VERSION 5.8 ;
BUSBITCHARS "[]" ;
DIVIDERCHAR "/" ;
UNITS
    DATABASE MICRONS 1000 ;
END UNITS

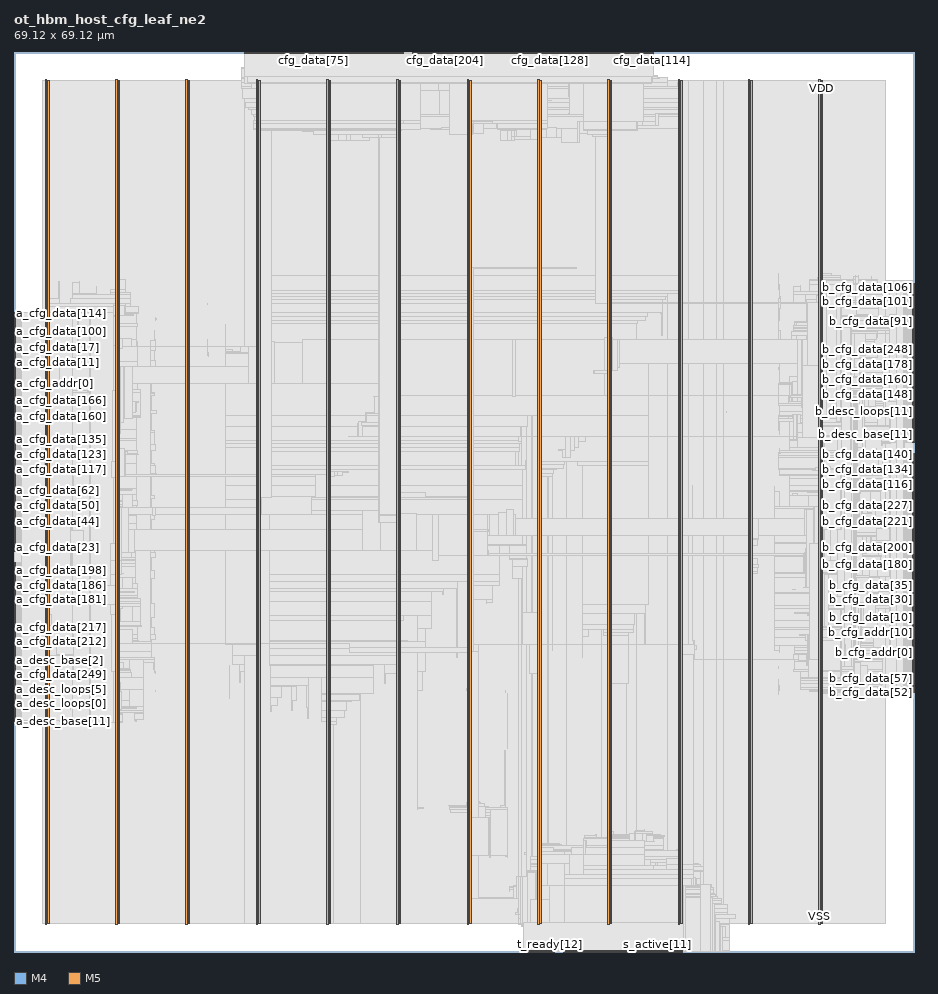
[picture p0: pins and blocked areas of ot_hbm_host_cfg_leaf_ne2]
MACRO ot_hbm_host_cfg_leaf_ne2
  FOREIGN ot_hbm_host_cfg_leaf_ne2 0 0 ;
  CLASS BLOCK ;
  SIZE 69.12 BY 69.12 ;
  PIN a_cfg_addr[0]
    DIRECTION OUTPUT ;
    USE SIGNAL ;
    PORT
      LAYER M4 ;
        RECT  0 43.056 0.084 43.08 ;
    END
  END a_cfg_addr[0]
  PIN a_cfg_addr[10]
    DIRECTION OUTPUT ;
    USE SIGNAL ;
    PORT
      LAYER M4 ;
        RECT  0 44.016 0.084 44.04 ;
    END
  END a_cfg_addr[10]
  PIN a_cfg_addr[11]
    DIRECTION OUTPUT ;
    USE SIGNAL ;
    PORT
      LAYER M4 ;
        RECT  0 44.112 0.084 44.136 ;
    END
  END a_cfg_addr[11]
  PIN a_cfg_addr[1]
    DIRECTION OUTPUT ;
    USE SIGNAL ;
    PORT
      LAYER M4 ;
        RECT  0 43.152 0.084 43.176 ;
    END
  END a_cfg_addr[1]
  PIN a_cfg_addr[2]
    DIRECTION OUTPUT ;
    USE SIGNAL ;
    PORT
      LAYER M4 ;
        RECT  0 43.248 0.084 43.272 ;
    END
  END a_cfg_addr[2]
  PIN a_cfg_addr[3]
    DIRECTION OUTPUT ;
    USE SIGNAL ;
    PORT
      LAYER M4 ;
        RECT  0 43.344 0.084 43.368 ;
    END
  END a_cfg_addr[3]
  PIN a_cfg_addr[4]
    DIRECTION OUTPUT ;
    USE SIGNAL ;
    PORT
      LAYER M4 ;
        RECT  0 43.44 0.084 43.464 ;
    END
  END a_cfg_addr[4]
  PIN a_cfg_addr[5]
    DIRECTION OUTPUT ;
    USE SIGNAL ;
    PORT
      LAYER M4 ;
        RECT  0 43.536 0.084 43.56 ;
    END
  END a_cfg_addr[5]
  PIN a_cfg_addr[6]
    DIRECTION OUTPUT ;
    USE SIGNAL ;
    PORT
      LAYER M4 ;
        RECT  0 43.632 0.084 43.656 ;
    END
  END a_cfg_addr[6]
  PIN a_cfg_addr[7]
    DIRECTION OUTPUT ;
    USE SIGNAL ;
    PORT
      LAYER M4 ;
        RECT  0 43.728 0.084 43.752 ;
    END
  END a_cfg_addr[7]
  PIN a_cfg_addr[8]
    DIRECTION OUTPUT ;
    USE SIGNAL ;
    PORT
      LAYER M4 ;
        RECT  0 43.824 0.084 43.848 ;
    END
  END a_cfg_addr[8]
  PIN a_cfg_addr[9]
    DIRECTION OUTPUT ;
    USE SIGNAL ;
    PORT
      LAYER M4 ;
        RECT  0 43.92 0.084 43.944 ;
    END
  END a_cfg_addr[9]
  PIN a_cfg_data[0]
    DIRECTION OUTPUT ;
    USE SIGNAL ;
    PORT
      LAYER M4 ;
        RECT  0 44.208 0.084 44.232 ;
    END
  END a_cfg_data[0]
  PIN a_cfg_data[100]
    DIRECTION OUTPUT ;
    USE SIGNAL ;
    PORT
      LAYER M4 ;
        RECT  0 47.664 0.084 47.688 ;
    END
  END a_cfg_data[100]
  PIN a_cfg_data[101]
    DIRECTION OUTPUT ;
    USE SIGNAL ;
    PORT
      LAYER M4 ;
        RECT  0 47.76 0.084 47.784 ;
    END
  END a_cfg_data[101]
  PIN a_cfg_data[102]
    DIRECTION OUTPUT ;
    USE SIGNAL ;
    PORT
      LAYER M4 ;
        RECT  0 47.856 0.084 47.88 ;
    END
  END a_cfg_data[102]
  PIN a_cfg_data[103]
    DIRECTION OUTPUT ;
    USE SIGNAL ;
    PORT
      LAYER M4 ;
        RECT  0 47.952 0.084 47.976 ;
    END
  END a_cfg_data[103]
  PIN a_cfg_data[104]
    DIRECTION OUTPUT ;
    USE SIGNAL ;
    PORT
      LAYER M4 ;
        RECT  0 48.048 0.084 48.072 ;
    END
  END a_cfg_data[104]
  PIN a_cfg_data[105]
    DIRECTION OUTPUT ;
    USE SIGNAL ;
    PORT
      LAYER M4 ;
        RECT  0 48.144 0.084 48.168 ;
    END
  END a_cfg_data[105]
  PIN a_cfg_data[106]
    DIRECTION OUTPUT ;
    USE SIGNAL ;
    PORT
      LAYER M4 ;
        RECT  0 48.24 0.084 48.264 ;
    END
  END a_cfg_data[106]
  PIN a_cfg_data[107]
    DIRECTION OUTPUT ;
    USE SIGNAL ;
    PORT
      LAYER M4 ;
        RECT  0 48.336 0.084 48.36 ;
    END
  END a_cfg_data[107]
  PIN a_cfg_data[108]
    DIRECTION OUTPUT ;
    USE SIGNAL ;
    PORT
      LAYER M4 ;
        RECT  0 48.432 0.084 48.456 ;
    END
  END a_cfg_data[108]
  PIN a_cfg_data[109]
    DIRECTION OUTPUT ;
    USE SIGNAL ;
    PORT
      LAYER M4 ;
        RECT  0 48.528 0.084 48.552 ;
    END
  END a_cfg_data[109]
  PIN a_cfg_data[10]
    DIRECTION OUTPUT ;
    USE SIGNAL ;
    PORT
      LAYER M4 ;
        RECT  0 45.168 0.084 45.192 ;
    END
  END a_cfg_data[10]
  PIN a_cfg_data[110]
    DIRECTION OUTPUT ;
    USE SIGNAL ;
    PORT
      LAYER M4 ;
        RECT  0 48.624 0.084 48.648 ;
    END
  END a_cfg_data[110]
  PIN a_cfg_data[111]
    DIRECTION OUTPUT ;
    USE SIGNAL ;
    PORT
      LAYER M4 ;
        RECT  0 48.72 0.084 48.744 ;
    END
  END a_cfg_data[111]
  PIN a_cfg_data[112]
    DIRECTION OUTPUT ;
    USE SIGNAL ;
    PORT
      LAYER M4 ;
        RECT  0 48.816 0.084 48.84 ;
    END
  END a_cfg_data[112]
  PIN a_cfg_data[113]
    DIRECTION OUTPUT ;
    USE SIGNAL ;
    PORT
      LAYER M4 ;
        RECT  0 48.912 0.084 48.936 ;
    END
  END a_cfg_data[113]
  PIN a_cfg_data[114]
    DIRECTION OUTPUT ;
    USE SIGNAL ;
    PORT
      LAYER M4 ;
        RECT  0 49.008 0.084 49.032 ;
    END
  END a_cfg_data[114]
  PIN a_cfg_data[115]
    DIRECTION OUTPUT ;
    USE SIGNAL ;
    PORT
      LAYER M4 ;
        RECT  0 49.104 0.084 49.128 ;
    END
  END a_cfg_data[115]
  PIN a_cfg_data[116]
    DIRECTION OUTPUT ;
    USE SIGNAL ;
    PORT
      LAYER M4 ;
        RECT  0 36.912 0.084 36.936 ;
    END
  END a_cfg_data[116]
  PIN a_cfg_data[117]
    DIRECTION OUTPUT ;
    USE SIGNAL ;
    PORT
      LAYER M4 ;
        RECT  0 37.008 0.084 37.032 ;
    END
  END a_cfg_data[117]
  PIN a_cfg_data[118]
    DIRECTION OUTPUT ;
    USE SIGNAL ;
    PORT
      LAYER M4 ;
        RECT  0 37.104 0.084 37.128 ;
    END
  END a_cfg_data[118]
  PIN a_cfg_data[119]
    DIRECTION OUTPUT ;
    USE SIGNAL ;
    PORT
      LAYER M4 ;
        RECT  0 37.2 0.084 37.224 ;
    END
  END a_cfg_data[119]
  PIN a_cfg_data[11]
    DIRECTION OUTPUT ;
    USE SIGNAL ;
    PORT
      LAYER M4 ;
        RECT  0 45.264 0.084 45.288 ;
    END
  END a_cfg_data[11]
  PIN a_cfg_data[120]
    DIRECTION OUTPUT ;
    USE SIGNAL ;
    PORT
      LAYER M4 ;
        RECT  0 37.296 0.084 37.32 ;
    END
  END a_cfg_data[120]
  PIN a_cfg_data[121]
    DIRECTION OUTPUT ;
    USE SIGNAL ;
    PORT
      LAYER M4 ;
        RECT  0 37.392 0.084 37.416 ;
    END
  END a_cfg_data[121]
  PIN a_cfg_data[122]
    DIRECTION OUTPUT ;
    USE SIGNAL ;
    PORT
      LAYER M4 ;
        RECT  0 37.488 0.084 37.512 ;
    END
  END a_cfg_data[122]
  PIN a_cfg_data[123]
    DIRECTION OUTPUT ;
    USE SIGNAL ;
    PORT
      LAYER M4 ;
        RECT  0 37.584 0.084 37.608 ;
    END
  END a_cfg_data[123]
  PIN a_cfg_data[124]
    DIRECTION OUTPUT ;
    USE SIGNAL ;
    PORT
      LAYER M4 ;
        RECT  0 37.68 0.084 37.704 ;
    END
  END a_cfg_data[124]
  PIN a_cfg_data[125]
    DIRECTION OUTPUT ;
    USE SIGNAL ;
    PORT
      LAYER M4 ;
        RECT  0 37.776 0.084 37.8 ;
    END
  END a_cfg_data[125]
  PIN a_cfg_data[126]
    DIRECTION OUTPUT ;
    USE SIGNAL ;
    PORT
      LAYER M4 ;
        RECT  0 37.872 0.084 37.896 ;
    END
  END a_cfg_data[126]
  PIN a_cfg_data[127]
    DIRECTION OUTPUT ;
    USE SIGNAL ;
    PORT
      LAYER M4 ;
        RECT  0 37.968 0.084 37.992 ;
    END
  END a_cfg_data[127]
  PIN a_cfg_data[128]
    DIRECTION OUTPUT ;
    USE SIGNAL ;
    PORT
      LAYER M4 ;
        RECT  0 38.064 0.084 38.088 ;
    END
  END a_cfg_data[128]
  PIN a_cfg_data[129]
    DIRECTION OUTPUT ;
    USE SIGNAL ;
    PORT
      LAYER M4 ;
        RECT  0 38.16 0.084 38.184 ;
    END
  END a_cfg_data[129]
  PIN a_cfg_data[12]
    DIRECTION OUTPUT ;
    USE SIGNAL ;
    PORT
      LAYER M4 ;
        RECT  0 45.36 0.084 45.384 ;
    END
  END a_cfg_data[12]
  PIN a_cfg_data[130]
    DIRECTION OUTPUT ;
    USE SIGNAL ;
    PORT
      LAYER M4 ;
        RECT  0 38.256 0.084 38.28 ;
    END
  END a_cfg_data[130]
  PIN a_cfg_data[131]
    DIRECTION OUTPUT ;
    USE SIGNAL ;
    PORT
      LAYER M4 ;
        RECT  0 38.352 0.084 38.376 ;
    END
  END a_cfg_data[131]
  PIN a_cfg_data[132]
    DIRECTION OUTPUT ;
    USE SIGNAL ;
    PORT
      LAYER M4 ;
        RECT  0 38.448 0.084 38.472 ;
    END
  END a_cfg_data[132]
  PIN a_cfg_data[133]
    DIRECTION OUTPUT ;
    USE SIGNAL ;
    PORT
      LAYER M4 ;
        RECT  0 38.544 0.084 38.568 ;
    END
  END a_cfg_data[133]
  PIN a_cfg_data[134]
    DIRECTION OUTPUT ;
    USE SIGNAL ;
    PORT
      LAYER M4 ;
        RECT  0 38.64 0.084 38.664 ;
    END
  END a_cfg_data[134]
  PIN a_cfg_data[135]
    DIRECTION OUTPUT ;
    USE SIGNAL ;
    PORT
      LAYER M4 ;
        RECT  0 38.736 0.084 38.76 ;
    END
  END a_cfg_data[135]
  PIN a_cfg_data[136]
    DIRECTION OUTPUT ;
    USE SIGNAL ;
    PORT
      LAYER M4 ;
        RECT  0 38.832 0.084 38.856 ;
    END
  END a_cfg_data[136]
  PIN a_cfg_data[137]
    DIRECTION OUTPUT ;
    USE SIGNAL ;
    PORT
      LAYER M4 ;
        RECT  0 38.928 0.084 38.952 ;
    END
  END a_cfg_data[137]
  PIN a_cfg_data[138]
    DIRECTION OUTPUT ;
    USE SIGNAL ;
    PORT
      LAYER M4 ;
        RECT  0 39.024 0.084 39.048 ;
    END
  END a_cfg_data[138]
  PIN a_cfg_data[139]
    DIRECTION OUTPUT ;
    USE SIGNAL ;
    PORT
      LAYER M4 ;
        RECT  0 39.12 0.084 39.144 ;
    END
  END a_cfg_data[139]
  PIN a_cfg_data[13]
    DIRECTION OUTPUT ;
    USE SIGNAL ;
    PORT
      LAYER M4 ;
        RECT  0 45.456 0.084 45.48 ;
    END
  END a_cfg_data[13]
  PIN a_cfg_data[140]
    DIRECTION OUTPUT ;
    USE SIGNAL ;
    PORT
      LAYER M4 ;
        RECT  0 39.216 0.084 39.24 ;
    END
  END a_cfg_data[140]
  PIN a_cfg_data[141]
    DIRECTION OUTPUT ;
    USE SIGNAL ;
    PORT
      LAYER M4 ;
        RECT  0 39.312 0.084 39.336 ;
    END
  END a_cfg_data[141]
  PIN a_cfg_data[142]
    DIRECTION OUTPUT ;
    USE SIGNAL ;
    PORT
      LAYER M4 ;
        RECT  0 39.408 0.084 39.432 ;
    END
  END a_cfg_data[142]
  PIN a_cfg_data[143]
    DIRECTION OUTPUT ;
    USE SIGNAL ;
    PORT
      LAYER M4 ;
        RECT  0 39.504 0.084 39.528 ;
    END
  END a_cfg_data[143]
  PIN a_cfg_data[144]
    DIRECTION OUTPUT ;
    USE SIGNAL ;
    PORT
      LAYER M4 ;
        RECT  0 39.6 0.084 39.624 ;
    END
  END a_cfg_data[144]
  PIN a_cfg_data[145]
    DIRECTION OUTPUT ;
    USE SIGNAL ;
    PORT
      LAYER M4 ;
        RECT  0 39.696 0.084 39.72 ;
    END
  END a_cfg_data[145]
  PIN a_cfg_data[146]
    DIRECTION OUTPUT ;
    USE SIGNAL ;
    PORT
      LAYER M4 ;
        RECT  0 39.792 0.084 39.816 ;
    END
  END a_cfg_data[146]
  PIN a_cfg_data[147]
    DIRECTION OUTPUT ;
    USE SIGNAL ;
    PORT
      LAYER M4 ;
        RECT  0 39.888 0.084 39.912 ;
    END
  END a_cfg_data[147]
  PIN a_cfg_data[148]
    DIRECTION OUTPUT ;
    USE SIGNAL ;
    PORT
      LAYER M4 ;
        RECT  0 39.984 0.084 40.008 ;
    END
  END a_cfg_data[148]
  PIN a_cfg_data[149]
    DIRECTION OUTPUT ;
    USE SIGNAL ;
    PORT
      LAYER M4 ;
        RECT  0 40.08 0.084 40.104 ;
    END
  END a_cfg_data[149]
  PIN a_cfg_data[14]
    DIRECTION OUTPUT ;
    USE SIGNAL ;
    PORT
      LAYER M4 ;
        RECT  0 45.552 0.084 45.576 ;
    END
  END a_cfg_data[14]
  PIN a_cfg_data[150]
    DIRECTION OUTPUT ;
    USE SIGNAL ;
    PORT
      LAYER M4 ;
        RECT  0 40.176 0.084 40.2 ;
    END
  END a_cfg_data[150]
  PIN a_cfg_data[151]
    DIRECTION OUTPUT ;
    USE SIGNAL ;
    PORT
      LAYER M4 ;
        RECT  0 40.272 0.084 40.296 ;
    END
  END a_cfg_data[151]
  PIN a_cfg_data[152]
    DIRECTION OUTPUT ;
    USE SIGNAL ;
    PORT
      LAYER M4 ;
        RECT  0 40.368 0.084 40.392 ;
    END
  END a_cfg_data[152]
  PIN a_cfg_data[153]
    DIRECTION OUTPUT ;
    USE SIGNAL ;
    PORT
      LAYER M4 ;
        RECT  0 40.464 0.084 40.488 ;
    END
  END a_cfg_data[153]
  PIN a_cfg_data[154]
    DIRECTION OUTPUT ;
    USE SIGNAL ;
    PORT
      LAYER M4 ;
        RECT  0 40.56 0.084 40.584 ;
    END
  END a_cfg_data[154]
  PIN a_cfg_data[155]
    DIRECTION OUTPUT ;
    USE SIGNAL ;
    PORT
      LAYER M4 ;
        RECT  0 40.656 0.084 40.68 ;
    END
  END a_cfg_data[155]
  PIN a_cfg_data[156]
    DIRECTION OUTPUT ;
    USE SIGNAL ;
    PORT
      LAYER M4 ;
        RECT  0 40.752 0.084 40.776 ;
    END
  END a_cfg_data[156]
  PIN a_cfg_data[157]
    DIRECTION OUTPUT ;
    USE SIGNAL ;
    PORT
      LAYER M4 ;
        RECT  0 40.848 0.084 40.872 ;
    END
  END a_cfg_data[157]
  PIN a_cfg_data[158]
    DIRECTION OUTPUT ;
    USE SIGNAL ;
    PORT
      LAYER M4 ;
        RECT  0 40.944 0.084 40.968 ;
    END
  END a_cfg_data[158]
  PIN a_cfg_data[159]
    DIRECTION OUTPUT ;
    USE SIGNAL ;
    PORT
      LAYER M4 ;
        RECT  0 41.04 0.084 41.064 ;
    END
  END a_cfg_data[159]
  PIN a_cfg_data[15]
    DIRECTION OUTPUT ;
    USE SIGNAL ;
    PORT
      LAYER M4 ;
        RECT  0 45.648 0.084 45.672 ;
    END
  END a_cfg_data[15]
  PIN a_cfg_data[160]
    DIRECTION OUTPUT ;
    USE SIGNAL ;
    PORT
      LAYER M4 ;
        RECT  0 41.136 0.084 41.16 ;
    END
  END a_cfg_data[160]
  PIN a_cfg_data[161]
    DIRECTION OUTPUT ;
    USE SIGNAL ;
    PORT
      LAYER M4 ;
        RECT  0 41.232 0.084 41.256 ;
    END
  END a_cfg_data[161]
  PIN a_cfg_data[162]
    DIRECTION OUTPUT ;
    USE SIGNAL ;
    PORT
      LAYER M4 ;
        RECT  0 41.328 0.084 41.352 ;
    END
  END a_cfg_data[162]
  PIN a_cfg_data[163]
    DIRECTION OUTPUT ;
    USE SIGNAL ;
    PORT
      LAYER M4 ;
        RECT  0 41.424 0.084 41.448 ;
    END
  END a_cfg_data[163]
  PIN a_cfg_data[164]
    DIRECTION OUTPUT ;
    USE SIGNAL ;
    PORT
      LAYER M4 ;
        RECT  0 41.52 0.084 41.544 ;
    END
  END a_cfg_data[164]
  PIN a_cfg_data[165]
    DIRECTION OUTPUT ;
    USE SIGNAL ;
    PORT
      LAYER M4 ;
        RECT  0 41.616 0.084 41.64 ;
    END
  END a_cfg_data[165]
  PIN a_cfg_data[166]
    DIRECTION OUTPUT ;
    USE SIGNAL ;
    PORT
      LAYER M4 ;
        RECT  0 41.712 0.084 41.736 ;
    END
  END a_cfg_data[166]
  PIN a_cfg_data[167]
    DIRECTION OUTPUT ;
    USE SIGNAL ;
    PORT
      LAYER M4 ;
        RECT  0 41.808 0.084 41.832 ;
    END
  END a_cfg_data[167]
  PIN a_cfg_data[168]
    DIRECTION OUTPUT ;
    USE SIGNAL ;
    PORT
      LAYER M4 ;
        RECT  0 41.904 0.084 41.928 ;
    END
  END a_cfg_data[168]
  PIN a_cfg_data[169]
    DIRECTION OUTPUT ;
    USE SIGNAL ;
    PORT
      LAYER M4 ;
        RECT  0 42 0.084 42.024 ;
    END
  END a_cfg_data[169]
  PIN a_cfg_data[16]
    DIRECTION OUTPUT ;
    USE SIGNAL ;
    PORT
      LAYER M4 ;
        RECT  0 45.744 0.084 45.768 ;
    END
  END a_cfg_data[16]
  PIN a_cfg_data[170]
    DIRECTION OUTPUT ;
    USE SIGNAL ;
    PORT
      LAYER M4 ;
        RECT  0 42.096 0.084 42.12 ;
    END
  END a_cfg_data[170]
  PIN a_cfg_data[171]
    DIRECTION OUTPUT ;
    USE SIGNAL ;
    PORT
      LAYER M4 ;
        RECT  0 42.192 0.084 42.216 ;
    END
  END a_cfg_data[171]
  PIN a_cfg_data[172]
    DIRECTION OUTPUT ;
    USE SIGNAL ;
    PORT
      LAYER M4 ;
        RECT  0 42.288 0.084 42.312 ;
    END
  END a_cfg_data[172]
  PIN a_cfg_data[173]
    DIRECTION OUTPUT ;
    USE SIGNAL ;
    PORT
      LAYER M4 ;
        RECT  0 42.384 0.084 42.408 ;
    END
  END a_cfg_data[173]
  PIN a_cfg_data[174]
    DIRECTION OUTPUT ;
    USE SIGNAL ;
    PORT
      LAYER M4 ;
        RECT  0 42.48 0.084 42.504 ;
    END
  END a_cfg_data[174]
  PIN a_cfg_data[175]
    DIRECTION OUTPUT ;
    USE SIGNAL ;
    PORT
      LAYER M4 ;
        RECT  0 42.576 0.084 42.6 ;
    END
  END a_cfg_data[175]
  PIN a_cfg_data[176]
    DIRECTION OUTPUT ;
    USE SIGNAL ;
    PORT
      LAYER M4 ;
        RECT  0 42.672 0.084 42.696 ;
    END
  END a_cfg_data[176]
  PIN a_cfg_data[177]
    DIRECTION OUTPUT ;
    USE SIGNAL ;
    PORT
      LAYER M4 ;
        RECT  0 42.768 0.084 42.792 ;
    END
  END a_cfg_data[177]
  PIN a_cfg_data[178]
    DIRECTION OUTPUT ;
    USE SIGNAL ;
    PORT
      LAYER M4 ;
        RECT  0 42.864 0.084 42.888 ;
    END
  END a_cfg_data[178]
  PIN a_cfg_data[179]
    DIRECTION OUTPUT ;
    USE SIGNAL ;
    PORT
      LAYER M4 ;
        RECT  0 42.96 0.084 42.984 ;
    END
  END a_cfg_data[179]
  PIN a_cfg_data[17]
    DIRECTION OUTPUT ;
    USE SIGNAL ;
    PORT
      LAYER M4 ;
        RECT  0 45.84 0.084 45.864 ;
    END
  END a_cfg_data[17]
  PIN a_cfg_data[180]
    DIRECTION OUTPUT ;
    USE SIGNAL ;
    PORT
      LAYER M4 ;
        RECT  0 26.928 0.084 26.952 ;
    END
  END a_cfg_data[180]
  PIN a_cfg_data[181]
    DIRECTION OUTPUT ;
    USE SIGNAL ;
    PORT
      LAYER M4 ;
        RECT  0 27.024 0.084 27.048 ;
    END
  END a_cfg_data[181]
  PIN a_cfg_data[182]
    DIRECTION OUTPUT ;
    USE SIGNAL ;
    PORT
      LAYER M4 ;
        RECT  0 27.12 0.084 27.144 ;
    END
  END a_cfg_data[182]
  PIN a_cfg_data[183]
    DIRECTION OUTPUT ;
    USE SIGNAL ;
    PORT
      LAYER M4 ;
        RECT  0 27.216 0.084 27.24 ;
    END
  END a_cfg_data[183]
  PIN a_cfg_data[184]
    DIRECTION OUTPUT ;
    USE SIGNAL ;
    PORT
      LAYER M4 ;
        RECT  0 27.312 0.084 27.336 ;
    END
  END a_cfg_data[184]
  PIN a_cfg_data[185]
    DIRECTION OUTPUT ;
    USE SIGNAL ;
    PORT
      LAYER M4 ;
        RECT  0 27.408 0.084 27.432 ;
    END
  END a_cfg_data[185]
  PIN a_cfg_data[186]
    DIRECTION OUTPUT ;
    USE SIGNAL ;
    PORT
      LAYER M4 ;
        RECT  0 27.504 0.084 27.528 ;
    END
  END a_cfg_data[186]
  PIN a_cfg_data[187]
    DIRECTION OUTPUT ;
    USE SIGNAL ;
    PORT
      LAYER M4 ;
        RECT  0 27.6 0.084 27.624 ;
    END
  END a_cfg_data[187]
  PIN a_cfg_data[188]
    DIRECTION OUTPUT ;
    USE SIGNAL ;
    PORT
      LAYER M4 ;
        RECT  0 27.696 0.084 27.72 ;
    END
  END a_cfg_data[188]
  PIN a_cfg_data[189]
    DIRECTION OUTPUT ;
    USE SIGNAL ;
    PORT
      LAYER M4 ;
        RECT  0 27.792 0.084 27.816 ;
    END
  END a_cfg_data[189]
  PIN a_cfg_data[18]
    DIRECTION OUTPUT ;
    USE SIGNAL ;
    PORT
      LAYER M4 ;
        RECT  0 45.936 0.084 45.96 ;
    END
  END a_cfg_data[18]
  PIN a_cfg_data[190]
    DIRECTION OUTPUT ;
    USE SIGNAL ;
    PORT
      LAYER M4 ;
        RECT  0 27.888 0.084 27.912 ;
    END
  END a_cfg_data[190]
  PIN a_cfg_data[191]
    DIRECTION OUTPUT ;
    USE SIGNAL ;
    PORT
      LAYER M4 ;
        RECT  0 27.984 0.084 28.008 ;
    END
  END a_cfg_data[191]
  PIN a_cfg_data[192]
    DIRECTION OUTPUT ;
    USE SIGNAL ;
    PORT
      LAYER M4 ;
        RECT  0 28.08 0.084 28.104 ;
    END
  END a_cfg_data[192]
  PIN a_cfg_data[193]
    DIRECTION OUTPUT ;
    USE SIGNAL ;
    PORT
      LAYER M4 ;
        RECT  0 28.176 0.084 28.2 ;
    END
  END a_cfg_data[193]
  PIN a_cfg_data[194]
    DIRECTION OUTPUT ;
    USE SIGNAL ;
    PORT
      LAYER M4 ;
        RECT  0 28.272 0.084 28.296 ;
    END
  END a_cfg_data[194]
  PIN a_cfg_data[195]
    DIRECTION OUTPUT ;
    USE SIGNAL ;
    PORT
      LAYER M4 ;
        RECT  0 28.368 0.084 28.392 ;
    END
  END a_cfg_data[195]
  PIN a_cfg_data[196]
    DIRECTION OUTPUT ;
    USE SIGNAL ;
    PORT
      LAYER M4 ;
        RECT  0 28.464 0.084 28.488 ;
    END
  END a_cfg_data[196]
  PIN a_cfg_data[197]
    DIRECTION OUTPUT ;
    USE SIGNAL ;
    PORT
      LAYER M4 ;
        RECT  0 28.56 0.084 28.584 ;
    END
  END a_cfg_data[197]
  PIN a_cfg_data[198]
    DIRECTION OUTPUT ;
    USE SIGNAL ;
    PORT
      LAYER M4 ;
        RECT  0 28.656 0.084 28.68 ;
    END
  END a_cfg_data[198]
  PIN a_cfg_data[199]
    DIRECTION OUTPUT ;
    USE SIGNAL ;
    PORT
      LAYER M4 ;
        RECT  0 28.752 0.084 28.776 ;
    END
  END a_cfg_data[199]
  PIN a_cfg_data[19]
    DIRECTION OUTPUT ;
    USE SIGNAL ;
    PORT
      LAYER M4 ;
        RECT  0 46.032 0.084 46.056 ;
    END
  END a_cfg_data[19]
  PIN a_cfg_data[1]
    DIRECTION OUTPUT ;
    USE SIGNAL ;
    PORT
      LAYER M4 ;
        RECT  0 44.304 0.084 44.328 ;
    END
  END a_cfg_data[1]
  PIN a_cfg_data[200]
    DIRECTION OUTPUT ;
    USE SIGNAL ;
    PORT
      LAYER M4 ;
        RECT  0 28.848 0.084 28.872 ;
    END
  END a_cfg_data[200]
  PIN a_cfg_data[201]
    DIRECTION OUTPUT ;
    USE SIGNAL ;
    PORT
      LAYER M4 ;
        RECT  0 28.944 0.084 28.968 ;
    END
  END a_cfg_data[201]
  PIN a_cfg_data[202]
    DIRECTION OUTPUT ;
    USE SIGNAL ;
    PORT
      LAYER M4 ;
        RECT  0 29.04 0.084 29.064 ;
    END
  END a_cfg_data[202]
  PIN a_cfg_data[203]
    DIRECTION OUTPUT ;
    USE SIGNAL ;
    PORT
      LAYER M4 ;
        RECT  0 29.136 0.084 29.16 ;
    END
  END a_cfg_data[203]
  PIN a_cfg_data[204]
    DIRECTION OUTPUT ;
    USE SIGNAL ;
    PORT
      LAYER M4 ;
        RECT  0 29.232 0.084 29.256 ;
    END
  END a_cfg_data[204]
  PIN a_cfg_data[205]
    DIRECTION OUTPUT ;
    USE SIGNAL ;
    PORT
      LAYER M4 ;
        RECT  0 29.328 0.084 29.352 ;
    END
  END a_cfg_data[205]
  PIN a_cfg_data[206]
    DIRECTION OUTPUT ;
    USE SIGNAL ;
    PORT
      LAYER M4 ;
        RECT  0 29.424 0.084 29.448 ;
    END
  END a_cfg_data[206]
  PIN a_cfg_data[207]
    DIRECTION OUTPUT ;
    USE SIGNAL ;
    PORT
      LAYER M4 ;
        RECT  0 29.52 0.084 29.544 ;
    END
  END a_cfg_data[207]
  PIN a_cfg_data[208]
    DIRECTION OUTPUT ;
    USE SIGNAL ;
    PORT
      LAYER M4 ;
        RECT  0 29.616 0.084 29.64 ;
    END
  END a_cfg_data[208]
  PIN a_cfg_data[209]
    DIRECTION OUTPUT ;
    USE SIGNAL ;
    PORT
      LAYER M4 ;
        RECT  0 29.712 0.084 29.736 ;
    END
  END a_cfg_data[209]
  PIN a_cfg_data[20]
    DIRECTION OUTPUT ;
    USE SIGNAL ;
    PORT
      LAYER M4 ;
        RECT  0 30.768 0.084 30.792 ;
    END
  END a_cfg_data[20]
  PIN a_cfg_data[210]
    DIRECTION OUTPUT ;
    USE SIGNAL ;
    PORT
      LAYER M4 ;
        RECT  0 29.808 0.084 29.832 ;
    END
  END a_cfg_data[210]
  PIN a_cfg_data[211]
    DIRECTION OUTPUT ;
    USE SIGNAL ;
    PORT
      LAYER M4 ;
        RECT  0 29.904 0.084 29.928 ;
    END
  END a_cfg_data[211]
  PIN a_cfg_data[212]
    DIRECTION OUTPUT ;
    USE SIGNAL ;
    PORT
      LAYER M4 ;
        RECT  0 23.856 0.084 23.88 ;
    END
  END a_cfg_data[212]
  PIN a_cfg_data[213]
    DIRECTION OUTPUT ;
    USE SIGNAL ;
    PORT
      LAYER M4 ;
        RECT  0 23.952 0.084 23.976 ;
    END
  END a_cfg_data[213]
  PIN a_cfg_data[214]
    DIRECTION OUTPUT ;
    USE SIGNAL ;
    PORT
      LAYER M4 ;
        RECT  0 24.048 0.084 24.072 ;
    END
  END a_cfg_data[214]
  PIN a_cfg_data[215]
    DIRECTION OUTPUT ;
    USE SIGNAL ;
    PORT
      LAYER M4 ;
        RECT  0 24.144 0.084 24.168 ;
    END
  END a_cfg_data[215]
  PIN a_cfg_data[216]
    DIRECTION OUTPUT ;
    USE SIGNAL ;
    PORT
      LAYER M4 ;
        RECT  0 24.24 0.084 24.264 ;
    END
  END a_cfg_data[216]
  PIN a_cfg_data[217]
    DIRECTION OUTPUT ;
    USE SIGNAL ;
    PORT
      LAYER M4 ;
        RECT  0 24.336 0.084 24.36 ;
    END
  END a_cfg_data[217]
  PIN a_cfg_data[218]
    DIRECTION OUTPUT ;
    USE SIGNAL ;
    PORT
      LAYER M4 ;
        RECT  0 24.432 0.084 24.456 ;
    END
  END a_cfg_data[218]
  PIN a_cfg_data[219]
    DIRECTION OUTPUT ;
    USE SIGNAL ;
    PORT
      LAYER M4 ;
        RECT  0 24.528 0.084 24.552 ;
    END
  END a_cfg_data[219]
  PIN a_cfg_data[21]
    DIRECTION OUTPUT ;
    USE SIGNAL ;
    PORT
      LAYER M4 ;
        RECT  0 30.864 0.084 30.888 ;
    END
  END a_cfg_data[21]
  PIN a_cfg_data[220]
    DIRECTION OUTPUT ;
    USE SIGNAL ;
    PORT
      LAYER M4 ;
        RECT  0 24.624 0.084 24.648 ;
    END
  END a_cfg_data[220]
  PIN a_cfg_data[221]
    DIRECTION OUTPUT ;
    USE SIGNAL ;
    PORT
      LAYER M4 ;
        RECT  0 24.72 0.084 24.744 ;
    END
  END a_cfg_data[221]
  PIN a_cfg_data[222]
    DIRECTION OUTPUT ;
    USE SIGNAL ;
    PORT
      LAYER M4 ;
        RECT  0 24.816 0.084 24.84 ;
    END
  END a_cfg_data[222]
  PIN a_cfg_data[223]
    DIRECTION OUTPUT ;
    USE SIGNAL ;
    PORT
      LAYER M4 ;
        RECT  0 24.912 0.084 24.936 ;
    END
  END a_cfg_data[223]
  PIN a_cfg_data[224]
    DIRECTION OUTPUT ;
    USE SIGNAL ;
    PORT
      LAYER M4 ;
        RECT  0 25.008 0.084 25.032 ;
    END
  END a_cfg_data[224]
  PIN a_cfg_data[225]
    DIRECTION OUTPUT ;
    USE SIGNAL ;
    PORT
      LAYER M4 ;
        RECT  0 25.104 0.084 25.128 ;
    END
  END a_cfg_data[225]
  PIN a_cfg_data[226]
    DIRECTION OUTPUT ;
    USE SIGNAL ;
    PORT
      LAYER M4 ;
        RECT  0 25.2 0.084 25.224 ;
    END
  END a_cfg_data[226]
  PIN a_cfg_data[227]
    DIRECTION OUTPUT ;
    USE SIGNAL ;
    PORT
      LAYER M4 ;
        RECT  0 25.296 0.084 25.32 ;
    END
  END a_cfg_data[227]
  PIN a_cfg_data[228]
    DIRECTION OUTPUT ;
    USE SIGNAL ;
    PORT
      LAYER M4 ;
        RECT  0 25.392 0.084 25.416 ;
    END
  END a_cfg_data[228]
  PIN a_cfg_data[229]
    DIRECTION OUTPUT ;
    USE SIGNAL ;
    PORT
      LAYER M4 ;
        RECT  0 25.488 0.084 25.512 ;
    END
  END a_cfg_data[229]
  PIN a_cfg_data[22]
    DIRECTION OUTPUT ;
    USE SIGNAL ;
    PORT
      LAYER M4 ;
        RECT  0 30.96 0.084 30.984 ;
    END
  END a_cfg_data[22]
  PIN a_cfg_data[230]
    DIRECTION OUTPUT ;
    USE SIGNAL ;
    PORT
      LAYER M4 ;
        RECT  0 25.584 0.084 25.608 ;
    END
  END a_cfg_data[230]
  PIN a_cfg_data[231]
    DIRECTION OUTPUT ;
    USE SIGNAL ;
    PORT
      LAYER M4 ;
        RECT  0 25.68 0.084 25.704 ;
    END
  END a_cfg_data[231]
  PIN a_cfg_data[232]
    DIRECTION OUTPUT ;
    USE SIGNAL ;
    PORT
      LAYER M4 ;
        RECT  0 25.776 0.084 25.8 ;
    END
  END a_cfg_data[232]
  PIN a_cfg_data[233]
    DIRECTION OUTPUT ;
    USE SIGNAL ;
    PORT
      LAYER M4 ;
        RECT  0 25.872 0.084 25.896 ;
    END
  END a_cfg_data[233]
  PIN a_cfg_data[234]
    DIRECTION OUTPUT ;
    USE SIGNAL ;
    PORT
      LAYER M4 ;
        RECT  0 25.968 0.084 25.992 ;
    END
  END a_cfg_data[234]
  PIN a_cfg_data[235]
    DIRECTION OUTPUT ;
    USE SIGNAL ;
    PORT
      LAYER M4 ;
        RECT  0 26.064 0.084 26.088 ;
    END
  END a_cfg_data[235]
  PIN a_cfg_data[236]
    DIRECTION OUTPUT ;
    USE SIGNAL ;
    PORT
      LAYER M4 ;
        RECT  0 26.16 0.084 26.184 ;
    END
  END a_cfg_data[236]
  PIN a_cfg_data[237]
    DIRECTION OUTPUT ;
    USE SIGNAL ;
    PORT
      LAYER M4 ;
        RECT  0 26.256 0.084 26.28 ;
    END
  END a_cfg_data[237]
  PIN a_cfg_data[238]
    DIRECTION OUTPUT ;
    USE SIGNAL ;
    PORT
      LAYER M4 ;
        RECT  0 26.352 0.084 26.376 ;
    END
  END a_cfg_data[238]
  PIN a_cfg_data[239]
    DIRECTION OUTPUT ;
    USE SIGNAL ;
    PORT
      LAYER M4 ;
        RECT  0 26.448 0.084 26.472 ;
    END
  END a_cfg_data[239]
  PIN a_cfg_data[23]
    DIRECTION OUTPUT ;
    USE SIGNAL ;
    PORT
      LAYER M4 ;
        RECT  0 31.056 0.084 31.08 ;
    END
  END a_cfg_data[23]
  PIN a_cfg_data[240]
    DIRECTION OUTPUT ;
    USE SIGNAL ;
    PORT
      LAYER M4 ;
        RECT  0 26.544 0.084 26.568 ;
    END
  END a_cfg_data[240]
  PIN a_cfg_data[241]
    DIRECTION OUTPUT ;
    USE SIGNAL ;
    PORT
      LAYER M4 ;
        RECT  0 26.64 0.084 26.664 ;
    END
  END a_cfg_data[241]
  PIN a_cfg_data[242]
    DIRECTION OUTPUT ;
    USE SIGNAL ;
    PORT
      LAYER M4 ;
        RECT  0 26.736 0.084 26.76 ;
    END
  END a_cfg_data[242]
  PIN a_cfg_data[243]
    DIRECTION OUTPUT ;
    USE SIGNAL ;
    PORT
      LAYER M4 ;
        RECT  0 26.832 0.084 26.856 ;
    END
  END a_cfg_data[243]
  PIN a_cfg_data[244]
    DIRECTION OUTPUT ;
    USE SIGNAL ;
    PORT
      LAYER M4 ;
        RECT  0 20.784 0.084 20.808 ;
    END
  END a_cfg_data[244]
  PIN a_cfg_data[245]
    DIRECTION OUTPUT ;
    USE SIGNAL ;
    PORT
      LAYER M4 ;
        RECT  0 20.88 0.084 20.904 ;
    END
  END a_cfg_data[245]
  PIN a_cfg_data[246]
    DIRECTION OUTPUT ;
    USE SIGNAL ;
    PORT
      LAYER M4 ;
        RECT  0 20.976 0.084 21 ;
    END
  END a_cfg_data[246]
  PIN a_cfg_data[247]
    DIRECTION OUTPUT ;
    USE SIGNAL ;
    PORT
      LAYER M4 ;
        RECT  0 21.072 0.084 21.096 ;
    END
  END a_cfg_data[247]
  PIN a_cfg_data[248]
    DIRECTION OUTPUT ;
    USE SIGNAL ;
    PORT
      LAYER M4 ;
        RECT  0 21.168 0.084 21.192 ;
    END
  END a_cfg_data[248]
  PIN a_cfg_data[249]
    DIRECTION OUTPUT ;
    USE SIGNAL ;
    PORT
      LAYER M4 ;
        RECT  0 21.264 0.084 21.288 ;
    END
  END a_cfg_data[249]
  PIN a_cfg_data[24]
    DIRECTION OUTPUT ;
    USE SIGNAL ;
    PORT
      LAYER M4 ;
        RECT  0 31.152 0.084 31.176 ;
    END
  END a_cfg_data[24]
  PIN a_cfg_data[250]
    DIRECTION OUTPUT ;
    USE SIGNAL ;
    PORT
      LAYER M4 ;
        RECT  0 21.36 0.084 21.384 ;
    END
  END a_cfg_data[250]
  PIN a_cfg_data[251]
    DIRECTION OUTPUT ;
    USE SIGNAL ;
    PORT
      LAYER M4 ;
        RECT  0 21.456 0.084 21.48 ;
    END
  END a_cfg_data[251]
  PIN a_cfg_data[252]
    DIRECTION OUTPUT ;
    USE SIGNAL ;
    PORT
      LAYER M4 ;
        RECT  0 21.552 0.084 21.576 ;
    END
  END a_cfg_data[252]
  PIN a_cfg_data[253]
    DIRECTION OUTPUT ;
    USE SIGNAL ;
    PORT
      LAYER M4 ;
        RECT  0 21.648 0.084 21.672 ;
    END
  END a_cfg_data[253]
  PIN a_cfg_data[254]
    DIRECTION OUTPUT ;
    USE SIGNAL ;
    PORT
      LAYER M4 ;
        RECT  0 21.744 0.084 21.768 ;
    END
  END a_cfg_data[254]
  PIN a_cfg_data[255]
    DIRECTION OUTPUT ;
    USE SIGNAL ;
    PORT
      LAYER M4 ;
        RECT  0 21.84 0.084 21.864 ;
    END
  END a_cfg_data[255]
  PIN a_cfg_data[25]
    DIRECTION OUTPUT ;
    USE SIGNAL ;
    PORT
      LAYER M4 ;
        RECT  0 31.248 0.084 31.272 ;
    END
  END a_cfg_data[25]
  PIN a_cfg_data[26]
    DIRECTION OUTPUT ;
    USE SIGNAL ;
    PORT
      LAYER M4 ;
        RECT  0 31.344 0.084 31.368 ;
    END
  END a_cfg_data[26]
  PIN a_cfg_data[27]
    DIRECTION OUTPUT ;
    USE SIGNAL ;
    PORT
      LAYER M4 ;
        RECT  0 31.44 0.084 31.464 ;
    END
  END a_cfg_data[27]
  PIN a_cfg_data[28]
    DIRECTION OUTPUT ;
    USE SIGNAL ;
    PORT
      LAYER M4 ;
        RECT  0 31.536 0.084 31.56 ;
    END
  END a_cfg_data[28]
  PIN a_cfg_data[29]
    DIRECTION OUTPUT ;
    USE SIGNAL ;
    PORT
      LAYER M4 ;
        RECT  0 31.632 0.084 31.656 ;
    END
  END a_cfg_data[29]
  PIN a_cfg_data[2]
    DIRECTION OUTPUT ;
    USE SIGNAL ;
    PORT
      LAYER M4 ;
        RECT  0 44.4 0.084 44.424 ;
    END
  END a_cfg_data[2]
  PIN a_cfg_data[30]
    DIRECTION OUTPUT ;
    USE SIGNAL ;
    PORT
      LAYER M4 ;
        RECT  0 31.728 0.084 31.752 ;
    END
  END a_cfg_data[30]
  PIN a_cfg_data[31]
    DIRECTION OUTPUT ;
    USE SIGNAL ;
    PORT
      LAYER M4 ;
        RECT  0 31.824 0.084 31.848 ;
    END
  END a_cfg_data[31]
  PIN a_cfg_data[32]
    DIRECTION OUTPUT ;
    USE SIGNAL ;
    PORT
      LAYER M4 ;
        RECT  0 31.92 0.084 31.944 ;
    END
  END a_cfg_data[32]
  PIN a_cfg_data[33]
    DIRECTION OUTPUT ;
    USE SIGNAL ;
    PORT
      LAYER M4 ;
        RECT  0 32.016 0.084 32.04 ;
    END
  END a_cfg_data[33]
  PIN a_cfg_data[34]
    DIRECTION OUTPUT ;
    USE SIGNAL ;
    PORT
      LAYER M4 ;
        RECT  0 32.112 0.084 32.136 ;
    END
  END a_cfg_data[34]
  PIN a_cfg_data[35]
    DIRECTION OUTPUT ;
    USE SIGNAL ;
    PORT
      LAYER M4 ;
        RECT  0 32.208 0.084 32.232 ;
    END
  END a_cfg_data[35]
  PIN a_cfg_data[36]
    DIRECTION OUTPUT ;
    USE SIGNAL ;
    PORT
      LAYER M4 ;
        RECT  0 32.304 0.084 32.328 ;
    END
  END a_cfg_data[36]
  PIN a_cfg_data[37]
    DIRECTION OUTPUT ;
    USE SIGNAL ;
    PORT
      LAYER M4 ;
        RECT  0 32.4 0.084 32.424 ;
    END
  END a_cfg_data[37]
  PIN a_cfg_data[38]
    DIRECTION OUTPUT ;
    USE SIGNAL ;
    PORT
      LAYER M4 ;
        RECT  0 32.496 0.084 32.52 ;
    END
  END a_cfg_data[38]
  PIN a_cfg_data[39]
    DIRECTION OUTPUT ;
    USE SIGNAL ;
    PORT
      LAYER M4 ;
        RECT  0 32.592 0.084 32.616 ;
    END
  END a_cfg_data[39]
  PIN a_cfg_data[3]
    DIRECTION OUTPUT ;
    USE SIGNAL ;
    PORT
      LAYER M4 ;
        RECT  0 44.496 0.084 44.52 ;
    END
  END a_cfg_data[3]
  PIN a_cfg_data[40]
    DIRECTION OUTPUT ;
    USE SIGNAL ;
    PORT
      LAYER M4 ;
        RECT  0 32.688 0.084 32.712 ;
    END
  END a_cfg_data[40]
  PIN a_cfg_data[41]
    DIRECTION OUTPUT ;
    USE SIGNAL ;
    PORT
      LAYER M4 ;
        RECT  0 32.784 0.084 32.808 ;
    END
  END a_cfg_data[41]
  PIN a_cfg_data[42]
    DIRECTION OUTPUT ;
    USE SIGNAL ;
    PORT
      LAYER M4 ;
        RECT  0 32.88 0.084 32.904 ;
    END
  END a_cfg_data[42]
  PIN a_cfg_data[43]
    DIRECTION OUTPUT ;
    USE SIGNAL ;
    PORT
      LAYER M4 ;
        RECT  0 32.976 0.084 33 ;
    END
  END a_cfg_data[43]
  PIN a_cfg_data[44]
    DIRECTION OUTPUT ;
    USE SIGNAL ;
    PORT
      LAYER M4 ;
        RECT  0 33.072 0.084 33.096 ;
    END
  END a_cfg_data[44]
  PIN a_cfg_data[45]
    DIRECTION OUTPUT ;
    USE SIGNAL ;
    PORT
      LAYER M4 ;
        RECT  0 33.168 0.084 33.192 ;
    END
  END a_cfg_data[45]
  PIN a_cfg_data[46]
    DIRECTION OUTPUT ;
    USE SIGNAL ;
    PORT
      LAYER M4 ;
        RECT  0 33.264 0.084 33.288 ;
    END
  END a_cfg_data[46]
  PIN a_cfg_data[47]
    DIRECTION OUTPUT ;
    USE SIGNAL ;
    PORT
      LAYER M4 ;
        RECT  0 33.36 0.084 33.384 ;
    END
  END a_cfg_data[47]
  PIN a_cfg_data[48]
    DIRECTION OUTPUT ;
    USE SIGNAL ;
    PORT
      LAYER M4 ;
        RECT  0 33.456 0.084 33.48 ;
    END
  END a_cfg_data[48]
  PIN a_cfg_data[49]
    DIRECTION OUTPUT ;
    USE SIGNAL ;
    PORT
      LAYER M4 ;
        RECT  0 33.552 0.084 33.576 ;
    END
  END a_cfg_data[49]
  PIN a_cfg_data[4]
    DIRECTION OUTPUT ;
    USE SIGNAL ;
    PORT
      LAYER M4 ;
        RECT  0 44.592 0.084 44.616 ;
    END
  END a_cfg_data[4]
  PIN a_cfg_data[50]
    DIRECTION OUTPUT ;
    USE SIGNAL ;
    PORT
      LAYER M4 ;
        RECT  0 33.648 0.084 33.672 ;
    END
  END a_cfg_data[50]
  PIN a_cfg_data[51]
    DIRECTION OUTPUT ;
    USE SIGNAL ;
    PORT
      LAYER M4 ;
        RECT  0 33.744 0.084 33.768 ;
    END
  END a_cfg_data[51]
  PIN a_cfg_data[52]
    DIRECTION OUTPUT ;
    USE SIGNAL ;
    PORT
      LAYER M4 ;
        RECT  0 33.84 0.084 33.864 ;
    END
  END a_cfg_data[52]
  PIN a_cfg_data[53]
    DIRECTION OUTPUT ;
    USE SIGNAL ;
    PORT
      LAYER M4 ;
        RECT  0 33.936 0.084 33.96 ;
    END
  END a_cfg_data[53]
  PIN a_cfg_data[54]
    DIRECTION OUTPUT ;
    USE SIGNAL ;
    PORT
      LAYER M4 ;
        RECT  0 34.032 0.084 34.056 ;
    END
  END a_cfg_data[54]
  PIN a_cfg_data[55]
    DIRECTION OUTPUT ;
    USE SIGNAL ;
    PORT
      LAYER M4 ;
        RECT  0 34.128 0.084 34.152 ;
    END
  END a_cfg_data[55]
  PIN a_cfg_data[56]
    DIRECTION OUTPUT ;
    USE SIGNAL ;
    PORT
      LAYER M4 ;
        RECT  0 34.224 0.084 34.248 ;
    END
  END a_cfg_data[56]
  PIN a_cfg_data[57]
    DIRECTION OUTPUT ;
    USE SIGNAL ;
    PORT
      LAYER M4 ;
        RECT  0 34.32 0.084 34.344 ;
    END
  END a_cfg_data[57]
  PIN a_cfg_data[58]
    DIRECTION OUTPUT ;
    USE SIGNAL ;
    PORT
      LAYER M4 ;
        RECT  0 34.416 0.084 34.44 ;
    END
  END a_cfg_data[58]
  PIN a_cfg_data[59]
    DIRECTION OUTPUT ;
    USE SIGNAL ;
    PORT
      LAYER M4 ;
        RECT  0 34.512 0.084 34.536 ;
    END
  END a_cfg_data[59]
  PIN a_cfg_data[5]
    DIRECTION OUTPUT ;
    USE SIGNAL ;
    PORT
      LAYER M4 ;
        RECT  0 44.688 0.084 44.712 ;
    END
  END a_cfg_data[5]
  PIN a_cfg_data[60]
    DIRECTION OUTPUT ;
    USE SIGNAL ;
    PORT
      LAYER M4 ;
        RECT  0 34.608 0.084 34.632 ;
    END
  END a_cfg_data[60]
  PIN a_cfg_data[61]
    DIRECTION OUTPUT ;
    USE SIGNAL ;
    PORT
      LAYER M4 ;
        RECT  0 34.704 0.084 34.728 ;
    END
  END a_cfg_data[61]
  PIN a_cfg_data[62]
    DIRECTION OUTPUT ;
    USE SIGNAL ;
    PORT
      LAYER M4 ;
        RECT  0 34.8 0.084 34.824 ;
    END
  END a_cfg_data[62]
  PIN a_cfg_data[63]
    DIRECTION OUTPUT ;
    USE SIGNAL ;
    PORT
      LAYER M4 ;
        RECT  0 34.896 0.084 34.92 ;
    END
  END a_cfg_data[63]
  PIN a_cfg_data[64]
    DIRECTION OUTPUT ;
    USE SIGNAL ;
    PORT
      LAYER M4 ;
        RECT  0 34.992 0.084 35.016 ;
    END
  END a_cfg_data[64]
  PIN a_cfg_data[65]
    DIRECTION OUTPUT ;
    USE SIGNAL ;
    PORT
      LAYER M4 ;
        RECT  0 35.088 0.084 35.112 ;
    END
  END a_cfg_data[65]
  PIN a_cfg_data[66]
    DIRECTION OUTPUT ;
    USE SIGNAL ;
    PORT
      LAYER M4 ;
        RECT  0 35.184 0.084 35.208 ;
    END
  END a_cfg_data[66]
  PIN a_cfg_data[67]
    DIRECTION OUTPUT ;
    USE SIGNAL ;
    PORT
      LAYER M4 ;
        RECT  0 35.28 0.084 35.304 ;
    END
  END a_cfg_data[67]
  PIN a_cfg_data[68]
    DIRECTION OUTPUT ;
    USE SIGNAL ;
    PORT
      LAYER M4 ;
        RECT  0 35.376 0.084 35.4 ;
    END
  END a_cfg_data[68]
  PIN a_cfg_data[69]
    DIRECTION OUTPUT ;
    USE SIGNAL ;
    PORT
      LAYER M4 ;
        RECT  0 35.472 0.084 35.496 ;
    END
  END a_cfg_data[69]
  PIN a_cfg_data[6]
    DIRECTION OUTPUT ;
    USE SIGNAL ;
    PORT
      LAYER M4 ;
        RECT  0 44.784 0.084 44.808 ;
    END
  END a_cfg_data[6]
  PIN a_cfg_data[70]
    DIRECTION OUTPUT ;
    USE SIGNAL ;
    PORT
      LAYER M4 ;
        RECT  0 35.568 0.084 35.592 ;
    END
  END a_cfg_data[70]
  PIN a_cfg_data[71]
    DIRECTION OUTPUT ;
    USE SIGNAL ;
    PORT
      LAYER M4 ;
        RECT  0 35.664 0.084 35.688 ;
    END
  END a_cfg_data[71]
  PIN a_cfg_data[72]
    DIRECTION OUTPUT ;
    USE SIGNAL ;
    PORT
      LAYER M4 ;
        RECT  0 35.76 0.084 35.784 ;
    END
  END a_cfg_data[72]
  PIN a_cfg_data[73]
    DIRECTION OUTPUT ;
    USE SIGNAL ;
    PORT
      LAYER M4 ;
        RECT  0 35.856 0.084 35.88 ;
    END
  END a_cfg_data[73]
  PIN a_cfg_data[74]
    DIRECTION OUTPUT ;
    USE SIGNAL ;
    PORT
      LAYER M4 ;
        RECT  0 35.952 0.084 35.976 ;
    END
  END a_cfg_data[74]
  PIN a_cfg_data[75]
    DIRECTION OUTPUT ;
    USE SIGNAL ;
    PORT
      LAYER M4 ;
        RECT  0 36.048 0.084 36.072 ;
    END
  END a_cfg_data[75]
  PIN a_cfg_data[76]
    DIRECTION OUTPUT ;
    USE SIGNAL ;
    PORT
      LAYER M4 ;
        RECT  0 36.144 0.084 36.168 ;
    END
  END a_cfg_data[76]
  PIN a_cfg_data[77]
    DIRECTION OUTPUT ;
    USE SIGNAL ;
    PORT
      LAYER M4 ;
        RECT  0 36.24 0.084 36.264 ;
    END
  END a_cfg_data[77]
  PIN a_cfg_data[78]
    DIRECTION OUTPUT ;
    USE SIGNAL ;
    PORT
      LAYER M4 ;
        RECT  0 36.336 0.084 36.36 ;
    END
  END a_cfg_data[78]
  PIN a_cfg_data[79]
    DIRECTION OUTPUT ;
    USE SIGNAL ;
    PORT
      LAYER M4 ;
        RECT  0 36.432 0.084 36.456 ;
    END
  END a_cfg_data[79]
  PIN a_cfg_data[7]
    DIRECTION OUTPUT ;
    USE SIGNAL ;
    PORT
      LAYER M4 ;
        RECT  0 44.88 0.084 44.904 ;
    END
  END a_cfg_data[7]
  PIN a_cfg_data[80]
    DIRECTION OUTPUT ;
    USE SIGNAL ;
    PORT
      LAYER M4 ;
        RECT  0 36.528 0.084 36.552 ;
    END
  END a_cfg_data[80]
  PIN a_cfg_data[81]
    DIRECTION OUTPUT ;
    USE SIGNAL ;
    PORT
      LAYER M4 ;
        RECT  0 36.624 0.084 36.648 ;
    END
  END a_cfg_data[81]
  PIN a_cfg_data[82]
    DIRECTION OUTPUT ;
    USE SIGNAL ;
    PORT
      LAYER M4 ;
        RECT  0 36.72 0.084 36.744 ;
    END
  END a_cfg_data[82]
  PIN a_cfg_data[83]
    DIRECTION OUTPUT ;
    USE SIGNAL ;
    PORT
      LAYER M4 ;
        RECT  0 36.816 0.084 36.84 ;
    END
  END a_cfg_data[83]
  PIN a_cfg_data[84]
    DIRECTION OUTPUT ;
    USE SIGNAL ;
    PORT
      LAYER M4 ;
        RECT  0 46.128 0.084 46.152 ;
    END
  END a_cfg_data[84]
  PIN a_cfg_data[85]
    DIRECTION OUTPUT ;
    USE SIGNAL ;
    PORT
      LAYER M4 ;
        RECT  0 46.224 0.084 46.248 ;
    END
  END a_cfg_data[85]
  PIN a_cfg_data[86]
    DIRECTION OUTPUT ;
    USE SIGNAL ;
    PORT
      LAYER M4 ;
        RECT  0 46.32 0.084 46.344 ;
    END
  END a_cfg_data[86]
  PIN a_cfg_data[87]
    DIRECTION OUTPUT ;
    USE SIGNAL ;
    PORT
      LAYER M4 ;
        RECT  0 46.416 0.084 46.44 ;
    END
  END a_cfg_data[87]
  PIN a_cfg_data[88]
    DIRECTION OUTPUT ;
    USE SIGNAL ;
    PORT
      LAYER M4 ;
        RECT  0 46.512 0.084 46.536 ;
    END
  END a_cfg_data[88]
  PIN a_cfg_data[89]
    DIRECTION OUTPUT ;
    USE SIGNAL ;
    PORT
      LAYER M4 ;
        RECT  0 46.608 0.084 46.632 ;
    END
  END a_cfg_data[89]
  PIN a_cfg_data[8]
    DIRECTION OUTPUT ;
    USE SIGNAL ;
    PORT
      LAYER M4 ;
        RECT  0 44.976 0.084 45 ;
    END
  END a_cfg_data[8]
  PIN a_cfg_data[90]
    DIRECTION OUTPUT ;
    USE SIGNAL ;
    PORT
      LAYER M4 ;
        RECT  0 46.704 0.084 46.728 ;
    END
  END a_cfg_data[90]
  PIN a_cfg_data[91]
    DIRECTION OUTPUT ;
    USE SIGNAL ;
    PORT
      LAYER M4 ;
        RECT  0 46.8 0.084 46.824 ;
    END
  END a_cfg_data[91]
  PIN a_cfg_data[92]
    DIRECTION OUTPUT ;
    USE SIGNAL ;
    PORT
      LAYER M4 ;
        RECT  0 46.896 0.084 46.92 ;
    END
  END a_cfg_data[92]
  PIN a_cfg_data[93]
    DIRECTION OUTPUT ;
    USE SIGNAL ;
    PORT
      LAYER M4 ;
        RECT  0 46.992 0.084 47.016 ;
    END
  END a_cfg_data[93]
  PIN a_cfg_data[94]
    DIRECTION OUTPUT ;
    USE SIGNAL ;
    PORT
      LAYER M4 ;
        RECT  0 47.088 0.084 47.112 ;
    END
  END a_cfg_data[94]
  PIN a_cfg_data[95]
    DIRECTION OUTPUT ;
    USE SIGNAL ;
    PORT
      LAYER M4 ;
        RECT  0 47.184 0.084 47.208 ;
    END
  END a_cfg_data[95]
  PIN a_cfg_data[96]
    DIRECTION OUTPUT ;
    USE SIGNAL ;
    PORT
      LAYER M4 ;
        RECT  0 47.28 0.084 47.304 ;
    END
  END a_cfg_data[96]
  PIN a_cfg_data[97]
    DIRECTION OUTPUT ;
    USE SIGNAL ;
    PORT
      LAYER M4 ;
        RECT  0 47.376 0.084 47.4 ;
    END
  END a_cfg_data[97]
  PIN a_cfg_data[98]
    DIRECTION OUTPUT ;
    USE SIGNAL ;
    PORT
      LAYER M4 ;
        RECT  0 47.472 0.084 47.496 ;
    END
  END a_cfg_data[98]
  PIN a_cfg_data[99]
    DIRECTION OUTPUT ;
    USE SIGNAL ;
    PORT
      LAYER M4 ;
        RECT  0 47.568 0.084 47.592 ;
    END
  END a_cfg_data[99]
  PIN a_cfg_data[9]
    DIRECTION OUTPUT ;
    USE SIGNAL ;
    PORT
      LAYER M4 ;
        RECT  0 45.072 0.084 45.096 ;
    END
  END a_cfg_data[9]
  PIN a_cfg_target[0]
    DIRECTION OUTPUT ;
    USE SIGNAL ;
    PORT
      LAYER M4 ;
        RECT  0 21.936 0.084 21.96 ;
    END
  END a_cfg_target[0]
  PIN a_cfg_target[1]
    DIRECTION OUTPUT ;
    USE SIGNAL ;
    PORT
      LAYER M4 ;
        RECT  0 22.032 0.084 22.056 ;
    END
  END a_cfg_target[1]
  PIN a_cfg_target[2]
    DIRECTION OUTPUT ;
    USE SIGNAL ;
    PORT
      LAYER M4 ;
        RECT  0 22.128 0.084 22.152 ;
    END
  END a_cfg_target[2]
  PIN a_cfg_target[3]
    DIRECTION OUTPUT ;
    USE SIGNAL ;
    PORT
      LAYER M4 ;
        RECT  0 22.224 0.084 22.248 ;
    END
  END a_cfg_target[3]
  PIN a_cfg_target[4]
    DIRECTION OUTPUT ;
    USE SIGNAL ;
    PORT
      LAYER M4 ;
        RECT  0 22.32 0.084 22.344 ;
    END
  END a_cfg_target[4]
  PIN a_cfg_target[5]
    DIRECTION OUTPUT ;
    USE SIGNAL ;
    PORT
      LAYER M4 ;
        RECT  0 22.416 0.084 22.44 ;
    END
  END a_cfg_target[5]
  PIN a_cfg_target[6]
    DIRECTION OUTPUT ;
    USE SIGNAL ;
    PORT
      LAYER M4 ;
        RECT  0 22.512 0.084 22.536 ;
    END
  END a_cfg_target[6]
  PIN a_cfg_target[7]
    DIRECTION OUTPUT ;
    USE SIGNAL ;
    PORT
      LAYER M4 ;
        RECT  0 22.608 0.084 22.632 ;
    END
  END a_cfg_target[7]
  PIN a_cfg_v
    DIRECTION OUTPUT ;
    USE SIGNAL ;
    PORT
      LAYER M4 ;
        RECT  0 22.704 0.084 22.728 ;
    END
  END a_cfg_v
  PIN a_desc_base[0]
    DIRECTION OUTPUT ;
    USE SIGNAL ;
    PORT
      LAYER M4 ;
        RECT  0 22.8 0.084 22.824 ;
    END
  END a_desc_base[0]
  PIN a_desc_base[10]
    DIRECTION OUTPUT ;
    USE SIGNAL ;
    PORT
      LAYER M4 ;
        RECT  0 23.76 0.084 23.784 ;
    END
  END a_desc_base[10]
  PIN a_desc_base[11]
    DIRECTION OUTPUT ;
    USE SIGNAL ;
    PORT
      LAYER M4 ;
        RECT  0 17.712 0.084 17.736 ;
    END
  END a_desc_base[11]
  PIN a_desc_base[1]
    DIRECTION OUTPUT ;
    USE SIGNAL ;
    PORT
      LAYER M4 ;
        RECT  0 22.896 0.084 22.92 ;
    END
  END a_desc_base[1]
  PIN a_desc_base[2]
    DIRECTION OUTPUT ;
    USE SIGNAL ;
    PORT
      LAYER M4 ;
        RECT  0 22.992 0.084 23.016 ;
    END
  END a_desc_base[2]
  PIN a_desc_base[3]
    DIRECTION OUTPUT ;
    USE SIGNAL ;
    PORT
      LAYER M4 ;
        RECT  0 23.088 0.084 23.112 ;
    END
  END a_desc_base[3]
  PIN a_desc_base[4]
    DIRECTION OUTPUT ;
    USE SIGNAL ;
    PORT
      LAYER M4 ;
        RECT  0 23.184 0.084 23.208 ;
    END
  END a_desc_base[4]
  PIN a_desc_base[5]
    DIRECTION OUTPUT ;
    USE SIGNAL ;
    PORT
      LAYER M4 ;
        RECT  0 23.28 0.084 23.304 ;
    END
  END a_desc_base[5]
  PIN a_desc_base[6]
    DIRECTION OUTPUT ;
    USE SIGNAL ;
    PORT
      LAYER M4 ;
        RECT  0 23.376 0.084 23.4 ;
    END
  END a_desc_base[6]
  PIN a_desc_base[7]
    DIRECTION OUTPUT ;
    USE SIGNAL ;
    PORT
      LAYER M4 ;
        RECT  0 23.472 0.084 23.496 ;
    END
  END a_desc_base[7]
  PIN a_desc_base[8]
    DIRECTION OUTPUT ;
    USE SIGNAL ;
    PORT
      LAYER M4 ;
        RECT  0 23.568 0.084 23.592 ;
    END
  END a_desc_base[8]
  PIN a_desc_base[9]
    DIRECTION OUTPUT ;
    USE SIGNAL ;
    PORT
      LAYER M4 ;
        RECT  0 23.664 0.084 23.688 ;
    END
  END a_desc_base[9]
  PIN a_desc_limit[0]
    DIRECTION OUTPUT ;
    USE SIGNAL ;
    PORT
      LAYER M4 ;
        RECT  0 17.808 0.084 17.832 ;
    END
  END a_desc_limit[0]
  PIN a_desc_limit[10]
    DIRECTION OUTPUT ;
    USE SIGNAL ;
    PORT
      LAYER M4 ;
        RECT  0 18.768 0.084 18.792 ;
    END
  END a_desc_limit[10]
  PIN a_desc_limit[11]
    DIRECTION OUTPUT ;
    USE SIGNAL ;
    PORT
      LAYER M4 ;
        RECT  0 18.864 0.084 18.888 ;
    END
  END a_desc_limit[11]
  PIN a_desc_limit[12]
    DIRECTION OUTPUT ;
    USE SIGNAL ;
    PORT
      LAYER M4 ;
        RECT  0 18.96 0.084 18.984 ;
    END
  END a_desc_limit[12]
  PIN a_desc_limit[1]
    DIRECTION OUTPUT ;
    USE SIGNAL ;
    PORT
      LAYER M4 ;
        RECT  0 17.904 0.084 17.928 ;
    END
  END a_desc_limit[1]
  PIN a_desc_limit[2]
    DIRECTION OUTPUT ;
    USE SIGNAL ;
    PORT
      LAYER M4 ;
        RECT  0 18 0.084 18.024 ;
    END
  END a_desc_limit[2]
  PIN a_desc_limit[3]
    DIRECTION OUTPUT ;
    USE SIGNAL ;
    PORT
      LAYER M4 ;
        RECT  0 18.096 0.084 18.12 ;
    END
  END a_desc_limit[3]
  PIN a_desc_limit[4]
    DIRECTION OUTPUT ;
    USE SIGNAL ;
    PORT
      LAYER M4 ;
        RECT  0 18.192 0.084 18.216 ;
    END
  END a_desc_limit[4]
  PIN a_desc_limit[5]
    DIRECTION OUTPUT ;
    USE SIGNAL ;
    PORT
      LAYER M4 ;
        RECT  0 18.288 0.084 18.312 ;
    END
  END a_desc_limit[5]
  PIN a_desc_limit[6]
    DIRECTION OUTPUT ;
    USE SIGNAL ;
    PORT
      LAYER M4 ;
        RECT  0 18.384 0.084 18.408 ;
    END
  END a_desc_limit[6]
  PIN a_desc_limit[7]
    DIRECTION OUTPUT ;
    USE SIGNAL ;
    PORT
      LAYER M4 ;
        RECT  0 18.48 0.084 18.504 ;
    END
  END a_desc_limit[7]
  PIN a_desc_limit[8]
    DIRECTION OUTPUT ;
    USE SIGNAL ;
    PORT
      LAYER M4 ;
        RECT  0 18.576 0.084 18.6 ;
    END
  END a_desc_limit[8]
  PIN a_desc_limit[9]
    DIRECTION OUTPUT ;
    USE SIGNAL ;
    PORT
      LAYER M4 ;
        RECT  0 18.672 0.084 18.696 ;
    END
  END a_desc_limit[9]
  PIN a_desc_loops[0]
    DIRECTION OUTPUT ;
    USE SIGNAL ;
    PORT
      LAYER M4 ;
        RECT  0 19.056 0.084 19.08 ;
    END
  END a_desc_loops[0]
  PIN a_desc_loops[10]
    DIRECTION OUTPUT ;
    USE SIGNAL ;
    PORT
      LAYER M4 ;
        RECT  0 20.016 0.084 20.04 ;
    END
  END a_desc_loops[10]
  PIN a_desc_loops[11]
    DIRECTION OUTPUT ;
    USE SIGNAL ;
    PORT
      LAYER M4 ;
        RECT  0 20.112 0.084 20.136 ;
    END
  END a_desc_loops[11]
  PIN a_desc_loops[12]
    DIRECTION OUTPUT ;
    USE SIGNAL ;
    PORT
      LAYER M4 ;
        RECT  0 20.208 0.084 20.232 ;
    END
  END a_desc_loops[12]
  PIN a_desc_loops[13]
    DIRECTION OUTPUT ;
    USE SIGNAL ;
    PORT
      LAYER M4 ;
        RECT  0 20.304 0.084 20.328 ;
    END
  END a_desc_loops[13]
  PIN a_desc_loops[14]
    DIRECTION OUTPUT ;
    USE SIGNAL ;
    PORT
      LAYER M4 ;
        RECT  0 20.4 0.084 20.424 ;
    END
  END a_desc_loops[14]
  PIN a_desc_loops[15]
    DIRECTION OUTPUT ;
    USE SIGNAL ;
    PORT
      LAYER M4 ;
        RECT  0 20.496 0.084 20.52 ;
    END
  END a_desc_loops[15]
  PIN a_desc_loops[1]
    DIRECTION OUTPUT ;
    USE SIGNAL ;
    PORT
      LAYER M4 ;
        RECT  0 19.152 0.084 19.176 ;
    END
  END a_desc_loops[1]
  PIN a_desc_loops[2]
    DIRECTION OUTPUT ;
    USE SIGNAL ;
    PORT
      LAYER M4 ;
        RECT  0 19.248 0.084 19.272 ;
    END
  END a_desc_loops[2]
  PIN a_desc_loops[3]
    DIRECTION OUTPUT ;
    USE SIGNAL ;
    PORT
      LAYER M4 ;
        RECT  0 19.344 0.084 19.368 ;
    END
  END a_desc_loops[3]
  PIN a_desc_loops[4]
    DIRECTION OUTPUT ;
    USE SIGNAL ;
    PORT
      LAYER M4 ;
        RECT  0 19.44 0.084 19.464 ;
    END
  END a_desc_loops[4]
  PIN a_desc_loops[5]
    DIRECTION OUTPUT ;
    USE SIGNAL ;
    PORT
      LAYER M4 ;
        RECT  0 19.536 0.084 19.56 ;
    END
  END a_desc_loops[5]
  PIN a_desc_loops[6]
    DIRECTION OUTPUT ;
    USE SIGNAL ;
    PORT
      LAYER M4 ;
        RECT  0 19.632 0.084 19.656 ;
    END
  END a_desc_loops[6]
  PIN a_desc_loops[7]
    DIRECTION OUTPUT ;
    USE SIGNAL ;
    PORT
      LAYER M4 ;
        RECT  0 19.728 0.084 19.752 ;
    END
  END a_desc_loops[7]
  PIN a_desc_loops[8]
    DIRECTION OUTPUT ;
    USE SIGNAL ;
    PORT
      LAYER M4 ;
        RECT  0 19.824 0.084 19.848 ;
    END
  END a_desc_loops[8]
  PIN a_desc_loops[9]
    DIRECTION OUTPUT ;
    USE SIGNAL ;
    PORT
      LAYER M4 ;
        RECT  0 19.92 0.084 19.944 ;
    END
  END a_desc_loops[9]
  PIN a_desc_v
    DIRECTION OUTPUT ;
    USE SIGNAL ;
    PORT
      LAYER M4 ;
        RECT  0 20.592 0.084 20.616 ;
    END
  END a_desc_v
  PIN a_launch_v
    DIRECTION OUTPUT ;
    USE SIGNAL ;
    PORT
      LAYER M4 ;
        RECT  0 20.688 0.084 20.712 ;
    END
  END a_launch_v
  PIN b_cfg_addr[0]
    DIRECTION OUTPUT ;
    USE SIGNAL ;
    PORT
      LAYER M4 ;
        RECT  69.036 22.992 69.12 23.016 ;
    END
  END b_cfg_addr[0]
  PIN b_cfg_addr[10]
    DIRECTION OUTPUT ;
    USE SIGNAL ;
    PORT
      LAYER M4 ;
        RECT  69.036 23.952 69.12 23.976 ;
    END
  END b_cfg_addr[10]
  PIN b_cfg_addr[11]
    DIRECTION OUTPUT ;
    USE SIGNAL ;
    PORT
      LAYER M4 ;
        RECT  69.036 24.048 69.12 24.072 ;
    END
  END b_cfg_addr[11]
  PIN b_cfg_addr[1]
    DIRECTION OUTPUT ;
    USE SIGNAL ;
    PORT
      LAYER M4 ;
        RECT  69.036 23.088 69.12 23.112 ;
    END
  END b_cfg_addr[1]
  PIN b_cfg_addr[2]
    DIRECTION OUTPUT ;
    USE SIGNAL ;
    PORT
      LAYER M4 ;
        RECT  69.036 23.184 69.12 23.208 ;
    END
  END b_cfg_addr[2]
  PIN b_cfg_addr[3]
    DIRECTION OUTPUT ;
    USE SIGNAL ;
    PORT
      LAYER M4 ;
        RECT  69.036 23.28 69.12 23.304 ;
    END
  END b_cfg_addr[3]
  PIN b_cfg_addr[4]
    DIRECTION OUTPUT ;
    USE SIGNAL ;
    PORT
      LAYER M4 ;
        RECT  69.036 23.376 69.12 23.4 ;
    END
  END b_cfg_addr[4]
  PIN b_cfg_addr[5]
    DIRECTION OUTPUT ;
    USE SIGNAL ;
    PORT
      LAYER M4 ;
        RECT  69.036 23.472 69.12 23.496 ;
    END
  END b_cfg_addr[5]
  PIN b_cfg_addr[6]
    DIRECTION OUTPUT ;
    USE SIGNAL ;
    PORT
      LAYER M4 ;
        RECT  69.036 23.568 69.12 23.592 ;
    END
  END b_cfg_addr[6]
  PIN b_cfg_addr[7]
    DIRECTION OUTPUT ;
    USE SIGNAL ;
    PORT
      LAYER M4 ;
        RECT  69.036 23.664 69.12 23.688 ;
    END
  END b_cfg_addr[7]
  PIN b_cfg_addr[8]
    DIRECTION OUTPUT ;
    USE SIGNAL ;
    PORT
      LAYER M4 ;
        RECT  69.036 23.76 69.12 23.784 ;
    END
  END b_cfg_addr[8]
  PIN b_cfg_addr[9]
    DIRECTION OUTPUT ;
    USE SIGNAL ;
    PORT
      LAYER M4 ;
        RECT  69.036 23.856 69.12 23.88 ;
    END
  END b_cfg_addr[9]
  PIN b_cfg_data[0]
    DIRECTION OUTPUT ;
    USE SIGNAL ;
    PORT
      LAYER M4 ;
        RECT  69.036 24.144 69.12 24.168 ;
    END
  END b_cfg_data[0]
  PIN b_cfg_data[100]
    DIRECTION OUTPUT ;
    USE SIGNAL ;
    PORT
      LAYER M4 ;
        RECT  69.036 49.872 69.12 49.896 ;
    END
  END b_cfg_data[100]
  PIN b_cfg_data[101]
    DIRECTION OUTPUT ;
    USE SIGNAL ;
    PORT
      LAYER M4 ;
        RECT  69.036 49.968 69.12 49.992 ;
    END
  END b_cfg_data[101]
  PIN b_cfg_data[102]
    DIRECTION OUTPUT ;
    USE SIGNAL ;
    PORT
      LAYER M4 ;
        RECT  69.036 50.064 69.12 50.088 ;
    END
  END b_cfg_data[102]
  PIN b_cfg_data[103]
    DIRECTION OUTPUT ;
    USE SIGNAL ;
    PORT
      LAYER M4 ;
        RECT  69.036 50.16 69.12 50.184 ;
    END
  END b_cfg_data[103]
  PIN b_cfg_data[104]
    DIRECTION OUTPUT ;
    USE SIGNAL ;
    PORT
      LAYER M4 ;
        RECT  69.036 50.256 69.12 50.28 ;
    END
  END b_cfg_data[104]
  PIN b_cfg_data[105]
    DIRECTION OUTPUT ;
    USE SIGNAL ;
    PORT
      LAYER M4 ;
        RECT  69.036 50.352 69.12 50.376 ;
    END
  END b_cfg_data[105]
  PIN b_cfg_data[106]
    DIRECTION OUTPUT ;
    USE SIGNAL ;
    PORT
      LAYER M4 ;
        RECT  69.036 50.448 69.12 50.472 ;
    END
  END b_cfg_data[106]
  PIN b_cfg_data[107]
    DIRECTION OUTPUT ;
    USE SIGNAL ;
    PORT
      LAYER M4 ;
        RECT  69.036 50.544 69.12 50.568 ;
    END
  END b_cfg_data[107]
  PIN b_cfg_data[108]
    DIRECTION OUTPUT ;
    USE SIGNAL ;
    PORT
      LAYER M4 ;
        RECT  69.036 50.64 69.12 50.664 ;
    END
  END b_cfg_data[108]
  PIN b_cfg_data[109]
    DIRECTION OUTPUT ;
    USE SIGNAL ;
    PORT
      LAYER M4 ;
        RECT  69.036 50.736 69.12 50.76 ;
    END
  END b_cfg_data[109]
  PIN b_cfg_data[10]
    DIRECTION OUTPUT ;
    USE SIGNAL ;
    PORT
      LAYER M4 ;
        RECT  69.036 25.104 69.12 25.128 ;
    END
  END b_cfg_data[10]
  PIN b_cfg_data[110]
    DIRECTION OUTPUT ;
    USE SIGNAL ;
    PORT
      LAYER M4 ;
        RECT  69.036 50.832 69.12 50.856 ;
    END
  END b_cfg_data[110]
  PIN b_cfg_data[111]
    DIRECTION OUTPUT ;
    USE SIGNAL ;
    PORT
      LAYER M4 ;
        RECT  69.036 50.928 69.12 50.952 ;
    END
  END b_cfg_data[111]
  PIN b_cfg_data[112]
    DIRECTION OUTPUT ;
    USE SIGNAL ;
    PORT
      LAYER M4 ;
        RECT  69.036 51.024 69.12 51.048 ;
    END
  END b_cfg_data[112]
  PIN b_cfg_data[113]
    DIRECTION OUTPUT ;
    USE SIGNAL ;
    PORT
      LAYER M4 ;
        RECT  69.036 51.12 69.12 51.144 ;
    END
  END b_cfg_data[113]
  PIN b_cfg_data[114]
    DIRECTION OUTPUT ;
    USE SIGNAL ;
    PORT
      LAYER M4 ;
        RECT  69.036 51.216 69.12 51.24 ;
    END
  END b_cfg_data[114]
  PIN b_cfg_data[115]
    DIRECTION OUTPUT ;
    USE SIGNAL ;
    PORT
      LAYER M4 ;
        RECT  69.036 51.312 69.12 51.336 ;
    END
  END b_cfg_data[115]
  PIN b_cfg_data[116]
    DIRECTION OUTPUT ;
    USE SIGNAL ;
    PORT
      LAYER M4 ;
        RECT  69.036 35.28 69.12 35.304 ;
    END
  END b_cfg_data[116]
  PIN b_cfg_data[117]
    DIRECTION OUTPUT ;
    USE SIGNAL ;
    PORT
      LAYER M4 ;
        RECT  69.036 35.376 69.12 35.4 ;
    END
  END b_cfg_data[117]
  PIN b_cfg_data[118]
    DIRECTION OUTPUT ;
    USE SIGNAL ;
    PORT
      LAYER M4 ;
        RECT  69.036 35.472 69.12 35.496 ;
    END
  END b_cfg_data[118]
  PIN b_cfg_data[119]
    DIRECTION OUTPUT ;
    USE SIGNAL ;
    PORT
      LAYER M4 ;
        RECT  69.036 35.568 69.12 35.592 ;
    END
  END b_cfg_data[119]
  PIN b_cfg_data[11]
    DIRECTION OUTPUT ;
    USE SIGNAL ;
    PORT
      LAYER M4 ;
        RECT  69.036 25.2 69.12 25.224 ;
    END
  END b_cfg_data[11]
  PIN b_cfg_data[120]
    DIRECTION OUTPUT ;
    USE SIGNAL ;
    PORT
      LAYER M4 ;
        RECT  69.036 35.664 69.12 35.688 ;
    END
  END b_cfg_data[120]
  PIN b_cfg_data[121]
    DIRECTION OUTPUT ;
    USE SIGNAL ;
    PORT
      LAYER M4 ;
        RECT  69.036 35.76 69.12 35.784 ;
    END
  END b_cfg_data[121]
  PIN b_cfg_data[122]
    DIRECTION OUTPUT ;
    USE SIGNAL ;
    PORT
      LAYER M4 ;
        RECT  69.036 35.856 69.12 35.88 ;
    END
  END b_cfg_data[122]
  PIN b_cfg_data[123]
    DIRECTION OUTPUT ;
    USE SIGNAL ;
    PORT
      LAYER M4 ;
        RECT  69.036 35.952 69.12 35.976 ;
    END
  END b_cfg_data[123]
  PIN b_cfg_data[124]
    DIRECTION OUTPUT ;
    USE SIGNAL ;
    PORT
      LAYER M4 ;
        RECT  69.036 36.048 69.12 36.072 ;
    END
  END b_cfg_data[124]
  PIN b_cfg_data[125]
    DIRECTION OUTPUT ;
    USE SIGNAL ;
    PORT
      LAYER M4 ;
        RECT  69.036 36.144 69.12 36.168 ;
    END
  END b_cfg_data[125]
  PIN b_cfg_data[126]
    DIRECTION OUTPUT ;
    USE SIGNAL ;
    PORT
      LAYER M4 ;
        RECT  69.036 36.24 69.12 36.264 ;
    END
  END b_cfg_data[126]
  PIN b_cfg_data[127]
    DIRECTION OUTPUT ;
    USE SIGNAL ;
    PORT
      LAYER M4 ;
        RECT  69.036 36.336 69.12 36.36 ;
    END
  END b_cfg_data[127]
  PIN b_cfg_data[128]
    DIRECTION OUTPUT ;
    USE SIGNAL ;
    PORT
      LAYER M4 ;
        RECT  69.036 36.432 69.12 36.456 ;
    END
  END b_cfg_data[128]
  PIN b_cfg_data[129]
    DIRECTION OUTPUT ;
    USE SIGNAL ;
    PORT
      LAYER M4 ;
        RECT  69.036 36.528 69.12 36.552 ;
    END
  END b_cfg_data[129]
  PIN b_cfg_data[12]
    DIRECTION OUTPUT ;
    USE SIGNAL ;
    PORT
      LAYER M4 ;
        RECT  69.036 25.296 69.12 25.32 ;
    END
  END b_cfg_data[12]
  PIN b_cfg_data[130]
    DIRECTION OUTPUT ;
    USE SIGNAL ;
    PORT
      LAYER M4 ;
        RECT  69.036 36.624 69.12 36.648 ;
    END
  END b_cfg_data[130]
  PIN b_cfg_data[131]
    DIRECTION OUTPUT ;
    USE SIGNAL ;
    PORT
      LAYER M4 ;
        RECT  69.036 36.72 69.12 36.744 ;
    END
  END b_cfg_data[131]
  PIN b_cfg_data[132]
    DIRECTION OUTPUT ;
    USE SIGNAL ;
    PORT
      LAYER M4 ;
        RECT  69.036 36.816 69.12 36.84 ;
    END
  END b_cfg_data[132]
  PIN b_cfg_data[133]
    DIRECTION OUTPUT ;
    USE SIGNAL ;
    PORT
      LAYER M4 ;
        RECT  69.036 36.912 69.12 36.936 ;
    END
  END b_cfg_data[133]
  PIN b_cfg_data[134]
    DIRECTION OUTPUT ;
    USE SIGNAL ;
    PORT
      LAYER M4 ;
        RECT  69.036 37.008 69.12 37.032 ;
    END
  END b_cfg_data[134]
  PIN b_cfg_data[135]
    DIRECTION OUTPUT ;
    USE SIGNAL ;
    PORT
      LAYER M4 ;
        RECT  69.036 37.104 69.12 37.128 ;
    END
  END b_cfg_data[135]
  PIN b_cfg_data[136]
    DIRECTION OUTPUT ;
    USE SIGNAL ;
    PORT
      LAYER M4 ;
        RECT  69.036 37.2 69.12 37.224 ;
    END
  END b_cfg_data[136]
  PIN b_cfg_data[137]
    DIRECTION OUTPUT ;
    USE SIGNAL ;
    PORT
      LAYER M4 ;
        RECT  69.036 37.296 69.12 37.32 ;
    END
  END b_cfg_data[137]
  PIN b_cfg_data[138]
    DIRECTION OUTPUT ;
    USE SIGNAL ;
    PORT
      LAYER M4 ;
        RECT  69.036 37.392 69.12 37.416 ;
    END
  END b_cfg_data[138]
  PIN b_cfg_data[139]
    DIRECTION OUTPUT ;
    USE SIGNAL ;
    PORT
      LAYER M4 ;
        RECT  69.036 37.488 69.12 37.512 ;
    END
  END b_cfg_data[139]
  PIN b_cfg_data[13]
    DIRECTION OUTPUT ;
    USE SIGNAL ;
    PORT
      LAYER M4 ;
        RECT  69.036 25.392 69.12 25.416 ;
    END
  END b_cfg_data[13]
  PIN b_cfg_data[140]
    DIRECTION OUTPUT ;
    USE SIGNAL ;
    PORT
      LAYER M4 ;
        RECT  69.036 37.584 69.12 37.608 ;
    END
  END b_cfg_data[140]
  PIN b_cfg_data[141]
    DIRECTION OUTPUT ;
    USE SIGNAL ;
    PORT
      LAYER M4 ;
        RECT  69.036 37.68 69.12 37.704 ;
    END
  END b_cfg_data[141]
  PIN b_cfg_data[142]
    DIRECTION OUTPUT ;
    USE SIGNAL ;
    PORT
      LAYER M4 ;
        RECT  69.036 37.776 69.12 37.8 ;
    END
  END b_cfg_data[142]
  PIN b_cfg_data[143]
    DIRECTION OUTPUT ;
    USE SIGNAL ;
    PORT
      LAYER M4 ;
        RECT  69.036 37.872 69.12 37.896 ;
    END
  END b_cfg_data[143]
  PIN b_cfg_data[144]
    DIRECTION OUTPUT ;
    USE SIGNAL ;
    PORT
      LAYER M4 ;
        RECT  69.036 37.968 69.12 37.992 ;
    END
  END b_cfg_data[144]
  PIN b_cfg_data[145]
    DIRECTION OUTPUT ;
    USE SIGNAL ;
    PORT
      LAYER M4 ;
        RECT  69.036 38.064 69.12 38.088 ;
    END
  END b_cfg_data[145]
  PIN b_cfg_data[146]
    DIRECTION OUTPUT ;
    USE SIGNAL ;
    PORT
      LAYER M4 ;
        RECT  69.036 38.16 69.12 38.184 ;
    END
  END b_cfg_data[146]
  PIN b_cfg_data[147]
    DIRECTION OUTPUT ;
    USE SIGNAL ;
    PORT
      LAYER M4 ;
        RECT  69.036 38.256 69.12 38.28 ;
    END
  END b_cfg_data[147]
  PIN b_cfg_data[148]
    DIRECTION OUTPUT ;
    USE SIGNAL ;
    PORT
      LAYER M4 ;
        RECT  69.036 42.192 69.12 42.216 ;
    END
  END b_cfg_data[148]
  PIN b_cfg_data[149]
    DIRECTION OUTPUT ;
    USE SIGNAL ;
    PORT
      LAYER M4 ;
        RECT  69.036 42.288 69.12 42.312 ;
    END
  END b_cfg_data[149]
  PIN b_cfg_data[14]
    DIRECTION OUTPUT ;
    USE SIGNAL ;
    PORT
      LAYER M4 ;
        RECT  69.036 25.488 69.12 25.512 ;
    END
  END b_cfg_data[14]
  PIN b_cfg_data[150]
    DIRECTION OUTPUT ;
    USE SIGNAL ;
    PORT
      LAYER M4 ;
        RECT  69.036 42.384 69.12 42.408 ;
    END
  END b_cfg_data[150]
  PIN b_cfg_data[151]
    DIRECTION OUTPUT ;
    USE SIGNAL ;
    PORT
      LAYER M4 ;
        RECT  69.036 42.48 69.12 42.504 ;
    END
  END b_cfg_data[151]
  PIN b_cfg_data[152]
    DIRECTION OUTPUT ;
    USE SIGNAL ;
    PORT
      LAYER M4 ;
        RECT  69.036 42.576 69.12 42.6 ;
    END
  END b_cfg_data[152]
  PIN b_cfg_data[153]
    DIRECTION OUTPUT ;
    USE SIGNAL ;
    PORT
      LAYER M4 ;
        RECT  69.036 42.672 69.12 42.696 ;
    END
  END b_cfg_data[153]
  PIN b_cfg_data[154]
    DIRECTION OUTPUT ;
    USE SIGNAL ;
    PORT
      LAYER M4 ;
        RECT  69.036 42.768 69.12 42.792 ;
    END
  END b_cfg_data[154]
  PIN b_cfg_data[155]
    DIRECTION OUTPUT ;
    USE SIGNAL ;
    PORT
      LAYER M4 ;
        RECT  69.036 42.864 69.12 42.888 ;
    END
  END b_cfg_data[155]
  PIN b_cfg_data[156]
    DIRECTION OUTPUT ;
    USE SIGNAL ;
    PORT
      LAYER M4 ;
        RECT  69.036 42.96 69.12 42.984 ;
    END
  END b_cfg_data[156]
  PIN b_cfg_data[157]
    DIRECTION OUTPUT ;
    USE SIGNAL ;
    PORT
      LAYER M4 ;
        RECT  69.036 43.056 69.12 43.08 ;
    END
  END b_cfg_data[157]
  PIN b_cfg_data[158]
    DIRECTION OUTPUT ;
    USE SIGNAL ;
    PORT
      LAYER M4 ;
        RECT  69.036 43.152 69.12 43.176 ;
    END
  END b_cfg_data[158]
  PIN b_cfg_data[159]
    DIRECTION OUTPUT ;
    USE SIGNAL ;
    PORT
      LAYER M4 ;
        RECT  69.036 43.248 69.12 43.272 ;
    END
  END b_cfg_data[159]
  PIN b_cfg_data[15]
    DIRECTION OUTPUT ;
    USE SIGNAL ;
    PORT
      LAYER M4 ;
        RECT  69.036 25.584 69.12 25.608 ;
    END
  END b_cfg_data[15]
  PIN b_cfg_data[160]
    DIRECTION OUTPUT ;
    USE SIGNAL ;
    PORT
      LAYER M4 ;
        RECT  69.036 43.344 69.12 43.368 ;
    END
  END b_cfg_data[160]
  PIN b_cfg_data[161]
    DIRECTION OUTPUT ;
    USE SIGNAL ;
    PORT
      LAYER M4 ;
        RECT  69.036 43.44 69.12 43.464 ;
    END
  END b_cfg_data[161]
  PIN b_cfg_data[162]
    DIRECTION OUTPUT ;
    USE SIGNAL ;
    PORT
      LAYER M4 ;
        RECT  69.036 43.536 69.12 43.56 ;
    END
  END b_cfg_data[162]
  PIN b_cfg_data[163]
    DIRECTION OUTPUT ;
    USE SIGNAL ;
    PORT
      LAYER M4 ;
        RECT  69.036 43.632 69.12 43.656 ;
    END
  END b_cfg_data[163]
  PIN b_cfg_data[164]
    DIRECTION OUTPUT ;
    USE SIGNAL ;
    PORT
      LAYER M4 ;
        RECT  69.036 43.728 69.12 43.752 ;
    END
  END b_cfg_data[164]
  PIN b_cfg_data[165]
    DIRECTION OUTPUT ;
    USE SIGNAL ;
    PORT
      LAYER M4 ;
        RECT  69.036 43.824 69.12 43.848 ;
    END
  END b_cfg_data[165]
  PIN b_cfg_data[166]
    DIRECTION OUTPUT ;
    USE SIGNAL ;
    PORT
      LAYER M4 ;
        RECT  69.036 43.92 69.12 43.944 ;
    END
  END b_cfg_data[166]
  PIN b_cfg_data[167]
    DIRECTION OUTPUT ;
    USE SIGNAL ;
    PORT
      LAYER M4 ;
        RECT  69.036 44.016 69.12 44.04 ;
    END
  END b_cfg_data[167]
  PIN b_cfg_data[168]
    DIRECTION OUTPUT ;
    USE SIGNAL ;
    PORT
      LAYER M4 ;
        RECT  69.036 44.112 69.12 44.136 ;
    END
  END b_cfg_data[168]
  PIN b_cfg_data[169]
    DIRECTION OUTPUT ;
    USE SIGNAL ;
    PORT
      LAYER M4 ;
        RECT  69.036 44.208 69.12 44.232 ;
    END
  END b_cfg_data[169]
  PIN b_cfg_data[16]
    DIRECTION OUTPUT ;
    USE SIGNAL ;
    PORT
      LAYER M4 ;
        RECT  69.036 25.68 69.12 25.704 ;
    END
  END b_cfg_data[16]
  PIN b_cfg_data[170]
    DIRECTION OUTPUT ;
    USE SIGNAL ;
    PORT
      LAYER M4 ;
        RECT  69.036 44.304 69.12 44.328 ;
    END
  END b_cfg_data[170]
  PIN b_cfg_data[171]
    DIRECTION OUTPUT ;
    USE SIGNAL ;
    PORT
      LAYER M4 ;
        RECT  69.036 44.4 69.12 44.424 ;
    END
  END b_cfg_data[171]
  PIN b_cfg_data[172]
    DIRECTION OUTPUT ;
    USE SIGNAL ;
    PORT
      LAYER M4 ;
        RECT  69.036 44.496 69.12 44.52 ;
    END
  END b_cfg_data[172]
  PIN b_cfg_data[173]
    DIRECTION OUTPUT ;
    USE SIGNAL ;
    PORT
      LAYER M4 ;
        RECT  69.036 44.592 69.12 44.616 ;
    END
  END b_cfg_data[173]
  PIN b_cfg_data[174]
    DIRECTION OUTPUT ;
    USE SIGNAL ;
    PORT
      LAYER M4 ;
        RECT  69.036 44.688 69.12 44.712 ;
    END
  END b_cfg_data[174]
  PIN b_cfg_data[175]
    DIRECTION OUTPUT ;
    USE SIGNAL ;
    PORT
      LAYER M4 ;
        RECT  69.036 44.784 69.12 44.808 ;
    END
  END b_cfg_data[175]
  PIN b_cfg_data[176]
    DIRECTION OUTPUT ;
    USE SIGNAL ;
    PORT
      LAYER M4 ;
        RECT  69.036 44.88 69.12 44.904 ;
    END
  END b_cfg_data[176]
  PIN b_cfg_data[177]
    DIRECTION OUTPUT ;
    USE SIGNAL ;
    PORT
      LAYER M4 ;
        RECT  69.036 44.976 69.12 45 ;
    END
  END b_cfg_data[177]
  PIN b_cfg_data[178]
    DIRECTION OUTPUT ;
    USE SIGNAL ;
    PORT
      LAYER M4 ;
        RECT  69.036 45.072 69.12 45.096 ;
    END
  END b_cfg_data[178]
  PIN b_cfg_data[179]
    DIRECTION OUTPUT ;
    USE SIGNAL ;
    PORT
      LAYER M4 ;
        RECT  69.036 45.168 69.12 45.192 ;
    END
  END b_cfg_data[179]
  PIN b_cfg_data[17]
    DIRECTION OUTPUT ;
    USE SIGNAL ;
    PORT
      LAYER M4 ;
        RECT  69.036 25.776 69.12 25.8 ;
    END
  END b_cfg_data[17]
  PIN b_cfg_data[180]
    DIRECTION OUTPUT ;
    USE SIGNAL ;
    PORT
      LAYER M4 ;
        RECT  69.036 29.136 69.12 29.16 ;
    END
  END b_cfg_data[180]
  PIN b_cfg_data[181]
    DIRECTION OUTPUT ;
    USE SIGNAL ;
    PORT
      LAYER M4 ;
        RECT  69.036 29.232 69.12 29.256 ;
    END
  END b_cfg_data[181]
  PIN b_cfg_data[182]
    DIRECTION OUTPUT ;
    USE SIGNAL ;
    PORT
      LAYER M4 ;
        RECT  69.036 29.328 69.12 29.352 ;
    END
  END b_cfg_data[182]
  PIN b_cfg_data[183]
    DIRECTION OUTPUT ;
    USE SIGNAL ;
    PORT
      LAYER M4 ;
        RECT  69.036 29.424 69.12 29.448 ;
    END
  END b_cfg_data[183]
  PIN b_cfg_data[184]
    DIRECTION OUTPUT ;
    USE SIGNAL ;
    PORT
      LAYER M4 ;
        RECT  69.036 29.52 69.12 29.544 ;
    END
  END b_cfg_data[184]
  PIN b_cfg_data[185]
    DIRECTION OUTPUT ;
    USE SIGNAL ;
    PORT
      LAYER M4 ;
        RECT  69.036 29.616 69.12 29.64 ;
    END
  END b_cfg_data[185]
  PIN b_cfg_data[186]
    DIRECTION OUTPUT ;
    USE SIGNAL ;
    PORT
      LAYER M4 ;
        RECT  69.036 29.712 69.12 29.736 ;
    END
  END b_cfg_data[186]
  PIN b_cfg_data[187]
    DIRECTION OUTPUT ;
    USE SIGNAL ;
    PORT
      LAYER M4 ;
        RECT  69.036 29.808 69.12 29.832 ;
    END
  END b_cfg_data[187]
  PIN b_cfg_data[188]
    DIRECTION OUTPUT ;
    USE SIGNAL ;
    PORT
      LAYER M4 ;
        RECT  69.036 29.904 69.12 29.928 ;
    END
  END b_cfg_data[188]
  PIN b_cfg_data[189]
    DIRECTION OUTPUT ;
    USE SIGNAL ;
    PORT
      LAYER M4 ;
        RECT  69.036 30 69.12 30.024 ;
    END
  END b_cfg_data[189]
  PIN b_cfg_data[18]
    DIRECTION OUTPUT ;
    USE SIGNAL ;
    PORT
      LAYER M4 ;
        RECT  69.036 25.872 69.12 25.896 ;
    END
  END b_cfg_data[18]
  PIN b_cfg_data[190]
    DIRECTION OUTPUT ;
    USE SIGNAL ;
    PORT
      LAYER M4 ;
        RECT  69.036 30.096 69.12 30.12 ;
    END
  END b_cfg_data[190]
  PIN b_cfg_data[191]
    DIRECTION OUTPUT ;
    USE SIGNAL ;
    PORT
      LAYER M4 ;
        RECT  69.036 30.192 69.12 30.216 ;
    END
  END b_cfg_data[191]
  PIN b_cfg_data[192]
    DIRECTION OUTPUT ;
    USE SIGNAL ;
    PORT
      LAYER M4 ;
        RECT  69.036 30.288 69.12 30.312 ;
    END
  END b_cfg_data[192]
  PIN b_cfg_data[193]
    DIRECTION OUTPUT ;
    USE SIGNAL ;
    PORT
      LAYER M4 ;
        RECT  69.036 30.384 69.12 30.408 ;
    END
  END b_cfg_data[193]
  PIN b_cfg_data[194]
    DIRECTION OUTPUT ;
    USE SIGNAL ;
    PORT
      LAYER M4 ;
        RECT  69.036 30.48 69.12 30.504 ;
    END
  END b_cfg_data[194]
  PIN b_cfg_data[195]
    DIRECTION OUTPUT ;
    USE SIGNAL ;
    PORT
      LAYER M4 ;
        RECT  69.036 30.576 69.12 30.6 ;
    END
  END b_cfg_data[195]
  PIN b_cfg_data[196]
    DIRECTION OUTPUT ;
    USE SIGNAL ;
    PORT
      LAYER M4 ;
        RECT  69.036 30.672 69.12 30.696 ;
    END
  END b_cfg_data[196]
  PIN b_cfg_data[197]
    DIRECTION OUTPUT ;
    USE SIGNAL ;
    PORT
      LAYER M4 ;
        RECT  69.036 30.768 69.12 30.792 ;
    END
  END b_cfg_data[197]
  PIN b_cfg_data[198]
    DIRECTION OUTPUT ;
    USE SIGNAL ;
    PORT
      LAYER M4 ;
        RECT  69.036 30.864 69.12 30.888 ;
    END
  END b_cfg_data[198]
  PIN b_cfg_data[199]
    DIRECTION OUTPUT ;
    USE SIGNAL ;
    PORT
      LAYER M4 ;
        RECT  69.036 30.96 69.12 30.984 ;
    END
  END b_cfg_data[199]
  PIN b_cfg_data[19]
    DIRECTION OUTPUT ;
    USE SIGNAL ;
    PORT
      LAYER M4 ;
        RECT  69.036 25.968 69.12 25.992 ;
    END
  END b_cfg_data[19]
  PIN b_cfg_data[1]
    DIRECTION OUTPUT ;
    USE SIGNAL ;
    PORT
      LAYER M4 ;
        RECT  69.036 24.24 69.12 24.264 ;
    END
  END b_cfg_data[1]
  PIN b_cfg_data[200]
    DIRECTION OUTPUT ;
    USE SIGNAL ;
    PORT
      LAYER M4 ;
        RECT  69.036 31.056 69.12 31.08 ;
    END
  END b_cfg_data[200]
  PIN b_cfg_data[201]
    DIRECTION OUTPUT ;
    USE SIGNAL ;
    PORT
      LAYER M4 ;
        RECT  69.036 31.152 69.12 31.176 ;
    END
  END b_cfg_data[201]
  PIN b_cfg_data[202]
    DIRECTION OUTPUT ;
    USE SIGNAL ;
    PORT
      LAYER M4 ;
        RECT  69.036 31.248 69.12 31.272 ;
    END
  END b_cfg_data[202]
  PIN b_cfg_data[203]
    DIRECTION OUTPUT ;
    USE SIGNAL ;
    PORT
      LAYER M4 ;
        RECT  69.036 31.344 69.12 31.368 ;
    END
  END b_cfg_data[203]
  PIN b_cfg_data[204]
    DIRECTION OUTPUT ;
    USE SIGNAL ;
    PORT
      LAYER M4 ;
        RECT  69.036 31.44 69.12 31.464 ;
    END
  END b_cfg_data[204]
  PIN b_cfg_data[205]
    DIRECTION OUTPUT ;
    USE SIGNAL ;
    PORT
      LAYER M4 ;
        RECT  69.036 31.536 69.12 31.56 ;
    END
  END b_cfg_data[205]
  PIN b_cfg_data[206]
    DIRECTION OUTPUT ;
    USE SIGNAL ;
    PORT
      LAYER M4 ;
        RECT  69.036 31.632 69.12 31.656 ;
    END
  END b_cfg_data[206]
  PIN b_cfg_data[207]
    DIRECTION OUTPUT ;
    USE SIGNAL ;
    PORT
      LAYER M4 ;
        RECT  69.036 31.728 69.12 31.752 ;
    END
  END b_cfg_data[207]
  PIN b_cfg_data[208]
    DIRECTION OUTPUT ;
    USE SIGNAL ;
    PORT
      LAYER M4 ;
        RECT  69.036 31.824 69.12 31.848 ;
    END
  END b_cfg_data[208]
  PIN b_cfg_data[209]
    DIRECTION OUTPUT ;
    USE SIGNAL ;
    PORT
      LAYER M4 ;
        RECT  69.036 31.92 69.12 31.944 ;
    END
  END b_cfg_data[209]
  PIN b_cfg_data[20]
    DIRECTION OUTPUT ;
    USE SIGNAL ;
    PORT
      LAYER M4 ;
        RECT  69.036 26.064 69.12 26.088 ;
    END
  END b_cfg_data[20]
  PIN b_cfg_data[210]
    DIRECTION OUTPUT ;
    USE SIGNAL ;
    PORT
      LAYER M4 ;
        RECT  69.036 32.016 69.12 32.04 ;
    END
  END b_cfg_data[210]
  PIN b_cfg_data[211]
    DIRECTION OUTPUT ;
    USE SIGNAL ;
    PORT
      LAYER M4 ;
        RECT  69.036 32.112 69.12 32.136 ;
    END
  END b_cfg_data[211]
  PIN b_cfg_data[212]
    DIRECTION OUTPUT ;
    USE SIGNAL ;
    PORT
      LAYER M4 ;
        RECT  69.036 32.208 69.12 32.232 ;
    END
  END b_cfg_data[212]
  PIN b_cfg_data[213]
    DIRECTION OUTPUT ;
    USE SIGNAL ;
    PORT
      LAYER M4 ;
        RECT  69.036 32.304 69.12 32.328 ;
    END
  END b_cfg_data[213]
  PIN b_cfg_data[214]
    DIRECTION OUTPUT ;
    USE SIGNAL ;
    PORT
      LAYER M4 ;
        RECT  69.036 32.4 69.12 32.424 ;
    END
  END b_cfg_data[214]
  PIN b_cfg_data[215]
    DIRECTION OUTPUT ;
    USE SIGNAL ;
    PORT
      LAYER M4 ;
        RECT  69.036 32.496 69.12 32.52 ;
    END
  END b_cfg_data[215]
  PIN b_cfg_data[216]
    DIRECTION OUTPUT ;
    USE SIGNAL ;
    PORT
      LAYER M4 ;
        RECT  69.036 32.592 69.12 32.616 ;
    END
  END b_cfg_data[216]
  PIN b_cfg_data[217]
    DIRECTION OUTPUT ;
    USE SIGNAL ;
    PORT
      LAYER M4 ;
        RECT  69.036 32.688 69.12 32.712 ;
    END
  END b_cfg_data[217]
  PIN b_cfg_data[218]
    DIRECTION OUTPUT ;
    USE SIGNAL ;
    PORT
      LAYER M4 ;
        RECT  69.036 32.784 69.12 32.808 ;
    END
  END b_cfg_data[218]
  PIN b_cfg_data[219]
    DIRECTION OUTPUT ;
    USE SIGNAL ;
    PORT
      LAYER M4 ;
        RECT  69.036 32.88 69.12 32.904 ;
    END
  END b_cfg_data[219]
  PIN b_cfg_data[21]
    DIRECTION OUTPUT ;
    USE SIGNAL ;
    PORT
      LAYER M4 ;
        RECT  69.036 26.16 69.12 26.184 ;
    END
  END b_cfg_data[21]
  PIN b_cfg_data[220]
    DIRECTION OUTPUT ;
    USE SIGNAL ;
    PORT
      LAYER M4 ;
        RECT  69.036 32.976 69.12 33 ;
    END
  END b_cfg_data[220]
  PIN b_cfg_data[221]
    DIRECTION OUTPUT ;
    USE SIGNAL ;
    PORT
      LAYER M4 ;
        RECT  69.036 33.072 69.12 33.096 ;
    END
  END b_cfg_data[221]
  PIN b_cfg_data[222]
    DIRECTION OUTPUT ;
    USE SIGNAL ;
    PORT
      LAYER M4 ;
        RECT  69.036 33.168 69.12 33.192 ;
    END
  END b_cfg_data[222]
  PIN b_cfg_data[223]
    DIRECTION OUTPUT ;
    USE SIGNAL ;
    PORT
      LAYER M4 ;
        RECT  69.036 33.264 69.12 33.288 ;
    END
  END b_cfg_data[223]
  PIN b_cfg_data[224]
    DIRECTION OUTPUT ;
    USE SIGNAL ;
    PORT
      LAYER M4 ;
        RECT  69.036 33.36 69.12 33.384 ;
    END
  END b_cfg_data[224]
  PIN b_cfg_data[225]
    DIRECTION OUTPUT ;
    USE SIGNAL ;
    PORT
      LAYER M4 ;
        RECT  69.036 33.456 69.12 33.48 ;
    END
  END b_cfg_data[225]
  PIN b_cfg_data[226]
    DIRECTION OUTPUT ;
    USE SIGNAL ;
    PORT
      LAYER M4 ;
        RECT  69.036 33.552 69.12 33.576 ;
    END
  END b_cfg_data[226]
  PIN b_cfg_data[227]
    DIRECTION OUTPUT ;
    USE SIGNAL ;
    PORT
      LAYER M4 ;
        RECT  69.036 33.648 69.12 33.672 ;
    END
  END b_cfg_data[227]
  PIN b_cfg_data[228]
    DIRECTION OUTPUT ;
    USE SIGNAL ;
    PORT
      LAYER M4 ;
        RECT  69.036 33.744 69.12 33.768 ;
    END
  END b_cfg_data[228]
  PIN b_cfg_data[229]
    DIRECTION OUTPUT ;
    USE SIGNAL ;
    PORT
      LAYER M4 ;
        RECT  69.036 33.84 69.12 33.864 ;
    END
  END b_cfg_data[229]
  PIN b_cfg_data[22]
    DIRECTION OUTPUT ;
    USE SIGNAL ;
    PORT
      LAYER M4 ;
        RECT  69.036 26.256 69.12 26.28 ;
    END
  END b_cfg_data[22]
  PIN b_cfg_data[230]
    DIRECTION OUTPUT ;
    USE SIGNAL ;
    PORT
      LAYER M4 ;
        RECT  69.036 33.936 69.12 33.96 ;
    END
  END b_cfg_data[230]
  PIN b_cfg_data[231]
    DIRECTION OUTPUT ;
    USE SIGNAL ;
    PORT
      LAYER M4 ;
        RECT  69.036 34.032 69.12 34.056 ;
    END
  END b_cfg_data[231]
  PIN b_cfg_data[232]
    DIRECTION OUTPUT ;
    USE SIGNAL ;
    PORT
      LAYER M4 ;
        RECT  69.036 34.128 69.12 34.152 ;
    END
  END b_cfg_data[232]
  PIN b_cfg_data[233]
    DIRECTION OUTPUT ;
    USE SIGNAL ;
    PORT
      LAYER M4 ;
        RECT  69.036 34.224 69.12 34.248 ;
    END
  END b_cfg_data[233]
  PIN b_cfg_data[234]
    DIRECTION OUTPUT ;
    USE SIGNAL ;
    PORT
      LAYER M4 ;
        RECT  69.036 34.32 69.12 34.344 ;
    END
  END b_cfg_data[234]
  PIN b_cfg_data[235]
    DIRECTION OUTPUT ;
    USE SIGNAL ;
    PORT
      LAYER M4 ;
        RECT  69.036 34.416 69.12 34.44 ;
    END
  END b_cfg_data[235]
  PIN b_cfg_data[236]
    DIRECTION OUTPUT ;
    USE SIGNAL ;
    PORT
      LAYER M4 ;
        RECT  69.036 34.512 69.12 34.536 ;
    END
  END b_cfg_data[236]
  PIN b_cfg_data[237]
    DIRECTION OUTPUT ;
    USE SIGNAL ;
    PORT
      LAYER M4 ;
        RECT  69.036 34.608 69.12 34.632 ;
    END
  END b_cfg_data[237]
  PIN b_cfg_data[238]
    DIRECTION OUTPUT ;
    USE SIGNAL ;
    PORT
      LAYER M4 ;
        RECT  69.036 34.704 69.12 34.728 ;
    END
  END b_cfg_data[238]
  PIN b_cfg_data[239]
    DIRECTION OUTPUT ;
    USE SIGNAL ;
    PORT
      LAYER M4 ;
        RECT  69.036 34.8 69.12 34.824 ;
    END
  END b_cfg_data[239]
  PIN b_cfg_data[23]
    DIRECTION OUTPUT ;
    USE SIGNAL ;
    PORT
      LAYER M4 ;
        RECT  69.036 26.352 69.12 26.376 ;
    END
  END b_cfg_data[23]
  PIN b_cfg_data[240]
    DIRECTION OUTPUT ;
    USE SIGNAL ;
    PORT
      LAYER M4 ;
        RECT  69.036 34.896 69.12 34.92 ;
    END
  END b_cfg_data[240]
  PIN b_cfg_data[241]
    DIRECTION OUTPUT ;
    USE SIGNAL ;
    PORT
      LAYER M4 ;
        RECT  69.036 34.992 69.12 35.016 ;
    END
  END b_cfg_data[241]
  PIN b_cfg_data[242]
    DIRECTION OUTPUT ;
    USE SIGNAL ;
    PORT
      LAYER M4 ;
        RECT  69.036 35.088 69.12 35.112 ;
    END
  END b_cfg_data[242]
  PIN b_cfg_data[243]
    DIRECTION OUTPUT ;
    USE SIGNAL ;
    PORT
      LAYER M4 ;
        RECT  69.036 35.184 69.12 35.208 ;
    END
  END b_cfg_data[243]
  PIN b_cfg_data[244]
    DIRECTION OUTPUT ;
    USE SIGNAL ;
    PORT
      LAYER M4 ;
        RECT  69.036 45.264 69.12 45.288 ;
    END
  END b_cfg_data[244]
  PIN b_cfg_data[245]
    DIRECTION OUTPUT ;
    USE SIGNAL ;
    PORT
      LAYER M4 ;
        RECT  69.036 45.36 69.12 45.384 ;
    END
  END b_cfg_data[245]
  PIN b_cfg_data[246]
    DIRECTION OUTPUT ;
    USE SIGNAL ;
    PORT
      LAYER M4 ;
        RECT  69.036 45.456 69.12 45.48 ;
    END
  END b_cfg_data[246]
  PIN b_cfg_data[247]
    DIRECTION OUTPUT ;
    USE SIGNAL ;
    PORT
      LAYER M4 ;
        RECT  69.036 45.552 69.12 45.576 ;
    END
  END b_cfg_data[247]
  PIN b_cfg_data[248]
    DIRECTION OUTPUT ;
    USE SIGNAL ;
    PORT
      LAYER M4 ;
        RECT  69.036 45.648 69.12 45.672 ;
    END
  END b_cfg_data[248]
  PIN b_cfg_data[249]
    DIRECTION OUTPUT ;
    USE SIGNAL ;
    PORT
      LAYER M4 ;
        RECT  69.036 45.744 69.12 45.768 ;
    END
  END b_cfg_data[249]
  PIN b_cfg_data[24]
    DIRECTION OUTPUT ;
    USE SIGNAL ;
    PORT
      LAYER M4 ;
        RECT  69.036 26.448 69.12 26.472 ;
    END
  END b_cfg_data[24]
  PIN b_cfg_data[250]
    DIRECTION OUTPUT ;
    USE SIGNAL ;
    PORT
      LAYER M4 ;
        RECT  69.036 45.84 69.12 45.864 ;
    END
  END b_cfg_data[250]
  PIN b_cfg_data[251]
    DIRECTION OUTPUT ;
    USE SIGNAL ;
    PORT
      LAYER M4 ;
        RECT  69.036 45.936 69.12 45.96 ;
    END
  END b_cfg_data[251]
  PIN b_cfg_data[252]
    DIRECTION OUTPUT ;
    USE SIGNAL ;
    PORT
      LAYER M4 ;
        RECT  69.036 46.032 69.12 46.056 ;
    END
  END b_cfg_data[252]
  PIN b_cfg_data[253]
    DIRECTION OUTPUT ;
    USE SIGNAL ;
    PORT
      LAYER M4 ;
        RECT  69.036 46.128 69.12 46.152 ;
    END
  END b_cfg_data[253]
  PIN b_cfg_data[254]
    DIRECTION OUTPUT ;
    USE SIGNAL ;
    PORT
      LAYER M4 ;
        RECT  69.036 46.224 69.12 46.248 ;
    END
  END b_cfg_data[254]
  PIN b_cfg_data[255]
    DIRECTION OUTPUT ;
    USE SIGNAL ;
    PORT
      LAYER M4 ;
        RECT  69.036 46.32 69.12 46.344 ;
    END
  END b_cfg_data[255]
  PIN b_cfg_data[25]
    DIRECTION OUTPUT ;
    USE SIGNAL ;
    PORT
      LAYER M4 ;
        RECT  69.036 26.544 69.12 26.568 ;
    END
  END b_cfg_data[25]
  PIN b_cfg_data[26]
    DIRECTION OUTPUT ;
    USE SIGNAL ;
    PORT
      LAYER M4 ;
        RECT  69.036 26.64 69.12 26.664 ;
    END
  END b_cfg_data[26]
  PIN b_cfg_data[27]
    DIRECTION OUTPUT ;
    USE SIGNAL ;
    PORT
      LAYER M4 ;
        RECT  69.036 26.736 69.12 26.76 ;
    END
  END b_cfg_data[27]
  PIN b_cfg_data[28]
    DIRECTION OUTPUT ;
    USE SIGNAL ;
    PORT
      LAYER M4 ;
        RECT  69.036 26.832 69.12 26.856 ;
    END
  END b_cfg_data[28]
  PIN b_cfg_data[29]
    DIRECTION OUTPUT ;
    USE SIGNAL ;
    PORT
      LAYER M4 ;
        RECT  69.036 26.928 69.12 26.952 ;
    END
  END b_cfg_data[29]
  PIN b_cfg_data[2]
    DIRECTION OUTPUT ;
    USE SIGNAL ;
    PORT
      LAYER M4 ;
        RECT  69.036 24.336 69.12 24.36 ;
    END
  END b_cfg_data[2]
  PIN b_cfg_data[30]
    DIRECTION OUTPUT ;
    USE SIGNAL ;
    PORT
      LAYER M4 ;
        RECT  69.036 27.024 69.12 27.048 ;
    END
  END b_cfg_data[30]
  PIN b_cfg_data[31]
    DIRECTION OUTPUT ;
    USE SIGNAL ;
    PORT
      LAYER M4 ;
        RECT  69.036 27.12 69.12 27.144 ;
    END
  END b_cfg_data[31]
  PIN b_cfg_data[32]
    DIRECTION OUTPUT ;
    USE SIGNAL ;
    PORT
      LAYER M4 ;
        RECT  69.036 27.216 69.12 27.24 ;
    END
  END b_cfg_data[32]
  PIN b_cfg_data[33]
    DIRECTION OUTPUT ;
    USE SIGNAL ;
    PORT
      LAYER M4 ;
        RECT  69.036 27.312 69.12 27.336 ;
    END
  END b_cfg_data[33]
  PIN b_cfg_data[34]
    DIRECTION OUTPUT ;
    USE SIGNAL ;
    PORT
      LAYER M4 ;
        RECT  69.036 27.408 69.12 27.432 ;
    END
  END b_cfg_data[34]
  PIN b_cfg_data[35]
    DIRECTION OUTPUT ;
    USE SIGNAL ;
    PORT
      LAYER M4 ;
        RECT  69.036 27.504 69.12 27.528 ;
    END
  END b_cfg_data[35]
  PIN b_cfg_data[36]
    DIRECTION OUTPUT ;
    USE SIGNAL ;
    PORT
      LAYER M4 ;
        RECT  69.036 27.6 69.12 27.624 ;
    END
  END b_cfg_data[36]
  PIN b_cfg_data[37]
    DIRECTION OUTPUT ;
    USE SIGNAL ;
    PORT
      LAYER M4 ;
        RECT  69.036 27.696 69.12 27.72 ;
    END
  END b_cfg_data[37]
  PIN b_cfg_data[38]
    DIRECTION OUTPUT ;
    USE SIGNAL ;
    PORT
      LAYER M4 ;
        RECT  69.036 27.792 69.12 27.816 ;
    END
  END b_cfg_data[38]
  PIN b_cfg_data[39]
    DIRECTION OUTPUT ;
    USE SIGNAL ;
    PORT
      LAYER M4 ;
        RECT  69.036 27.888 69.12 27.912 ;
    END
  END b_cfg_data[39]
  PIN b_cfg_data[3]
    DIRECTION OUTPUT ;
    USE SIGNAL ;
    PORT
      LAYER M4 ;
        RECT  69.036 24.432 69.12 24.456 ;
    END
  END b_cfg_data[3]
  PIN b_cfg_data[40]
    DIRECTION OUTPUT ;
    USE SIGNAL ;
    PORT
      LAYER M4 ;
        RECT  69.036 27.984 69.12 28.008 ;
    END
  END b_cfg_data[40]
  PIN b_cfg_data[41]
    DIRECTION OUTPUT ;
    USE SIGNAL ;
    PORT
      LAYER M4 ;
        RECT  69.036 28.08 69.12 28.104 ;
    END
  END b_cfg_data[41]
  PIN b_cfg_data[42]
    DIRECTION OUTPUT ;
    USE SIGNAL ;
    PORT
      LAYER M4 ;
        RECT  69.036 28.176 69.12 28.2 ;
    END
  END b_cfg_data[42]
  PIN b_cfg_data[43]
    DIRECTION OUTPUT ;
    USE SIGNAL ;
    PORT
      LAYER M4 ;
        RECT  69.036 28.272 69.12 28.296 ;
    END
  END b_cfg_data[43]
  PIN b_cfg_data[44]
    DIRECTION OUTPUT ;
    USE SIGNAL ;
    PORT
      LAYER M4 ;
        RECT  69.036 28.368 69.12 28.392 ;
    END
  END b_cfg_data[44]
  PIN b_cfg_data[45]
    DIRECTION OUTPUT ;
    USE SIGNAL ;
    PORT
      LAYER M4 ;
        RECT  69.036 28.464 69.12 28.488 ;
    END
  END b_cfg_data[45]
  PIN b_cfg_data[46]
    DIRECTION OUTPUT ;
    USE SIGNAL ;
    PORT
      LAYER M4 ;
        RECT  69.036 28.56 69.12 28.584 ;
    END
  END b_cfg_data[46]
  PIN b_cfg_data[47]
    DIRECTION OUTPUT ;
    USE SIGNAL ;
    PORT
      LAYER M4 ;
        RECT  69.036 28.656 69.12 28.68 ;
    END
  END b_cfg_data[47]
  PIN b_cfg_data[48]
    DIRECTION OUTPUT ;
    USE SIGNAL ;
    PORT
      LAYER M4 ;
        RECT  69.036 28.752 69.12 28.776 ;
    END
  END b_cfg_data[48]
  PIN b_cfg_data[49]
    DIRECTION OUTPUT ;
    USE SIGNAL ;
    PORT
      LAYER M4 ;
        RECT  69.036 28.848 69.12 28.872 ;
    END
  END b_cfg_data[49]
  PIN b_cfg_data[4]
    DIRECTION OUTPUT ;
    USE SIGNAL ;
    PORT
      LAYER M4 ;
        RECT  69.036 24.528 69.12 24.552 ;
    END
  END b_cfg_data[4]
  PIN b_cfg_data[50]
    DIRECTION OUTPUT ;
    USE SIGNAL ;
    PORT
      LAYER M4 ;
        RECT  69.036 28.944 69.12 28.968 ;
    END
  END b_cfg_data[50]
  PIN b_cfg_data[51]
    DIRECTION OUTPUT ;
    USE SIGNAL ;
    PORT
      LAYER M4 ;
        RECT  69.036 29.04 69.12 29.064 ;
    END
  END b_cfg_data[51]
  PIN b_cfg_data[52]
    DIRECTION OUTPUT ;
    USE SIGNAL ;
    PORT
      LAYER M4 ;
        RECT  69.036 19.92 69.12 19.944 ;
    END
  END b_cfg_data[52]
  PIN b_cfg_data[53]
    DIRECTION OUTPUT ;
    USE SIGNAL ;
    PORT
      LAYER M4 ;
        RECT  69.036 20.016 69.12 20.04 ;
    END
  END b_cfg_data[53]
  PIN b_cfg_data[54]
    DIRECTION OUTPUT ;
    USE SIGNAL ;
    PORT
      LAYER M4 ;
        RECT  69.036 20.112 69.12 20.136 ;
    END
  END b_cfg_data[54]
  PIN b_cfg_data[55]
    DIRECTION OUTPUT ;
    USE SIGNAL ;
    PORT
      LAYER M4 ;
        RECT  69.036 20.208 69.12 20.232 ;
    END
  END b_cfg_data[55]
  PIN b_cfg_data[56]
    DIRECTION OUTPUT ;
    USE SIGNAL ;
    PORT
      LAYER M4 ;
        RECT  69.036 20.304 69.12 20.328 ;
    END
  END b_cfg_data[56]
  PIN b_cfg_data[57]
    DIRECTION OUTPUT ;
    USE SIGNAL ;
    PORT
      LAYER M4 ;
        RECT  69.036 20.4 69.12 20.424 ;
    END
  END b_cfg_data[57]
  PIN b_cfg_data[58]
    DIRECTION OUTPUT ;
    USE SIGNAL ;
    PORT
      LAYER M4 ;
        RECT  69.036 20.496 69.12 20.52 ;
    END
  END b_cfg_data[58]
  PIN b_cfg_data[59]
    DIRECTION OUTPUT ;
    USE SIGNAL ;
    PORT
      LAYER M4 ;
        RECT  69.036 20.592 69.12 20.616 ;
    END
  END b_cfg_data[59]
  PIN b_cfg_data[5]
    DIRECTION OUTPUT ;
    USE SIGNAL ;
    PORT
      LAYER M4 ;
        RECT  69.036 24.624 69.12 24.648 ;
    END
  END b_cfg_data[5]
  PIN b_cfg_data[60]
    DIRECTION OUTPUT ;
    USE SIGNAL ;
    PORT
      LAYER M4 ;
        RECT  69.036 20.688 69.12 20.712 ;
    END
  END b_cfg_data[60]
  PIN b_cfg_data[61]
    DIRECTION OUTPUT ;
    USE SIGNAL ;
    PORT
      LAYER M4 ;
        RECT  69.036 20.784 69.12 20.808 ;
    END
  END b_cfg_data[61]
  PIN b_cfg_data[62]
    DIRECTION OUTPUT ;
    USE SIGNAL ;
    PORT
      LAYER M4 ;
        RECT  69.036 20.88 69.12 20.904 ;
    END
  END b_cfg_data[62]
  PIN b_cfg_data[63]
    DIRECTION OUTPUT ;
    USE SIGNAL ;
    PORT
      LAYER M4 ;
        RECT  69.036 20.976 69.12 21 ;
    END
  END b_cfg_data[63]
  PIN b_cfg_data[64]
    DIRECTION OUTPUT ;
    USE SIGNAL ;
    PORT
      LAYER M4 ;
        RECT  69.036 21.072 69.12 21.096 ;
    END
  END b_cfg_data[64]
  PIN b_cfg_data[65]
    DIRECTION OUTPUT ;
    USE SIGNAL ;
    PORT
      LAYER M4 ;
        RECT  69.036 21.168 69.12 21.192 ;
    END
  END b_cfg_data[65]
  PIN b_cfg_data[66]
    DIRECTION OUTPUT ;
    USE SIGNAL ;
    PORT
      LAYER M4 ;
        RECT  69.036 21.264 69.12 21.288 ;
    END
  END b_cfg_data[66]
  PIN b_cfg_data[67]
    DIRECTION OUTPUT ;
    USE SIGNAL ;
    PORT
      LAYER M4 ;
        RECT  69.036 21.36 69.12 21.384 ;
    END
  END b_cfg_data[67]
  PIN b_cfg_data[68]
    DIRECTION OUTPUT ;
    USE SIGNAL ;
    PORT
      LAYER M4 ;
        RECT  69.036 21.456 69.12 21.48 ;
    END
  END b_cfg_data[68]
  PIN b_cfg_data[69]
    DIRECTION OUTPUT ;
    USE SIGNAL ;
    PORT
      LAYER M4 ;
        RECT  69.036 21.552 69.12 21.576 ;
    END
  END b_cfg_data[69]
  PIN b_cfg_data[6]
    DIRECTION OUTPUT ;
    USE SIGNAL ;
    PORT
      LAYER M4 ;
        RECT  69.036 24.72 69.12 24.744 ;
    END
  END b_cfg_data[6]
  PIN b_cfg_data[70]
    DIRECTION OUTPUT ;
    USE SIGNAL ;
    PORT
      LAYER M4 ;
        RECT  69.036 21.648 69.12 21.672 ;
    END
  END b_cfg_data[70]
  PIN b_cfg_data[71]
    DIRECTION OUTPUT ;
    USE SIGNAL ;
    PORT
      LAYER M4 ;
        RECT  69.036 21.744 69.12 21.768 ;
    END
  END b_cfg_data[71]
  PIN b_cfg_data[72]
    DIRECTION OUTPUT ;
    USE SIGNAL ;
    PORT
      LAYER M4 ;
        RECT  69.036 21.84 69.12 21.864 ;
    END
  END b_cfg_data[72]
  PIN b_cfg_data[73]
    DIRECTION OUTPUT ;
    USE SIGNAL ;
    PORT
      LAYER M4 ;
        RECT  69.036 21.936 69.12 21.96 ;
    END
  END b_cfg_data[73]
  PIN b_cfg_data[74]
    DIRECTION OUTPUT ;
    USE SIGNAL ;
    PORT
      LAYER M4 ;
        RECT  69.036 22.032 69.12 22.056 ;
    END
  END b_cfg_data[74]
  PIN b_cfg_data[75]
    DIRECTION OUTPUT ;
    USE SIGNAL ;
    PORT
      LAYER M4 ;
        RECT  69.036 22.128 69.12 22.152 ;
    END
  END b_cfg_data[75]
  PIN b_cfg_data[76]
    DIRECTION OUTPUT ;
    USE SIGNAL ;
    PORT
      LAYER M4 ;
        RECT  69.036 22.224 69.12 22.248 ;
    END
  END b_cfg_data[76]
  PIN b_cfg_data[77]
    DIRECTION OUTPUT ;
    USE SIGNAL ;
    PORT
      LAYER M4 ;
        RECT  69.036 22.32 69.12 22.344 ;
    END
  END b_cfg_data[77]
  PIN b_cfg_data[78]
    DIRECTION OUTPUT ;
    USE SIGNAL ;
    PORT
      LAYER M4 ;
        RECT  69.036 22.416 69.12 22.44 ;
    END
  END b_cfg_data[78]
  PIN b_cfg_data[79]
    DIRECTION OUTPUT ;
    USE SIGNAL ;
    PORT
      LAYER M4 ;
        RECT  69.036 22.512 69.12 22.536 ;
    END
  END b_cfg_data[79]
  PIN b_cfg_data[7]
    DIRECTION OUTPUT ;
    USE SIGNAL ;
    PORT
      LAYER M4 ;
        RECT  69.036 24.816 69.12 24.84 ;
    END
  END b_cfg_data[7]
  PIN b_cfg_data[80]
    DIRECTION OUTPUT ;
    USE SIGNAL ;
    PORT
      LAYER M4 ;
        RECT  69.036 22.608 69.12 22.632 ;
    END
  END b_cfg_data[80]
  PIN b_cfg_data[81]
    DIRECTION OUTPUT ;
    USE SIGNAL ;
    PORT
      LAYER M4 ;
        RECT  69.036 22.704 69.12 22.728 ;
    END
  END b_cfg_data[81]
  PIN b_cfg_data[82]
    DIRECTION OUTPUT ;
    USE SIGNAL ;
    PORT
      LAYER M4 ;
        RECT  69.036 22.8 69.12 22.824 ;
    END
  END b_cfg_data[82]
  PIN b_cfg_data[83]
    DIRECTION OUTPUT ;
    USE SIGNAL ;
    PORT
      LAYER M4 ;
        RECT  69.036 22.896 69.12 22.92 ;
    END
  END b_cfg_data[83]
  PIN b_cfg_data[84]
    DIRECTION OUTPUT ;
    USE SIGNAL ;
    PORT
      LAYER M4 ;
        RECT  69.036 48.336 69.12 48.36 ;
    END
  END b_cfg_data[84]
  PIN b_cfg_data[85]
    DIRECTION OUTPUT ;
    USE SIGNAL ;
    PORT
      LAYER M4 ;
        RECT  69.036 48.432 69.12 48.456 ;
    END
  END b_cfg_data[85]
  PIN b_cfg_data[86]
    DIRECTION OUTPUT ;
    USE SIGNAL ;
    PORT
      LAYER M4 ;
        RECT  69.036 48.528 69.12 48.552 ;
    END
  END b_cfg_data[86]
  PIN b_cfg_data[87]
    DIRECTION OUTPUT ;
    USE SIGNAL ;
    PORT
      LAYER M4 ;
        RECT  69.036 48.624 69.12 48.648 ;
    END
  END b_cfg_data[87]
  PIN b_cfg_data[88]
    DIRECTION OUTPUT ;
    USE SIGNAL ;
    PORT
      LAYER M4 ;
        RECT  69.036 48.72 69.12 48.744 ;
    END
  END b_cfg_data[88]
  PIN b_cfg_data[89]
    DIRECTION OUTPUT ;
    USE SIGNAL ;
    PORT
      LAYER M4 ;
        RECT  69.036 48.816 69.12 48.84 ;
    END
  END b_cfg_data[89]
  PIN b_cfg_data[8]
    DIRECTION OUTPUT ;
    USE SIGNAL ;
    PORT
      LAYER M4 ;
        RECT  69.036 24.912 69.12 24.936 ;
    END
  END b_cfg_data[8]
  PIN b_cfg_data[90]
    DIRECTION OUTPUT ;
    USE SIGNAL ;
    PORT
      LAYER M4 ;
        RECT  69.036 48.912 69.12 48.936 ;
    END
  END b_cfg_data[90]
  PIN b_cfg_data[91]
    DIRECTION OUTPUT ;
    USE SIGNAL ;
    PORT
      LAYER M4 ;
        RECT  69.036 49.008 69.12 49.032 ;
    END
  END b_cfg_data[91]
  PIN b_cfg_data[92]
    DIRECTION OUTPUT ;
    USE SIGNAL ;
    PORT
      LAYER M4 ;
        RECT  69.036 49.104 69.12 49.128 ;
    END
  END b_cfg_data[92]
  PIN b_cfg_data[93]
    DIRECTION OUTPUT ;
    USE SIGNAL ;
    PORT
      LAYER M4 ;
        RECT  69.036 49.2 69.12 49.224 ;
    END
  END b_cfg_data[93]
  PIN b_cfg_data[94]
    DIRECTION OUTPUT ;
    USE SIGNAL ;
    PORT
      LAYER M4 ;
        RECT  69.036 49.296 69.12 49.32 ;
    END
  END b_cfg_data[94]
  PIN b_cfg_data[95]
    DIRECTION OUTPUT ;
    USE SIGNAL ;
    PORT
      LAYER M4 ;
        RECT  69.036 49.392 69.12 49.416 ;
    END
  END b_cfg_data[95]
  PIN b_cfg_data[96]
    DIRECTION OUTPUT ;
    USE SIGNAL ;
    PORT
      LAYER M4 ;
        RECT  69.036 49.488 69.12 49.512 ;
    END
  END b_cfg_data[96]
  PIN b_cfg_data[97]
    DIRECTION OUTPUT ;
    USE SIGNAL ;
    PORT
      LAYER M4 ;
        RECT  69.036 49.584 69.12 49.608 ;
    END
  END b_cfg_data[97]
  PIN b_cfg_data[98]
    DIRECTION OUTPUT ;
    USE SIGNAL ;
    PORT
      LAYER M4 ;
        RECT  69.036 49.68 69.12 49.704 ;
    END
  END b_cfg_data[98]
  PIN b_cfg_data[99]
    DIRECTION OUTPUT ;
    USE SIGNAL ;
    PORT
      LAYER M4 ;
        RECT  69.036 49.776 69.12 49.8 ;
    END
  END b_cfg_data[99]
  PIN b_cfg_data[9]
    DIRECTION OUTPUT ;
    USE SIGNAL ;
    PORT
      LAYER M4 ;
        RECT  69.036 25.008 69.12 25.032 ;
    END
  END b_cfg_data[9]
  PIN b_cfg_target[0]
    DIRECTION OUTPUT ;
    USE SIGNAL ;
    PORT
      LAYER M4 ;
        RECT  69.036 46.416 69.12 46.44 ;
    END
  END b_cfg_target[0]
  PIN b_cfg_target[1]
    DIRECTION OUTPUT ;
    USE SIGNAL ;
    PORT
      LAYER M4 ;
        RECT  69.036 46.512 69.12 46.536 ;
    END
  END b_cfg_target[1]
  PIN b_cfg_target[2]
    DIRECTION OUTPUT ;
    USE SIGNAL ;
    PORT
      LAYER M4 ;
        RECT  69.036 46.608 69.12 46.632 ;
    END
  END b_cfg_target[2]
  PIN b_cfg_target[3]
    DIRECTION OUTPUT ;
    USE SIGNAL ;
    PORT
      LAYER M4 ;
        RECT  69.036 46.704 69.12 46.728 ;
    END
  END b_cfg_target[3]
  PIN b_cfg_target[4]
    DIRECTION OUTPUT ;
    USE SIGNAL ;
    PORT
      LAYER M4 ;
        RECT  69.036 46.8 69.12 46.824 ;
    END
  END b_cfg_target[4]
  PIN b_cfg_target[5]
    DIRECTION OUTPUT ;
    USE SIGNAL ;
    PORT
      LAYER M4 ;
        RECT  69.036 46.896 69.12 46.92 ;
    END
  END b_cfg_target[5]
  PIN b_cfg_target[6]
    DIRECTION OUTPUT ;
    USE SIGNAL ;
    PORT
      LAYER M4 ;
        RECT  69.036 46.992 69.12 47.016 ;
    END
  END b_cfg_target[6]
  PIN b_cfg_target[7]
    DIRECTION OUTPUT ;
    USE SIGNAL ;
    PORT
      LAYER M4 ;
        RECT  69.036 47.088 69.12 47.112 ;
    END
  END b_cfg_target[7]
  PIN b_cfg_v
    DIRECTION OUTPUT ;
    USE SIGNAL ;
    PORT
      LAYER M4 ;
        RECT  69.036 47.184 69.12 47.208 ;
    END
  END b_cfg_v
  PIN b_desc_base[0]
    DIRECTION OUTPUT ;
    USE SIGNAL ;
    PORT
      LAYER M4 ;
        RECT  69.036 47.28 69.12 47.304 ;
    END
  END b_desc_base[0]
  PIN b_desc_base[10]
    DIRECTION OUTPUT ;
    USE SIGNAL ;
    PORT
      LAYER M4 ;
        RECT  69.036 48.24 69.12 48.264 ;
    END
  END b_desc_base[10]
  PIN b_desc_base[11]
    DIRECTION OUTPUT ;
    USE SIGNAL ;
    PORT
      LAYER M4 ;
        RECT  69.036 39.12 69.12 39.144 ;
    END
  END b_desc_base[11]
  PIN b_desc_base[1]
    DIRECTION OUTPUT ;
    USE SIGNAL ;
    PORT
      LAYER M4 ;
        RECT  69.036 47.376 69.12 47.4 ;
    END
  END b_desc_base[1]
  PIN b_desc_base[2]
    DIRECTION OUTPUT ;
    USE SIGNAL ;
    PORT
      LAYER M4 ;
        RECT  69.036 47.472 69.12 47.496 ;
    END
  END b_desc_base[2]
  PIN b_desc_base[3]
    DIRECTION OUTPUT ;
    USE SIGNAL ;
    PORT
      LAYER M4 ;
        RECT  69.036 47.568 69.12 47.592 ;
    END
  END b_desc_base[3]
  PIN b_desc_base[4]
    DIRECTION OUTPUT ;
    USE SIGNAL ;
    PORT
      LAYER M4 ;
        RECT  69.036 47.664 69.12 47.688 ;
    END
  END b_desc_base[4]
  PIN b_desc_base[5]
    DIRECTION OUTPUT ;
    USE SIGNAL ;
    PORT
      LAYER M4 ;
        RECT  69.036 47.76 69.12 47.784 ;
    END
  END b_desc_base[5]
  PIN b_desc_base[6]
    DIRECTION OUTPUT ;
    USE SIGNAL ;
    PORT
      LAYER M4 ;
        RECT  69.036 47.856 69.12 47.88 ;
    END
  END b_desc_base[6]
  PIN b_desc_base[7]
    DIRECTION OUTPUT ;
    USE SIGNAL ;
    PORT
      LAYER M4 ;
        RECT  69.036 47.952 69.12 47.976 ;
    END
  END b_desc_base[7]
  PIN b_desc_base[8]
    DIRECTION OUTPUT ;
    USE SIGNAL ;
    PORT
      LAYER M4 ;
        RECT  69.036 48.048 69.12 48.072 ;
    END
  END b_desc_base[8]
  PIN b_desc_base[9]
    DIRECTION OUTPUT ;
    USE SIGNAL ;
    PORT
      LAYER M4 ;
        RECT  69.036 48.144 69.12 48.168 ;
    END
  END b_desc_base[9]
  PIN b_desc_limit[0]
    DIRECTION OUTPUT ;
    USE SIGNAL ;
    PORT
      LAYER M4 ;
        RECT  69.036 39.216 69.12 39.24 ;
    END
  END b_desc_limit[0]
  PIN b_desc_limit[10]
    DIRECTION OUTPUT ;
    USE SIGNAL ;
    PORT
      LAYER M4 ;
        RECT  69.036 40.176 69.12 40.2 ;
    END
  END b_desc_limit[10]
  PIN b_desc_limit[11]
    DIRECTION OUTPUT ;
    USE SIGNAL ;
    PORT
      LAYER M4 ;
        RECT  69.036 40.272 69.12 40.296 ;
    END
  END b_desc_limit[11]
  PIN b_desc_limit[12]
    DIRECTION OUTPUT ;
    USE SIGNAL ;
    PORT
      LAYER M4 ;
        RECT  69.036 40.368 69.12 40.392 ;
    END
  END b_desc_limit[12]
  PIN b_desc_limit[1]
    DIRECTION OUTPUT ;
    USE SIGNAL ;
    PORT
      LAYER M4 ;
        RECT  69.036 39.312 69.12 39.336 ;
    END
  END b_desc_limit[1]
  PIN b_desc_limit[2]
    DIRECTION OUTPUT ;
    USE SIGNAL ;
    PORT
      LAYER M4 ;
        RECT  69.036 39.408 69.12 39.432 ;
    END
  END b_desc_limit[2]
  PIN b_desc_limit[3]
    DIRECTION OUTPUT ;
    USE SIGNAL ;
    PORT
      LAYER M4 ;
        RECT  69.036 39.504 69.12 39.528 ;
    END
  END b_desc_limit[3]
  PIN b_desc_limit[4]
    DIRECTION OUTPUT ;
    USE SIGNAL ;
    PORT
      LAYER M4 ;
        RECT  69.036 39.6 69.12 39.624 ;
    END
  END b_desc_limit[4]
  PIN b_desc_limit[5]
    DIRECTION OUTPUT ;
    USE SIGNAL ;
    PORT
      LAYER M4 ;
        RECT  69.036 39.696 69.12 39.72 ;
    END
  END b_desc_limit[5]
  PIN b_desc_limit[6]
    DIRECTION OUTPUT ;
    USE SIGNAL ;
    PORT
      LAYER M4 ;
        RECT  69.036 39.792 69.12 39.816 ;
    END
  END b_desc_limit[6]
  PIN b_desc_limit[7]
    DIRECTION OUTPUT ;
    USE SIGNAL ;
    PORT
      LAYER M4 ;
        RECT  69.036 39.888 69.12 39.912 ;
    END
  END b_desc_limit[7]
  PIN b_desc_limit[8]
    DIRECTION OUTPUT ;
    USE SIGNAL ;
    PORT
      LAYER M4 ;
        RECT  69.036 39.984 69.12 40.008 ;
    END
  END b_desc_limit[8]
  PIN b_desc_limit[9]
    DIRECTION OUTPUT ;
    USE SIGNAL ;
    PORT
      LAYER M4 ;
        RECT  69.036 40.08 69.12 40.104 ;
    END
  END b_desc_limit[9]
  PIN b_desc_loops[0]
    DIRECTION OUTPUT ;
    USE SIGNAL ;
    PORT
      LAYER M4 ;
        RECT  69.036 40.464 69.12 40.488 ;
    END
  END b_desc_loops[0]
  PIN b_desc_loops[10]
    DIRECTION OUTPUT ;
    USE SIGNAL ;
    PORT
      LAYER M4 ;
        RECT  69.036 41.424 69.12 41.448 ;
    END
  END b_desc_loops[10]
  PIN b_desc_loops[11]
    DIRECTION OUTPUT ;
    USE SIGNAL ;
    PORT
      LAYER M4 ;
        RECT  69.036 41.52 69.12 41.544 ;
    END
  END b_desc_loops[11]
  PIN b_desc_loops[12]
    DIRECTION OUTPUT ;
    USE SIGNAL ;
    PORT
      LAYER M4 ;
        RECT  69.036 41.616 69.12 41.64 ;
    END
  END b_desc_loops[12]
  PIN b_desc_loops[13]
    DIRECTION OUTPUT ;
    USE SIGNAL ;
    PORT
      LAYER M4 ;
        RECT  69.036 41.712 69.12 41.736 ;
    END
  END b_desc_loops[13]
  PIN b_desc_loops[14]
    DIRECTION OUTPUT ;
    USE SIGNAL ;
    PORT
      LAYER M4 ;
        RECT  69.036 41.808 69.12 41.832 ;
    END
  END b_desc_loops[14]
  PIN b_desc_loops[15]
    DIRECTION OUTPUT ;
    USE SIGNAL ;
    PORT
      LAYER M4 ;
        RECT  69.036 41.904 69.12 41.928 ;
    END
  END b_desc_loops[15]
  PIN b_desc_loops[1]
    DIRECTION OUTPUT ;
    USE SIGNAL ;
    PORT
      LAYER M4 ;
        RECT  69.036 40.56 69.12 40.584 ;
    END
  END b_desc_loops[1]
  PIN b_desc_loops[2]
    DIRECTION OUTPUT ;
    USE SIGNAL ;
    PORT
      LAYER M4 ;
        RECT  69.036 40.656 69.12 40.68 ;
    END
  END b_desc_loops[2]
  PIN b_desc_loops[3]
    DIRECTION OUTPUT ;
    USE SIGNAL ;
    PORT
      LAYER M4 ;
        RECT  69.036 40.752 69.12 40.776 ;
    END
  END b_desc_loops[3]
  PIN b_desc_loops[4]
    DIRECTION OUTPUT ;
    USE SIGNAL ;
    PORT
      LAYER M4 ;
        RECT  69.036 40.848 69.12 40.872 ;
    END
  END b_desc_loops[4]
  PIN b_desc_loops[5]
    DIRECTION OUTPUT ;
    USE SIGNAL ;
    PORT
      LAYER M4 ;
        RECT  69.036 40.944 69.12 40.968 ;
    END
  END b_desc_loops[5]
  PIN b_desc_loops[6]
    DIRECTION OUTPUT ;
    USE SIGNAL ;
    PORT
      LAYER M4 ;
        RECT  69.036 41.04 69.12 41.064 ;
    END
  END b_desc_loops[6]
  PIN b_desc_loops[7]
    DIRECTION OUTPUT ;
    USE SIGNAL ;
    PORT
      LAYER M4 ;
        RECT  69.036 41.136 69.12 41.16 ;
    END
  END b_desc_loops[7]
  PIN b_desc_loops[8]
    DIRECTION OUTPUT ;
    USE SIGNAL ;
    PORT
      LAYER M4 ;
        RECT  69.036 41.232 69.12 41.256 ;
    END
  END b_desc_loops[8]
  PIN b_desc_loops[9]
    DIRECTION OUTPUT ;
    USE SIGNAL ;
    PORT
      LAYER M4 ;
        RECT  69.036 41.328 69.12 41.352 ;
    END
  END b_desc_loops[9]
  PIN b_desc_v
    DIRECTION OUTPUT ;
    USE SIGNAL ;
    PORT
      LAYER M4 ;
        RECT  69.036 42 69.12 42.024 ;
    END
  END b_desc_v
  PIN b_launch_v
    DIRECTION OUTPUT ;
    USE SIGNAL ;
    PORT
      LAYER M4 ;
        RECT  69.036 42.096 69.12 42.12 ;
    END
  END b_launch_v
  PIN cfg_addr[0]
    DIRECTION INPUT ;
    USE SIGNAL ;
    PORT
      LAYER M5 ;
        RECT  43.056 69.036 43.08 69.12 ;
    END
  END cfg_addr[0]
  PIN cfg_addr[10]
    DIRECTION INPUT ;
    USE SIGNAL ;
    PORT
      LAYER M5 ;
        RECT  44.016 69.036 44.04 69.12 ;
    END
  END cfg_addr[10]
  PIN cfg_addr[11]
    DIRECTION INPUT ;
    USE SIGNAL ;
    PORT
      LAYER M5 ;
        RECT  44.112 69.036 44.136 69.12 ;
    END
  END cfg_addr[11]
  PIN cfg_addr[1]
    DIRECTION INPUT ;
    USE SIGNAL ;
    PORT
      LAYER M5 ;
        RECT  43.152 69.036 43.176 69.12 ;
    END
  END cfg_addr[1]
  PIN cfg_addr[2]
    DIRECTION INPUT ;
    USE SIGNAL ;
    PORT
      LAYER M5 ;
        RECT  43.248 69.036 43.272 69.12 ;
    END
  END cfg_addr[2]
  PIN cfg_addr[3]
    DIRECTION INPUT ;
    USE SIGNAL ;
    PORT
      LAYER M5 ;
        RECT  43.344 69.036 43.368 69.12 ;
    END
  END cfg_addr[3]
  PIN cfg_addr[4]
    DIRECTION INPUT ;
    USE SIGNAL ;
    PORT
      LAYER M5 ;
        RECT  43.44 69.036 43.464 69.12 ;
    END
  END cfg_addr[4]
  PIN cfg_addr[5]
    DIRECTION INPUT ;
    USE SIGNAL ;
    PORT
      LAYER M5 ;
        RECT  43.536 69.036 43.56 69.12 ;
    END
  END cfg_addr[5]
  PIN cfg_addr[6]
    DIRECTION INPUT ;
    USE SIGNAL ;
    PORT
      LAYER M5 ;
        RECT  43.632 69.036 43.656 69.12 ;
    END
  END cfg_addr[6]
  PIN cfg_addr[7]
    DIRECTION INPUT ;
    USE SIGNAL ;
    PORT
      LAYER M5 ;
        RECT  43.728 69.036 43.752 69.12 ;
    END
  END cfg_addr[7]
  PIN cfg_addr[8]
    DIRECTION INPUT ;
    USE SIGNAL ;
    PORT
      LAYER M5 ;
        RECT  43.824 69.036 43.848 69.12 ;
    END
  END cfg_addr[8]
  PIN cfg_addr[9]
    DIRECTION INPUT ;
    USE SIGNAL ;
    PORT
      LAYER M5 ;
        RECT  43.92 69.036 43.944 69.12 ;
    END
  END cfg_addr[9]
  PIN cfg_data[0]
    DIRECTION INPUT ;
    USE SIGNAL ;
    PORT
      LAYER M5 ;
        RECT  44.208 69.036 44.232 69.12 ;
    END
  END cfg_data[0]
  PIN cfg_data[100]
    DIRECTION INPUT ;
    USE SIGNAL ;
    PORT
      LAYER M5 ;
        RECT  47.664 69.036 47.688 69.12 ;
    END
  END cfg_data[100]
  PIN cfg_data[101]
    DIRECTION INPUT ;
    USE SIGNAL ;
    PORT
      LAYER M5 ;
        RECT  47.76 69.036 47.784 69.12 ;
    END
  END cfg_data[101]
  PIN cfg_data[102]
    DIRECTION INPUT ;
    USE SIGNAL ;
    PORT
      LAYER M5 ;
        RECT  47.856 69.036 47.88 69.12 ;
    END
  END cfg_data[102]
  PIN cfg_data[103]
    DIRECTION INPUT ;
    USE SIGNAL ;
    PORT
      LAYER M5 ;
        RECT  47.952 69.036 47.976 69.12 ;
    END
  END cfg_data[103]
  PIN cfg_data[104]
    DIRECTION INPUT ;
    USE SIGNAL ;
    PORT
      LAYER M5 ;
        RECT  48.048 69.036 48.072 69.12 ;
    END
  END cfg_data[104]
  PIN cfg_data[105]
    DIRECTION INPUT ;
    USE SIGNAL ;
    PORT
      LAYER M5 ;
        RECT  48.144 69.036 48.168 69.12 ;
    END
  END cfg_data[105]
  PIN cfg_data[106]
    DIRECTION INPUT ;
    USE SIGNAL ;
    PORT
      LAYER M5 ;
        RECT  48.24 69.036 48.264 69.12 ;
    END
  END cfg_data[106]
  PIN cfg_data[107]
    DIRECTION INPUT ;
    USE SIGNAL ;
    PORT
      LAYER M5 ;
        RECT  48.336 69.036 48.36 69.12 ;
    END
  END cfg_data[107]
  PIN cfg_data[108]
    DIRECTION INPUT ;
    USE SIGNAL ;
    PORT
      LAYER M5 ;
        RECT  48.432 69.036 48.456 69.12 ;
    END
  END cfg_data[108]
  PIN cfg_data[109]
    DIRECTION INPUT ;
    USE SIGNAL ;
    PORT
      LAYER M5 ;
        RECT  48.528 69.036 48.552 69.12 ;
    END
  END cfg_data[109]
  PIN cfg_data[10]
    DIRECTION INPUT ;
    USE SIGNAL ;
    PORT
      LAYER M5 ;
        RECT  45.168 69.036 45.192 69.12 ;
    END
  END cfg_data[10]
  PIN cfg_data[110]
    DIRECTION INPUT ;
    USE SIGNAL ;
    PORT
      LAYER M5 ;
        RECT  48.624 69.036 48.648 69.12 ;
    END
  END cfg_data[110]
  PIN cfg_data[111]
    DIRECTION INPUT ;
    USE SIGNAL ;
    PORT
      LAYER M5 ;
        RECT  48.72 69.036 48.744 69.12 ;
    END
  END cfg_data[111]
  PIN cfg_data[112]
    DIRECTION INPUT ;
    USE SIGNAL ;
    PORT
      LAYER M5 ;
        RECT  48.816 69.036 48.84 69.12 ;
    END
  END cfg_data[112]
  PIN cfg_data[113]
    DIRECTION INPUT ;
    USE SIGNAL ;
    PORT
      LAYER M5 ;
        RECT  48.912 69.036 48.936 69.12 ;
    END
  END cfg_data[113]
  PIN cfg_data[114]
    DIRECTION INPUT ;
    USE SIGNAL ;
    PORT
      LAYER M5 ;
        RECT  49.008 69.036 49.032 69.12 ;
    END
  END cfg_data[114]
  PIN cfg_data[115]
    DIRECTION INPUT ;
    USE SIGNAL ;
    PORT
      LAYER M5 ;
        RECT  49.104 69.036 49.128 69.12 ;
    END
  END cfg_data[115]
  PIN cfg_data[116]
    DIRECTION INPUT ;
    USE SIGNAL ;
    PORT
      LAYER M5 ;
        RECT  39.984 69.036 40.008 69.12 ;
    END
  END cfg_data[116]
  PIN cfg_data[117]
    DIRECTION INPUT ;
    USE SIGNAL ;
    PORT
      LAYER M5 ;
        RECT  40.08 69.036 40.104 69.12 ;
    END
  END cfg_data[117]
  PIN cfg_data[118]
    DIRECTION INPUT ;
    USE SIGNAL ;
    PORT
      LAYER M5 ;
        RECT  40.176 69.036 40.2 69.12 ;
    END
  END cfg_data[118]
  PIN cfg_data[119]
    DIRECTION INPUT ;
    USE SIGNAL ;
    PORT
      LAYER M5 ;
        RECT  40.272 69.036 40.296 69.12 ;
    END
  END cfg_data[119]
  PIN cfg_data[11]
    DIRECTION INPUT ;
    USE SIGNAL ;
    PORT
      LAYER M5 ;
        RECT  45.264 69.036 45.288 69.12 ;
    END
  END cfg_data[11]
  PIN cfg_data[120]
    DIRECTION INPUT ;
    USE SIGNAL ;
    PORT
      LAYER M5 ;
        RECT  40.368 69.036 40.392 69.12 ;
    END
  END cfg_data[120]
  PIN cfg_data[121]
    DIRECTION INPUT ;
    USE SIGNAL ;
    PORT
      LAYER M5 ;
        RECT  40.464 69.036 40.488 69.12 ;
    END
  END cfg_data[121]
  PIN cfg_data[122]
    DIRECTION INPUT ;
    USE SIGNAL ;
    PORT
      LAYER M5 ;
        RECT  40.56 69.036 40.584 69.12 ;
    END
  END cfg_data[122]
  PIN cfg_data[123]
    DIRECTION INPUT ;
    USE SIGNAL ;
    PORT
      LAYER M5 ;
        RECT  40.656 69.036 40.68 69.12 ;
    END
  END cfg_data[123]
  PIN cfg_data[124]
    DIRECTION INPUT ;
    USE SIGNAL ;
    PORT
      LAYER M5 ;
        RECT  40.752 69.036 40.776 69.12 ;
    END
  END cfg_data[124]
  PIN cfg_data[125]
    DIRECTION INPUT ;
    USE SIGNAL ;
    PORT
      LAYER M5 ;
        RECT  40.848 69.036 40.872 69.12 ;
    END
  END cfg_data[125]
  PIN cfg_data[126]
    DIRECTION INPUT ;
    USE SIGNAL ;
    PORT
      LAYER M5 ;
        RECT  40.944 69.036 40.968 69.12 ;
    END
  END cfg_data[126]
  PIN cfg_data[127]
    DIRECTION INPUT ;
    USE SIGNAL ;
    PORT
      LAYER M5 ;
        RECT  41.04 69.036 41.064 69.12 ;
    END
  END cfg_data[127]
  PIN cfg_data[128]
    DIRECTION INPUT ;
    USE SIGNAL ;
    PORT
      LAYER M5 ;
        RECT  41.136 69.036 41.16 69.12 ;
    END
  END cfg_data[128]
  PIN cfg_data[129]
    DIRECTION INPUT ;
    USE SIGNAL ;
    PORT
      LAYER M5 ;
        RECT  41.232 69.036 41.256 69.12 ;
    END
  END cfg_data[129]
  PIN cfg_data[12]
    DIRECTION INPUT ;
    USE SIGNAL ;
    PORT
      LAYER M5 ;
        RECT  45.36 69.036 45.384 69.12 ;
    END
  END cfg_data[12]
  PIN cfg_data[130]
    DIRECTION INPUT ;
    USE SIGNAL ;
    PORT
      LAYER M5 ;
        RECT  41.328 69.036 41.352 69.12 ;
    END
  END cfg_data[130]
  PIN cfg_data[131]
    DIRECTION INPUT ;
    USE SIGNAL ;
    PORT
      LAYER M5 ;
        RECT  41.424 69.036 41.448 69.12 ;
    END
  END cfg_data[131]
  PIN cfg_data[132]
    DIRECTION INPUT ;
    USE SIGNAL ;
    PORT
      LAYER M5 ;
        RECT  41.52 69.036 41.544 69.12 ;
    END
  END cfg_data[132]
  PIN cfg_data[133]
    DIRECTION INPUT ;
    USE SIGNAL ;
    PORT
      LAYER M5 ;
        RECT  41.616 69.036 41.64 69.12 ;
    END
  END cfg_data[133]
  PIN cfg_data[134]
    DIRECTION INPUT ;
    USE SIGNAL ;
    PORT
      LAYER M5 ;
        RECT  41.712 69.036 41.736 69.12 ;
    END
  END cfg_data[134]
  PIN cfg_data[135]
    DIRECTION INPUT ;
    USE SIGNAL ;
    PORT
      LAYER M5 ;
        RECT  41.808 69.036 41.832 69.12 ;
    END
  END cfg_data[135]
  PIN cfg_data[136]
    DIRECTION INPUT ;
    USE SIGNAL ;
    PORT
      LAYER M5 ;
        RECT  41.904 69.036 41.928 69.12 ;
    END
  END cfg_data[136]
  PIN cfg_data[137]
    DIRECTION INPUT ;
    USE SIGNAL ;
    PORT
      LAYER M5 ;
        RECT  42 69.036 42.024 69.12 ;
    END
  END cfg_data[137]
  PIN cfg_data[138]
    DIRECTION INPUT ;
    USE SIGNAL ;
    PORT
      LAYER M5 ;
        RECT  42.096 69.036 42.12 69.12 ;
    END
  END cfg_data[138]
  PIN cfg_data[139]
    DIRECTION INPUT ;
    USE SIGNAL ;
    PORT
      LAYER M5 ;
        RECT  42.192 69.036 42.216 69.12 ;
    END
  END cfg_data[139]
  PIN cfg_data[13]
    DIRECTION INPUT ;
    USE SIGNAL ;
    PORT
      LAYER M5 ;
        RECT  45.456 69.036 45.48 69.12 ;
    END
  END cfg_data[13]
  PIN cfg_data[140]
    DIRECTION INPUT ;
    USE SIGNAL ;
    PORT
      LAYER M5 ;
        RECT  42.288 69.036 42.312 69.12 ;
    END
  END cfg_data[140]
  PIN cfg_data[141]
    DIRECTION INPUT ;
    USE SIGNAL ;
    PORT
      LAYER M5 ;
        RECT  42.384 69.036 42.408 69.12 ;
    END
  END cfg_data[141]
  PIN cfg_data[142]
    DIRECTION INPUT ;
    USE SIGNAL ;
    PORT
      LAYER M5 ;
        RECT  42.48 69.036 42.504 69.12 ;
    END
  END cfg_data[142]
  PIN cfg_data[143]
    DIRECTION INPUT ;
    USE SIGNAL ;
    PORT
      LAYER M5 ;
        RECT  42.576 69.036 42.6 69.12 ;
    END
  END cfg_data[143]
  PIN cfg_data[144]
    DIRECTION INPUT ;
    USE SIGNAL ;
    PORT
      LAYER M5 ;
        RECT  42.672 69.036 42.696 69.12 ;
    END
  END cfg_data[144]
  PIN cfg_data[145]
    DIRECTION INPUT ;
    USE SIGNAL ;
    PORT
      LAYER M5 ;
        RECT  42.768 69.036 42.792 69.12 ;
    END
  END cfg_data[145]
  PIN cfg_data[146]
    DIRECTION INPUT ;
    USE SIGNAL ;
    PORT
      LAYER M5 ;
        RECT  42.864 69.036 42.888 69.12 ;
    END
  END cfg_data[146]
  PIN cfg_data[147]
    DIRECTION INPUT ;
    USE SIGNAL ;
    PORT
      LAYER M5 ;
        RECT  42.96 69.036 42.984 69.12 ;
    END
  END cfg_data[147]
  PIN cfg_data[148]
    DIRECTION INPUT ;
    USE SIGNAL ;
    PORT
      LAYER M5 ;
        RECT  36.912 69.036 36.936 69.12 ;
    END
  END cfg_data[148]
  PIN cfg_data[149]
    DIRECTION INPUT ;
    USE SIGNAL ;
    PORT
      LAYER M5 ;
        RECT  37.008 69.036 37.032 69.12 ;
    END
  END cfg_data[149]
  PIN cfg_data[14]
    DIRECTION INPUT ;
    USE SIGNAL ;
    PORT
      LAYER M5 ;
        RECT  45.552 69.036 45.576 69.12 ;
    END
  END cfg_data[14]
  PIN cfg_data[150]
    DIRECTION INPUT ;
    USE SIGNAL ;
    PORT
      LAYER M5 ;
        RECT  37.104 69.036 37.128 69.12 ;
    END
  END cfg_data[150]
  PIN cfg_data[151]
    DIRECTION INPUT ;
    USE SIGNAL ;
    PORT
      LAYER M5 ;
        RECT  37.2 69.036 37.224 69.12 ;
    END
  END cfg_data[151]
  PIN cfg_data[152]
    DIRECTION INPUT ;
    USE SIGNAL ;
    PORT
      LAYER M5 ;
        RECT  37.296 69.036 37.32 69.12 ;
    END
  END cfg_data[152]
  PIN cfg_data[153]
    DIRECTION INPUT ;
    USE SIGNAL ;
    PORT
      LAYER M5 ;
        RECT  37.392 69.036 37.416 69.12 ;
    END
  END cfg_data[153]
  PIN cfg_data[154]
    DIRECTION INPUT ;
    USE SIGNAL ;
    PORT
      LAYER M5 ;
        RECT  37.488 69.036 37.512 69.12 ;
    END
  END cfg_data[154]
  PIN cfg_data[155]
    DIRECTION INPUT ;
    USE SIGNAL ;
    PORT
      LAYER M5 ;
        RECT  37.584 69.036 37.608 69.12 ;
    END
  END cfg_data[155]
  PIN cfg_data[156]
    DIRECTION INPUT ;
    USE SIGNAL ;
    PORT
      LAYER M5 ;
        RECT  37.68 69.036 37.704 69.12 ;
    END
  END cfg_data[156]
  PIN cfg_data[157]
    DIRECTION INPUT ;
    USE SIGNAL ;
    PORT
      LAYER M5 ;
        RECT  37.776 69.036 37.8 69.12 ;
    END
  END cfg_data[157]
  PIN cfg_data[158]
    DIRECTION INPUT ;
    USE SIGNAL ;
    PORT
      LAYER M5 ;
        RECT  37.872 69.036 37.896 69.12 ;
    END
  END cfg_data[158]
  PIN cfg_data[159]
    DIRECTION INPUT ;
    USE SIGNAL ;
    PORT
      LAYER M5 ;
        RECT  37.968 69.036 37.992 69.12 ;
    END
  END cfg_data[159]
  PIN cfg_data[15]
    DIRECTION INPUT ;
    USE SIGNAL ;
    PORT
      LAYER M5 ;
        RECT  45.648 69.036 45.672 69.12 ;
    END
  END cfg_data[15]
  PIN cfg_data[160]
    DIRECTION INPUT ;
    USE SIGNAL ;
    PORT
      LAYER M5 ;
        RECT  38.064 69.036 38.088 69.12 ;
    END
  END cfg_data[160]
  PIN cfg_data[161]
    DIRECTION INPUT ;
    USE SIGNAL ;
    PORT
      LAYER M5 ;
        RECT  38.16 69.036 38.184 69.12 ;
    END
  END cfg_data[161]
  PIN cfg_data[162]
    DIRECTION INPUT ;
    USE SIGNAL ;
    PORT
      LAYER M5 ;
        RECT  38.256 69.036 38.28 69.12 ;
    END
  END cfg_data[162]
  PIN cfg_data[163]
    DIRECTION INPUT ;
    USE SIGNAL ;
    PORT
      LAYER M5 ;
        RECT  38.352 69.036 38.376 69.12 ;
    END
  END cfg_data[163]
  PIN cfg_data[164]
    DIRECTION INPUT ;
    USE SIGNAL ;
    PORT
      LAYER M5 ;
        RECT  38.448 69.036 38.472 69.12 ;
    END
  END cfg_data[164]
  PIN cfg_data[165]
    DIRECTION INPUT ;
    USE SIGNAL ;
    PORT
      LAYER M5 ;
        RECT  38.544 69.036 38.568 69.12 ;
    END
  END cfg_data[165]
  PIN cfg_data[166]
    DIRECTION INPUT ;
    USE SIGNAL ;
    PORT
      LAYER M5 ;
        RECT  38.64 69.036 38.664 69.12 ;
    END
  END cfg_data[166]
  PIN cfg_data[167]
    DIRECTION INPUT ;
    USE SIGNAL ;
    PORT
      LAYER M5 ;
        RECT  38.736 69.036 38.76 69.12 ;
    END
  END cfg_data[167]
  PIN cfg_data[168]
    DIRECTION INPUT ;
    USE SIGNAL ;
    PORT
      LAYER M5 ;
        RECT  38.832 69.036 38.856 69.12 ;
    END
  END cfg_data[168]
  PIN cfg_data[169]
    DIRECTION INPUT ;
    USE SIGNAL ;
    PORT
      LAYER M5 ;
        RECT  38.928 69.036 38.952 69.12 ;
    END
  END cfg_data[169]
  PIN cfg_data[16]
    DIRECTION INPUT ;
    USE SIGNAL ;
    PORT
      LAYER M5 ;
        RECT  45.744 69.036 45.768 69.12 ;
    END
  END cfg_data[16]
  PIN cfg_data[170]
    DIRECTION INPUT ;
    USE SIGNAL ;
    PORT
      LAYER M5 ;
        RECT  39.024 69.036 39.048 69.12 ;
    END
  END cfg_data[170]
  PIN cfg_data[171]
    DIRECTION INPUT ;
    USE SIGNAL ;
    PORT
      LAYER M5 ;
        RECT  39.12 69.036 39.144 69.12 ;
    END
  END cfg_data[171]
  PIN cfg_data[172]
    DIRECTION INPUT ;
    USE SIGNAL ;
    PORT
      LAYER M5 ;
        RECT  39.216 69.036 39.24 69.12 ;
    END
  END cfg_data[172]
  PIN cfg_data[173]
    DIRECTION INPUT ;
    USE SIGNAL ;
    PORT
      LAYER M5 ;
        RECT  39.312 69.036 39.336 69.12 ;
    END
  END cfg_data[173]
  PIN cfg_data[174]
    DIRECTION INPUT ;
    USE SIGNAL ;
    PORT
      LAYER M5 ;
        RECT  39.408 69.036 39.432 69.12 ;
    END
  END cfg_data[174]
  PIN cfg_data[175]
    DIRECTION INPUT ;
    USE SIGNAL ;
    PORT
      LAYER M5 ;
        RECT  39.504 69.036 39.528 69.12 ;
    END
  END cfg_data[175]
  PIN cfg_data[176]
    DIRECTION INPUT ;
    USE SIGNAL ;
    PORT
      LAYER M5 ;
        RECT  39.6 69.036 39.624 69.12 ;
    END
  END cfg_data[176]
  PIN cfg_data[177]
    DIRECTION INPUT ;
    USE SIGNAL ;
    PORT
      LAYER M5 ;
        RECT  39.696 69.036 39.72 69.12 ;
    END
  END cfg_data[177]
  PIN cfg_data[178]
    DIRECTION INPUT ;
    USE SIGNAL ;
    PORT
      LAYER M5 ;
        RECT  39.792 69.036 39.816 69.12 ;
    END
  END cfg_data[178]
  PIN cfg_data[179]
    DIRECTION INPUT ;
    USE SIGNAL ;
    PORT
      LAYER M5 ;
        RECT  39.888 69.036 39.912 69.12 ;
    END
  END cfg_data[179]
  PIN cfg_data[17]
    DIRECTION INPUT ;
    USE SIGNAL ;
    PORT
      LAYER M5 ;
        RECT  45.84 69.036 45.864 69.12 ;
    END
  END cfg_data[17]
  PIN cfg_data[180]
    DIRECTION INPUT ;
    USE SIGNAL ;
    PORT
      LAYER M5 ;
        RECT  30.768 69.036 30.792 69.12 ;
    END
  END cfg_data[180]
  PIN cfg_data[181]
    DIRECTION INPUT ;
    USE SIGNAL ;
    PORT
      LAYER M5 ;
        RECT  30.864 69.036 30.888 69.12 ;
    END
  END cfg_data[181]
  PIN cfg_data[182]
    DIRECTION INPUT ;
    USE SIGNAL ;
    PORT
      LAYER M5 ;
        RECT  30.96 69.036 30.984 69.12 ;
    END
  END cfg_data[182]
  PIN cfg_data[183]
    DIRECTION INPUT ;
    USE SIGNAL ;
    PORT
      LAYER M5 ;
        RECT  31.056 69.036 31.08 69.12 ;
    END
  END cfg_data[183]
  PIN cfg_data[184]
    DIRECTION INPUT ;
    USE SIGNAL ;
    PORT
      LAYER M5 ;
        RECT  31.152 69.036 31.176 69.12 ;
    END
  END cfg_data[184]
  PIN cfg_data[185]
    DIRECTION INPUT ;
    USE SIGNAL ;
    PORT
      LAYER M5 ;
        RECT  31.248 69.036 31.272 69.12 ;
    END
  END cfg_data[185]
  PIN cfg_data[186]
    DIRECTION INPUT ;
    USE SIGNAL ;
    PORT
      LAYER M5 ;
        RECT  31.344 69.036 31.368 69.12 ;
    END
  END cfg_data[186]
  PIN cfg_data[187]
    DIRECTION INPUT ;
    USE SIGNAL ;
    PORT
      LAYER M5 ;
        RECT  31.44 69.036 31.464 69.12 ;
    END
  END cfg_data[187]
  PIN cfg_data[188]
    DIRECTION INPUT ;
    USE SIGNAL ;
    PORT
      LAYER M5 ;
        RECT  31.536 69.036 31.56 69.12 ;
    END
  END cfg_data[188]
  PIN cfg_data[189]
    DIRECTION INPUT ;
    USE SIGNAL ;
    PORT
      LAYER M5 ;
        RECT  31.632 69.036 31.656 69.12 ;
    END
  END cfg_data[189]
  PIN cfg_data[18]
    DIRECTION INPUT ;
    USE SIGNAL ;
    PORT
      LAYER M5 ;
        RECT  45.936 69.036 45.96 69.12 ;
    END
  END cfg_data[18]
  PIN cfg_data[190]
    DIRECTION INPUT ;
    USE SIGNAL ;
    PORT
      LAYER M5 ;
        RECT  31.728 69.036 31.752 69.12 ;
    END
  END cfg_data[190]
  PIN cfg_data[191]
    DIRECTION INPUT ;
    USE SIGNAL ;
    PORT
      LAYER M5 ;
        RECT  31.824 69.036 31.848 69.12 ;
    END
  END cfg_data[191]
  PIN cfg_data[192]
    DIRECTION INPUT ;
    USE SIGNAL ;
    PORT
      LAYER M5 ;
        RECT  31.92 69.036 31.944 69.12 ;
    END
  END cfg_data[192]
  PIN cfg_data[193]
    DIRECTION INPUT ;
    USE SIGNAL ;
    PORT
      LAYER M5 ;
        RECT  32.016 69.036 32.04 69.12 ;
    END
  END cfg_data[193]
  PIN cfg_data[194]
    DIRECTION INPUT ;
    USE SIGNAL ;
    PORT
      LAYER M5 ;
        RECT  32.112 69.036 32.136 69.12 ;
    END
  END cfg_data[194]
  PIN cfg_data[195]
    DIRECTION INPUT ;
    USE SIGNAL ;
    PORT
      LAYER M5 ;
        RECT  32.208 69.036 32.232 69.12 ;
    END
  END cfg_data[195]
  PIN cfg_data[196]
    DIRECTION INPUT ;
    USE SIGNAL ;
    PORT
      LAYER M5 ;
        RECT  32.304 69.036 32.328 69.12 ;
    END
  END cfg_data[196]
  PIN cfg_data[197]
    DIRECTION INPUT ;
    USE SIGNAL ;
    PORT
      LAYER M5 ;
        RECT  32.4 69.036 32.424 69.12 ;
    END
  END cfg_data[197]
  PIN cfg_data[198]
    DIRECTION INPUT ;
    USE SIGNAL ;
    PORT
      LAYER M5 ;
        RECT  32.496 69.036 32.52 69.12 ;
    END
  END cfg_data[198]
  PIN cfg_data[199]
    DIRECTION INPUT ;
    USE SIGNAL ;
    PORT
      LAYER M5 ;
        RECT  32.592 69.036 32.616 69.12 ;
    END
  END cfg_data[199]
  PIN cfg_data[19]
    DIRECTION INPUT ;
    USE SIGNAL ;
    PORT
      LAYER M5 ;
        RECT  46.032 69.036 46.056 69.12 ;
    END
  END cfg_data[19]
  PIN cfg_data[1]
    DIRECTION INPUT ;
    USE SIGNAL ;
    PORT
      LAYER M5 ;
        RECT  44.304 69.036 44.328 69.12 ;
    END
  END cfg_data[1]
  PIN cfg_data[200]
    DIRECTION INPUT ;
    USE SIGNAL ;
    PORT
      LAYER M5 ;
        RECT  32.688 69.036 32.712 69.12 ;
    END
  END cfg_data[200]
  PIN cfg_data[201]
    DIRECTION INPUT ;
    USE SIGNAL ;
    PORT
      LAYER M5 ;
        RECT  32.784 69.036 32.808 69.12 ;
    END
  END cfg_data[201]
  PIN cfg_data[202]
    DIRECTION INPUT ;
    USE SIGNAL ;
    PORT
      LAYER M5 ;
        RECT  32.88 69.036 32.904 69.12 ;
    END
  END cfg_data[202]
  PIN cfg_data[203]
    DIRECTION INPUT ;
    USE SIGNAL ;
    PORT
      LAYER M5 ;
        RECT  32.976 69.036 33 69.12 ;
    END
  END cfg_data[203]
  PIN cfg_data[204]
    DIRECTION INPUT ;
    USE SIGNAL ;
    PORT
      LAYER M5 ;
        RECT  33.072 69.036 33.096 69.12 ;
    END
  END cfg_data[204]
  PIN cfg_data[205]
    DIRECTION INPUT ;
    USE SIGNAL ;
    PORT
      LAYER M5 ;
        RECT  33.168 69.036 33.192 69.12 ;
    END
  END cfg_data[205]
  PIN cfg_data[206]
    DIRECTION INPUT ;
    USE SIGNAL ;
    PORT
      LAYER M5 ;
        RECT  33.264 69.036 33.288 69.12 ;
    END
  END cfg_data[206]
  PIN cfg_data[207]
    DIRECTION INPUT ;
    USE SIGNAL ;
    PORT
      LAYER M5 ;
        RECT  33.36 69.036 33.384 69.12 ;
    END
  END cfg_data[207]
  PIN cfg_data[208]
    DIRECTION INPUT ;
    USE SIGNAL ;
    PORT
      LAYER M5 ;
        RECT  33.456 69.036 33.48 69.12 ;
    END
  END cfg_data[208]
  PIN cfg_data[209]
    DIRECTION INPUT ;
    USE SIGNAL ;
    PORT
      LAYER M5 ;
        RECT  33.552 69.036 33.576 69.12 ;
    END
  END cfg_data[209]
  PIN cfg_data[20]
    DIRECTION INPUT ;
    USE SIGNAL ;
    PORT
      LAYER M5 ;
        RECT  33.84 69.036 33.864 69.12 ;
    END
  END cfg_data[20]
  PIN cfg_data[210]
    DIRECTION INPUT ;
    USE SIGNAL ;
    PORT
      LAYER M5 ;
        RECT  33.648 69.036 33.672 69.12 ;
    END
  END cfg_data[210]
  PIN cfg_data[211]
    DIRECTION INPUT ;
    USE SIGNAL ;
    PORT
      LAYER M5 ;
        RECT  33.744 69.036 33.768 69.12 ;
    END
  END cfg_data[211]
  PIN cfg_data[212]
    DIRECTION INPUT ;
    USE SIGNAL ;
    PORT
      LAYER M5 ;
        RECT  26.928 69.036 26.952 69.12 ;
    END
  END cfg_data[212]
  PIN cfg_data[213]
    DIRECTION INPUT ;
    USE SIGNAL ;
    PORT
      LAYER M5 ;
        RECT  27.024 69.036 27.048 69.12 ;
    END
  END cfg_data[213]
  PIN cfg_data[214]
    DIRECTION INPUT ;
    USE SIGNAL ;
    PORT
      LAYER M5 ;
        RECT  27.12 69.036 27.144 69.12 ;
    END
  END cfg_data[214]
  PIN cfg_data[215]
    DIRECTION INPUT ;
    USE SIGNAL ;
    PORT
      LAYER M5 ;
        RECT  27.216 69.036 27.24 69.12 ;
    END
  END cfg_data[215]
  PIN cfg_data[216]
    DIRECTION INPUT ;
    USE SIGNAL ;
    PORT
      LAYER M5 ;
        RECT  27.312 69.036 27.336 69.12 ;
    END
  END cfg_data[216]
  PIN cfg_data[217]
    DIRECTION INPUT ;
    USE SIGNAL ;
    PORT
      LAYER M5 ;
        RECT  27.408 69.036 27.432 69.12 ;
    END
  END cfg_data[217]
  PIN cfg_data[218]
    DIRECTION INPUT ;
    USE SIGNAL ;
    PORT
      LAYER M5 ;
        RECT  27.504 69.036 27.528 69.12 ;
    END
  END cfg_data[218]
  PIN cfg_data[219]
    DIRECTION INPUT ;
    USE SIGNAL ;
    PORT
      LAYER M5 ;
        RECT  27.6 69.036 27.624 69.12 ;
    END
  END cfg_data[219]
  PIN cfg_data[21]
    DIRECTION INPUT ;
    USE SIGNAL ;
    PORT
      LAYER M5 ;
        RECT  33.936 69.036 33.96 69.12 ;
    END
  END cfg_data[21]
  PIN cfg_data[220]
    DIRECTION INPUT ;
    USE SIGNAL ;
    PORT
      LAYER M5 ;
        RECT  27.696 69.036 27.72 69.12 ;
    END
  END cfg_data[220]
  PIN cfg_data[221]
    DIRECTION INPUT ;
    USE SIGNAL ;
    PORT
      LAYER M5 ;
        RECT  27.792 69.036 27.816 69.12 ;
    END
  END cfg_data[221]
  PIN cfg_data[222]
    DIRECTION INPUT ;
    USE SIGNAL ;
    PORT
      LAYER M5 ;
        RECT  27.888 69.036 27.912 69.12 ;
    END
  END cfg_data[222]
  PIN cfg_data[223]
    DIRECTION INPUT ;
    USE SIGNAL ;
    PORT
      LAYER M5 ;
        RECT  27.984 69.036 28.008 69.12 ;
    END
  END cfg_data[223]
  PIN cfg_data[224]
    DIRECTION INPUT ;
    USE SIGNAL ;
    PORT
      LAYER M5 ;
        RECT  28.08 69.036 28.104 69.12 ;
    END
  END cfg_data[224]
  PIN cfg_data[225]
    DIRECTION INPUT ;
    USE SIGNAL ;
    PORT
      LAYER M5 ;
        RECT  28.176 69.036 28.2 69.12 ;
    END
  END cfg_data[225]
  PIN cfg_data[226]
    DIRECTION INPUT ;
    USE SIGNAL ;
    PORT
      LAYER M5 ;
        RECT  28.272 69.036 28.296 69.12 ;
    END
  END cfg_data[226]
  PIN cfg_data[227]
    DIRECTION INPUT ;
    USE SIGNAL ;
    PORT
      LAYER M5 ;
        RECT  28.368 69.036 28.392 69.12 ;
    END
  END cfg_data[227]
  PIN cfg_data[228]
    DIRECTION INPUT ;
    USE SIGNAL ;
    PORT
      LAYER M5 ;
        RECT  28.464 69.036 28.488 69.12 ;
    END
  END cfg_data[228]
  PIN cfg_data[229]
    DIRECTION INPUT ;
    USE SIGNAL ;
    PORT
      LAYER M5 ;
        RECT  28.56 69.036 28.584 69.12 ;
    END
  END cfg_data[229]
  PIN cfg_data[22]
    DIRECTION INPUT ;
    USE SIGNAL ;
    PORT
      LAYER M5 ;
        RECT  34.032 69.036 34.056 69.12 ;
    END
  END cfg_data[22]
  PIN cfg_data[230]
    DIRECTION INPUT ;
    USE SIGNAL ;
    PORT
      LAYER M5 ;
        RECT  28.656 69.036 28.68 69.12 ;
    END
  END cfg_data[230]
  PIN cfg_data[231]
    DIRECTION INPUT ;
    USE SIGNAL ;
    PORT
      LAYER M5 ;
        RECT  28.752 69.036 28.776 69.12 ;
    END
  END cfg_data[231]
  PIN cfg_data[232]
    DIRECTION INPUT ;
    USE SIGNAL ;
    PORT
      LAYER M5 ;
        RECT  28.848 69.036 28.872 69.12 ;
    END
  END cfg_data[232]
  PIN cfg_data[233]
    DIRECTION INPUT ;
    USE SIGNAL ;
    PORT
      LAYER M5 ;
        RECT  28.944 69.036 28.968 69.12 ;
    END
  END cfg_data[233]
  PIN cfg_data[234]
    DIRECTION INPUT ;
    USE SIGNAL ;
    PORT
      LAYER M5 ;
        RECT  29.04 69.036 29.064 69.12 ;
    END
  END cfg_data[234]
  PIN cfg_data[235]
    DIRECTION INPUT ;
    USE SIGNAL ;
    PORT
      LAYER M5 ;
        RECT  29.136 69.036 29.16 69.12 ;
    END
  END cfg_data[235]
  PIN cfg_data[236]
    DIRECTION INPUT ;
    USE SIGNAL ;
    PORT
      LAYER M5 ;
        RECT  29.232 69.036 29.256 69.12 ;
    END
  END cfg_data[236]
  PIN cfg_data[237]
    DIRECTION INPUT ;
    USE SIGNAL ;
    PORT
      LAYER M5 ;
        RECT  29.328 69.036 29.352 69.12 ;
    END
  END cfg_data[237]
  PIN cfg_data[238]
    DIRECTION INPUT ;
    USE SIGNAL ;
    PORT
      LAYER M5 ;
        RECT  29.424 69.036 29.448 69.12 ;
    END
  END cfg_data[238]
  PIN cfg_data[239]
    DIRECTION INPUT ;
    USE SIGNAL ;
    PORT
      LAYER M5 ;
        RECT  29.52 69.036 29.544 69.12 ;
    END
  END cfg_data[239]
  PIN cfg_data[23]
    DIRECTION INPUT ;
    USE SIGNAL ;
    PORT
      LAYER M5 ;
        RECT  34.128 69.036 34.152 69.12 ;
    END
  END cfg_data[23]
  PIN cfg_data[240]
    DIRECTION INPUT ;
    USE SIGNAL ;
    PORT
      LAYER M5 ;
        RECT  29.616 69.036 29.64 69.12 ;
    END
  END cfg_data[240]
  PIN cfg_data[241]
    DIRECTION INPUT ;
    USE SIGNAL ;
    PORT
      LAYER M5 ;
        RECT  29.712 69.036 29.736 69.12 ;
    END
  END cfg_data[241]
  PIN cfg_data[242]
    DIRECTION INPUT ;
    USE SIGNAL ;
    PORT
      LAYER M5 ;
        RECT  29.808 69.036 29.832 69.12 ;
    END
  END cfg_data[242]
  PIN cfg_data[243]
    DIRECTION INPUT ;
    USE SIGNAL ;
    PORT
      LAYER M5 ;
        RECT  29.904 69.036 29.928 69.12 ;
    END
  END cfg_data[243]
  PIN cfg_data[244]
    DIRECTION INPUT ;
    USE SIGNAL ;
    PORT
      LAYER M5 ;
        RECT  17.712 69.036 17.736 69.12 ;
    END
  END cfg_data[244]
  PIN cfg_data[245]
    DIRECTION INPUT ;
    USE SIGNAL ;
    PORT
      LAYER M5 ;
        RECT  17.808 69.036 17.832 69.12 ;
    END
  END cfg_data[245]
  PIN cfg_data[246]
    DIRECTION INPUT ;
    USE SIGNAL ;
    PORT
      LAYER M5 ;
        RECT  17.904 69.036 17.928 69.12 ;
    END
  END cfg_data[246]
  PIN cfg_data[247]
    DIRECTION INPUT ;
    USE SIGNAL ;
    PORT
      LAYER M5 ;
        RECT  18 69.036 18.024 69.12 ;
    END
  END cfg_data[247]
  PIN cfg_data[248]
    DIRECTION INPUT ;
    USE SIGNAL ;
    PORT
      LAYER M5 ;
        RECT  18.096 69.036 18.12 69.12 ;
    END
  END cfg_data[248]
  PIN cfg_data[249]
    DIRECTION INPUT ;
    USE SIGNAL ;
    PORT
      LAYER M5 ;
        RECT  18.192 69.036 18.216 69.12 ;
    END
  END cfg_data[249]
  PIN cfg_data[24]
    DIRECTION INPUT ;
    USE SIGNAL ;
    PORT
      LAYER M5 ;
        RECT  34.224 69.036 34.248 69.12 ;
    END
  END cfg_data[24]
  PIN cfg_data[250]
    DIRECTION INPUT ;
    USE SIGNAL ;
    PORT
      LAYER M5 ;
        RECT  18.288 69.036 18.312 69.12 ;
    END
  END cfg_data[250]
  PIN cfg_data[251]
    DIRECTION INPUT ;
    USE SIGNAL ;
    PORT
      LAYER M5 ;
        RECT  18.384 69.036 18.408 69.12 ;
    END
  END cfg_data[251]
  PIN cfg_data[252]
    DIRECTION INPUT ;
    USE SIGNAL ;
    PORT
      LAYER M5 ;
        RECT  18.48 69.036 18.504 69.12 ;
    END
  END cfg_data[252]
  PIN cfg_data[253]
    DIRECTION INPUT ;
    USE SIGNAL ;
    PORT
      LAYER M5 ;
        RECT  18.576 69.036 18.6 69.12 ;
    END
  END cfg_data[253]
  PIN cfg_data[254]
    DIRECTION INPUT ;
    USE SIGNAL ;
    PORT
      LAYER M5 ;
        RECT  18.672 69.036 18.696 69.12 ;
    END
  END cfg_data[254]
  PIN cfg_data[255]
    DIRECTION INPUT ;
    USE SIGNAL ;
    PORT
      LAYER M5 ;
        RECT  18.768 69.036 18.792 69.12 ;
    END
  END cfg_data[255]
  PIN cfg_data[25]
    DIRECTION INPUT ;
    USE SIGNAL ;
    PORT
      LAYER M5 ;
        RECT  34.32 69.036 34.344 69.12 ;
    END
  END cfg_data[25]
  PIN cfg_data[26]
    DIRECTION INPUT ;
    USE SIGNAL ;
    PORT
      LAYER M5 ;
        RECT  34.416 69.036 34.44 69.12 ;
    END
  END cfg_data[26]
  PIN cfg_data[27]
    DIRECTION INPUT ;
    USE SIGNAL ;
    PORT
      LAYER M5 ;
        RECT  34.512 69.036 34.536 69.12 ;
    END
  END cfg_data[27]
  PIN cfg_data[28]
    DIRECTION INPUT ;
    USE SIGNAL ;
    PORT
      LAYER M5 ;
        RECT  34.608 69.036 34.632 69.12 ;
    END
  END cfg_data[28]
  PIN cfg_data[29]
    DIRECTION INPUT ;
    USE SIGNAL ;
    PORT
      LAYER M5 ;
        RECT  34.704 69.036 34.728 69.12 ;
    END
  END cfg_data[29]
  PIN cfg_data[2]
    DIRECTION INPUT ;
    USE SIGNAL ;
    PORT
      LAYER M5 ;
        RECT  44.4 69.036 44.424 69.12 ;
    END
  END cfg_data[2]
  PIN cfg_data[30]
    DIRECTION INPUT ;
    USE SIGNAL ;
    PORT
      LAYER M5 ;
        RECT  34.8 69.036 34.824 69.12 ;
    END
  END cfg_data[30]
  PIN cfg_data[31]
    DIRECTION INPUT ;
    USE SIGNAL ;
    PORT
      LAYER M5 ;
        RECT  34.896 69.036 34.92 69.12 ;
    END
  END cfg_data[31]
  PIN cfg_data[32]
    DIRECTION INPUT ;
    USE SIGNAL ;
    PORT
      LAYER M5 ;
        RECT  34.992 69.036 35.016 69.12 ;
    END
  END cfg_data[32]
  PIN cfg_data[33]
    DIRECTION INPUT ;
    USE SIGNAL ;
    PORT
      LAYER M5 ;
        RECT  35.088 69.036 35.112 69.12 ;
    END
  END cfg_data[33]
  PIN cfg_data[34]
    DIRECTION INPUT ;
    USE SIGNAL ;
    PORT
      LAYER M5 ;
        RECT  35.184 69.036 35.208 69.12 ;
    END
  END cfg_data[34]
  PIN cfg_data[35]
    DIRECTION INPUT ;
    USE SIGNAL ;
    PORT
      LAYER M5 ;
        RECT  35.28 69.036 35.304 69.12 ;
    END
  END cfg_data[35]
  PIN cfg_data[36]
    DIRECTION INPUT ;
    USE SIGNAL ;
    PORT
      LAYER M5 ;
        RECT  35.376 69.036 35.4 69.12 ;
    END
  END cfg_data[36]
  PIN cfg_data[37]
    DIRECTION INPUT ;
    USE SIGNAL ;
    PORT
      LAYER M5 ;
        RECT  35.472 69.036 35.496 69.12 ;
    END
  END cfg_data[37]
  PIN cfg_data[38]
    DIRECTION INPUT ;
    USE SIGNAL ;
    PORT
      LAYER M5 ;
        RECT  35.568 69.036 35.592 69.12 ;
    END
  END cfg_data[38]
  PIN cfg_data[39]
    DIRECTION INPUT ;
    USE SIGNAL ;
    PORT
      LAYER M5 ;
        RECT  35.664 69.036 35.688 69.12 ;
    END
  END cfg_data[39]
  PIN cfg_data[3]
    DIRECTION INPUT ;
    USE SIGNAL ;
    PORT
      LAYER M5 ;
        RECT  44.496 69.036 44.52 69.12 ;
    END
  END cfg_data[3]
  PIN cfg_data[40]
    DIRECTION INPUT ;
    USE SIGNAL ;
    PORT
      LAYER M5 ;
        RECT  35.76 69.036 35.784 69.12 ;
    END
  END cfg_data[40]
  PIN cfg_data[41]
    DIRECTION INPUT ;
    USE SIGNAL ;
    PORT
      LAYER M5 ;
        RECT  35.856 69.036 35.88 69.12 ;
    END
  END cfg_data[41]
  PIN cfg_data[42]
    DIRECTION INPUT ;
    USE SIGNAL ;
    PORT
      LAYER M5 ;
        RECT  35.952 69.036 35.976 69.12 ;
    END
  END cfg_data[42]
  PIN cfg_data[43]
    DIRECTION INPUT ;
    USE SIGNAL ;
    PORT
      LAYER M5 ;
        RECT  36.048 69.036 36.072 69.12 ;
    END
  END cfg_data[43]
  PIN cfg_data[44]
    DIRECTION INPUT ;
    USE SIGNAL ;
    PORT
      LAYER M5 ;
        RECT  36.144 69.036 36.168 69.12 ;
    END
  END cfg_data[44]
  PIN cfg_data[45]
    DIRECTION INPUT ;
    USE SIGNAL ;
    PORT
      LAYER M5 ;
        RECT  36.24 69.036 36.264 69.12 ;
    END
  END cfg_data[45]
  PIN cfg_data[46]
    DIRECTION INPUT ;
    USE SIGNAL ;
    PORT
      LAYER M5 ;
        RECT  36.336 69.036 36.36 69.12 ;
    END
  END cfg_data[46]
  PIN cfg_data[47]
    DIRECTION INPUT ;
    USE SIGNAL ;
    PORT
      LAYER M5 ;
        RECT  36.432 69.036 36.456 69.12 ;
    END
  END cfg_data[47]
  PIN cfg_data[48]
    DIRECTION INPUT ;
    USE SIGNAL ;
    PORT
      LAYER M5 ;
        RECT  36.528 69.036 36.552 69.12 ;
    END
  END cfg_data[48]
  PIN cfg_data[49]
    DIRECTION INPUT ;
    USE SIGNAL ;
    PORT
      LAYER M5 ;
        RECT  36.624 69.036 36.648 69.12 ;
    END
  END cfg_data[49]
  PIN cfg_data[4]
    DIRECTION INPUT ;
    USE SIGNAL ;
    PORT
      LAYER M5 ;
        RECT  44.592 69.036 44.616 69.12 ;
    END
  END cfg_data[4]
  PIN cfg_data[50]
    DIRECTION INPUT ;
    USE SIGNAL ;
    PORT
      LAYER M5 ;
        RECT  36.72 69.036 36.744 69.12 ;
    END
  END cfg_data[50]
  PIN cfg_data[51]
    DIRECTION INPUT ;
    USE SIGNAL ;
    PORT
      LAYER M5 ;
        RECT  36.816 69.036 36.84 69.12 ;
    END
  END cfg_data[51]
  PIN cfg_data[52]
    DIRECTION INPUT ;
    USE SIGNAL ;
    PORT
      LAYER M5 ;
        RECT  20.784 69.036 20.808 69.12 ;
    END
  END cfg_data[52]
  PIN cfg_data[53]
    DIRECTION INPUT ;
    USE SIGNAL ;
    PORT
      LAYER M5 ;
        RECT  20.88 69.036 20.904 69.12 ;
    END
  END cfg_data[53]
  PIN cfg_data[54]
    DIRECTION INPUT ;
    USE SIGNAL ;
    PORT
      LAYER M5 ;
        RECT  20.976 69.036 21 69.12 ;
    END
  END cfg_data[54]
  PIN cfg_data[55]
    DIRECTION INPUT ;
    USE SIGNAL ;
    PORT
      LAYER M5 ;
        RECT  21.072 69.036 21.096 69.12 ;
    END
  END cfg_data[55]
  PIN cfg_data[56]
    DIRECTION INPUT ;
    USE SIGNAL ;
    PORT
      LAYER M5 ;
        RECT  21.168 69.036 21.192 69.12 ;
    END
  END cfg_data[56]
  PIN cfg_data[57]
    DIRECTION INPUT ;
    USE SIGNAL ;
    PORT
      LAYER M5 ;
        RECT  21.264 69.036 21.288 69.12 ;
    END
  END cfg_data[57]
  PIN cfg_data[58]
    DIRECTION INPUT ;
    USE SIGNAL ;
    PORT
      LAYER M5 ;
        RECT  21.36 69.036 21.384 69.12 ;
    END
  END cfg_data[58]
  PIN cfg_data[59]
    DIRECTION INPUT ;
    USE SIGNAL ;
    PORT
      LAYER M5 ;
        RECT  21.456 69.036 21.48 69.12 ;
    END
  END cfg_data[59]
  PIN cfg_data[5]
    DIRECTION INPUT ;
    USE SIGNAL ;
    PORT
      LAYER M5 ;
        RECT  44.688 69.036 44.712 69.12 ;
    END
  END cfg_data[5]
  PIN cfg_data[60]
    DIRECTION INPUT ;
    USE SIGNAL ;
    PORT
      LAYER M5 ;
        RECT  21.552 69.036 21.576 69.12 ;
    END
  END cfg_data[60]
  PIN cfg_data[61]
    DIRECTION INPUT ;
    USE SIGNAL ;
    PORT
      LAYER M5 ;
        RECT  21.648 69.036 21.672 69.12 ;
    END
  END cfg_data[61]
  PIN cfg_data[62]
    DIRECTION INPUT ;
    USE SIGNAL ;
    PORT
      LAYER M5 ;
        RECT  21.744 69.036 21.768 69.12 ;
    END
  END cfg_data[62]
  PIN cfg_data[63]
    DIRECTION INPUT ;
    USE SIGNAL ;
    PORT
      LAYER M5 ;
        RECT  21.84 69.036 21.864 69.12 ;
    END
  END cfg_data[63]
  PIN cfg_data[64]
    DIRECTION INPUT ;
    USE SIGNAL ;
    PORT
      LAYER M5 ;
        RECT  21.936 69.036 21.96 69.12 ;
    END
  END cfg_data[64]
  PIN cfg_data[65]
    DIRECTION INPUT ;
    USE SIGNAL ;
    PORT
      LAYER M5 ;
        RECT  22.032 69.036 22.056 69.12 ;
    END
  END cfg_data[65]
  PIN cfg_data[66]
    DIRECTION INPUT ;
    USE SIGNAL ;
    PORT
      LAYER M5 ;
        RECT  22.128 69.036 22.152 69.12 ;
    END
  END cfg_data[66]
  PIN cfg_data[67]
    DIRECTION INPUT ;
    USE SIGNAL ;
    PORT
      LAYER M5 ;
        RECT  22.224 69.036 22.248 69.12 ;
    END
  END cfg_data[67]
  PIN cfg_data[68]
    DIRECTION INPUT ;
    USE SIGNAL ;
    PORT
      LAYER M5 ;
        RECT  22.32 69.036 22.344 69.12 ;
    END
  END cfg_data[68]
  PIN cfg_data[69]
    DIRECTION INPUT ;
    USE SIGNAL ;
    PORT
      LAYER M5 ;
        RECT  22.416 69.036 22.44 69.12 ;
    END
  END cfg_data[69]
  PIN cfg_data[6]
    DIRECTION INPUT ;
    USE SIGNAL ;
    PORT
      LAYER M5 ;
        RECT  44.784 69.036 44.808 69.12 ;
    END
  END cfg_data[6]
  PIN cfg_data[70]
    DIRECTION INPUT ;
    USE SIGNAL ;
    PORT
      LAYER M5 ;
        RECT  22.512 69.036 22.536 69.12 ;
    END
  END cfg_data[70]
  PIN cfg_data[71]
    DIRECTION INPUT ;
    USE SIGNAL ;
    PORT
      LAYER M5 ;
        RECT  22.608 69.036 22.632 69.12 ;
    END
  END cfg_data[71]
  PIN cfg_data[72]
    DIRECTION INPUT ;
    USE SIGNAL ;
    PORT
      LAYER M5 ;
        RECT  22.704 69.036 22.728 69.12 ;
    END
  END cfg_data[72]
  PIN cfg_data[73]
    DIRECTION INPUT ;
    USE SIGNAL ;
    PORT
      LAYER M5 ;
        RECT  22.8 69.036 22.824 69.12 ;
    END
  END cfg_data[73]
  PIN cfg_data[74]
    DIRECTION INPUT ;
    USE SIGNAL ;
    PORT
      LAYER M5 ;
        RECT  22.896 69.036 22.92 69.12 ;
    END
  END cfg_data[74]
  PIN cfg_data[75]
    DIRECTION INPUT ;
    USE SIGNAL ;
    PORT
      LAYER M5 ;
        RECT  22.992 69.036 23.016 69.12 ;
    END
  END cfg_data[75]
  PIN cfg_data[76]
    DIRECTION INPUT ;
    USE SIGNAL ;
    PORT
      LAYER M5 ;
        RECT  23.088 69.036 23.112 69.12 ;
    END
  END cfg_data[76]
  PIN cfg_data[77]
    DIRECTION INPUT ;
    USE SIGNAL ;
    PORT
      LAYER M5 ;
        RECT  23.184 69.036 23.208 69.12 ;
    END
  END cfg_data[77]
  PIN cfg_data[78]
    DIRECTION INPUT ;
    USE SIGNAL ;
    PORT
      LAYER M5 ;
        RECT  23.28 69.036 23.304 69.12 ;
    END
  END cfg_data[78]
  PIN cfg_data[79]
    DIRECTION INPUT ;
    USE SIGNAL ;
    PORT
      LAYER M5 ;
        RECT  23.376 69.036 23.4 69.12 ;
    END
  END cfg_data[79]
  PIN cfg_data[7]
    DIRECTION INPUT ;
    USE SIGNAL ;
    PORT
      LAYER M5 ;
        RECT  44.88 69.036 44.904 69.12 ;
    END
  END cfg_data[7]
  PIN cfg_data[80]
    DIRECTION INPUT ;
    USE SIGNAL ;
    PORT
      LAYER M5 ;
        RECT  23.472 69.036 23.496 69.12 ;
    END
  END cfg_data[80]
  PIN cfg_data[81]
    DIRECTION INPUT ;
    USE SIGNAL ;
    PORT
      LAYER M5 ;
        RECT  23.568 69.036 23.592 69.12 ;
    END
  END cfg_data[81]
  PIN cfg_data[82]
    DIRECTION INPUT ;
    USE SIGNAL ;
    PORT
      LAYER M5 ;
        RECT  23.664 69.036 23.688 69.12 ;
    END
  END cfg_data[82]
  PIN cfg_data[83]
    DIRECTION INPUT ;
    USE SIGNAL ;
    PORT
      LAYER M5 ;
        RECT  23.76 69.036 23.784 69.12 ;
    END
  END cfg_data[83]
  PIN cfg_data[84]
    DIRECTION INPUT ;
    USE SIGNAL ;
    PORT
      LAYER M5 ;
        RECT  46.128 69.036 46.152 69.12 ;
    END
  END cfg_data[84]
  PIN cfg_data[85]
    DIRECTION INPUT ;
    USE SIGNAL ;
    PORT
      LAYER M5 ;
        RECT  46.224 69.036 46.248 69.12 ;
    END
  END cfg_data[85]
  PIN cfg_data[86]
    DIRECTION INPUT ;
    USE SIGNAL ;
    PORT
      LAYER M5 ;
        RECT  46.32 69.036 46.344 69.12 ;
    END
  END cfg_data[86]
  PIN cfg_data[87]
    DIRECTION INPUT ;
    USE SIGNAL ;
    PORT
      LAYER M5 ;
        RECT  46.416 69.036 46.44 69.12 ;
    END
  END cfg_data[87]
  PIN cfg_data[88]
    DIRECTION INPUT ;
    USE SIGNAL ;
    PORT
      LAYER M5 ;
        RECT  46.512 69.036 46.536 69.12 ;
    END
  END cfg_data[88]
  PIN cfg_data[89]
    DIRECTION INPUT ;
    USE SIGNAL ;
    PORT
      LAYER M5 ;
        RECT  46.608 69.036 46.632 69.12 ;
    END
  END cfg_data[89]
  PIN cfg_data[8]
    DIRECTION INPUT ;
    USE SIGNAL ;
    PORT
      LAYER M5 ;
        RECT  44.976 69.036 45 69.12 ;
    END
  END cfg_data[8]
  PIN cfg_data[90]
    DIRECTION INPUT ;
    USE SIGNAL ;
    PORT
      LAYER M5 ;
        RECT  46.704 69.036 46.728 69.12 ;
    END
  END cfg_data[90]
  PIN cfg_data[91]
    DIRECTION INPUT ;
    USE SIGNAL ;
    PORT
      LAYER M5 ;
        RECT  46.8 69.036 46.824 69.12 ;
    END
  END cfg_data[91]
  PIN cfg_data[92]
    DIRECTION INPUT ;
    USE SIGNAL ;
    PORT
      LAYER M5 ;
        RECT  46.896 69.036 46.92 69.12 ;
    END
  END cfg_data[92]
  PIN cfg_data[93]
    DIRECTION INPUT ;
    USE SIGNAL ;
    PORT
      LAYER M5 ;
        RECT  46.992 69.036 47.016 69.12 ;
    END
  END cfg_data[93]
  PIN cfg_data[94]
    DIRECTION INPUT ;
    USE SIGNAL ;
    PORT
      LAYER M5 ;
        RECT  47.088 69.036 47.112 69.12 ;
    END
  END cfg_data[94]
  PIN cfg_data[95]
    DIRECTION INPUT ;
    USE SIGNAL ;
    PORT
      LAYER M5 ;
        RECT  47.184 69.036 47.208 69.12 ;
    END
  END cfg_data[95]
  PIN cfg_data[96]
    DIRECTION INPUT ;
    USE SIGNAL ;
    PORT
      LAYER M5 ;
        RECT  47.28 69.036 47.304 69.12 ;
    END
  END cfg_data[96]
  PIN cfg_data[97]
    DIRECTION INPUT ;
    USE SIGNAL ;
    PORT
      LAYER M5 ;
        RECT  47.376 69.036 47.4 69.12 ;
    END
  END cfg_data[97]
  PIN cfg_data[98]
    DIRECTION INPUT ;
    USE SIGNAL ;
    PORT
      LAYER M5 ;
        RECT  47.472 69.036 47.496 69.12 ;
    END
  END cfg_data[98]
  PIN cfg_data[99]
    DIRECTION INPUT ;
    USE SIGNAL ;
    PORT
      LAYER M5 ;
        RECT  47.568 69.036 47.592 69.12 ;
    END
  END cfg_data[99]
  PIN cfg_data[9]
    DIRECTION INPUT ;
    USE SIGNAL ;
    PORT
      LAYER M5 ;
        RECT  45.072 69.036 45.096 69.12 ;
    END
  END cfg_data[9]
  PIN cfg_target[0]
    DIRECTION INPUT ;
    USE SIGNAL ;
    PORT
      LAYER M5 ;
        RECT  18.864 69.036 18.888 69.12 ;
    END
  END cfg_target[0]
  PIN cfg_target[1]
    DIRECTION INPUT ;
    USE SIGNAL ;
    PORT
      LAYER M5 ;
        RECT  18.96 69.036 18.984 69.12 ;
    END
  END cfg_target[1]
  PIN cfg_target[2]
    DIRECTION INPUT ;
    USE SIGNAL ;
    PORT
      LAYER M5 ;
        RECT  19.056 69.036 19.08 69.12 ;
    END
  END cfg_target[2]
  PIN cfg_target[3]
    DIRECTION INPUT ;
    USE SIGNAL ;
    PORT
      LAYER M5 ;
        RECT  19.152 69.036 19.176 69.12 ;
    END
  END cfg_target[3]
  PIN cfg_target[4]
    DIRECTION INPUT ;
    USE SIGNAL ;
    PORT
      LAYER M5 ;
        RECT  19.248 69.036 19.272 69.12 ;
    END
  END cfg_target[4]
  PIN cfg_target[5]
    DIRECTION INPUT ;
    USE SIGNAL ;
    PORT
      LAYER M5 ;
        RECT  19.344 69.036 19.368 69.12 ;
    END
  END cfg_target[5]
  PIN cfg_target[6]
    DIRECTION INPUT ;
    USE SIGNAL ;
    PORT
      LAYER M5 ;
        RECT  19.44 69.036 19.464 69.12 ;
    END
  END cfg_target[6]
  PIN cfg_target[7]
    DIRECTION INPUT ;
    USE SIGNAL ;
    PORT
      LAYER M5 ;
        RECT  19.536 69.036 19.56 69.12 ;
    END
  END cfg_target[7]
  PIN cfg_v
    DIRECTION INPUT ;
    USE SIGNAL ;
    PORT
      LAYER M5 ;
        RECT  19.632 69.036 19.656 69.12 ;
    END
  END cfg_v
  PIN clk
    DIRECTION INPUT ;
    USE SIGNAL ;
    PORT
      LAYER M5 ;
        RECT  19.728 69.036 19.752 69.12 ;
    END
  END clk
  PIN desc_base[0]
    DIRECTION INPUT ;
    USE SIGNAL ;
    PORT
      LAYER M5 ;
        RECT  19.824 69.036 19.848 69.12 ;
    END
  END desc_base[0]
  PIN desc_base[10]
    DIRECTION INPUT ;
    USE SIGNAL ;
    PORT
      LAYER M5 ;
        RECT  23.856 69.036 23.88 69.12 ;
    END
  END desc_base[10]
  PIN desc_base[11]
    DIRECTION INPUT ;
    USE SIGNAL ;
    PORT
      LAYER M5 ;
        RECT  23.952 69.036 23.976 69.12 ;
    END
  END desc_base[11]
  PIN desc_base[1]
    DIRECTION INPUT ;
    USE SIGNAL ;
    PORT
      LAYER M5 ;
        RECT  19.92 69.036 19.944 69.12 ;
    END
  END desc_base[1]
  PIN desc_base[2]
    DIRECTION INPUT ;
    USE SIGNAL ;
    PORT
      LAYER M5 ;
        RECT  20.016 69.036 20.04 69.12 ;
    END
  END desc_base[2]
  PIN desc_base[3]
    DIRECTION INPUT ;
    USE SIGNAL ;
    PORT
      LAYER M5 ;
        RECT  20.112 69.036 20.136 69.12 ;
    END
  END desc_base[3]
  PIN desc_base[4]
    DIRECTION INPUT ;
    USE SIGNAL ;
    PORT
      LAYER M5 ;
        RECT  20.208 69.036 20.232 69.12 ;
    END
  END desc_base[4]
  PIN desc_base[5]
    DIRECTION INPUT ;
    USE SIGNAL ;
    PORT
      LAYER M5 ;
        RECT  20.304 69.036 20.328 69.12 ;
    END
  END desc_base[5]
  PIN desc_base[6]
    DIRECTION INPUT ;
    USE SIGNAL ;
    PORT
      LAYER M5 ;
        RECT  20.4 69.036 20.424 69.12 ;
    END
  END desc_base[6]
  PIN desc_base[7]
    DIRECTION INPUT ;
    USE SIGNAL ;
    PORT
      LAYER M5 ;
        RECT  20.496 69.036 20.52 69.12 ;
    END
  END desc_base[7]
  PIN desc_base[8]
    DIRECTION INPUT ;
    USE SIGNAL ;
    PORT
      LAYER M5 ;
        RECT  20.592 69.036 20.616 69.12 ;
    END
  END desc_base[8]
  PIN desc_base[9]
    DIRECTION INPUT ;
    USE SIGNAL ;
    PORT
      LAYER M5 ;
        RECT  20.688 69.036 20.712 69.12 ;
    END
  END desc_base[9]
  PIN desc_limit[0]
    DIRECTION INPUT ;
    USE SIGNAL ;
    PORT
      LAYER M5 ;
        RECT  24.048 69.036 24.072 69.12 ;
    END
  END desc_limit[0]
  PIN desc_limit[10]
    DIRECTION INPUT ;
    USE SIGNAL ;
    PORT
      LAYER M5 ;
        RECT  25.008 69.036 25.032 69.12 ;
    END
  END desc_limit[10]
  PIN desc_limit[11]
    DIRECTION INPUT ;
    USE SIGNAL ;
    PORT
      LAYER M5 ;
        RECT  25.104 69.036 25.128 69.12 ;
    END
  END desc_limit[11]
  PIN desc_limit[12]
    DIRECTION INPUT ;
    USE SIGNAL ;
    PORT
      LAYER M5 ;
        RECT  25.2 69.036 25.224 69.12 ;
    END
  END desc_limit[12]
  PIN desc_limit[1]
    DIRECTION INPUT ;
    USE SIGNAL ;
    PORT
      LAYER M5 ;
        RECT  24.144 69.036 24.168 69.12 ;
    END
  END desc_limit[1]
  PIN desc_limit[2]
    DIRECTION INPUT ;
    USE SIGNAL ;
    PORT
      LAYER M5 ;
        RECT  24.24 69.036 24.264 69.12 ;
    END
  END desc_limit[2]
  PIN desc_limit[3]
    DIRECTION INPUT ;
    USE SIGNAL ;
    PORT
      LAYER M5 ;
        RECT  24.336 69.036 24.36 69.12 ;
    END
  END desc_limit[3]
  PIN desc_limit[4]
    DIRECTION INPUT ;
    USE SIGNAL ;
    PORT
      LAYER M5 ;
        RECT  24.432 69.036 24.456 69.12 ;
    END
  END desc_limit[4]
  PIN desc_limit[5]
    DIRECTION INPUT ;
    USE SIGNAL ;
    PORT
      LAYER M5 ;
        RECT  24.528 69.036 24.552 69.12 ;
    END
  END desc_limit[5]
  PIN desc_limit[6]
    DIRECTION INPUT ;
    USE SIGNAL ;
    PORT
      LAYER M5 ;
        RECT  24.624 69.036 24.648 69.12 ;
    END
  END desc_limit[6]
  PIN desc_limit[7]
    DIRECTION INPUT ;
    USE SIGNAL ;
    PORT
      LAYER M5 ;
        RECT  24.72 69.036 24.744 69.12 ;
    END
  END desc_limit[7]
  PIN desc_limit[8]
    DIRECTION INPUT ;
    USE SIGNAL ;
    PORT
      LAYER M5 ;
        RECT  24.816 69.036 24.84 69.12 ;
    END
  END desc_limit[8]
  PIN desc_limit[9]
    DIRECTION INPUT ;
    USE SIGNAL ;
    PORT
      LAYER M5 ;
        RECT  24.912 69.036 24.936 69.12 ;
    END
  END desc_limit[9]
  PIN desc_loops[0]
    DIRECTION INPUT ;
    USE SIGNAL ;
    PORT
      LAYER M5 ;
        RECT  25.296 69.036 25.32 69.12 ;
    END
  END desc_loops[0]
  PIN desc_loops[10]
    DIRECTION INPUT ;
    USE SIGNAL ;
    PORT
      LAYER M5 ;
        RECT  26.256 69.036 26.28 69.12 ;
    END
  END desc_loops[10]
  PIN desc_loops[11]
    DIRECTION INPUT ;
    USE SIGNAL ;
    PORT
      LAYER M5 ;
        RECT  26.352 69.036 26.376 69.12 ;
    END
  END desc_loops[11]
  PIN desc_loops[12]
    DIRECTION INPUT ;
    USE SIGNAL ;
    PORT
      LAYER M5 ;
        RECT  26.448 69.036 26.472 69.12 ;
    END
  END desc_loops[12]
  PIN desc_loops[13]
    DIRECTION INPUT ;
    USE SIGNAL ;
    PORT
      LAYER M5 ;
        RECT  26.544 69.036 26.568 69.12 ;
    END
  END desc_loops[13]
  PIN desc_loops[14]
    DIRECTION INPUT ;
    USE SIGNAL ;
    PORT
      LAYER M5 ;
        RECT  26.64 69.036 26.664 69.12 ;
    END
  END desc_loops[14]
  PIN desc_loops[15]
    DIRECTION INPUT ;
    USE SIGNAL ;
    PORT
      LAYER M5 ;
        RECT  26.736 69.036 26.76 69.12 ;
    END
  END desc_loops[15]
  PIN desc_loops[1]
    DIRECTION INPUT ;
    USE SIGNAL ;
    PORT
      LAYER M5 ;
        RECT  25.392 69.036 25.416 69.12 ;
    END
  END desc_loops[1]
  PIN desc_loops[2]
    DIRECTION INPUT ;
    USE SIGNAL ;
    PORT
      LAYER M5 ;
        RECT  25.488 69.036 25.512 69.12 ;
    END
  END desc_loops[2]
  PIN desc_loops[3]
    DIRECTION INPUT ;
    USE SIGNAL ;
    PORT
      LAYER M5 ;
        RECT  25.584 69.036 25.608 69.12 ;
    END
  END desc_loops[3]
  PIN desc_loops[4]
    DIRECTION INPUT ;
    USE SIGNAL ;
    PORT
      LAYER M5 ;
        RECT  25.68 69.036 25.704 69.12 ;
    END
  END desc_loops[4]
  PIN desc_loops[5]
    DIRECTION INPUT ;
    USE SIGNAL ;
    PORT
      LAYER M5 ;
        RECT  25.776 69.036 25.8 69.12 ;
    END
  END desc_loops[5]
  PIN desc_loops[6]
    DIRECTION INPUT ;
    USE SIGNAL ;
    PORT
      LAYER M5 ;
        RECT  25.872 69.036 25.896 69.12 ;
    END
  END desc_loops[6]
  PIN desc_loops[7]
    DIRECTION INPUT ;
    USE SIGNAL ;
    PORT
      LAYER M5 ;
        RECT  25.968 69.036 25.992 69.12 ;
    END
  END desc_loops[7]
  PIN desc_loops[8]
    DIRECTION INPUT ;
    USE SIGNAL ;
    PORT
      LAYER M5 ;
        RECT  26.064 69.036 26.088 69.12 ;
    END
  END desc_loops[8]
  PIN desc_loops[9]
    DIRECTION INPUT ;
    USE SIGNAL ;
    PORT
      LAYER M5 ;
        RECT  26.16 69.036 26.184 69.12 ;
    END
  END desc_loops[9]
  PIN desc_v
    DIRECTION INPUT ;
    USE SIGNAL ;
    PORT
      LAYER M5 ;
        RECT  26.832 69.036 26.856 69.12 ;
    END
  END desc_v
  PIN launch_v
    DIRECTION INPUT ;
    USE SIGNAL ;
    PORT
      LAYER M5 ;
        RECT  30.576 69.036 30.6 69.12 ;
    END
  END launch_v
  PIN rst_n
    DIRECTION INPUT ;
    USE SIGNAL ;
    PORT
      LAYER M5 ;
        RECT  30.672 69.036 30.696 69.12 ;
    END
  END rst_n
  PIN s_active[0]
    DIRECTION OUTPUT ;
    USE SIGNAL ;
    PORT
      LAYER M5 ;
        RECT  48.336 0 48.36 0.084 ;
    END
  END s_active[0]
  PIN s_active[10]
    DIRECTION OUTPUT ;
    USE SIGNAL ;
    PORT
      LAYER M5 ;
        RECT  49.296 0 49.32 0.084 ;
    END
  END s_active[10]
  PIN s_active[11]
    DIRECTION OUTPUT ;
    USE SIGNAL ;
    PORT
      LAYER M5 ;
        RECT  49.392 0 49.416 0.084 ;
    END
  END s_active[11]
  PIN s_active[12]
    DIRECTION OUTPUT ;
    USE SIGNAL ;
    PORT
      LAYER M5 ;
        RECT  49.488 0 49.512 0.084 ;
    END
  END s_active[12]
  PIN s_active[13]
    DIRECTION OUTPUT ;
    USE SIGNAL ;
    PORT
      LAYER M5 ;
        RECT  49.584 0 49.608 0.084 ;
    END
  END s_active[13]
  PIN s_active[14]
    DIRECTION OUTPUT ;
    USE SIGNAL ;
    PORT
      LAYER M5 ;
        RECT  49.68 0 49.704 0.084 ;
    END
  END s_active[14]
  PIN s_active[15]
    DIRECTION OUTPUT ;
    USE SIGNAL ;
    PORT
      LAYER M5 ;
        RECT  49.776 0 49.8 0.084 ;
    END
  END s_active[15]
  PIN s_active[16]
    DIRECTION OUTPUT ;
    USE SIGNAL ;
    PORT
      LAYER M5 ;
        RECT  49.872 0 49.896 0.084 ;
    END
  END s_active[16]
  PIN s_active[1]
    DIRECTION OUTPUT ;
    USE SIGNAL ;
    PORT
      LAYER M5 ;
        RECT  48.432 0 48.456 0.084 ;
    END
  END s_active[1]
  PIN s_active[2]
    DIRECTION OUTPUT ;
    USE SIGNAL ;
    PORT
      LAYER M5 ;
        RECT  48.528 0 48.552 0.084 ;
    END
  END s_active[2]
  PIN s_active[3]
    DIRECTION OUTPUT ;
    USE SIGNAL ;
    PORT
      LAYER M5 ;
        RECT  48.624 0 48.648 0.084 ;
    END
  END s_active[3]
  PIN s_active[4]
    DIRECTION OUTPUT ;
    USE SIGNAL ;
    PORT
      LAYER M5 ;
        RECT  48.72 0 48.744 0.084 ;
    END
  END s_active[4]
  PIN s_active[5]
    DIRECTION OUTPUT ;
    USE SIGNAL ;
    PORT
      LAYER M5 ;
        RECT  48.816 0 48.84 0.084 ;
    END
  END s_active[5]
  PIN s_active[6]
    DIRECTION OUTPUT ;
    USE SIGNAL ;
    PORT
      LAYER M5 ;
        RECT  48.912 0 48.936 0.084 ;
    END
  END s_active[6]
  PIN s_active[7]
    DIRECTION OUTPUT ;
    USE SIGNAL ;
    PORT
      LAYER M5 ;
        RECT  49.008 0 49.032 0.084 ;
    END
  END s_active[7]
  PIN s_active[8]
    DIRECTION OUTPUT ;
    USE SIGNAL ;
    PORT
      LAYER M5 ;
        RECT  49.104 0 49.128 0.084 ;
    END
  END s_active[8]
  PIN s_active[9]
    DIRECTION OUTPUT ;
    USE SIGNAL ;
    PORT
      LAYER M5 ;
        RECT  49.2 0 49.224 0.084 ;
    END
  END s_active[9]
  PIN s_fault[0]
    DIRECTION OUTPUT ;
    USE SIGNAL ;
    PORT
      LAYER M5 ;
        RECT  49.968 0 49.992 0.084 ;
    END
  END s_fault[0]
  PIN s_fault[10]
    DIRECTION OUTPUT ;
    USE SIGNAL ;
    PORT
      LAYER M5 ;
        RECT  50.928 0 50.952 0.084 ;
    END
  END s_fault[10]
  PIN s_fault[11]
    DIRECTION OUTPUT ;
    USE SIGNAL ;
    PORT
      LAYER M5 ;
        RECT  51.024 0 51.048 0.084 ;
    END
  END s_fault[11]
  PIN s_fault[12]
    DIRECTION OUTPUT ;
    USE SIGNAL ;
    PORT
      LAYER M5 ;
        RECT  51.12 0 51.144 0.084 ;
    END
  END s_fault[12]
  PIN s_fault[13]
    DIRECTION OUTPUT ;
    USE SIGNAL ;
    PORT
      LAYER M5 ;
        RECT  51.216 0 51.24 0.084 ;
    END
  END s_fault[13]
  PIN s_fault[14]
    DIRECTION OUTPUT ;
    USE SIGNAL ;
    PORT
      LAYER M5 ;
        RECT  51.312 0 51.336 0.084 ;
    END
  END s_fault[14]
  PIN s_fault[15]
    DIRECTION OUTPUT ;
    USE SIGNAL ;
    PORT
      LAYER M5 ;
        RECT  45.264 0 45.288 0.084 ;
    END
  END s_fault[15]
  PIN s_fault[16]
    DIRECTION OUTPUT ;
    USE SIGNAL ;
    PORT
      LAYER M5 ;
        RECT  45.36 0 45.384 0.084 ;
    END
  END s_fault[16]
  PIN s_fault[17]
    DIRECTION OUTPUT ;
    USE SIGNAL ;
    PORT
      LAYER M5 ;
        RECT  45.456 0 45.48 0.084 ;
    END
  END s_fault[17]
  PIN s_fault[18]
    DIRECTION OUTPUT ;
    USE SIGNAL ;
    PORT
      LAYER M5 ;
        RECT  45.552 0 45.576 0.084 ;
    END
  END s_fault[18]
  PIN s_fault[19]
    DIRECTION OUTPUT ;
    USE SIGNAL ;
    PORT
      LAYER M5 ;
        RECT  45.648 0 45.672 0.084 ;
    END
  END s_fault[19]
  PIN s_fault[1]
    DIRECTION OUTPUT ;
    USE SIGNAL ;
    PORT
      LAYER M5 ;
        RECT  50.064 0 50.088 0.084 ;
    END
  END s_fault[1]
  PIN s_fault[20]
    DIRECTION OUTPUT ;
    USE SIGNAL ;
    PORT
      LAYER M5 ;
        RECT  45.744 0 45.768 0.084 ;
    END
  END s_fault[20]
  PIN s_fault[21]
    DIRECTION OUTPUT ;
    USE SIGNAL ;
    PORT
      LAYER M5 ;
        RECT  45.84 0 45.864 0.084 ;
    END
  END s_fault[21]
  PIN s_fault[22]
    DIRECTION OUTPUT ;
    USE SIGNAL ;
    PORT
      LAYER M5 ;
        RECT  45.936 0 45.96 0.084 ;
    END
  END s_fault[22]
  PIN s_fault[23]
    DIRECTION OUTPUT ;
    USE SIGNAL ;
    PORT
      LAYER M5 ;
        RECT  46.032 0 46.056 0.084 ;
    END
  END s_fault[23]
  PIN s_fault[24]
    DIRECTION OUTPUT ;
    USE SIGNAL ;
    PORT
      LAYER M5 ;
        RECT  46.128 0 46.152 0.084 ;
    END
  END s_fault[24]
  PIN s_fault[25]
    DIRECTION OUTPUT ;
    USE SIGNAL ;
    PORT
      LAYER M5 ;
        RECT  46.224 0 46.248 0.084 ;
    END
  END s_fault[25]
  PIN s_fault[26]
    DIRECTION OUTPUT ;
    USE SIGNAL ;
    PORT
      LAYER M5 ;
        RECT  46.32 0 46.344 0.084 ;
    END
  END s_fault[26]
  PIN s_fault[2]
    DIRECTION OUTPUT ;
    USE SIGNAL ;
    PORT
      LAYER M5 ;
        RECT  50.16 0 50.184 0.084 ;
    END
  END s_fault[2]
  PIN s_fault[3]
    DIRECTION OUTPUT ;
    USE SIGNAL ;
    PORT
      LAYER M5 ;
        RECT  50.256 0 50.28 0.084 ;
    END
  END s_fault[3]
  PIN s_fault[4]
    DIRECTION OUTPUT ;
    USE SIGNAL ;
    PORT
      LAYER M5 ;
        RECT  50.352 0 50.376 0.084 ;
    END
  END s_fault[4]
  PIN s_fault[5]
    DIRECTION OUTPUT ;
    USE SIGNAL ;
    PORT
      LAYER M5 ;
        RECT  50.448 0 50.472 0.084 ;
    END
  END s_fault[5]
  PIN s_fault[6]
    DIRECTION OUTPUT ;
    USE SIGNAL ;
    PORT
      LAYER M5 ;
        RECT  50.544 0 50.568 0.084 ;
    END
  END s_fault[6]
  PIN s_fault[7]
    DIRECTION OUTPUT ;
    USE SIGNAL ;
    PORT
      LAYER M5 ;
        RECT  50.64 0 50.664 0.084 ;
    END
  END s_fault[7]
  PIN s_fault[8]
    DIRECTION OUTPUT ;
    USE SIGNAL ;
    PORT
      LAYER M5 ;
        RECT  50.736 0 50.76 0.084 ;
    END
  END s_fault[8]
  PIN s_fault[9]
    DIRECTION OUTPUT ;
    USE SIGNAL ;
    PORT
      LAYER M5 ;
        RECT  50.832 0 50.856 0.084 ;
    END
  END s_fault[9]
  PIN s_ready[0]
    DIRECTION OUTPUT ;
    USE SIGNAL ;
    PORT
      LAYER M5 ;
        RECT  46.416 0 46.44 0.084 ;
    END
  END s_ready[0]
  PIN s_ready[10]
    DIRECTION OUTPUT ;
    USE SIGNAL ;
    PORT
      LAYER M5 ;
        RECT  47.376 0 47.4 0.084 ;
    END
  END s_ready[10]
  PIN s_ready[11]
    DIRECTION OUTPUT ;
    USE SIGNAL ;
    PORT
      LAYER M5 ;
        RECT  47.472 0 47.496 0.084 ;
    END
  END s_ready[11]
  PIN s_ready[12]
    DIRECTION OUTPUT ;
    USE SIGNAL ;
    PORT
      LAYER M5 ;
        RECT  47.568 0 47.592 0.084 ;
    END
  END s_ready[12]
  PIN s_ready[13]
    DIRECTION OUTPUT ;
    USE SIGNAL ;
    PORT
      LAYER M5 ;
        RECT  47.664 0 47.688 0.084 ;
    END
  END s_ready[13]
  PIN s_ready[14]
    DIRECTION OUTPUT ;
    USE SIGNAL ;
    PORT
      LAYER M5 ;
        RECT  47.76 0 47.784 0.084 ;
    END
  END s_ready[14]
  PIN s_ready[15]
    DIRECTION OUTPUT ;
    USE SIGNAL ;
    PORT
      LAYER M5 ;
        RECT  47.856 0 47.88 0.084 ;
    END
  END s_ready[15]
  PIN s_ready[16]
    DIRECTION OUTPUT ;
    USE SIGNAL ;
    PORT
      LAYER M5 ;
        RECT  47.952 0 47.976 0.084 ;
    END
  END s_ready[16]
  PIN s_ready[1]
    DIRECTION OUTPUT ;
    USE SIGNAL ;
    PORT
      LAYER M5 ;
        RECT  46.512 0 46.536 0.084 ;
    END
  END s_ready[1]
  PIN s_ready[2]
    DIRECTION OUTPUT ;
    USE SIGNAL ;
    PORT
      LAYER M5 ;
        RECT  46.608 0 46.632 0.084 ;
    END
  END s_ready[2]
  PIN s_ready[3]
    DIRECTION OUTPUT ;
    USE SIGNAL ;
    PORT
      LAYER M5 ;
        RECT  46.704 0 46.728 0.084 ;
    END
  END s_ready[3]
  PIN s_ready[4]
    DIRECTION OUTPUT ;
    USE SIGNAL ;
    PORT
      LAYER M5 ;
        RECT  46.8 0 46.824 0.084 ;
    END
  END s_ready[4]
  PIN s_ready[5]
    DIRECTION OUTPUT ;
    USE SIGNAL ;
    PORT
      LAYER M5 ;
        RECT  46.896 0 46.92 0.084 ;
    END
  END s_ready[5]
  PIN s_ready[6]
    DIRECTION OUTPUT ;
    USE SIGNAL ;
    PORT
      LAYER M5 ;
        RECT  46.992 0 47.016 0.084 ;
    END
  END s_ready[6]
  PIN s_ready[7]
    DIRECTION OUTPUT ;
    USE SIGNAL ;
    PORT
      LAYER M5 ;
        RECT  47.088 0 47.112 0.084 ;
    END
  END s_ready[7]
  PIN s_ready[8]
    DIRECTION OUTPUT ;
    USE SIGNAL ;
    PORT
      LAYER M5 ;
        RECT  47.184 0 47.208 0.084 ;
    END
  END s_ready[8]
  PIN s_ready[9]
    DIRECTION OUTPUT ;
    USE SIGNAL ;
    PORT
      LAYER M5 ;
        RECT  47.28 0 47.304 0.084 ;
    END
  END s_ready[9]
  PIN t_active[0]
    DIRECTION INPUT ;
    USE SIGNAL ;
    PORT
      LAYER M5 ;
        RECT  48.048 0 48.072 0.084 ;
    END
  END t_active[0]
  PIN t_active[10]
    DIRECTION INPUT ;
    USE SIGNAL ;
    PORT
      LAYER M5 ;
        RECT  42.864 0 42.888 0.084 ;
    END
  END t_active[10]
  PIN t_active[11]
    DIRECTION INPUT ;
    USE SIGNAL ;
    PORT
      LAYER M5 ;
        RECT  42.96 0 42.984 0.084 ;
    END
  END t_active[11]
  PIN t_active[12]
    DIRECTION INPUT ;
    USE SIGNAL ;
    PORT
      LAYER M5 ;
        RECT  43.056 0 43.08 0.084 ;
    END
  END t_active[12]
  PIN t_active[13]
    DIRECTION INPUT ;
    USE SIGNAL ;
    PORT
      LAYER M5 ;
        RECT  43.152 0 43.176 0.084 ;
    END
  END t_active[13]
  PIN t_active[14]
    DIRECTION INPUT ;
    USE SIGNAL ;
    PORT
      LAYER M5 ;
        RECT  43.248 0 43.272 0.084 ;
    END
  END t_active[14]
  PIN t_active[15]
    DIRECTION INPUT ;
    USE SIGNAL ;
    PORT
      LAYER M5 ;
        RECT  43.344 0 43.368 0.084 ;
    END
  END t_active[15]
  PIN t_active[16]
    DIRECTION INPUT ;
    USE SIGNAL ;
    PORT
      LAYER M5 ;
        RECT  43.44 0 43.464 0.084 ;
    END
  END t_active[16]
  PIN t_active[1]
    DIRECTION INPUT ;
    USE SIGNAL ;
    PORT
      LAYER M5 ;
        RECT  48.144 0 48.168 0.084 ;
    END
  END t_active[1]
  PIN t_active[2]
    DIRECTION INPUT ;
    USE SIGNAL ;
    PORT
      LAYER M5 ;
        RECT  48.24 0 48.264 0.084 ;
    END
  END t_active[2]
  PIN t_active[3]
    DIRECTION INPUT ;
    USE SIGNAL ;
    PORT
      LAYER M5 ;
        RECT  42.192 0 42.216 0.084 ;
    END
  END t_active[3]
  PIN t_active[4]
    DIRECTION INPUT ;
    USE SIGNAL ;
    PORT
      LAYER M5 ;
        RECT  42.288 0 42.312 0.084 ;
    END
  END t_active[4]
  PIN t_active[5]
    DIRECTION INPUT ;
    USE SIGNAL ;
    PORT
      LAYER M5 ;
        RECT  42.384 0 42.408 0.084 ;
    END
  END t_active[5]
  PIN t_active[6]
    DIRECTION INPUT ;
    USE SIGNAL ;
    PORT
      LAYER M5 ;
        RECT  42.48 0 42.504 0.084 ;
    END
  END t_active[6]
  PIN t_active[7]
    DIRECTION INPUT ;
    USE SIGNAL ;
    PORT
      LAYER M5 ;
        RECT  42.576 0 42.6 0.084 ;
    END
  END t_active[7]
  PIN t_active[8]
    DIRECTION INPUT ;
    USE SIGNAL ;
    PORT
      LAYER M5 ;
        RECT  42.672 0 42.696 0.084 ;
    END
  END t_active[8]
  PIN t_active[9]
    DIRECTION INPUT ;
    USE SIGNAL ;
    PORT
      LAYER M5 ;
        RECT  42.768 0 42.792 0.084 ;
    END
  END t_active[9]
  PIN t_fault[0]
    DIRECTION INPUT ;
    USE SIGNAL ;
    PORT
      LAYER M5 ;
        RECT  43.536 0 43.56 0.084 ;
    END
  END t_fault[0]
  PIN t_fault[10]
    DIRECTION INPUT ;
    USE SIGNAL ;
    PORT
      LAYER M5 ;
        RECT  44.496 0 44.52 0.084 ;
    END
  END t_fault[10]
  PIN t_fault[11]
    DIRECTION INPUT ;
    USE SIGNAL ;
    PORT
      LAYER M5 ;
        RECT  44.592 0 44.616 0.084 ;
    END
  END t_fault[11]
  PIN t_fault[12]
    DIRECTION INPUT ;
    USE SIGNAL ;
    PORT
      LAYER M5 ;
        RECT  44.688 0 44.712 0.084 ;
    END
  END t_fault[12]
  PIN t_fault[13]
    DIRECTION INPUT ;
    USE SIGNAL ;
    PORT
      LAYER M5 ;
        RECT  44.784 0 44.808 0.084 ;
    END
  END t_fault[13]
  PIN t_fault[14]
    DIRECTION INPUT ;
    USE SIGNAL ;
    PORT
      LAYER M5 ;
        RECT  44.88 0 44.904 0.084 ;
    END
  END t_fault[14]
  PIN t_fault[15]
    DIRECTION INPUT ;
    USE SIGNAL ;
    PORT
      LAYER M5 ;
        RECT  44.976 0 45 0.084 ;
    END
  END t_fault[15]
  PIN t_fault[16]
    DIRECTION INPUT ;
    USE SIGNAL ;
    PORT
      LAYER M5 ;
        RECT  45.072 0 45.096 0.084 ;
    END
  END t_fault[16]
  PIN t_fault[17]
    DIRECTION INPUT ;
    USE SIGNAL ;
    PORT
      LAYER M5 ;
        RECT  45.168 0 45.192 0.084 ;
    END
  END t_fault[17]
  PIN t_fault[18]
    DIRECTION INPUT ;
    USE SIGNAL ;
    PORT
      LAYER M5 ;
        RECT  39.12 0 39.144 0.084 ;
    END
  END t_fault[18]
  PIN t_fault[19]
    DIRECTION INPUT ;
    USE SIGNAL ;
    PORT
      LAYER M5 ;
        RECT  39.216 0 39.24 0.084 ;
    END
  END t_fault[19]
  PIN t_fault[1]
    DIRECTION INPUT ;
    USE SIGNAL ;
    PORT
      LAYER M5 ;
        RECT  43.632 0 43.656 0.084 ;
    END
  END t_fault[1]
  PIN t_fault[20]
    DIRECTION INPUT ;
    USE SIGNAL ;
    PORT
      LAYER M5 ;
        RECT  39.312 0 39.336 0.084 ;
    END
  END t_fault[20]
  PIN t_fault[21]
    DIRECTION INPUT ;
    USE SIGNAL ;
    PORT
      LAYER M5 ;
        RECT  39.408 0 39.432 0.084 ;
    END
  END t_fault[21]
  PIN t_fault[22]
    DIRECTION INPUT ;
    USE SIGNAL ;
    PORT
      LAYER M5 ;
        RECT  39.504 0 39.528 0.084 ;
    END
  END t_fault[22]
  PIN t_fault[23]
    DIRECTION INPUT ;
    USE SIGNAL ;
    PORT
      LAYER M5 ;
        RECT  39.6 0 39.624 0.084 ;
    END
  END t_fault[23]
  PIN t_fault[24]
    DIRECTION INPUT ;
    USE SIGNAL ;
    PORT
      LAYER M5 ;
        RECT  39.696 0 39.72 0.084 ;
    END
  END t_fault[24]
  PIN t_fault[25]
    DIRECTION INPUT ;
    USE SIGNAL ;
    PORT
      LAYER M5 ;
        RECT  39.792 0 39.816 0.084 ;
    END
  END t_fault[25]
  PIN t_fault[26]
    DIRECTION INPUT ;
    USE SIGNAL ;
    PORT
      LAYER M5 ;
        RECT  39.888 0 39.912 0.084 ;
    END
  END t_fault[26]
  PIN t_fault[2]
    DIRECTION INPUT ;
    USE SIGNAL ;
    PORT
      LAYER M5 ;
        RECT  43.728 0 43.752 0.084 ;
    END
  END t_fault[2]
  PIN t_fault[3]
    DIRECTION INPUT ;
    USE SIGNAL ;
    PORT
      LAYER M5 ;
        RECT  43.824 0 43.848 0.084 ;
    END
  END t_fault[3]
  PIN t_fault[4]
    DIRECTION INPUT ;
    USE SIGNAL ;
    PORT
      LAYER M5 ;
        RECT  43.92 0 43.944 0.084 ;
    END
  END t_fault[4]
  PIN t_fault[5]
    DIRECTION INPUT ;
    USE SIGNAL ;
    PORT
      LAYER M5 ;
        RECT  44.016 0 44.04 0.084 ;
    END
  END t_fault[5]
  PIN t_fault[6]
    DIRECTION INPUT ;
    USE SIGNAL ;
    PORT
      LAYER M5 ;
        RECT  44.112 0 44.136 0.084 ;
    END
  END t_fault[6]
  PIN t_fault[7]
    DIRECTION INPUT ;
    USE SIGNAL ;
    PORT
      LAYER M5 ;
        RECT  44.208 0 44.232 0.084 ;
    END
  END t_fault[7]
  PIN t_fault[8]
    DIRECTION INPUT ;
    USE SIGNAL ;
    PORT
      LAYER M5 ;
        RECT  44.304 0 44.328 0.084 ;
    END
  END t_fault[8]
  PIN t_fault[9]
    DIRECTION INPUT ;
    USE SIGNAL ;
    PORT
      LAYER M5 ;
        RECT  44.4 0 44.424 0.084 ;
    END
  END t_fault[9]
  PIN t_ready[0]
    DIRECTION INPUT ;
    USE SIGNAL ;
    PORT
      LAYER M5 ;
        RECT  39.984 0 40.008 0.084 ;
    END
  END t_ready[0]
  PIN t_ready[10]
    DIRECTION INPUT ;
    USE SIGNAL ;
    PORT
      LAYER M5 ;
        RECT  40.944 0 40.968 0.084 ;
    END
  END t_ready[10]
  PIN t_ready[11]
    DIRECTION INPUT ;
    USE SIGNAL ;
    PORT
      LAYER M5 ;
        RECT  41.04 0 41.064 0.084 ;
    END
  END t_ready[11]
  PIN t_ready[12]
    DIRECTION INPUT ;
    USE SIGNAL ;
    PORT
      LAYER M5 ;
        RECT  41.136 0 41.16 0.084 ;
    END
  END t_ready[12]
  PIN t_ready[13]
    DIRECTION INPUT ;
    USE SIGNAL ;
    PORT
      LAYER M5 ;
        RECT  41.232 0 41.256 0.084 ;
    END
  END t_ready[13]
  PIN t_ready[14]
    DIRECTION INPUT ;
    USE SIGNAL ;
    PORT
      LAYER M5 ;
        RECT  41.328 0 41.352 0.084 ;
    END
  END t_ready[14]
  PIN t_ready[15]
    DIRECTION INPUT ;
    USE SIGNAL ;
    PORT
      LAYER M5 ;
        RECT  41.424 0 41.448 0.084 ;
    END
  END t_ready[15]
  PIN t_ready[16]
    DIRECTION INPUT ;
    USE SIGNAL ;
    PORT
      LAYER M5 ;
        RECT  41.52 0 41.544 0.084 ;
    END
  END t_ready[16]
  PIN t_ready[1]
    DIRECTION INPUT ;
    USE SIGNAL ;
    PORT
      LAYER M5 ;
        RECT  40.08 0 40.104 0.084 ;
    END
  END t_ready[1]
  PIN t_ready[2]
    DIRECTION INPUT ;
    USE SIGNAL ;
    PORT
      LAYER M5 ;
        RECT  40.176 0 40.2 0.084 ;
    END
  END t_ready[2]
  PIN t_ready[3]
    DIRECTION INPUT ;
    USE SIGNAL ;
    PORT
      LAYER M5 ;
        RECT  40.272 0 40.296 0.084 ;
    END
  END t_ready[3]
  PIN t_ready[4]
    DIRECTION INPUT ;
    USE SIGNAL ;
    PORT
      LAYER M5 ;
        RECT  40.368 0 40.392 0.084 ;
    END
  END t_ready[4]
  PIN t_ready[5]
    DIRECTION INPUT ;
    USE SIGNAL ;
    PORT
      LAYER M5 ;
        RECT  40.464 0 40.488 0.084 ;
    END
  END t_ready[5]
  PIN t_ready[6]
    DIRECTION INPUT ;
    USE SIGNAL ;
    PORT
      LAYER M5 ;
        RECT  40.56 0 40.584 0.084 ;
    END
  END t_ready[6]
  PIN t_ready[7]
    DIRECTION INPUT ;
    USE SIGNAL ;
    PORT
      LAYER M5 ;
        RECT  40.656 0 40.68 0.084 ;
    END
  END t_ready[7]
  PIN t_ready[8]
    DIRECTION INPUT ;
    USE SIGNAL ;
    PORT
      LAYER M5 ;
        RECT  40.752 0 40.776 0.084 ;
    END
  END t_ready[8]
  PIN t_ready[9]
    DIRECTION INPUT ;
    USE SIGNAL ;
    PORT
      LAYER M5 ;
        RECT  40.848 0 40.872 0.084 ;
    END
  END t_ready[9]
  PIN VDD
    DIRECTION INOUT ;
    USE POWER ;
    PORT
      LAYER M5 ;
        RECT  61.992 2.151 62.112 66.969 ;
        RECT  56.592 2.151 56.712 66.969 ;
        RECT  51.192 2.151 51.312 66.969 ;
        RECT  45.792 2.151 45.912 66.969 ;
        RECT  40.392 2.151 40.512 66.969 ;
        RECT  34.992 2.151 35.112 66.969 ;
        RECT  29.592 2.151 29.712 66.969 ;
        RECT  24.192 2.151 24.312 66.969 ;
        RECT  18.792 2.151 18.912 66.969 ;
        RECT  13.392 2.151 13.512 66.969 ;
        RECT  7.992 2.151 8.112 66.969 ;
        RECT  2.592 2.151 2.712 66.969 ;
    END
  END VDD
  PIN VSS
    DIRECTION INOUT ;
    USE GROUND ;
    PORT
      LAYER M5 ;
        RECT  61.8 2.137 61.92 66.983 ;
        RECT  56.4 2.137 56.52 66.983 ;
        RECT  51 2.137 51.12 66.983 ;
        RECT  45.6 2.137 45.72 66.983 ;
        RECT  40.2 2.137 40.32 66.983 ;
        RECT  34.8 2.137 34.92 66.983 ;
        RECT  29.4 2.137 29.52 66.983 ;
        RECT  24 2.137 24.12 66.983 ;
        RECT  18.6 2.137 18.72 66.983 ;
        RECT  13.2 2.137 13.32 66.983 ;
        RECT  7.8 2.137 7.92 66.983 ;
        RECT  2.4 2.137 2.52 66.983 ;
    END
  END VSS
  # OT_OBS_CLOSED layer=M5 d_um=1.536 added=40
  OBS
    LAYER RVTN ;
     RECT  2.16 2.16 66.96 2.295 ;
     RECT  2.16 2.565 66.96 2.835 ;
     RECT  2.16 3.105 66.96 3.375 ;
     RECT  2.16 3.645 66.96 3.915 ;
     RECT  2.16 4.185 66.96 4.455 ;
     RECT  2.16 4.725 66.96 4.995 ;
     RECT  2.16 5.265 66.96 5.535 ;
     RECT  2.16 5.805 66.96 6.075 ;
     RECT  2.16 6.345 66.96 6.615 ;
     RECT  2.16 6.885 66.96 7.155 ;
     RECT  2.16 7.425 66.96 7.695 ;
     RECT  2.16 7.965 66.96 8.235 ;
     RECT  2.16 8.505 66.96 8.775 ;
     RECT  2.16 9.045 66.96 9.315 ;
     RECT  2.16 9.585 66.96 9.855 ;
     RECT  2.16 10.125 66.96 10.395 ;
     RECT  2.16 10.665 66.96 10.935 ;
     RECT  2.16 11.205 66.96 11.475 ;
     RECT  2.16 11.745 66.96 12.015 ;
     RECT  2.16 12.285 66.96 12.555 ;
     RECT  2.16 12.825 66.96 13.095 ;
     RECT  2.16 13.365 66.96 13.635 ;
     RECT  2.16 13.905 66.96 14.175 ;
     RECT  2.16 14.445 66.96 14.715 ;
     RECT  2.16 14.985 66.96 15.255 ;
     RECT  2.16 15.525 66.96 15.795 ;
     RECT  2.16 16.065 66.96 16.335 ;
     RECT  2.16 16.605 66.96 16.875 ;
     RECT  2.16 17.145 66.96 17.415 ;
     RECT  2.16 17.685 66.96 17.955 ;
     RECT  2.16 18.225 66.96 18.495 ;
     RECT  2.16 18.765 66.96 19.035 ;
     RECT  2.16 19.305 66.96 19.575 ;
     RECT  2.16 19.845 66.96 20.115 ;
     RECT  2.16 20.385 66.96 20.655 ;
     RECT  2.16 20.925 66.96 21.195 ;
     RECT  2.16 21.465 66.96 21.735 ;
     RECT  2.16 22.005 66.96 22.275 ;
     RECT  2.16 22.545 66.96 22.815 ;
     RECT  2.16 23.085 66.96 23.355 ;
     RECT  2.16 23.625 66.96 23.895 ;
     RECT  2.16 24.165 66.96 24.435 ;
     RECT  2.16 24.705 66.96 24.975 ;
     RECT  2.16 25.245 66.96 25.515 ;
     RECT  2.16 25.785 66.96 26.055 ;
     RECT  2.16 26.325 66.96 26.595 ;
     RECT  2.16 26.865 66.96 27.135 ;
     RECT  2.16 27.405 66.96 27.675 ;
     RECT  2.16 27.945 66.96 28.215 ;
     RECT  2.16 28.485 66.96 28.755 ;
     RECT  2.16 29.025 66.96 29.295 ;
     RECT  2.16 29.565 66.96 29.835 ;
     RECT  2.16 30.105 66.96 30.375 ;
     RECT  2.16 30.645 66.96 30.915 ;
     RECT  2.16 31.185 66.96 31.455 ;
     RECT  2.16 31.725 66.96 31.995 ;
     RECT  2.16 32.265 66.96 32.535 ;
     RECT  2.16 32.805 66.96 33.075 ;
     RECT  2.16 33.345 66.96 33.615 ;
     RECT  2.16 33.885 66.96 34.155 ;
     RECT  2.16 34.425 66.96 34.695 ;
     RECT  2.16 34.965 66.96 35.235 ;
     RECT  2.16 35.505 66.96 35.775 ;
     RECT  2.16 36.045 66.96 36.315 ;
     RECT  2.16 36.585 66.96 36.855 ;
     RECT  2.16 37.125 66.96 37.395 ;
     RECT  2.16 37.665 66.96 37.935 ;
     RECT  2.16 38.205 66.96 38.475 ;
     RECT  2.16 38.745 66.96 39.015 ;
     RECT  2.16 39.285 66.96 39.555 ;
     RECT  2.16 39.825 66.96 40.095 ;
     RECT  2.16 40.365 66.96 40.635 ;
     RECT  2.16 40.905 66.96 41.175 ;
     RECT  2.16 41.445 66.96 41.715 ;
     RECT  2.16 41.985 66.96 42.255 ;
     RECT  2.16 42.525 66.96 42.795 ;
     RECT  2.16 43.065 66.96 43.335 ;
     RECT  2.16 43.605 66.96 43.875 ;
     RECT  2.16 44.145 66.96 44.415 ;
     RECT  2.16 44.685 66.96 44.955 ;
     RECT  2.16 45.225 66.96 45.495 ;
     RECT  2.16 45.765 66.96 46.035 ;
     RECT  2.16 46.305 66.96 46.575 ;
     RECT  2.16 46.845 66.96 47.115 ;
     RECT  2.16 47.385 66.96 47.655 ;
     RECT  2.16 47.925 66.96 48.195 ;
     RECT  2.16 48.465 66.96 48.735 ;
     RECT  2.16 49.005 66.96 49.275 ;
     RECT  2.16 49.545 66.96 49.815 ;
     RECT  2.16 50.085 66.96 50.355 ;
     RECT  2.16 50.625 66.96 50.895 ;
     RECT  2.16 51.165 66.96 51.435 ;
     RECT  2.16 51.705 66.96 51.975 ;
     RECT  2.16 52.245 66.96 52.515 ;
     RECT  2.16 52.785 66.96 53.055 ;
     RECT  2.16 53.325 66.96 53.595 ;
     RECT  2.16 53.865 66.96 54.135 ;
     RECT  2.16 54.405 66.96 54.675 ;
     RECT  2.16 54.945 66.96 55.215 ;
     RECT  2.16 55.485 66.96 55.755 ;
     RECT  2.16 56.025 66.96 56.295 ;
     RECT  2.16 56.565 66.96 56.835 ;
     RECT  2.16 57.105 66.96 57.375 ;
     RECT  2.16 57.645 66.96 57.915 ;
     RECT  2.16 58.185 66.96 58.455 ;
     RECT  2.16 58.725 66.96 58.995 ;
     RECT  2.16 59.265 66.96 59.535 ;
     RECT  2.16 59.805 66.96 60.075 ;
     RECT  2.16 60.345 66.96 60.615 ;
     RECT  2.16 60.885 66.96 61.155 ;
     RECT  2.16 61.425 66.96 61.695 ;
     RECT  2.16 61.965 66.96 62.235 ;
     RECT  2.16 62.505 66.96 62.775 ;
     RECT  2.16 63.045 66.96 63.315 ;
     RECT  2.16 63.585 66.96 63.855 ;
     RECT  2.16 64.125 66.96 64.395 ;
     RECT  2.16 64.665 66.96 64.935 ;
     RECT  2.16 65.205 66.96 65.475 ;
     RECT  2.16 65.745 66.96 66.015 ;
     RECT  2.16 66.285 66.96 66.555 ;
     RECT  2.16 66.825 66.96 66.96 ;
    LAYER RVTP ;
     RECT  2.16 2.295 66.96 2.565 ;
     RECT  2.16 2.835 66.96 3.105 ;
     RECT  2.16 3.375 66.96 3.645 ;
     RECT  2.16 3.915 66.96 4.185 ;
     RECT  2.16 4.455 66.96 4.725 ;
     RECT  2.16 4.995 66.96 5.265 ;
     RECT  2.16 5.535 66.96 5.805 ;
     RECT  2.16 6.075 66.96 6.345 ;
     RECT  2.16 6.615 66.96 6.885 ;
     RECT  2.16 7.155 66.96 7.425 ;
     RECT  2.16 7.695 66.96 7.965 ;
     RECT  2.16 8.235 66.96 8.505 ;
     RECT  2.16 8.775 66.96 9.045 ;
     RECT  2.16 9.315 66.96 9.585 ;
     RECT  2.16 9.855 66.96 10.125 ;
     RECT  2.16 10.395 66.96 10.665 ;
     RECT  2.16 10.935 66.96 11.205 ;
     RECT  2.16 11.475 66.96 11.745 ;
     RECT  2.16 12.015 66.96 12.285 ;
     RECT  2.16 12.555 66.96 12.825 ;
     RECT  2.16 13.095 66.96 13.365 ;
     RECT  2.16 13.635 66.96 13.905 ;
     RECT  2.16 14.175 66.96 14.445 ;
     RECT  2.16 14.715 66.96 14.985 ;
     RECT  2.16 15.255 66.96 15.525 ;
     RECT  2.16 15.795 66.96 16.065 ;
     RECT  2.16 16.335 66.96 16.605 ;
     RECT  2.16 16.875 66.96 17.145 ;
     RECT  2.16 17.415 66.96 17.685 ;
     RECT  2.16 17.955 66.96 18.225 ;
     RECT  2.16 18.495 66.96 18.765 ;
     RECT  2.16 19.035 66.96 19.305 ;
     RECT  2.16 19.575 66.96 19.845 ;
     RECT  2.16 20.115 66.96 20.385 ;
     RECT  2.16 20.655 66.96 20.925 ;
     RECT  2.16 21.195 66.96 21.465 ;
     RECT  2.16 21.735 66.96 22.005 ;
     RECT  2.16 22.275 66.96 22.545 ;
     RECT  2.16 22.815 66.96 23.085 ;
     RECT  2.16 23.355 66.96 23.625 ;
     RECT  2.16 23.895 66.96 24.165 ;
     RECT  2.16 24.435 66.96 24.705 ;
     RECT  2.16 24.975 66.96 25.245 ;
     RECT  2.16 25.515 66.96 25.785 ;
     RECT  2.16 26.055 66.96 26.325 ;
     RECT  2.16 26.595 66.96 26.865 ;
     RECT  2.16 27.135 66.96 27.405 ;
     RECT  2.16 27.675 66.96 27.945 ;
     RECT  2.16 28.215 66.96 28.485 ;
     RECT  2.16 28.755 66.96 29.025 ;
     RECT  2.16 29.295 66.96 29.565 ;
     RECT  2.16 29.835 66.96 30.105 ;
     RECT  2.16 30.375 66.96 30.645 ;
     RECT  2.16 30.915 66.96 31.185 ;
     RECT  2.16 31.455 66.96 31.725 ;
     RECT  2.16 31.995 66.96 32.265 ;
     RECT  2.16 32.535 66.96 32.805 ;
     RECT  2.16 33.075 66.96 33.345 ;
     RECT  2.16 33.615 66.96 33.885 ;
     RECT  2.16 34.155 66.96 34.425 ;
     RECT  2.16 34.695 66.96 34.965 ;
     RECT  2.16 35.235 66.96 35.505 ;
     RECT  2.16 35.775 66.96 36.045 ;
     RECT  2.16 36.315 66.96 36.585 ;
     RECT  2.16 36.855 66.96 37.125 ;
     RECT  2.16 37.395 66.96 37.665 ;
     RECT  2.16 37.935 66.96 38.205 ;
     RECT  2.16 38.475 66.96 38.745 ;
     RECT  2.16 39.015 66.96 39.285 ;
     RECT  2.16 39.555 66.96 39.825 ;
     RECT  2.16 40.095 66.96 40.365 ;
     RECT  2.16 40.635 66.96 40.905 ;
     RECT  2.16 41.175 66.96 41.445 ;
     RECT  2.16 41.715 66.96 41.985 ;
     RECT  2.16 42.255 66.96 42.525 ;
     RECT  2.16 42.795 66.96 43.065 ;
     RECT  2.16 43.335 66.96 43.605 ;
     RECT  2.16 43.875 66.96 44.145 ;
     RECT  2.16 44.415 66.96 44.685 ;
     RECT  2.16 44.955 66.96 45.225 ;
     RECT  2.16 45.495 66.96 45.765 ;
     RECT  2.16 46.035 66.96 46.305 ;
     RECT  2.16 46.575 66.96 46.845 ;
     RECT  2.16 47.115 66.96 47.385 ;
     RECT  2.16 47.655 66.96 47.925 ;
     RECT  2.16 48.195 66.96 48.465 ;
     RECT  2.16 48.735 66.96 49.005 ;
     RECT  2.16 49.275 66.96 49.545 ;
     RECT  2.16 49.815 66.96 50.085 ;
     RECT  2.16 50.355 66.96 50.625 ;
     RECT  2.16 50.895 66.96 51.165 ;
     RECT  2.16 51.435 66.96 51.705 ;
     RECT  2.16 51.975 66.96 52.245 ;
     RECT  2.16 52.515 66.96 52.785 ;
     RECT  2.16 53.055 66.96 53.325 ;
     RECT  2.16 53.595 66.96 53.865 ;
     RECT  2.16 54.135 66.96 54.405 ;
     RECT  2.16 54.675 66.96 54.945 ;
     RECT  2.16 55.215 66.96 55.485 ;
     RECT  2.16 55.755 66.96 56.025 ;
     RECT  2.16 56.295 66.96 56.565 ;
     RECT  2.16 56.835 66.96 57.105 ;
     RECT  2.16 57.375 66.96 57.645 ;
     RECT  2.16 57.915 66.96 58.185 ;
     RECT  2.16 58.455 66.96 58.725 ;
     RECT  2.16 58.995 66.96 59.265 ;
     RECT  2.16 59.535 66.96 59.805 ;
     RECT  2.16 60.075 66.96 60.345 ;
     RECT  2.16 60.615 66.96 60.885 ;
     RECT  2.16 61.155 66.96 61.425 ;
     RECT  2.16 61.695 66.96 61.965 ;
     RECT  2.16 62.235 66.96 62.505 ;
     RECT  2.16 62.775 66.96 63.045 ;
     RECT  2.16 63.315 66.96 63.585 ;
     RECT  2.16 63.855 66.96 64.125 ;
     RECT  2.16 64.395 66.96 64.665 ;
     RECT  2.16 64.935 66.96 65.205 ;
     RECT  2.16 65.475 66.96 65.745 ;
     RECT  2.16 66.015 66.96 66.285 ;
     RECT  2.16 66.555 66.96 66.825 ;
    LAYER M1 ;
     RECT  2.16 2.151 66.96 66.969 ;
    LAYER M2 ;
     RECT  0.103 44.118 0.139 44.136 ;
     RECT  0.103 20.322 0.203 20.574 ;
     RECT  0.103 21.942 0.203 21.96 ;
     RECT  0.103 27.576 0.203 27.594 ;
     RECT  0.103 28.611 0.203 28.629 ;
     RECT  0.103 29.466 0.203 29.484 ;
     RECT  0.103 35.712 0.203 35.964 ;
     RECT  0.103 38.448 0.203 40.428 ;
     RECT  0.103 41.922 0.203 41.94 ;
     RECT  0.139 44.046 0.203 44.136 ;
     RECT  0.103 48.438 0.203 48.456 ;
     RECT  0.103 34.128 0.239 34.146 ;
     RECT  0.203 44.046 0.239 44.064 ;
     RECT  0.203 39.096 0.275 39.114 ;
     RECT  0.103 30.888 0.347 31.914 ;
     RECT  0.535 22.554 0.635 23.346 ;
     RECT  0.535 33.048 0.635 33.174 ;
     RECT  0.535 47.286 0.635 47.484 ;
     RECT  0.535 27.918 2.155 27.936 ;
     RECT  0.535 17.586 2.16 17.604 ;
     RECT  0.535 20.934 2.16 21.456 ;
     RECT  0.635 22.554 2.16 22.572 ;
     RECT  0.635 23.328 2.16 23.346 ;
     RECT  2.155 27.216 2.16 27.936 ;
     RECT  0.347 31.122 2.16 31.914 ;
     RECT  0.635 33.048 2.16 33.066 ;
     RECT  2.155 34.596 2.16 34.614 ;
     RECT  0.203 35.946 2.16 35.964 ;
     RECT  0.535 42.156 2.16 42.174 ;
     RECT  0.635 47.286 2.16 47.304 ;
     RECT  2.16 2.151 17.671 66.969 ;
     RECT  17.671 2.151 18.779 67.014 ;
     RECT  18.779 2.151 24.511 66.969 ;
     RECT  24.511 2.151 26.591 67.014 ;
     RECT  26.591 2.151 38.731 66.969 ;
     RECT  38.731 2.106 38.947 66.969 ;
     RECT  38.947 1.962 39.379 66.969 ;
     RECT  39.379 1.881 39.739 66.969 ;
     RECT  39.739 1.881 39.839 67.239 ;
     RECT  39.839 1.881 40.955 66.969 ;
     RECT  40.955 1.926 41.027 66.969 ;
     RECT  41.027 1.962 42.395 66.969 ;
     RECT  42.331 1.152 42.431 1.17 ;
     RECT  42.395 2.151 45.139 66.969 ;
     RECT  45.139 2.106 45.751 66.969 ;
     RECT  45.967 1.152 46.139 1.17 ;
     RECT  45.751 2.07 47.039 66.969 ;
     RECT  47.039 2.106 47.831 66.969 ;
     RECT  47.831 2.151 50.179 66.969 ;
     RECT  50.179 1.926 51.791 66.969 ;
     RECT  51.791 2.106 52.951 66.969 ;
     RECT  52.951 2.034 53.951 66.969 ;
     RECT  53.951 2.106 54.527 66.969 ;
     RECT  54.527 2.151 66.96 66.969 ;
     RECT  66.96 19.746 67.811 51.534 ;
     RECT  67.811 25.254 67.847 44.91 ;
     RECT  67.811 19.746 68.387 24.462 ;
     RECT  67.847 25.254 68.387 42.552 ;
     RECT  67.847 43.308 68.387 44.91 ;
     RECT  67.811 45.774 68.387 51.534 ;
     RECT  68.387 19.746 68.423 22.374 ;
     RECT  68.387 23.166 68.423 24.462 ;
     RECT  68.387 25.254 68.423 28.314 ;
     RECT  68.387 29.268 68.423 33.174 ;
     RECT  68.387 35.442 68.423 36.072 ;
     RECT  68.387 38.016 68.423 39.312 ;
     RECT  68.387 40.986 68.423 42.444 ;
     RECT  68.387 43.308 68.423 44.712 ;
     RECT  68.387 47.286 68.423 49.572 ;
     RECT  68.423 20.628 68.459 22.374 ;
     RECT  68.423 26.136 68.459 27.162 ;
     RECT  68.459 26.136 68.495 26.964 ;
     RECT  68.423 32.472 68.495 32.904 ;
     RECT  68.459 20.628 68.999 21.834 ;
     RECT  68.423 38.016 68.999 38.304 ;
     RECT  68.387 40.104 68.999 40.194 ;
     RECT  68.423 40.986 68.999 42.084 ;
     RECT  68.387 50.364 68.999 51.534 ;
     RECT  68.999 20.664 69.035 20.682 ;
     RECT  68.999 21.438 69.035 21.834 ;
     RECT  68.423 23.94 69.035 24.462 ;
     RECT  68.423 25.254 69.035 25.272 ;
     RECT  68.495 26.136 69.035 26.424 ;
     RECT  68.423 28.026 69.035 28.044 ;
     RECT  68.423 30.348 69.035 31.41 ;
     RECT  68.495 32.472 69.035 32.49 ;
     RECT  68.387 33.966 69.035 34.686 ;
     RECT  68.423 35.442 69.035 35.802 ;
     RECT  68.999 38.016 69.035 38.034 ;
     RECT  68.423 39.294 69.035 39.312 ;
     RECT  68.999 40.104 69.035 40.122 ;
     RECT  68.999 41.49 69.035 42.084 ;
     RECT  68.423 43.308 69.035 44.289 ;
     RECT  68.387 45.774 69.035 46.404 ;
     RECT  68.423 47.286 69.035 47.916 ;
     RECT  68.423 48.978 69.035 49.572 ;
     RECT  68.999 50.364 69.035 51.228 ;
    LAYER M3 ;
     RECT  54.9 0.043 54.918 0.091 ;
     RECT  49.428 0.043 49.446 0.173 ;
     RECT  40.068 0.091 40.086 0.317 ;
     RECT  42.732 0.475 42.75 0.523 ;
     RECT  39.24 0.091 39.258 0.571 ;
     RECT  44.964 0.523 44.982 0.571 ;
     RECT  45.972 0.091 45.99 0.571 ;
     RECT  54.18 0.091 54.918 0.859 ;
     RECT  54 0.859 54.918 0.907 ;
     RECT  42.732 0.523 42.858 1.099 ;
     RECT  39.24 0.571 39.942 1.147 ;
     RECT  40.752 0.571 41.022 1.147 ;
     RECT  44.964 0.571 45.99 1.147 ;
     RECT  42.336 1.099 42.858 1.175 ;
     RECT  44.964 1.147 46.134 1.175 ;
     RECT  46.944 1.627 46.962 1.675 ;
     RECT  39.24 1.147 41.022 1.723 ;
     RECT  42.408 1.175 42.858 1.723 ;
     RECT  43.992 0.523 44.01 1.723 ;
     RECT  44.964 1.175 45.306 1.723 ;
     RECT  48.996 1.147 49.014 1.723 ;
     RECT  48.816 1.723 49.014 1.771 ;
     RECT  50.184 1.723 50.202 1.771 ;
     RECT  52.884 1.723 52.902 1.771 ;
     RECT  48.816 1.771 49.23 1.819 ;
     RECT  50.112 1.771 50.202 1.819 ;
     RECT  52.812 1.771 52.902 1.819 ;
     RECT  51.84 0.811 51.858 1.921 ;
     RECT  39.24 1.723 41.598 1.957 ;
     RECT  42.408 1.723 45.306 1.957 ;
     RECT  48.816 1.819 50.202 1.957 ;
     RECT  51.768 1.921 51.858 1.957 ;
     RECT  42.372 1.957 45.306 2.011 ;
     RECT  46.116 1.175 46.134 2.011 ;
     RECT  38.952 1.957 41.598 2.029 ;
     RECT  42.372 2.011 46.134 2.029 ;
     RECT  48.816 1.957 50.742 2.029 ;
     RECT  51.66 1.957 51.858 2.029 ;
     RECT  52.74 1.819 52.902 2.029 ;
     RECT  38.952 2.029 46.134 2.101 ;
     RECT  46.944 1.675 47.106 2.101 ;
     RECT  48.816 2.029 51.858 2.101 ;
     RECT  52.74 2.029 52.974 2.101 ;
     RECT  53.712 0.907 54.918 2.101 ;
     RECT  38.736 2.101 46.134 2.191 ;
     RECT  46.944 2.101 47.826 2.191 ;
     RECT  48.816 2.101 54.918 2.191 ;
     RECT  2.415 2.143 2.505 2.413 ;
     RECT  7.815 2.143 7.905 2.413 ;
     RECT  13.215 2.143 13.305 2.413 ;
     RECT  18.615 2.143 18.705 2.413 ;
     RECT  24.015 2.143 24.105 2.413 ;
     RECT  29.415 2.143 29.505 2.413 ;
     RECT  34.815 2.143 34.905 2.413 ;
     RECT  56.415 2.143 56.505 2.413 ;
     RECT  61.815 2.143 61.905 2.413 ;
     RECT  38.736 2.191 54.918 2.605 ;
     RECT  38.736 2.605 55.386 2.875 ;
     RECT  38.7 2.875 55.386 2.903 ;
     RECT  38.7 2.903 54.774 2.911 ;
     RECT  38.52 2.911 54.774 3.029 ;
     RECT  38.7 3.029 54.774 3.335 ;
     RECT  38.772 3.335 54.774 3.641 ;
     RECT  38.772 3.641 54.306 3.713 ;
     RECT  38.88 3.713 54.306 3.983 ;
     RECT  38.916 3.983 54.306 4.145 ;
     RECT  38.916 4.145 54.018 4.289 ;
     RECT  38.916 4.289 53.838 4.379 ;
     RECT  38.916 4.379 53.766 4.487 ;
     RECT  38.052 4.657 38.07 4.792 ;
     RECT  38.916 4.487 53.694 4.792 ;
     RECT  38.052 4.792 53.694 4.955 ;
     RECT  38.052 4.955 53.586 5.063 ;
     RECT  38.376 5.063 53.586 5.069 ;
     RECT  38.628 5.069 53.586 5.189 ;
     RECT  53.568 5.189 53.586 5.213 ;
     RECT  38.628 5.189 52.686 5.639 ;
     RECT  38.628 5.639 38.646 5.789 ;
     RECT  39.42 5.639 52.686 6.151 ;
     RECT  39.42 6.151 52.974 6.269 ;
     RECT  39.672 6.269 52.974 6.539 ;
     RECT  39.672 6.539 52.722 6.683 ;
     RECT  39.672 6.683 52.542 6.809 ;
     RECT  39.672 6.809 52.218 7.079 ;
     RECT  39.672 7.079 51.966 7.349 ;
     RECT  37.872 7.231 37.89 7.357 ;
     RECT  37.728 7.357 37.89 7.421 ;
     RECT  39.348 7.465 39.366 7.501 ;
     RECT  39.168 7.501 39.366 7.619 ;
     RECT  39.168 7.619 39.186 7.655 ;
     RECT  40.215 7.349 51.297 7.763 ;
     RECT  40.215 7.763 49.914 7.889 ;
     RECT  50.904 7.763 51.297 7.889 ;
     RECT  40.215 7.889 49.878 8.159 ;
     RECT  43.02 8.159 49.878 8.195 ;
     RECT  40.215 8.159 42.03 8.267 ;
     RECT  40.215 8.267 41.922 8.303 ;
     RECT  43.74 8.195 49.878 8.699 ;
     RECT  43.776 8.699 49.878 8.807 ;
     RECT  45.615 8.807 49.878 8.851 ;
     RECT  43.776 8.807 44.73 8.969 ;
     RECT  45.615 8.851 49.986 8.969 ;
     RECT  44.64 8.969 44.73 9.005 ;
     RECT  45.615 8.969 49.662 9.005 ;
     RECT  44.712 9.005 44.73 9.041 ;
     RECT  47.304 9.005 49.662 9.041 ;
     RECT  47.304 9.041 49.014 9.101 ;
     RECT  45.615 9.005 46.026 9.239 ;
     RECT  47.7 9.101 49.014 9.239 ;
     RECT  47.7 9.239 48.438 9.311 ;
     RECT  48.168 9.311 48.438 9.347 ;
     RECT  48.42 9.347 48.438 9.383 ;
     RECT  36.54 7.231 36.558 10.201 ;
     RECT  36.432 10.201 36.558 10.291 ;
     RECT  34.815 2.413 35.097 10.357 ;
     RECT  36.144 10.291 36.558 10.357 ;
     RECT  34.815 10.357 36.558 10.471 ;
     RECT  34.812 10.471 36.558 10.705 ;
     RECT  37.872 7.421 37.89 10.939 ;
     RECT  33.552 10.705 36.558 10.975 ;
     RECT  37.368 10.939 37.89 10.975 ;
     RECT  30.996 10.975 31.014 11.011 ;
     RECT  30.996 11.011 31.446 11.129 ;
     RECT  33.408 10.975 37.89 11.129 ;
     RECT  33.408 11.129 36.45 11.165 ;
     RECT  33.408 11.165 33.966 11.237 ;
     RECT  37.368 11.129 37.71 11.237 ;
     RECT  33.408 11.237 33.426 11.261 ;
     RECT  34.776 11.165 36.162 11.399 ;
     RECT  34.776 11.399 35.838 11.507 ;
     RECT  34.815 11.507 35.73 11.543 ;
     RECT  37.692 11.237 37.71 15.485 ;
     RECT  4.212 17.455 4.23 17.491 ;
     RECT  24.015 2.413 24.297 17.491 ;
     RECT  5.976 17.491 5.994 17.609 ;
     RECT  7.815 2.413 8.097 17.659 ;
     RECT  5.796 17.617 5.85 17.689 ;
     RECT  24.015 17.491 24.786 17.689 ;
     RECT  4.212 17.491 4.338 17.725 ;
     RECT  0.54 17.581 0.558 17.741 ;
     RECT  3.492 17.725 4.338 17.755 ;
     RECT  2.415 2.413 2.697 17.761 ;
     RECT  3.492 17.755 4.482 17.761 ;
     RECT  5.58 17.689 5.85 17.761 ;
     RECT  9.36 17.725 9.378 17.761 ;
     RECT  9.288 17.761 9.378 17.851 ;
     RECT  3.42 17.761 5.85 17.879 ;
     RECT  2.304 17.761 2.697 17.887 ;
     RECT  3.42 17.879 3.51 17.887 ;
     RECT  6.912 17.761 6.93 17.995 ;
     RECT  23.652 17.689 24.786 18.031 ;
     RECT  2.304 17.887 3.51 18.149 ;
     RECT  6.912 17.995 7.038 18.265 ;
     RECT  7.815 17.659 8.298 18.265 ;
     RECT  6.912 18.265 8.298 18.301 ;
     RECT  9.288 17.851 9.954 18.301 ;
     RECT  6.768 18.301 8.298 18.391 ;
     RECT  9.216 18.301 9.954 18.391 ;
     RECT  0.144 18.235 0.162 18.413 ;
     RECT  6.768 18.391 9.954 18.427 ;
     RECT  4.248 17.879 5.85 18.571 ;
     RECT  6.696 18.427 9.954 18.571 ;
     RECT  23.652 18.031 25.398 18.571 ;
     RECT  22.572 17.923 22.59 18.769 ;
     RECT  4.248 18.571 9.954 18.869 ;
     RECT  19.728 18.463 19.746 18.931 ;
     RECT  23.652 18.571 25.542 19.201 ;
     RECT  4.248 18.869 8.838 19.291 ;
     RECT  2.304 18.149 3.402 19.309 ;
     RECT  4.176 19.291 8.838 19.309 ;
     RECT  23.652 19.201 25.938 19.309 ;
     RECT  21.348 18.535 21.366 19.345 ;
     RECT  19.728 18.931 20.214 19.543 ;
     RECT  63 19.615 63.018 19.651 ;
     RECT  23.652 19.309 26.514 19.777 ;
     RECT  37.872 15.601 37.89 19.841 ;
     RECT  23.616 19.777 26.514 19.849 ;
     RECT  23.616 19.849 27.054 19.885 ;
     RECT  61.815 2.413 62.097 19.885 ;
     RECT  63 19.651 63.27 19.885 ;
     RECT  68.4 19.741 68.418 19.915 ;
     RECT  61.815 19.885 63.27 19.921 ;
     RECT  61.815 19.921 64.458 20.011 ;
     RECT  61.092 20.011 64.674 20.047 ;
     RECT  37.728 19.921 37.746 20.075 ;
     RECT  30.996 11.129 31.014 20.083 ;
     RECT  34.815 11.543 35.097 20.083 ;
     RECT  58.716 19.777 58.734 20.083 ;
     RECT  10.836 20.011 10.854 20.111 ;
     RECT  0.144 19.435 0.162 20.155 ;
     RECT  66.312 20.011 66.33 20.155 ;
     RECT  2.304 19.309 8.838 20.191 ;
     RECT  9.936 18.869 9.954 20.191 ;
     RECT  61.092 20.047 64.818 20.191 ;
     RECT  0.144 20.155 0.198 20.203 ;
     RECT  34.776 20.083 35.097 20.219 ;
     RECT  60.372 20.191 64.818 20.281 ;
     RECT  68.364 19.915 68.418 20.299 ;
     RECT  66.312 20.155 66.474 20.353 ;
     RECT  19.728 19.543 20.538 20.389 ;
     RECT  21.348 19.345 21.69 20.389 ;
     RECT  66.312 20.353 66.618 20.389 ;
     RECT  68.328 20.299 68.418 20.395 ;
     RECT  19.728 20.389 21.69 20.461 ;
     RECT  22.5 18.769 22.59 20.461 ;
     RECT  58.716 20.083 58.806 20.489 ;
     RECT  67.788 20.395 68.418 20.491 ;
     RECT  65.664 20.389 66.618 20.551 ;
     RECT  60.372 20.281 64.89 20.587 ;
     RECT  65.664 20.551 66.69 20.587 ;
     RECT  0.108 20.203 0.198 20.621 ;
     RECT  45.615 9.239 45.897 20.623 ;
     RECT  47.196 20.587 47.214 20.623 ;
     RECT  60.372 20.587 66.69 20.821 ;
     RECT  0.144 20.621 0.198 20.929 ;
     RECT  58.716 20.489 58.734 20.957 ;
     RECT  60.372 20.821 66.762 21.001 ;
     RECT  67.788 20.491 69.03 21.001 ;
     RECT  19.728 20.461 22.59 21.091 ;
     RECT  23.616 19.885 27.63 21.091 ;
     RECT  0.144 20.929 0.558 21.101 ;
     RECT  60.372 21.001 69.03 21.101 ;
     RECT  2.304 20.191 9.954 21.119 ;
     RECT  28.476 20.587 28.494 21.361 ;
     RECT  29.415 2.413 29.697 21.361 ;
     RECT  40.215 8.303 40.497 21.361 ;
     RECT  2.304 21.119 9.054 21.461 ;
     RECT  10.836 21.361 10.854 21.469 ;
     RECT  60.372 21.101 66.69 21.505 ;
     RECT  10.764 21.469 10.854 21.533 ;
     RECT  17.352 20.731 17.37 21.541 ;
     RECT  30.996 20.083 31.338 21.541 ;
     RECT  2.304 21.461 8.982 21.581 ;
     RECT  2.376 21.581 8.982 21.659 ;
     RECT  59.868 21.505 66.69 21.659 ;
     RECT  0.18 21.101 0.558 21.677 ;
     RECT  10.764 21.533 10.818 21.703 ;
     RECT  0.18 21.677 0.198 21.835 ;
     RECT  67.788 21.101 69.03 21.839 ;
     RECT  58.716 21.811 58.734 21.929 ;
     RECT  16.524 19.507 16.542 21.965 ;
     RECT  0.108 21.835 0.198 21.98 ;
     RECT  19.728 21.091 27.63 22.009 ;
     RECT  17.352 21.541 17.694 22.045 ;
     RECT  19.656 22.009 27.63 22.045 ;
     RECT  28.476 21.361 29.697 22.045 ;
     RECT  67.788 21.839 68.526 22.061 ;
     RECT  67.788 22.061 68.49 22.157 ;
     RECT  9.936 21.119 9.954 22.207 ;
     RECT  10.728 21.703 10.818 22.207 ;
     RECT  59.904 21.659 66.69 22.279 ;
     RECT  2.376 21.659 8.838 22.441 ;
     RECT  9.936 22.207 10.818 22.441 ;
     RECT  59.904 22.279 66.726 22.441 ;
     RECT  59.868 22.441 66.726 22.493 ;
     RECT  67.788 22.157 68.454 22.541 ;
     RECT  0.144 21.98 0.198 22.549 ;
     RECT  59.904 22.493 66.726 22.549 ;
     RECT  2.376 22.441 10.818 22.649 ;
     RECT  67.788 22.541 68.418 22.699 ;
     RECT  16.812 22.045 17.694 22.783 ;
     RECT  18.615 2.413 18.897 22.783 ;
     RECT  19.656 22.045 29.697 22.808 ;
     RECT  0.144 22.549 0.558 22.843 ;
     RECT  59.904 22.549 66.762 22.891 ;
     RECT  67.752 22.699 68.418 22.891 ;
     RECT  2.376 22.649 10.53 23.083 ;
     RECT  59.904 22.891 68.418 23.117 ;
     RECT  58.788 22.981 58.806 23.161 ;
     RECT  0.144 22.843 0.63 23.179 ;
     RECT  52.2 22.795 52.218 23.251 ;
     RECT  30.996 21.541 31.626 23.287 ;
     RECT  0.144 23.179 1.17 23.309 ;
     RECT  19.62 22.808 29.697 23.323 ;
     RECT  30.78 23.287 31.626 23.323 ;
     RECT  59.904 23.117 66.546 23.351 ;
     RECT  58.392 23.161 58.806 23.521 ;
     RECT  59.904 23.351 66.042 23.521 ;
     RECT  52.2 23.251 52.434 23.549 ;
     RECT  67.284 23.117 68.418 23.549 ;
     RECT  68.328 23.549 68.418 23.563 ;
     RECT  0.54 23.309 0.558 23.597 ;
     RECT  16.812 22.783 18.897 23.629 ;
     RECT  39.6 21.361 40.497 23.629 ;
     RECT  19.62 23.323 31.626 23.819 ;
     RECT  2.304 23.083 10.53 23.855 ;
     RECT  19.62 23.819 30.222 23.891 ;
     RECT  52.2 23.549 52.29 23.899 ;
     RECT  2.304 23.855 9.558 23.927 ;
     RECT  52.128 23.899 52.29 23.927 ;
     RECT  10.512 23.855 10.53 23.971 ;
     RECT  2.304 23.927 9.486 24.043 ;
     RECT  58.392 23.521 66.042 24.133 ;
     RECT  43.668 22.621 43.686 24.205 ;
     RECT  68.328 23.563 69.03 24.269 ;
     RECT  45.615 20.623 47.214 24.331 ;
     RECT  10.512 23.971 10.854 24.359 ;
     RECT  1.152 24.187 1.17 24.365 ;
     RECT  67.284 23.549 67.374 24.403 ;
     RECT  2.268 24.043 9.486 24.413 ;
     RECT  45.288 24.331 47.214 24.511 ;
     RECT  43.668 24.205 44.154 24.745 ;
     RECT  45.288 24.511 47.574 24.745 ;
     RECT  58.392 24.133 66.15 24.781 ;
     RECT  30.996 23.819 31.626 24.871 ;
     RECT  10.512 24.359 10.782 24.899 ;
     RECT  58.392 24.781 66.222 24.907 ;
     RECT  2.304 24.413 9.486 24.979 ;
     RECT  2.304 24.979 9.774 25.079 ;
     RECT  43.668 24.745 47.574 25.141 ;
     RECT  67.284 24.403 67.842 25.195 ;
     RECT  69.012 24.269 69.03 25.195 ;
     RECT  0.144 24.523 0.162 25.277 ;
     RECT  67.284 25.195 69.03 25.325 ;
     RECT  2.304 25.079 9.702 25.349 ;
     RECT  19.62 23.891 29.697 25.447 ;
     RECT  58.392 24.907 66.294 25.447 ;
     RECT  2.304 25.349 3.618 25.681 ;
     RECT  10.512 24.899 10.53 25.717 ;
     RECT  0.324 25.675 0.342 25.805 ;
     RECT  67.752 25.325 69.03 25.853 ;
     RECT  19.62 25.447 29.934 25.861 ;
     RECT  30.996 24.871 32.058 25.861 ;
     RECT  2.232 25.681 3.618 25.949 ;
     RECT  43.668 25.141 47.646 26.023 ;
     RECT  48.456 23.701 48.474 26.023 ;
     RECT  39.024 23.629 40.497 26.087 ;
     RECT  34.815 20.219 35.097 26.095 ;
     RECT  2.304 25.949 3.618 26.347 ;
     RECT  4.356 25.349 8.19 26.347 ;
     RECT  2.304 26.347 8.19 26.365 ;
     RECT  58.392 25.447 66.402 26.365 ;
     RECT  67.248 26.251 67.302 26.365 ;
     RECT  68.328 25.853 69.03 26.429 ;
     RECT  2.304 26.365 8.37 26.527 ;
     RECT  9.108 25.349 9.702 26.527 ;
     RECT  58.392 26.365 67.302 26.635 ;
     RECT  68.328 26.429 68.49 26.635 ;
     RECT  43.668 26.023 48.474 26.671 ;
     RECT  0.144 26.587 0.162 26.765 ;
     RECT  10.512 25.717 10.818 26.789 ;
     RECT  2.304 26.527 9.702 26.797 ;
     RECT  36.252 26.761 36.27 26.869 ;
     RECT  2.304 26.797 9.738 26.941 ;
     RECT  19.62 25.861 32.058 26.941 ;
     RECT  34.815 26.095 35.154 27.103 ;
     RECT  36.252 26.869 36.774 27.103 ;
     RECT  2.268 26.941 9.738 27.131 ;
     RECT  2.268 27.131 9.702 27.167 ;
     RECT  2.268 27.167 9.486 27.211 ;
     RECT  2.16 27.211 9.486 27.341 ;
     RECT  0.18 27.451 0.198 27.499 ;
     RECT  58.392 26.635 68.49 27.499 ;
     RECT  0.108 27.499 0.198 27.599 ;
     RECT  58.392 27.499 69.03 27.599 ;
     RECT  19.62 26.941 32.094 27.715 ;
     RECT  32.94 27.445 32.958 27.715 ;
     RECT  0.216 27.739 0.234 27.787 ;
     RECT  65.52 27.599 69.03 27.869 ;
     RECT  2.304 27.341 9.486 27.905 ;
     RECT  0.216 27.787 0.342 27.913 ;
     RECT  65.628 27.869 69.03 27.917 ;
     RECT  19.62 27.715 32.958 27.949 ;
     RECT  34.02 22.585 34.038 27.949 ;
     RECT  65.628 27.917 66.69 28.049 ;
     RECT  67.752 27.917 69.03 28.049 ;
     RECT  34.815 27.103 36.774 28.147 ;
     RECT  0.216 27.913 0.558 28.205 ;
     RECT  67.752 28.049 68.454 28.205 ;
     RECT  9.108 27.905 9.486 28.319 ;
     RECT  0.216 28.205 0.342 28.363 ;
     RECT  19.62 27.949 34.038 28.489 ;
     RECT  34.815 28.147 37.278 28.489 ;
     RECT  67.788 28.205 68.454 28.589 ;
     RECT  10.512 26.789 10.53 28.651 ;
     RECT  0.108 28.363 0.342 28.652 ;
     RECT  39.024 26.087 39.042 28.723 ;
     RECT  0.144 28.652 0.342 28.781 ;
     RECT  2.304 27.905 8.37 28.795 ;
     RECT  9.108 28.319 9.342 28.795 ;
     RECT  58.392 27.599 64.71 28.795 ;
     RECT  65.628 28.049 66.438 28.795 ;
     RECT  19.62 28.489 37.278 29.029 ;
     RECT  67.788 28.589 68.418 29.029 ;
     RECT  56.415 2.413 56.697 29.101 ;
     RECT  58.392 28.795 66.438 29.101 ;
     RECT  58.392 29.101 66.582 29.165 ;
     RECT  67.32 29.029 68.418 29.165 ;
     RECT  56.415 29.101 57.078 29.191 ;
     RECT  67.32 29.165 67.338 29.191 ;
     RECT  10.512 28.651 10.818 29.291 ;
     RECT  0.144 28.781 0.198 29.452 ;
     RECT  56.415 29.191 57.114 29.497 ;
     RECT  67.284 29.191 67.338 29.549 ;
     RECT  38.304 28.723 39.042 29.569 ;
     RECT  2.304 28.795 9.342 29.597 ;
     RECT  67.32 29.549 67.338 29.645 ;
     RECT  0.108 29.452 0.198 29.741 ;
     RECT  0.18 29.741 0.198 29.789 ;
     RECT  56.415 29.497 57.15 29.795 ;
     RECT  2.415 29.597 9.342 29.867 ;
     RECT  68.364 29.165 68.418 29.992 ;
     RECT  4.5 29.867 9.342 30.065 ;
     RECT  4.68 30.065 9.342 30.173 ;
     RECT  67.788 29.992 68.418 30.173 ;
     RECT  38.304 29.569 39.402 30.181 ;
     RECT  38.088 30.181 39.402 30.209 ;
     RECT  56.415 29.795 57.078 30.209 ;
     RECT  4.788 30.173 9.342 30.299 ;
     RECT  10.512 29.291 10.53 30.307 ;
     RECT  58.392 29.165 66.51 30.343 ;
     RECT  58.392 30.343 66.618 30.443 ;
     RECT  10.512 30.307 10.854 30.677 ;
     RECT  2.415 29.867 3.618 30.811 ;
     RECT  9.036 30.299 9.342 30.811 ;
     RECT  2.415 30.811 3.798 30.859 ;
     RECT  67.788 30.173 67.878 30.859 ;
     RECT  0.108 30.859 0.126 30.883 ;
     RECT  9.036 30.811 9.414 30.919 ;
     RECT  67.248 30.859 67.878 30.919 ;
     RECT  68.868 30.187 69.03 30.919 ;
     RECT  0.108 30.883 0.342 31.117 ;
     RECT  56.415 30.209 56.697 31.189 ;
     RECT  4.788 30.299 8.262 31.195 ;
     RECT  9.036 30.919 9.486 31.195 ;
     RECT  19.62 29.029 37.314 31.225 ;
     RECT  38.088 30.209 39.366 31.225 ;
     RECT  2.304 30.859 3.798 31.243 ;
     RECT  4.788 31.195 9.486 31.243 ;
     RECT  2.268 31.243 9.486 31.289 ;
     RECT  19.62 31.225 39.366 31.289 ;
     RECT  58.392 30.443 66.366 31.387 ;
     RECT  67.248 30.919 69.03 31.387 ;
     RECT  58.392 31.387 69.03 31.415 ;
     RECT  56.415 31.189 57.078 31.693 ;
     RECT  0.108 31.117 0.522 31.765 ;
     RECT  56.415 31.693 57.15 31.801 ;
     RECT  56.415 31.801 57.186 31.853 ;
     RECT  0.108 31.765 0.558 31.949 ;
     RECT  58.392 31.415 68.418 31.955 ;
     RECT  0.144 31.949 0.558 32.045 ;
     RECT  0.144 32.045 0.522 32.141 ;
     RECT  58.392 31.955 66.546 32.225 ;
     RECT  10.512 30.677 10.818 32.297 ;
     RECT  10.512 32.297 10.746 32.369 ;
     RECT  0.144 32.141 0.486 32.429 ;
     RECT  13.215 2.413 13.497 32.431 ;
     RECT  67.284 31.955 68.418 32.467 ;
     RECT  13.104 32.431 13.497 32.477 ;
     RECT  56.415 31.853 57.15 32.495 ;
     RECT  0.468 32.429 0.486 32.621 ;
     RECT  67.284 32.467 69.03 32.621 ;
     RECT  2.304 31.289 9.414 32.872 ;
     RECT  2.268 32.872 9.414 32.909 ;
     RECT  56.415 32.495 57.114 32.909 ;
     RECT  56.415 32.909 57.042 33.071 ;
     RECT  58.392 32.225 58.41 33.079 ;
     RECT  59.544 32.225 66.546 33.079 ;
     RECT  67.284 32.621 68.49 33.079 ;
     RECT  0.54 33.043 0.558 33.115 ;
     RECT  0.54 33.115 0.63 33.179 ;
     RECT  58.392 33.079 68.49 33.179 ;
     RECT  0.54 33.179 0.558 33.197 ;
     RECT  10.512 32.369 10.53 33.241 ;
     RECT  67.284 33.179 68.49 33.389 ;
     RECT  2.304 32.909 9.414 33.485 ;
     RECT  10.512 33.241 10.818 33.691 ;
     RECT  10.512 33.691 10.89 33.809 ;
     RECT  67.752 33.389 68.49 33.809 ;
     RECT  0.252 33.739 0.27 33.883 ;
     RECT  2.415 33.485 9.414 34.079 ;
     RECT  58.392 33.179 66.15 34.087 ;
     RECT  0.144 33.883 0.27 34.123 ;
     RECT  0.108 34.123 0.27 34.16 ;
     RECT  58.392 34.087 66.546 34.187 ;
     RECT  0.144 34.16 0.27 34.205 ;
     RECT  59.544 34.187 66.546 34.205 ;
     RECT  2.415 34.079 8.37 34.219 ;
     RECT  61.815 34.205 66.546 34.219 ;
     RECT  67.752 33.809 67.806 34.219 ;
     RECT  9.108 34.079 9.414 34.321 ;
     RECT  2.304 34.219 8.37 34.385 ;
     RECT  61.815 34.219 67.806 34.385 ;
     RECT  65.772 34.385 67.806 34.457 ;
     RECT  2.304 34.385 8.298 34.591 ;
     RECT  2.16 34.591 8.298 34.637 ;
     RECT  67.284 34.457 67.806 34.637 ;
     RECT  9.108 34.321 9.45 34.691 ;
     RECT  67.788 34.637 67.806 34.699 ;
     RECT  69.012 33.931 69.03 34.699 ;
     RECT  16.236 23.629 18.897 34.771 ;
     RECT  19.62 31.289 39.042 34.771 ;
     RECT  10.512 33.809 10.53 34.861 ;
     RECT  10.512 34.861 10.818 35.033 ;
     RECT  59.544 34.205 61.038 35.041 ;
     RECT  61.815 34.385 64.962 35.041 ;
     RECT  2.304 34.637 8.298 35.167 ;
     RECT  9.108 34.691 9.414 35.167 ;
     RECT  58.392 34.187 58.806 35.339 ;
     RECT  67.788 34.699 69.03 35.371 ;
     RECT  59.544 35.041 64.962 35.401 ;
     RECT  65.772 34.457 66.546 35.401 ;
     RECT  59.544 35.401 66.546 35.419 ;
     RECT  59.544 35.419 66.618 35.467 ;
     RECT  67.752 35.371 69.03 35.467 ;
     RECT  2.304 35.167 9.414 35.563 ;
     RECT  2.268 35.563 9.414 35.609 ;
     RECT  0.144 34.205 0.162 35.692 ;
     RECT  58.392 35.339 58.41 35.771 ;
     RECT  52.128 23.927 52.146 35.807 ;
     RECT  59.544 35.467 69.03 35.807 ;
     RECT  0.108 35.692 0.198 35.837 ;
     RECT  16.236 34.771 39.042 35.843 ;
     RECT  0.108 35.837 0.126 35.981 ;
     RECT  59.544 35.807 68.418 36.365 ;
     RECT  40.215 26.087 40.497 36.517 ;
     RECT  41.328 23.125 41.346 36.517 ;
     RECT  59.544 36.365 68.382 36.625 ;
     RECT  10.512 35.033 10.53 36.661 ;
     RECT  58.824 36.625 68.382 36.661 ;
     RECT  40.215 36.517 41.346 36.751 ;
     RECT  10.512 36.661 10.926 36.779 ;
     RECT  0.144 36.859 0.162 37.037 ;
     RECT  58.788 36.661 68.382 37.057 ;
     RECT  19.62 35.843 39.042 37.093 ;
     RECT  40.215 36.751 41.454 37.093 ;
     RECT  40.215 37.093 41.634 37.129 ;
     RECT  58.716 37.057 68.382 37.133 ;
     RECT  40.215 37.129 41.67 37.165 ;
     RECT  10.512 36.779 10.854 37.391 ;
     RECT  19.62 37.093 39.258 37.391 ;
     RECT  43.668 26.671 48.726 37.399 ;
     RECT  40.215 37.165 42.21 37.471 ;
     RECT  67.248 37.133 68.382 37.483 ;
     RECT  2.304 35.609 9.414 37.499 ;
     RECT  10.512 37.391 10.782 37.499 ;
     RECT  40.215 37.471 42.246 37.633 ;
     RECT  43.308 37.399 48.726 37.633 ;
     RECT  39.312 37.399 39.33 37.769 ;
     RECT  67.248 37.483 69.03 37.967 ;
     RECT  58.716 37.133 66.402 37.975 ;
     RECT  67.248 37.967 67.842 37.975 ;
     RECT  68.976 37.967 69.03 38.039 ;
     RECT  58.716 37.975 67.842 38.093 ;
     RECT  67.284 38.093 67.842 38.189 ;
     RECT  6.912 37.499 9.414 38.2 ;
     RECT  6.912 38.2 9.522 38.237 ;
     RECT  2.304 37.499 6.174 38.245 ;
     RECT  6.912 38.237 9.486 38.245 ;
     RECT  2.304 38.245 9.486 38.273 ;
     RECT  67.824 38.189 67.842 38.285 ;
     RECT  68.976 38.039 68.994 38.309 ;
     RECT  58.716 38.093 66.222 38.333 ;
     RECT  0.108 38.347 0.126 38.395 ;
     RECT  19.62 37.391 38.538 38.407 ;
     RECT  58.788 38.333 66.222 38.507 ;
     RECT  4.428 38.273 9.486 38.543 ;
     RECT  10.512 37.499 10.53 38.551 ;
     RECT  66.204 38.507 66.222 38.669 ;
     RECT  58.788 38.507 58.806 38.705 ;
     RECT  59.544 38.507 65.43 38.765 ;
     RECT  16.236 35.843 18.897 38.768 ;
     RECT  19.62 38.407 38.79 38.768 ;
     RECT  2.304 38.273 3.546 38.923 ;
     RECT  10.512 38.551 10.854 38.939 ;
     RECT  0.108 38.395 0.198 39.019 ;
     RECT  2.268 38.923 3.546 39.091 ;
     RECT  16.236 38.768 38.79 39.091 ;
     RECT  66.6 38.911 66.726 39.091 ;
     RECT  66.6 39.091 67.338 39.115 ;
     RECT  68.4 38.821 68.418 39.115 ;
     RECT  66.6 39.115 68.418 39.211 ;
     RECT  0.108 39.019 0.342 39.245 ;
     RECT  16.236 39.091 38.97 39.245 ;
     RECT  2.268 39.091 3.69 39.289 ;
     RECT  4.428 38.543 9.414 39.289 ;
     RECT  59.544 38.765 60.21 39.293 ;
     RECT  59.544 39.293 60.066 39.353 ;
     RECT  2.268 39.289 9.414 39.437 ;
     RECT  60.984 38.765 65.43 39.623 ;
     RECT  61.38 39.623 65.43 39.631 ;
     RECT  66.6 39.211 69.03 39.631 ;
     RECT  10.512 38.939 10.782 39.901 ;
     RECT  10.512 39.901 10.818 40.019 ;
     RECT  58.752 39.757 58.77 40.027 ;
     RECT  2.304 39.437 9.414 40.127 ;
     RECT  16.236 39.245 38.862 40.369 ;
     RECT  61.38 39.631 69.03 40.369 ;
     RECT  0.108 39.245 0.198 40.433 ;
     RECT  60.66 40.369 69.03 40.433 ;
     RECT  67.248 40.433 69.03 40.469 ;
     RECT  58.716 40.027 58.77 40.531 ;
     RECT  0.144 40.433 0.162 40.637 ;
     RECT  60.66 40.433 66.294 40.637 ;
     RECT  58.716 40.531 58.806 40.711 ;
     RECT  59.544 39.353 59.886 40.711 ;
     RECT  58.716 40.711 59.886 40.936 ;
     RECT  60.66 40.637 60.966 40.936 ;
     RECT  2.412 40.127 9.414 41.035 ;
     RECT  2.304 41.035 9.414 41.071 ;
     RECT  2.304 41.071 9.702 41.131 ;
     RECT  58.716 40.936 60.966 41.165 ;
     RECT  2.232 41.131 9.702 41.171 ;
     RECT  16.236 40.369 39.438 41.215 ;
     RECT  40.215 37.633 48.726 41.215 ;
     RECT  61.815 40.637 66.294 41.215 ;
     RECT  67.284 40.469 69.03 41.215 ;
     RECT  61.815 41.215 69.03 41.261 ;
     RECT  10.512 40.019 10.53 41.341 ;
     RECT  58.752 41.165 60.966 41.485 ;
     RECT  54.72 41.413 54.738 41.513 ;
     RECT  58.752 41.485 61.074 41.521 ;
     RECT  61.815 41.261 66.762 41.521 ;
     RECT  10.512 41.341 10.926 41.549 ;
     RECT  67.752 41.261 69.03 41.639 ;
     RECT  0.18 41.755 0.198 41.803 ;
     RECT  0.108 41.803 0.198 41.948 ;
     RECT  58.752 41.521 66.762 41.989 ;
     RECT  58.716 41.989 66.762 42.089 ;
     RECT  67.788 41.639 69.03 42.089 ;
     RECT  0.144 41.948 0.198 42.125 ;
     RECT  0.54 42.151 0.558 42.413 ;
     RECT  59.508 42.089 66.762 42.521 ;
     RECT  58.716 42.089 58.734 42.629 ;
     RECT  60.624 42.521 66.762 42.667 ;
     RECT  67.788 42.089 68.418 42.667 ;
     RECT  10.512 41.549 10.53 42.763 ;
     RECT  59.508 42.521 59.886 42.871 ;
     RECT  10.512 42.763 10.818 42.899 ;
     RECT  2.304 41.171 9.702 42.989 ;
     RECT  10.512 42.899 10.782 42.989 ;
     RECT  4.14 42.989 9.702 43.169 ;
     RECT  2.304 42.989 3.366 43.181 ;
     RECT  60.624 42.667 68.418 43.243 ;
     RECT  58.752 42.871 59.886 43.411 ;
     RECT  60.624 43.243 69.03 43.411 ;
     RECT  58.752 43.411 69.03 43.531 ;
     RECT  58.716 43.531 69.03 43.637 ;
     RECT  13.215 32.477 13.497 43.672 ;
     RECT  58.788 43.637 60.174 43.709 ;
     RECT  13.104 43.672 13.497 43.808 ;
     RECT  2.415 43.181 3.366 43.915 ;
     RECT  10.512 42.989 10.53 43.915 ;
     RECT  0.144 43.387 0.162 44.041 ;
     RECT  10.512 43.915 10.746 44.041 ;
     RECT  2.304 43.915 3.366 44.077 ;
     RECT  4.14 43.169 9.522 44.077 ;
     RECT  0.144 44.041 0.234 44.092 ;
     RECT  0.108 44.092 0.234 44.141 ;
     RECT  60.948 43.637 69.03 44.141 ;
     RECT  10.512 44.041 10.818 44.176 ;
     RECT  2.304 44.077 9.522 44.203 ;
     RECT  59.544 43.709 60.174 44.213 ;
     RECT  2.268 44.203 9.522 44.339 ;
     RECT  2.304 44.339 9.522 44.447 ;
     RECT  60.948 44.141 67.014 44.477 ;
     RECT  60.156 44.213 60.174 44.581 ;
     RECT  58.788 43.709 58.806 44.761 ;
     RECT  0.144 44.141 0.234 44.813 ;
     RECT  61.128 44.477 67.014 44.813 ;
     RECT  58.716 44.761 58.806 44.879 ;
     RECT  61.128 44.813 66.078 44.879 ;
     RECT  0.216 44.813 0.234 44.909 ;
     RECT  60.156 44.581 60.318 44.987 ;
     RECT  67.752 44.141 69.03 44.995 ;
     RECT  67.248 44.995 69.03 45.101 ;
     RECT  59.868 45.265 60.066 45.301 ;
     RECT  59.796 45.301 60.066 45.341 ;
     RECT  2.415 44.447 9.522 45.355 ;
     RECT  10.512 44.176 10.854 45.419 ;
     RECT  59.868 45.341 60.066 45.419 ;
     RECT  61.128 44.879 66.006 45.563 ;
     RECT  61.128 45.563 62.226 45.571 ;
     RECT  58.788 44.879 58.806 45.661 ;
     RECT  63.108 45.563 66.006 45.661 ;
     RECT  67.248 45.101 67.806 45.689 ;
     RECT  14.94 45.733 14.958 45.841 ;
     RECT  63.108 45.661 66.33 45.931 ;
     RECT  69.012 45.101 69.03 45.931 ;
     RECT  16.236 41.215 48.726 45.959 ;
     RECT  68.976 45.931 69.03 46.027 ;
     RECT  14.868 45.841 14.958 46.031 ;
     RECT  63.108 45.931 66.366 46.039 ;
     RECT  67.248 45.689 67.338 46.039 ;
     RECT  0.324 45.931 0.342 46.061 ;
     RECT  16.236 45.959 48.15 46.067 ;
     RECT  16.236 46.067 17.406 46.109 ;
     RECT  18.615 46.067 48.15 46.139 ;
     RECT  63.108 46.039 67.338 46.157 ;
     RECT  10.512 45.419 10.818 46.201 ;
     RECT  63.108 46.157 66.366 46.229 ;
     RECT  58.716 45.661 58.806 46.237 ;
     RECT  67.284 46.157 67.338 46.253 ;
     RECT  16.236 46.109 16.794 46.301 ;
     RECT  60.948 45.571 62.226 46.309 ;
     RECT  63.108 46.229 66.114 46.309 ;
     RECT  14.868 46.031 14.886 46.381 ;
     RECT  68.364 46.027 69.03 46.409 ;
     RECT  14.832 46.381 14.886 46.499 ;
     RECT  58.716 46.237 58.878 46.507 ;
     RECT  58.716 46.507 58.914 46.679 ;
     RECT  68.364 46.409 68.382 46.699 ;
     RECT  0.144 46.555 0.162 46.733 ;
     RECT  59.868 45.419 60.03 46.813 ;
     RECT  60.948 46.309 66.114 46.849 ;
     RECT  67.284 46.253 67.302 46.891 ;
     RECT  2.304 45.355 9.522 46.913 ;
     RECT  10.512 46.201 10.854 46.949 ;
     RECT  60.84 46.849 66.114 47.011 ;
     RECT  10.764 46.949 10.854 47.039 ;
     RECT  59.724 46.813 60.03 47.047 ;
     RECT  14.868 46.499 14.886 47.075 ;
     RECT  67.248 46.891 67.302 47.119 ;
     RECT  68.328 46.699 68.382 47.119 ;
     RECT  60.84 47.011 66.222 47.191 ;
     RECT  67.248 47.119 68.382 47.272 ;
     RECT  59.724 47.047 60.102 47.317 ;
     RECT  60.84 47.191 66.33 47.317 ;
     RECT  0.54 47.281 0.558 47.419 ;
     RECT  0.54 47.419 0.63 47.489 ;
     RECT  0.54 47.489 0.558 47.501 ;
     RECT  59.724 47.317 66.33 47.651 ;
     RECT  59.868 47.651 66.33 47.695 ;
     RECT  67.248 47.272 69.03 47.695 ;
     RECT  10.764 47.039 10.818 47.723 ;
     RECT  10.8 47.723 10.818 47.759 ;
     RECT  58.716 46.679 58.878 47.759 ;
     RECT  59.868 47.695 69.03 47.921 ;
     RECT  59.868 47.921 68.994 47.981 ;
     RECT  2.304 46.913 9.414 48.001 ;
     RECT  59.868 47.981 68.418 48.119 ;
     RECT  16.236 46.301 16.254 48.227 ;
     RECT  18.615 46.139 47.79 48.271 ;
     RECT  2.304 48.001 9.486 48.299 ;
     RECT  0.108 48.331 0.126 48.379 ;
     RECT  59.976 48.119 60.066 48.389 ;
     RECT  59.976 48.389 59.994 48.413 ;
     RECT  60.948 48.119 68.418 48.461 ;
     RECT  0.108 48.379 0.198 48.476 ;
     RECT  18.615 48.271 47.862 48.505 ;
     RECT  58.716 47.759 58.734 48.505 ;
     RECT  10.836 48.469 10.854 48.541 ;
     RECT  0.144 48.476 0.162 48.653 ;
     RECT  10.836 48.541 10.926 48.659 ;
     RECT  10.836 48.659 10.854 48.695 ;
     RECT  61.815 48.461 68.418 48.803 ;
     RECT  18.615 48.505 48.51 48.811 ;
     RECT  67.248 48.803 68.418 48.811 ;
     RECT  67.248 48.811 69.03 48.929 ;
     RECT  49.752 47.353 49.77 49.009 ;
     RECT  2.304 48.299 9.414 49.045 ;
     RECT  60.948 48.461 61.002 49.051 ;
     RECT  18.615 48.811 48.69 49.081 ;
     RECT  49.644 49.009 49.77 49.081 ;
     RECT  2.304 49.045 9.558 49.133 ;
     RECT  58.716 48.505 58.806 49.387 ;
     RECT  60.912 49.051 61.002 49.441 ;
     RECT  61.815 48.803 66.366 49.441 ;
     RECT  58.716 49.387 58.878 49.505 ;
     RECT  2.415 49.133 9.558 49.577 ;
     RECT  2.415 49.577 8.982 49.811 ;
     RECT  14.832 49.711 14.85 49.811 ;
     RECT  60.912 49.441 66.366 49.855 ;
     RECT  60.912 49.855 66.618 50.059 ;
     RECT  67.788 48.929 69.03 50.059 ;
     RECT  18.615 49.081 49.77 50.089 ;
     RECT  18.615 50.089 49.878 50.125 ;
     RECT  58.716 49.505 58.842 50.153 ;
     RECT  2.415 49.811 3.474 50.189 ;
     RECT  4.32 49.811 8.982 50.189 ;
     RECT  58.752 50.153 58.842 50.351 ;
     RECT  18.615 50.125 50.022 50.359 ;
     RECT  4.464 50.189 8.982 50.459 ;
     RECT  60.804 50.059 69.03 50.459 ;
     RECT  60.804 50.459 66.726 50.477 ;
     RECT  59.868 49.855 59.886 50.521 ;
     RECT  60.804 50.477 66.618 50.521 ;
     RECT  4.464 50.459 6.354 50.585 ;
     RECT  18.615 50.359 50.202 50.593 ;
     RECT  51.015 7.889 51.297 50.593 ;
     RECT  7.38 50.459 8.982 50.621 ;
     RECT  59.868 50.521 66.618 50.693 ;
     RECT  18.615 50.593 51.297 50.791 ;
     RECT  7.38 50.621 8.586 50.855 ;
     RECT  58.752 50.351 58.806 50.899 ;
     RECT  3.42 50.189 3.474 50.963 ;
     RECT  67.752 50.459 69.03 51.089 ;
     RECT  6.336 50.585 6.354 51.125 ;
     RECT  59.868 50.693 60.39 51.125 ;
     RECT  60.372 51.125 60.39 51.197 ;
     RECT  67.788 51.089 69.03 51.197 ;
     RECT  58.716 50.899 58.806 51.233 ;
     RECT  68.976 51.197 69.03 51.233 ;
     RECT  61.128 50.693 66.618 51.269 ;
     RECT  67.788 51.197 67.806 51.359 ;
     RECT  4.464 50.585 5.022 51.395 ;
     RECT  5.004 51.395 5.022 51.467 ;
     RECT  3.456 50.963 3.474 51.503 ;
     RECT  61.128 51.269 66.33 51.539 ;
     RECT  68.976 51.233 68.994 51.539 ;
     RECT  61.128 51.539 63.666 51.629 ;
     RECT  64.44 51.539 66.33 51.629 ;
     RECT  7.815 50.855 8.586 51.665 ;
     RECT  61.128 51.629 63.486 51.677 ;
     RECT  61.74 51.677 63.486 51.773 ;
     RECT  64.44 51.629 64.854 51.899 ;
     RECT  65.844 51.629 65.862 51.899 ;
     RECT  18.615 50.791 51.354 51.935 ;
     RECT  61.815 51.773 63.486 51.935 ;
     RECT  64.836 51.899 64.854 51.935 ;
     RECT  58.716 51.233 58.734 52.079 ;
     RECT  61.815 51.935 62.802 52.079 ;
     RECT  18.615 51.935 51.297 63.211 ;
     RECT  18.396 63.211 51.297 63.275 ;
     RECT  18.468 63.275 51.297 64.165 ;
     RECT  18.432 64.165 51.297 64.327 ;
     RECT  18.216 64.327 51.297 64.705 ;
     RECT  18 64.705 51.297 64.867 ;
     RECT  17.748 64.867 51.297 65.245 ;
     RECT  17.676 65.245 51.297 65.515 ;
     RECT  17.568 65.515 51.297 66.325 ;
     RECT  17.46 66.325 51.297 66.479 ;
     RECT  2.415 50.189 2.697 66.707 ;
     RECT  7.815 51.665 8.097 66.707 ;
     RECT  13.215 43.808 13.497 66.707 ;
     RECT  50.976 66.479 51.297 66.707 ;
     RECT  56.415 33.071 56.697 66.707 ;
     RECT  61.815 52.079 62.097 66.707 ;
     RECT  17.46 66.479 50.202 66.749 ;
     RECT  50.976 66.707 51.105 66.749 ;
     RECT  29.268 66.749 50.202 66.785 ;
     RECT  17.46 66.749 27.27 66.797 ;
     RECT  20.7 66.797 27.27 66.893 ;
     RECT  29.268 66.785 43.326 66.893 ;
     RECT  2.415 66.707 2.505 66.977 ;
     RECT  7.815 66.707 7.905 66.977 ;
     RECT  13.215 66.707 13.305 66.977 ;
     RECT  29.268 66.893 43.29 66.977 ;
     RECT  51.015 66.749 51.105 66.977 ;
     RECT  56.415 66.707 56.505 66.977 ;
     RECT  61.815 66.707 61.905 66.977 ;
     RECT  17.46 66.797 19.89 67.085 ;
     RECT  20.772 66.893 24.858 67.085 ;
     RECT  29.268 66.977 29.358 67.133 ;
     RECT  44.28 66.785 50.202 67.133 ;
     RECT  17.46 67.085 18.45 67.181 ;
     RECT  30.132 66.977 43.29 67.181 ;
     RECT  50.184 67.133 50.202 67.181 ;
     RECT  19.188 67.085 19.89 67.229 ;
     RECT  24.768 67.085 24.858 67.229 ;
     RECT  30.168 67.181 43.146 67.229 ;
     RECT  19.296 67.229 19.89 67.277 ;
     RECT  20.772 67.085 23.994 67.277 ;
     RECT  24.84 67.229 24.858 67.277 ;
     RECT  25.776 66.893 27.27 67.277 ;
     RECT  29.34 67.133 29.358 67.277 ;
     RECT  30.168 67.229 40.194 67.277 ;
     RECT  40.932 67.229 43.146 67.277 ;
     RECT  44.28 67.133 49.41 67.277 ;
     RECT  26.712 67.277 27.27 67.325 ;
     RECT  31.68 67.277 32.958 67.325 ;
     RECT  39.78 67.277 40.194 67.325 ;
     RECT  44.28 67.277 44.298 67.325 ;
     RECT  45.18 67.277 45.198 67.325 ;
     RECT  38.088 67.277 38.754 67.373 ;
     RECT  20.772 67.277 20.79 67.853 ;
     RECT  30.6 67.277 30.762 67.853 ;
     RECT  31.788 67.325 32.958 67.853 ;
     RECT  33.84 67.277 34.47 67.853 ;
     RECT  38.088 67.373 38.106 67.853 ;
     RECT  40.932 67.277 41.274 67.853 ;
     RECT  17.46 67.181 18.234 67.901 ;
     RECT  30.744 67.853 30.762 67.901 ;
     RECT  32.94 67.853 32.958 67.901 ;
     RECT  40.968 67.853 41.274 67.901 ;
     RECT  27.216 67.325 27.27 68.381 ;
     RECT  18 67.901 18.234 68.429 ;
     RECT  19.872 67.277 19.89 68.429 ;
     RECT  23.724 67.277 23.742 68.429 ;
     RECT  33.84 67.853 34.362 68.429 ;
     RECT  39.78 67.325 40.158 68.429 ;
     RECT  18.18 68.429 18.234 68.477 ;
     RECT  46.368 67.277 46.494 68.525 ;
     RECT  29.16 68.635 29.178 68.731 ;
     RECT  23.184 68.779 23.202 68.875 ;
     RECT  42.552 67.277 43.146 68.875 ;
     RECT  29.16 68.731 29.214 68.909 ;
     RECT  18.18 68.477 18.198 69.005 ;
     RECT  22.14 68.875 23.202 69.005 ;
     RECT  25.092 68.875 25.434 69.005 ;
     RECT  27.216 68.381 27.234 69.005 ;
     RECT  29.196 68.909 29.214 69.005 ;
     RECT  30.924 68.779 30.942 69.005 ;
     RECT  31.896 67.853 31.914 69.005 ;
     RECT  34.344 68.429 34.362 69.005 ;
     RECT  37.98 68.875 37.998 69.005 ;
     RECT  39.78 68.429 39.798 69.005 ;
     RECT  40.968 67.901 40.986 69.005 ;
     RECT  42.552 68.875 43.866 69.005 ;
     RECT  44.856 68.875 44.874 69.005 ;
     RECT  46.476 68.525 46.494 69.005 ;
     RECT  48.996 67.277 49.014 69.005 ;
    LAYER M4 ;
     RECT  0.084 17.712 0.569 17.736 ;
     RECT  0.06 17.736 0.569 17.808 ;
     RECT  0.084 17.808 0.569 17.832 ;
     RECT  0.06 17.832 0.569 17.904 ;
     RECT  0.084 17.904 0.569 17.928 ;
     RECT  0.06 17.928 0.569 18 ;
     RECT  0.084 18 0.569 18.024 ;
     RECT  0.06 18.024 0.569 18.096 ;
     RECT  0.084 18.096 0.569 18.12 ;
     RECT  0.06 18.12 0.569 18.192 ;
     RECT  0.084 18.192 0.569 18.216 ;
     RECT  0.06 18.216 0.569 18.288 ;
     RECT  0.084 18.288 0.569 18.312 ;
     RECT  0.06 18.312 0.569 18.384 ;
     RECT  0.084 18.384 0.569 18.408 ;
     RECT  0.06 18.408 0.569 18.48 ;
     RECT  0.084 18.48 0.569 18.504 ;
     RECT  0.06 18.504 0.569 18.576 ;
     RECT  0.084 18.576 0.569 18.6 ;
     RECT  0.06 18.6 0.569 18.672 ;
     RECT  0.084 18.672 0.569 18.696 ;
     RECT  0.06 18.696 0.569 18.768 ;
     RECT  0.084 18.768 0.569 18.792 ;
     RECT  0.06 18.792 0.569 18.864 ;
     RECT  0.084 18.864 0.569 18.888 ;
     RECT  0.06 18.888 0.569 18.96 ;
     RECT  0.084 18.96 0.569 18.984 ;
     RECT  0.06 18.984 0.569 19.056 ;
     RECT  0.084 19.056 0.569 19.08 ;
     RECT  0.06 19.08 0.569 19.152 ;
     RECT  0.084 19.152 0.569 19.176 ;
     RECT  0.06 19.176 0.569 19.248 ;
     RECT  0.084 19.248 0.569 19.272 ;
     RECT  0.06 19.272 0.569 19.344 ;
     RECT  0.084 19.344 0.569 19.368 ;
     RECT  0.06 19.368 0.569 19.44 ;
     RECT  0.084 19.44 0.569 19.464 ;
     RECT  0.06 19.464 0.569 19.536 ;
     RECT  0.084 19.536 0.569 19.56 ;
     RECT  0.06 19.56 0.569 19.632 ;
     RECT  0.084 19.632 0.569 19.656 ;
     RECT  0.06 19.656 0.569 19.728 ;
     RECT  0.084 19.728 0.569 19.752 ;
     RECT  0.06 19.752 0.569 19.824 ;
     RECT  0.084 19.824 0.569 19.848 ;
     RECT  0.06 19.848 0.569 19.92 ;
     RECT  0.084 19.92 0.569 19.944 ;
     RECT  0.06 19.944 0.569 20.016 ;
     RECT  0.084 20.016 0.569 20.04 ;
     RECT  0.06 20.04 0.569 20.112 ;
     RECT  0.084 20.112 0.569 20.136 ;
     RECT  0.06 20.136 0.569 20.208 ;
     RECT  0.084 20.208 0.569 20.232 ;
     RECT  0.06 20.232 0.569 20.304 ;
     RECT  0.084 20.304 0.569 20.328 ;
     RECT  0.06 20.328 0.569 20.4 ;
     RECT  0.084 20.4 0.569 20.424 ;
     RECT  0.06 20.424 0.569 20.496 ;
     RECT  0.084 20.496 0.569 20.52 ;
     RECT  0.06 20.52 0.569 20.592 ;
     RECT  0.084 20.592 0.569 20.616 ;
     RECT  0.06 20.616 0.569 20.688 ;
     RECT  0.084 20.688 0.569 20.712 ;
     RECT  0.06 20.712 0.569 20.784 ;
     RECT  0.084 20.784 0.569 20.808 ;
     RECT  0.06 20.808 0.569 20.88 ;
     RECT  0.084 20.88 0.569 20.904 ;
     RECT  0.06 20.904 0.569 20.976 ;
     RECT  0.084 20.976 0.569 21 ;
     RECT  0.06 21 0.569 21.072 ;
     RECT  0.084 21.072 0.569 21.096 ;
     RECT  0.06 21.096 0.569 21.168 ;
     RECT  0.084 21.168 0.569 21.192 ;
     RECT  0.06 21.192 0.569 21.264 ;
     RECT  0.084 21.264 0.569 21.288 ;
     RECT  0.06 21.288 0.569 21.36 ;
     RECT  0.084 21.36 0.569 21.384 ;
     RECT  0.06 21.384 0.569 21.456 ;
     RECT  0.084 21.456 0.569 21.48 ;
     RECT  0.06 21.48 0.569 21.552 ;
     RECT  0.084 21.552 0.569 21.576 ;
     RECT  0.06 21.576 0.569 21.648 ;
     RECT  0.084 21.648 0.569 21.672 ;
     RECT  0.06 21.672 0.569 21.744 ;
     RECT  0.084 21.744 0.569 21.768 ;
     RECT  0.06 21.768 0.569 21.84 ;
     RECT  0.084 21.84 0.569 21.864 ;
     RECT  0.06 21.864 0.569 21.936 ;
     RECT  0.084 21.936 0.569 21.96 ;
     RECT  0.06 21.96 0.569 22.032 ;
     RECT  0.084 22.032 0.569 22.056 ;
     RECT  0.06 22.056 0.569 22.128 ;
     RECT  0.084 22.128 0.569 22.152 ;
     RECT  0.06 22.152 0.569 22.224 ;
     RECT  0.084 22.224 0.569 22.248 ;
     RECT  0.06 22.248 0.569 22.32 ;
     RECT  0.084 22.32 0.569 22.344 ;
     RECT  0.06 22.344 0.569 22.416 ;
     RECT  0.084 22.416 0.569 22.44 ;
     RECT  0.06 22.44 0.569 22.512 ;
     RECT  0.084 22.512 0.569 22.536 ;
     RECT  0.06 22.536 0.569 22.608 ;
     RECT  0.084 22.608 0.569 22.632 ;
     RECT  0.06 22.632 0.569 22.704 ;
     RECT  0.084 22.704 0.569 22.728 ;
     RECT  0.06 22.728 0.569 22.8 ;
     RECT  0.084 22.8 0.569 22.824 ;
     RECT  0.06 22.824 0.569 22.896 ;
     RECT  0.084 22.896 0.569 22.92 ;
     RECT  0.06 22.92 0.569 22.992 ;
     RECT  0.084 22.992 0.569 23.016 ;
     RECT  0.06 23.016 0.569 23.088 ;
     RECT  0.084 23.088 0.569 23.112 ;
     RECT  0.06 23.112 0.569 23.184 ;
     RECT  0.084 23.184 0.569 23.208 ;
     RECT  0.06 23.208 0.569 23.28 ;
     RECT  0.084 23.28 0.569 23.304 ;
     RECT  0.06 23.304 0.569 23.376 ;
     RECT  0.084 23.376 0.569 23.4 ;
     RECT  0.06 23.4 0.569 23.472 ;
     RECT  0.084 23.472 0.569 23.496 ;
     RECT  0.06 23.496 0.569 23.568 ;
     RECT  0.084 23.568 0.569 23.592 ;
     RECT  0.06 23.592 0.569 23.664 ;
     RECT  0.084 23.664 0.569 23.688 ;
     RECT  0.06 23.688 0.569 23.76 ;
     RECT  0.084 23.76 0.569 23.784 ;
     RECT  0.06 23.784 0.569 23.856 ;
     RECT  0.084 23.856 0.569 23.88 ;
     RECT  0.06 23.88 0.569 23.952 ;
     RECT  0.084 23.952 0.569 23.976 ;
     RECT  0.06 23.976 0.569 24.048 ;
     RECT  0.084 24.048 0.569 24.072 ;
     RECT  0.06 24.072 0.569 24.144 ;
     RECT  0.084 24.144 0.569 24.168 ;
     RECT  0.06 24.168 0.569 24.24 ;
     RECT  0.084 24.24 0.569 24.264 ;
     RECT  0.06 24.264 0.569 24.336 ;
     RECT  0.084 24.336 0.569 24.36 ;
     RECT  0.06 24.36 0.569 24.432 ;
     RECT  0.084 24.432 0.569 24.456 ;
     RECT  0.06 24.456 0.569 24.528 ;
     RECT  0.084 24.528 0.569 24.552 ;
     RECT  0.06 24.552 0.569 24.624 ;
     RECT  0.084 24.624 0.569 24.648 ;
     RECT  0.06 24.648 0.569 24.72 ;
     RECT  0.084 24.72 0.569 24.744 ;
     RECT  0.06 24.744 0.569 24.816 ;
     RECT  0.084 24.816 0.569 24.84 ;
     RECT  0.06 24.84 0.569 24.912 ;
     RECT  0.084 24.912 0.569 24.936 ;
     RECT  0.06 24.936 0.569 25.008 ;
     RECT  0.084 25.008 0.569 25.032 ;
     RECT  0.06 25.032 0.569 25.104 ;
     RECT  0.084 25.104 0.569 25.128 ;
     RECT  0.06 25.128 0.569 25.2 ;
     RECT  0.084 25.2 0.569 25.224 ;
     RECT  0.06 25.224 0.569 25.296 ;
     RECT  0.084 25.296 0.569 25.32 ;
     RECT  0.06 25.32 0.569 25.392 ;
     RECT  0.084 25.392 0.569 25.416 ;
     RECT  0.06 25.416 0.569 25.488 ;
     RECT  0.084 25.488 0.569 25.512 ;
     RECT  0.06 25.512 0.569 25.584 ;
     RECT  0.084 25.584 0.569 25.608 ;
     RECT  0.06 25.608 0.569 25.68 ;
     RECT  0.084 25.68 0.569 25.704 ;
     RECT  0.06 25.704 0.569 25.776 ;
     RECT  0.084 25.776 0.569 25.8 ;
     RECT  0.06 25.8 0.569 25.872 ;
     RECT  0.084 25.872 0.569 25.896 ;
     RECT  0.06 25.896 0.569 25.968 ;
     RECT  0.084 25.968 0.569 25.992 ;
     RECT  0.06 25.992 0.569 26.064 ;
     RECT  0.084 26.064 0.569 26.088 ;
     RECT  0.06 26.088 0.569 26.16 ;
     RECT  0.084 26.16 0.569 26.184 ;
     RECT  0.06 26.184 0.569 26.256 ;
     RECT  0.084 26.256 0.569 26.28 ;
     RECT  0.06 26.28 0.569 26.352 ;
     RECT  0.084 26.352 0.569 26.376 ;
     RECT  0.06 26.376 0.569 26.448 ;
     RECT  0.084 26.448 0.569 26.472 ;
     RECT  0.06 26.472 0.569 26.544 ;
     RECT  0.084 26.544 0.569 26.568 ;
     RECT  0.06 26.568 0.569 26.64 ;
     RECT  0.084 26.64 0.569 26.664 ;
     RECT  0.06 26.664 0.569 26.736 ;
     RECT  0.084 26.736 0.569 26.76 ;
     RECT  0.06 26.76 0.569 26.832 ;
     RECT  0.084 26.832 0.569 26.856 ;
     RECT  0.06 26.856 0.569 26.928 ;
     RECT  0.084 26.928 0.569 26.952 ;
     RECT  0.06 26.952 0.569 27.024 ;
     RECT  0.084 27.024 0.569 27.048 ;
     RECT  0.06 27.048 0.569 27.12 ;
     RECT  0.084 27.12 0.569 27.144 ;
     RECT  0.06 27.144 0.569 27.216 ;
     RECT  0.084 27.216 0.569 27.24 ;
     RECT  0.06 27.24 0.569 27.312 ;
     RECT  0.084 27.312 0.569 27.336 ;
     RECT  0.06 27.336 0.569 27.408 ;
     RECT  0.084 27.408 0.569 27.432 ;
     RECT  0.06 27.432 0.569 27.504 ;
     RECT  0.084 27.504 0.569 27.528 ;
     RECT  0.06 27.528 0.569 27.6 ;
     RECT  0.084 27.6 0.569 27.624 ;
     RECT  0.06 27.624 0.569 27.696 ;
     RECT  0.084 27.696 0.569 27.72 ;
     RECT  0.06 27.72 0.569 27.792 ;
     RECT  0.084 27.792 0.569 27.816 ;
     RECT  0.06 27.816 0.569 27.888 ;
     RECT  0.084 27.888 0.569 27.912 ;
     RECT  0.06 27.912 0.569 27.984 ;
     RECT  0.084 27.984 0.569 28.008 ;
     RECT  0.06 28.008 0.569 28.08 ;
     RECT  0.084 28.08 0.569 28.104 ;
     RECT  0.06 28.104 0.569 28.176 ;
     RECT  0.084 28.176 0.569 28.2 ;
     RECT  0.06 28.2 0.569 28.272 ;
     RECT  0.084 28.272 0.569 28.296 ;
     RECT  0.06 28.296 0.569 28.368 ;
     RECT  0.084 28.368 0.569 28.392 ;
     RECT  0.06 28.392 0.569 28.464 ;
     RECT  0.084 28.464 0.569 28.488 ;
     RECT  0.06 28.488 0.569 28.56 ;
     RECT  0.084 28.56 0.569 28.584 ;
     RECT  0.06 28.584 0.569 28.656 ;
     RECT  0.084 28.656 0.569 28.68 ;
     RECT  0.06 28.68 0.569 28.752 ;
     RECT  0.084 28.752 0.569 28.776 ;
     RECT  0.06 28.776 0.569 28.848 ;
     RECT  0.084 28.848 0.569 28.872 ;
     RECT  0.06 28.872 0.569 28.944 ;
     RECT  0.084 28.944 0.569 28.968 ;
     RECT  0.06 28.968 0.569 29.04 ;
     RECT  0.084 29.04 0.569 29.064 ;
     RECT  0.06 29.064 0.569 29.136 ;
     RECT  0.084 29.136 0.569 29.16 ;
     RECT  0.06 29.16 0.569 29.232 ;
     RECT  0.084 29.232 0.569 29.256 ;
     RECT  0.06 29.256 0.569 29.328 ;
     RECT  0.084 29.328 0.569 29.352 ;
     RECT  0.06 29.352 0.569 29.424 ;
     RECT  0.084 29.424 0.569 29.448 ;
     RECT  0.06 29.448 0.569 29.52 ;
     RECT  0.084 29.52 0.569 29.544 ;
     RECT  0.06 29.544 0.569 29.616 ;
     RECT  0.084 29.616 0.569 29.64 ;
     RECT  0.06 29.64 0.569 29.712 ;
     RECT  0.084 29.712 0.569 29.736 ;
     RECT  0.06 29.736 0.569 29.808 ;
     RECT  0.084 29.808 0.569 29.832 ;
     RECT  0.06 29.832 0.569 29.904 ;
     RECT  0.084 29.904 0.569 29.928 ;
     RECT  0.06 29.928 0.569 30.768 ;
     RECT  0.084 30.768 0.569 30.792 ;
     RECT  0.06 30.792 0.569 30.864 ;
     RECT  0.084 30.864 0.569 30.888 ;
     RECT  0.06 30.888 0.569 30.96 ;
     RECT  0.084 30.96 0.569 30.984 ;
     RECT  0.06 30.984 0.569 31.056 ;
     RECT  0.084 31.056 0.569 31.08 ;
     RECT  0.06 31.08 0.569 31.152 ;
     RECT  0.084 31.152 0.569 31.176 ;
     RECT  0.06 31.176 0.569 31.248 ;
     RECT  0.084 31.248 0.569 31.272 ;
     RECT  0.06 31.272 0.569 31.344 ;
     RECT  0.084 31.344 0.569 31.368 ;
     RECT  0.06 31.368 0.569 31.44 ;
     RECT  0.084 31.44 0.569 31.464 ;
     RECT  0.06 31.464 0.569 31.536 ;
     RECT  0.084 31.536 0.569 31.56 ;
     RECT  0.06 31.56 0.569 31.632 ;
     RECT  0.084 31.632 0.569 31.656 ;
     RECT  0.06 31.656 0.569 31.728 ;
     RECT  0.084 31.728 0.569 31.752 ;
     RECT  0.06 31.752 0.569 31.824 ;
     RECT  0.084 31.824 0.569 31.848 ;
     RECT  0.06 31.848 0.569 31.92 ;
     RECT  0.084 31.92 0.569 31.944 ;
     RECT  0.06 31.944 0.569 32.016 ;
     RECT  0.084 32.016 0.569 32.04 ;
     RECT  0.06 32.04 0.569 32.112 ;
     RECT  0.084 32.112 0.569 32.136 ;
     RECT  0.06 32.136 0.569 32.208 ;
     RECT  0.084 32.208 0.569 32.232 ;
     RECT  0.06 32.232 0.569 32.304 ;
     RECT  0.084 32.304 0.569 32.328 ;
     RECT  0.06 32.328 0.569 32.4 ;
     RECT  0.084 32.4 0.569 32.424 ;
     RECT  0.06 32.424 0.569 32.496 ;
     RECT  0.084 32.496 0.569 32.52 ;
     RECT  0.06 32.52 0.569 32.592 ;
     RECT  0.084 32.592 0.569 32.616 ;
     RECT  0.06 32.616 0.569 32.688 ;
     RECT  0.084 32.688 0.569 32.712 ;
     RECT  0.06 32.712 0.569 32.784 ;
     RECT  0.084 32.784 0.569 32.808 ;
     RECT  0.06 32.808 0.569 32.88 ;
     RECT  0.084 32.88 0.569 32.904 ;
     RECT  0.06 32.904 0.569 32.976 ;
     RECT  0.084 32.976 0.569 33 ;
     RECT  0.06 33 0.569 33.072 ;
     RECT  0.084 33.072 0.569 33.096 ;
     RECT  0.06 33.096 0.569 33.168 ;
     RECT  0.084 33.168 0.569 33.192 ;
     RECT  0.06 33.192 0.569 33.264 ;
     RECT  0.084 33.264 0.569 33.288 ;
     RECT  0.06 33.288 0.569 33.36 ;
     RECT  0.084 33.36 0.569 33.384 ;
     RECT  0.06 33.384 0.569 33.456 ;
     RECT  0.084 33.456 0.569 33.48 ;
     RECT  0.06 33.48 0.569 33.552 ;
     RECT  0.084 33.552 0.569 33.576 ;
     RECT  0.06 33.576 0.569 33.648 ;
     RECT  0.084 33.648 0.569 33.672 ;
     RECT  0.06 33.672 0.569 33.744 ;
     RECT  0.084 33.744 0.569 33.768 ;
     RECT  0.06 33.768 0.569 33.84 ;
     RECT  0.084 33.84 0.569 33.864 ;
     RECT  0.06 33.864 0.569 33.936 ;
     RECT  0.084 33.936 0.569 33.96 ;
     RECT  0.06 33.96 0.569 34.032 ;
     RECT  0.084 34.032 0.569 34.056 ;
     RECT  0.06 34.056 0.569 34.128 ;
     RECT  0.084 34.128 0.569 34.152 ;
     RECT  0.06 34.152 0.569 34.224 ;
     RECT  0.084 34.224 0.569 34.248 ;
     RECT  0.06 34.248 0.569 34.32 ;
     RECT  0.084 34.32 0.569 34.344 ;
     RECT  0.06 34.344 0.569 34.416 ;
     RECT  0.084 34.416 0.569 34.44 ;
     RECT  0.06 34.44 0.569 34.512 ;
     RECT  0.084 34.512 0.569 34.536 ;
     RECT  0.06 34.536 0.569 34.608 ;
     RECT  0.084 34.608 0.569 34.632 ;
     RECT  0.06 34.632 0.569 34.704 ;
     RECT  0.084 34.704 0.569 34.728 ;
     RECT  0.06 34.728 0.569 34.8 ;
     RECT  0.084 34.8 0.569 34.824 ;
     RECT  0.06 34.824 0.569 34.896 ;
     RECT  0.084 34.896 0.569 34.92 ;
     RECT  0.06 34.92 0.569 34.992 ;
     RECT  0.084 34.992 0.569 35.016 ;
     RECT  0.06 35.016 0.569 35.088 ;
     RECT  0.084 35.088 0.569 35.112 ;
     RECT  0.06 35.112 0.569 35.184 ;
     RECT  0.084 35.184 0.569 35.208 ;
     RECT  0.06 35.208 0.569 35.28 ;
     RECT  0.084 35.28 0.569 35.304 ;
     RECT  0.06 35.304 0.569 35.376 ;
     RECT  0.084 35.376 0.569 35.4 ;
     RECT  0.06 35.4 0.569 35.472 ;
     RECT  0.084 35.472 0.569 35.496 ;
     RECT  0.06 35.496 0.569 35.568 ;
     RECT  0.084 35.568 0.569 35.592 ;
     RECT  0.06 35.592 0.569 35.664 ;
     RECT  0.084 35.664 0.569 35.688 ;
     RECT  0.06 35.688 0.569 35.76 ;
     RECT  0.084 35.76 0.569 35.784 ;
     RECT  0.06 35.784 0.569 35.856 ;
     RECT  0.084 35.856 0.569 35.88 ;
     RECT  0.06 35.88 0.569 35.952 ;
     RECT  0.084 35.952 0.569 35.976 ;
     RECT  0.06 35.976 0.569 36.048 ;
     RECT  0.084 36.048 0.569 36.072 ;
     RECT  0.06 36.072 0.569 36.144 ;
     RECT  0.084 36.144 0.569 36.168 ;
     RECT  0.06 36.168 0.569 36.24 ;
     RECT  0.084 36.24 0.569 36.264 ;
     RECT  0.06 36.264 0.569 36.336 ;
     RECT  0.084 36.336 0.569 36.36 ;
     RECT  0.06 36.36 0.569 36.432 ;
     RECT  0.084 36.432 0.569 36.456 ;
     RECT  0.06 36.456 0.569 36.528 ;
     RECT  0.084 36.528 0.569 36.552 ;
     RECT  0.06 36.552 0.569 36.624 ;
     RECT  0.084 36.624 0.569 36.648 ;
     RECT  0.06 36.648 0.569 36.72 ;
     RECT  0.084 36.72 0.569 36.744 ;
     RECT  0.06 36.744 0.569 36.816 ;
     RECT  0.084 36.816 0.569 36.84 ;
     RECT  0.06 36.84 0.569 36.912 ;
     RECT  0.084 36.912 0.569 36.936 ;
     RECT  0.06 36.936 0.569 37.008 ;
     RECT  0.084 37.008 0.569 37.032 ;
     RECT  0.06 37.032 0.569 37.104 ;
     RECT  0.084 37.104 0.569 37.128 ;
     RECT  0.06 37.128 0.569 37.2 ;
     RECT  0.084 37.2 0.569 37.224 ;
     RECT  0.06 37.224 0.569 37.296 ;
     RECT  0.084 37.296 0.569 37.32 ;
     RECT  0.06 37.32 0.569 37.392 ;
     RECT  0.084 37.392 0.569 37.416 ;
     RECT  0.06 37.416 0.569 37.488 ;
     RECT  0.084 37.488 0.569 37.512 ;
     RECT  0.06 37.512 0.569 37.584 ;
     RECT  0.084 37.584 0.569 37.608 ;
     RECT  0.06 37.608 0.569 37.68 ;
     RECT  0.084 37.68 0.569 37.704 ;
     RECT  0.06 37.704 0.569 37.776 ;
     RECT  0.084 37.776 0.569 37.8 ;
     RECT  0.06 37.8 0.569 37.872 ;
     RECT  0.084 37.872 0.569 37.896 ;
     RECT  0.06 37.896 0.569 37.968 ;
     RECT  0.084 37.968 0.569 37.992 ;
     RECT  0.06 37.992 0.569 38.064 ;
     RECT  0.084 38.064 0.569 38.088 ;
     RECT  0.06 38.088 0.569 38.16 ;
     RECT  0.084 38.16 0.569 38.184 ;
     RECT  0.06 38.184 0.569 38.256 ;
     RECT  0.084 38.256 0.569 38.28 ;
     RECT  0.06 38.28 0.569 38.352 ;
     RECT  0.084 38.352 0.569 38.376 ;
     RECT  0.06 38.376 0.569 38.448 ;
     RECT  0.084 38.448 0.569 38.472 ;
     RECT  0.06 38.472 0.569 38.544 ;
     RECT  0.084 38.544 0.569 38.568 ;
     RECT  0.06 38.568 0.569 38.64 ;
     RECT  0.084 38.64 0.569 38.664 ;
     RECT  0.06 38.664 0.569 38.736 ;
     RECT  0.084 38.736 0.569 38.76 ;
     RECT  0.06 38.76 0.569 38.832 ;
     RECT  0.084 38.832 0.569 38.856 ;
     RECT  0.06 38.856 0.569 38.928 ;
     RECT  0.084 38.928 0.569 38.952 ;
     RECT  0.06 38.952 0.569 39.024 ;
     RECT  0.084 39.024 0.569 39.048 ;
     RECT  0.06 39.048 0.569 39.12 ;
     RECT  0.084 39.12 0.569 39.144 ;
     RECT  0.06 39.144 0.569 39.216 ;
     RECT  0.084 39.216 0.569 39.24 ;
     RECT  0.06 39.24 0.569 39.312 ;
     RECT  0.084 39.312 0.569 39.336 ;
     RECT  0.06 39.336 0.569 39.408 ;
     RECT  0.084 39.408 0.569 39.432 ;
     RECT  0.06 39.432 0.569 39.504 ;
     RECT  0.084 39.504 0.569 39.528 ;
     RECT  0.06 39.528 0.569 39.6 ;
     RECT  0.084 39.6 0.569 39.624 ;
     RECT  0.06 39.624 0.569 39.696 ;
     RECT  0.084 39.696 0.569 39.72 ;
     RECT  0.06 39.72 0.569 39.792 ;
     RECT  0.084 39.792 0.569 39.816 ;
     RECT  0.06 39.816 0.569 39.888 ;
     RECT  0.084 39.888 0.569 39.912 ;
     RECT  0.06 39.912 0.569 39.984 ;
     RECT  0.084 39.984 0.569 40.008 ;
     RECT  0.06 40.008 0.569 40.08 ;
     RECT  0.084 40.08 0.569 40.104 ;
     RECT  0.06 40.104 0.569 40.176 ;
     RECT  0.084 40.176 0.569 40.2 ;
     RECT  0.06 40.2 0.569 40.272 ;
     RECT  0.084 40.272 0.569 40.296 ;
     RECT  0.06 40.296 0.569 40.368 ;
     RECT  0.084 40.368 0.569 40.392 ;
     RECT  0.06 40.392 0.569 40.464 ;
     RECT  0.084 40.464 0.569 40.488 ;
     RECT  0.06 40.488 0.569 40.56 ;
     RECT  0.084 40.56 0.569 40.584 ;
     RECT  0.06 40.584 0.569 40.656 ;
     RECT  0.084 40.656 0.569 40.68 ;
     RECT  0.06 40.68 0.569 40.752 ;
     RECT  0.084 40.752 0.569 40.776 ;
     RECT  0.06 40.776 0.569 40.848 ;
     RECT  0.084 40.848 0.569 40.872 ;
     RECT  0.06 40.872 0.569 40.944 ;
     RECT  0.084 40.944 0.569 40.968 ;
     RECT  0.06 40.968 0.569 41.04 ;
     RECT  0.084 41.04 0.569 41.064 ;
     RECT  0.06 41.064 0.569 41.136 ;
     RECT  0.084 41.136 0.569 41.16 ;
     RECT  0.06 41.16 0.569 41.232 ;
     RECT  0.084 41.232 0.569 41.256 ;
     RECT  0.06 41.256 0.569 41.328 ;
     RECT  0.084 41.328 0.569 41.352 ;
     RECT  0.06 41.352 0.569 41.424 ;
     RECT  0.084 41.424 0.569 41.448 ;
     RECT  0.06 41.448 0.569 41.52 ;
     RECT  0.084 41.52 0.569 41.544 ;
     RECT  0.06 41.544 0.569 41.616 ;
     RECT  0.084 41.616 0.569 41.64 ;
     RECT  0.06 41.64 0.569 41.712 ;
     RECT  0.084 41.712 0.569 41.736 ;
     RECT  0.06 41.736 0.569 41.808 ;
     RECT  0.084 41.808 0.569 41.832 ;
     RECT  0.06 41.832 0.569 41.904 ;
     RECT  0.084 41.904 0.569 41.928 ;
     RECT  0.06 41.928 0.569 42 ;
     RECT  0.084 42 0.569 42.024 ;
     RECT  0.06 42.024 0.569 42.096 ;
     RECT  0.084 42.096 0.569 42.12 ;
     RECT  0.06 42.12 0.569 42.192 ;
     RECT  0.084 42.192 0.569 42.216 ;
     RECT  0.06 42.216 0.569 42.288 ;
     RECT  0.084 42.288 0.569 42.312 ;
     RECT  0.06 42.312 0.569 42.384 ;
     RECT  0.084 42.384 0.569 42.408 ;
     RECT  0.06 42.408 0.569 42.48 ;
     RECT  0.084 42.48 0.569 42.504 ;
     RECT  0.06 42.504 0.569 42.576 ;
     RECT  0.084 42.576 0.569 42.6 ;
     RECT  0.06 42.6 0.569 42.672 ;
     RECT  0.084 42.672 0.569 42.696 ;
     RECT  0.06 42.696 0.569 42.768 ;
     RECT  0.084 42.768 0.569 42.792 ;
     RECT  0.06 42.792 0.569 42.864 ;
     RECT  0.084 42.864 0.569 42.888 ;
     RECT  0.06 42.888 0.569 42.96 ;
     RECT  0.084 42.96 0.569 42.984 ;
     RECT  0.06 42.984 0.569 43.056 ;
     RECT  0.084 43.056 0.569 43.08 ;
     RECT  0.06 43.08 0.569 43.152 ;
     RECT  0.084 43.152 0.569 43.176 ;
     RECT  0.06 43.176 0.569 43.248 ;
     RECT  0.084 43.248 0.569 43.272 ;
     RECT  0.06 43.272 0.569 43.344 ;
     RECT  0.084 43.344 0.569 43.368 ;
     RECT  0.06 43.368 0.569 43.44 ;
     RECT  0.084 43.44 0.569 43.464 ;
     RECT  0.06 43.464 0.569 43.536 ;
     RECT  0.084 43.536 0.569 43.56 ;
     RECT  0.06 43.56 0.569 43.632 ;
     RECT  0.084 43.632 0.569 43.656 ;
     RECT  0.06 43.656 0.569 43.728 ;
     RECT  0.084 43.728 0.569 43.752 ;
     RECT  0.06 43.752 0.569 43.824 ;
     RECT  0.084 43.824 0.569 43.848 ;
     RECT  0.06 43.848 0.569 43.92 ;
     RECT  0.084 43.92 0.569 43.944 ;
     RECT  0.06 43.944 0.569 44.016 ;
     RECT  0.084 44.016 0.569 44.04 ;
     RECT  0.06 44.04 0.569 44.112 ;
     RECT  0.084 44.112 0.569 44.136 ;
     RECT  0.06 44.136 0.569 44.208 ;
     RECT  0.084 44.208 0.569 44.232 ;
     RECT  0.06 44.232 0.569 44.304 ;
     RECT  0.084 44.304 0.569 44.328 ;
     RECT  0.06 44.328 0.569 44.4 ;
     RECT  0.084 44.4 0.569 44.424 ;
     RECT  0.06 44.424 0.569 44.496 ;
     RECT  0.084 44.496 0.569 44.52 ;
     RECT  0.06 44.52 0.569 44.592 ;
     RECT  0.084 44.592 0.569 44.616 ;
     RECT  0.06 44.616 0.569 44.688 ;
     RECT  0.084 44.688 0.569 44.712 ;
     RECT  0.06 44.712 0.569 44.784 ;
     RECT  0.084 44.784 0.569 44.808 ;
     RECT  0.06 44.808 0.569 44.88 ;
     RECT  0.084 44.88 0.569 44.904 ;
     RECT  0.06 44.904 0.569 44.976 ;
     RECT  0.084 44.976 0.569 45 ;
     RECT  0.06 45 0.569 45.072 ;
     RECT  0.084 45.072 0.569 45.096 ;
     RECT  0.06 45.096 0.569 45.168 ;
     RECT  0.084 45.168 0.569 45.192 ;
     RECT  0.06 45.192 0.569 45.264 ;
     RECT  0.084 45.264 0.569 45.288 ;
     RECT  0.06 45.288 0.569 45.36 ;
     RECT  0.084 45.36 0.569 45.384 ;
     RECT  0.06 45.384 0.569 45.456 ;
     RECT  0.084 45.456 0.569 45.48 ;
     RECT  0.06 45.48 0.569 45.552 ;
     RECT  0.084 45.552 0.569 45.576 ;
     RECT  0.06 45.576 0.569 45.648 ;
     RECT  0.084 45.648 0.569 45.672 ;
     RECT  0.06 45.672 0.569 45.744 ;
     RECT  0.084 45.744 0.569 45.768 ;
     RECT  0.06 45.768 0.569 45.84 ;
     RECT  0.084 45.84 0.569 45.864 ;
     RECT  0.06 45.864 0.569 45.936 ;
     RECT  0.084 45.936 0.569 45.96 ;
     RECT  0.06 45.96 0.569 46.032 ;
     RECT  0.084 46.032 0.569 46.056 ;
     RECT  0.06 46.056 0.569 46.128 ;
     RECT  0.084 46.128 0.569 46.152 ;
     RECT  0.06 46.152 0.569 46.224 ;
     RECT  0.084 46.224 0.569 46.248 ;
     RECT  0.06 46.248 0.569 46.32 ;
     RECT  0.084 46.32 0.569 46.344 ;
     RECT  0.06 46.344 0.569 46.416 ;
     RECT  0.084 46.416 0.569 46.44 ;
     RECT  0.06 46.44 0.569 46.512 ;
     RECT  0.084 46.512 0.569 46.536 ;
     RECT  0.06 46.536 0.569 46.608 ;
     RECT  0.084 46.608 0.569 46.632 ;
     RECT  0.06 46.632 0.569 46.704 ;
     RECT  0.084 46.704 0.569 46.728 ;
     RECT  0.06 46.728 0.569 46.8 ;
     RECT  0.084 46.8 0.569 46.824 ;
     RECT  0.06 46.824 0.569 46.896 ;
     RECT  0.084 46.896 0.569 46.92 ;
     RECT  0.06 46.92 0.569 46.992 ;
     RECT  0.084 46.992 0.569 47.016 ;
     RECT  0.06 47.016 0.569 47.088 ;
     RECT  0.084 47.088 0.569 47.112 ;
     RECT  0.06 47.112 0.569 47.184 ;
     RECT  0.084 47.184 0.569 47.208 ;
     RECT  0.06 47.208 0.569 47.28 ;
     RECT  0.084 47.28 0.569 47.304 ;
     RECT  0.06 47.304 0.569 47.376 ;
     RECT  0.084 47.376 0.569 47.4 ;
     RECT  0.06 47.4 0.569 47.472 ;
     RECT  0.084 47.472 0.569 47.496 ;
     RECT  0.06 47.496 0.569 47.568 ;
     RECT  0.084 47.568 0.569 47.592 ;
     RECT  0.06 47.592 0.569 47.664 ;
     RECT  0.084 47.664 0.569 47.688 ;
     RECT  0.06 47.688 0.569 47.76 ;
     RECT  0.084 47.76 0.569 47.784 ;
     RECT  0.06 47.784 0.569 47.856 ;
     RECT  0.084 47.856 0.569 47.88 ;
     RECT  0.06 47.88 0.569 47.952 ;
     RECT  0.084 47.952 0.569 47.976 ;
     RECT  0.06 47.976 0.569 48.048 ;
     RECT  0.084 48.048 0.569 48.072 ;
     RECT  0.06 48.072 0.569 48.144 ;
     RECT  0.084 48.144 0.569 48.168 ;
     RECT  0.06 48.168 0.569 48.24 ;
     RECT  0.084 48.24 0.569 48.264 ;
     RECT  0.06 48.264 0.569 48.336 ;
     RECT  0.084 48.336 0.569 48.36 ;
     RECT  0.06 48.36 0.569 48.432 ;
     RECT  0.084 48.432 0.569 48.456 ;
     RECT  0.06 48.456 0.569 48.528 ;
     RECT  0.084 48.528 0.569 48.552 ;
     RECT  0.06 48.552 0.569 48.624 ;
     RECT  0.084 48.624 0.569 48.648 ;
     RECT  0.06 48.648 0.569 48.72 ;
     RECT  0.084 48.72 0.569 48.744 ;
     RECT  0.06 48.744 0.569 48.816 ;
     RECT  0.084 48.816 0.569 48.84 ;
     RECT  0.06 48.84 0.569 48.912 ;
     RECT  0.084 48.912 0.569 48.936 ;
     RECT  0.06 48.936 0.569 49.008 ;
     RECT  0.084 49.008 0.569 49.032 ;
     RECT  0.06 49.032 0.569 49.104 ;
     RECT  0.084 49.104 0.569 49.128 ;
     RECT  0.569 17.808 2.408 49.128 ;
     RECT  2.408 2.148 2.512 66.972 ;
     RECT  2.512 2.418 2.704 66.702 ;
     RECT  2.704 17.76 4.493 49.128 ;
     RECT  4.309 50.16 4.889 50.184 ;
     RECT  4.493 17.904 5.785 49.128 ;
     RECT  5.785 17.664 5.894 49.128 ;
     RECT  5.894 17.664 7.669 49.08 ;
     RECT  7.669 17.664 7.808 49.8 ;
     RECT  7.808 2.148 7.912 66.972 ;
     RECT  7.912 2.418 8.104 66.702 ;
     RECT  8.104 18.672 8.165 20.712 ;
     RECT  8.104 39.84 8.201 44.952 ;
     RECT  8.165 18.672 8.243 19.992 ;
     RECT  8.104 29.04 8.281 34.152 ;
     RECT  8.104 17.664 8.309 17.688 ;
     RECT  8.243 18.672 8.309 18.744 ;
     RECT  8.104 46.32 8.309 47.112 ;
     RECT  8.104 21.744 8.381 22.248 ;
     RECT  8.281 29.04 8.381 29.064 ;
     RECT  8.201 40.656 8.417 44.952 ;
     RECT  8.417 40.944 8.453 44.952 ;
     RECT  8.104 36.528 8.489 38.664 ;
     RECT  8.489 36.528 8.597 38.424 ;
     RECT  8.104 48.912 8.597 49.8 ;
     RECT  8.597 38.208 8.705 38.424 ;
     RECT  8.381 21.744 8.813 21.768 ;
     RECT  8.281 30.72 8.813 34.152 ;
     RECT  8.104 35.424 8.993 35.544 ;
     RECT  8.309 46.512 8.993 47.112 ;
     RECT  8.104 23.664 9.065 24.744 ;
     RECT  8.993 35.52 9.065 35.544 ;
     RECT  8.453 40.992 9.065 44.952 ;
     RECT  9.065 41.184 9.101 44.952 ;
     RECT  9.065 23.664 9.137 24.456 ;
     RECT  8.705 38.208 9.137 38.28 ;
     RECT  9.101 41.472 9.137 44.952 ;
     RECT  8.597 48.912 9.173 48.936 ;
     RECT  8.104 27.648 9.281 27.672 ;
     RECT  8.813 30.72 9.281 32.472 ;
     RECT  9.137 41.472 9.317 42.264 ;
     RECT  9.317 41.52 9.389 42.264 ;
     RECT  8.309 18.72 9.425 18.744 ;
     RECT  8.993 46.512 9.425 47.064 ;
     RECT  9.137 38.208 9.533 38.232 ;
     RECT  9.389 42.24 9.569 42.264 ;
     RECT  8.813 33.6 10.645 34.152 ;
     RECT  10.645 33.504 10.829 34.152 ;
     RECT  9.137 23.664 13.208 23.688 ;
     RECT  9.281 30.864 13.208 32.472 ;
     RECT  10.829 33.6 13.208 34.152 ;
     RECT  8.597 36.528 13.208 36.648 ;
     RECT  9.137 43.68 13.208 44.952 ;
     RECT  9.425 46.512 13.208 46.536 ;
     RECT  13.208 2.148 13.312 66.972 ;
     RECT  13.312 2.418 13.504 66.702 ;
     RECT  13.504 46.512 17.377 46.536 ;
     RECT  17.449 67.872 17.557 67.896 ;
     RECT  17.665 66.72 17.701 66.744 ;
     RECT  17.557 67.824 17.701 67.896 ;
     RECT  17.701 66.72 17.989 67.896 ;
     RECT  13.504 43.68 18.025 44.952 ;
     RECT  17.377 46.08 18.025 46.536 ;
     RECT  17.989 66.72 18.169 68.424 ;
     RECT  18.169 66.72 18.227 69 ;
     RECT  18.227 66.72 18.241 67.272 ;
     RECT  18.227 68.4 18.323 69 ;
     RECT  18.323 68.448 18.419 69 ;
     RECT  18.38 63.216 18.421 63.24 ;
     RECT  18.419 68.928 18.515 69 ;
     RECT  13.504 23.664 18.608 23.688 ;
     RECT  13.504 30.864 18.608 32.472 ;
     RECT  13.504 33.6 18.608 34.152 ;
     RECT  13.504 36.528 18.608 36.648 ;
     RECT  18.025 43.68 18.608 46.536 ;
     RECT  18.421 63.216 18.608 63.816 ;
     RECT  18.241 66.336 18.608 67.272 ;
     RECT  18.608 2.148 18.712 67.272 ;
     RECT  18.712 2.418 18.904 67.272 ;
     RECT  18.904 33.6 19.037 36.648 ;
     RECT  18.904 66.528 19.043 67.272 ;
     RECT  18.515 68.928 19.043 68.952 ;
     RECT  18.904 49.776 19.235 49.992 ;
     RECT  18.904 64.704 19.433 65.544 ;
     RECT  18.904 43.68 19.973 46.872 ;
     RECT  19.861 68.4 20.147 68.424 ;
     RECT  19.909 63.216 20.389 63.24 ;
     RECT  19.043 66.72 20.761 67.272 ;
     RECT  20.389 63.12 21.013 63.24 ;
     RECT  21.013 63.12 21.125 64.056 ;
     RECT  20.761 66.72 21.299 67.848 ;
     RECT  21.299 66.72 21.395 67.272 ;
     RECT  21.637 68.544 21.733 68.568 ;
     RECT  19.433 65.52 22.057 65.544 ;
     RECT  21.733 68.544 22.085 68.856 ;
     RECT  19.973 43.68 22.129 46.824 ;
     RECT  22.085 68.544 22.163 69 ;
     RECT  21.125 63.12 22.165 63.816 ;
     RECT  22.165 63.024 22.241 63.816 ;
     RECT  21.395 67.152 22.405 67.272 ;
     RECT  22.405 67.104 22.529 67.272 ;
     RECT  22.529 67.152 22.601 67.272 ;
     RECT  19.037 33.6 22.817 34.968 ;
     RECT  22.241 63.024 22.981 63.768 ;
     RECT  22.817 34.944 23.137 34.968 ;
     RECT  19.037 36.528 23.137 36.648 ;
     RECT  22.163 68.688 23.257 69 ;
     RECT  22.057 65.52 23.317 66.12 ;
     RECT  23.317 64.992 23.461 66.12 ;
     RECT  22.981 62.832 23.669 63.768 ;
     RECT  23.257 68.688 23.713 68.952 ;
     RECT  23.669 62.832 23.752 63.816 ;
     RECT  18.904 23.664 24.008 23.688 ;
     RECT  18.904 30.864 24.008 32.472 ;
     RECT  22.817 33.6 24.008 33.912 ;
     RECT  23.137 34.944 24.008 36.648 ;
     RECT  22.129 43.68 24.008 47.064 ;
     RECT  19.235 49.776 24.008 49.8 ;
     RECT  23.752 62.832 24.008 63.864 ;
     RECT  23.461 64.944 24.008 66.12 ;
     RECT  22.601 67.248 24.008 67.272 ;
     RECT  24.008 2.148 24.112 67.272 ;
     RECT  24.112 2.418 24.304 67.272 ;
     RECT  23.713 68.4 24.371 68.952 ;
     RECT  24.371 68.688 24.467 68.952 ;
     RECT  24.467 68.784 24.515 68.952 ;
     RECT  24.304 36.528 24.617 36.936 ;
     RECT  24.617 36.576 24.833 36.936 ;
     RECT  24.304 65.52 24.899 65.544 ;
     RECT  24.515 68.88 24.901 68.952 ;
     RECT  24.304 62.352 24.905 64.392 ;
     RECT  24.905 62.352 24.947 64.296 ;
     RECT  24.833 36.624 25.265 36.936 ;
     RECT  24.901 68.88 25.475 69 ;
     RECT  24.947 62.352 25.517 63.768 ;
     RECT  25.475 68.928 25.523 69 ;
     RECT  25.265 36.864 25.589 36.936 ;
     RECT  25.589 36.864 25.661 36.888 ;
     RECT  24.304 23.328 25.729 23.688 ;
     RECT  25.729 23.04 25.769 23.688 ;
     RECT  25.517 62.352 25.841 63.288 ;
     RECT  24.304 66.72 26.012 67.272 ;
     RECT  26.012 66.528 26.099 67.272 ;
     RECT  25.657 39.6 26.377 39.624 ;
     RECT  26.377 39.6 26.485 40.584 ;
     RECT  26.099 66.72 26.701 67.272 ;
     RECT  24.304 30.864 26.773 32.472 ;
     RECT  24.304 33.6 26.773 33.912 ;
     RECT  26.485 39.6 26.779 40.728 ;
     RECT  26.701 66.72 26.963 67.32 ;
     RECT  26.779 40.608 27.025 40.728 ;
     RECT  27.025 40.608 27.065 41.4 ;
     RECT  25.523 68.928 27.205 68.952 ;
     RECT  27.205 68.928 27.241 69 ;
     RECT  26.963 66.768 27.251 67.32 ;
     RECT  25.841 62.352 27.281 63.24 ;
     RECT  27.241 68.352 27.443 69 ;
     RECT  27.443 68.352 27.539 68.952 ;
     RECT  27.065 41.376 27.709 41.4 ;
     RECT  27.637 42.672 27.709 42.696 ;
     RECT  28.021 65.568 28.109 65.592 ;
     RECT  27.281 62.592 28.117 63.24 ;
     RECT  26.773 30.864 28.181 33.912 ;
     RECT  28.117 62.592 28.213 63.576 ;
     RECT  27.539 68.544 28.259 68.952 ;
     RECT  28.213 62.592 28.289 63.816 ;
     RECT  28.033 66.72 28.307 66.744 ;
     RECT  28.289 62.832 28.357 63.816 ;
     RECT  27.709 41.376 28.573 42.696 ;
     RECT  24.304 43.68 28.573 47.064 ;
     RECT  28.357 62.832 29.149 64.44 ;
     RECT  28.259 68.64 29.185 68.952 ;
     RECT  29.185 68.64 29.267 69 ;
     RECT  29.267 68.688 29.269 69 ;
     RECT  29.257 66.768 29.285 67.128 ;
     RECT  25.769 23.04 29.408 23.352 ;
     RECT  28.181 30.864 29.408 33.624 ;
     RECT  24.304 34.944 29.408 34.968 ;
     RECT  26.779 39.6 29.408 39.624 ;
     RECT  28.573 41.376 29.408 47.064 ;
     RECT  24.304 49.776 29.408 49.8 ;
     RECT  29.149 62.832 29.408 65.208 ;
     RECT  29.285 66.768 29.408 67.272 ;
     RECT  29.408 2.148 29.512 67.272 ;
     RECT  29.269 68.688 29.555 68.808 ;
     RECT  29.555 68.688 29.651 68.712 ;
     RECT  29.512 2.418 29.704 67.272 ;
     RECT  29.704 63.072 29.765 65.16 ;
     RECT  29.704 67.152 30.589 67.272 ;
     RECT  30.589 67.152 30.733 67.848 ;
     RECT  30.733 67.152 30.757 67.896 ;
     RECT  29.765 63.216 30.773 65.16 ;
     RECT  30.757 67.152 30.841 68.712 ;
     RECT  30.841 66.72 30.853 68.712 ;
     RECT  29.704 30.864 30.881 33.672 ;
     RECT  30.853 66.72 30.898 68.904 ;
     RECT  30.773 64.32 30.917 65.16 ;
     RECT  30.898 66.72 30.953 69 ;
     RECT  30.953 66.72 30.995 67.896 ;
     RECT  30.953 68.88 30.995 69 ;
     RECT  30.995 66.72 31.093 67.848 ;
     RECT  30.773 63.216 31.235 63.24 ;
     RECT  30.995 68.928 31.235 69 ;
     RECT  31.093 66.096 31.457 67.848 ;
     RECT  29.704 34.944 31.637 35.256 ;
     RECT  31.235 68.976 32.051 69 ;
     RECT  30.881 30.864 32.173 33.624 ;
     RECT  31.457 66.336 32.497 67.848 ;
     RECT  32.173 30.096 32.573 33.624 ;
     RECT  30.917 64.32 32.573 64.392 ;
     RECT  32.497 66.144 32.761 67.848 ;
     RECT  31.993 63.168 32.821 63.192 ;
     RECT  32.761 66.72 32.929 67.848 ;
     RECT  32.929 66.72 33.299 67.896 ;
     RECT  32.821 63.168 33.445 63.288 ;
     RECT  33.445 62.832 33.577 63.288 ;
     RECT  32.573 64.32 33.577 64.344 ;
     RECT  33.577 62.832 33.761 64.344 ;
     RECT  33.761 63.264 34.117 64.344 ;
     RECT  33.829 68.4 34.259 68.424 ;
     RECT  34.289 68.976 34.373 69 ;
     RECT  33.299 66.72 34.441 67.272 ;
     RECT  33.397 11.232 34.765 11.256 ;
     RECT  34.117 63.264 34.765 64.776 ;
     RECT  34.765 11.136 34.808 11.256 ;
     RECT  29.704 23.04 34.808 23.352 ;
     RECT  32.573 30.432 34.808 33.624 ;
     RECT  31.637 34.944 34.808 34.968 ;
     RECT  29.704 39.6 34.808 39.624 ;
     RECT  29.704 42.72 34.808 47.064 ;
     RECT  29.704 49.776 34.808 49.8 ;
     RECT  34.765 62.832 34.808 64.776 ;
     RECT  34.441 66.72 34.808 67.848 ;
     RECT  34.808 2.148 34.912 67.848 ;
     RECT  34.912 2.418 35.027 67.848 ;
     RECT  35.027 2.418 35.104 67.272 ;
     RECT  35.104 34.896 35.267 34.92 ;
     RECT  35.104 49.776 35.267 49.8 ;
     RECT  35.104 62.832 35.315 64.44 ;
     RECT  35.104 23.04 35.651 23.64 ;
     RECT  35.315 62.832 36.065 64.056 ;
     RECT  35.104 10.368 36.173 11.16 ;
     RECT  35.104 30.432 36.389 33.624 ;
     RECT  36.389 30.432 36.425 30.84 ;
     RECT  36.38 10.272 36.467 10.296 ;
     RECT  36.389 31.968 36.497 33.624 ;
     RECT  35.104 66.72 37.043 67.272 ;
     RECT  36.065 63.648 37.093 64.056 ;
     RECT  36.497 32.016 37.177 33.624 ;
     RECT  37.093 63.216 37.357 64.056 ;
     RECT  36.421 7.392 37.757 7.416 ;
     RECT  37.177 32.016 37.861 33.72 ;
     RECT  37.357 62.304 37.916 64.056 ;
     RECT  37.861 68.928 37.925 68.952 ;
     RECT  37.925 68.928 37.964 69 ;
     RECT  37.964 68.88 38.009 69 ;
     RECT  38.009 68.88 38.051 68.952 ;
     RECT  37.043 67.152 38.077 67.272 ;
     RECT  38.051 68.928 38.147 68.952 ;
     RECT  37.916 62.304 38.233 64.824 ;
     RECT  35.104 42.72 38.293 47.064 ;
     RECT  37.861 32.016 38.333 34.008 ;
     RECT  35.104 4.128 38.365 4.152 ;
     RECT  38.233 63.744 38.437 64.824 ;
     RECT  38.233 62.304 38.441 62.664 ;
     RECT  38.333 32.016 38.477 33.624 ;
     RECT  38.293 42.672 38.477 47.064 ;
     RECT  38.077 67.152 38.483 67.848 ;
     RECT  38.483 67.152 38.533 67.368 ;
     RECT  38.533 67.008 38.581 67.368 ;
     RECT  38.365 4.128 38.617 5.064 ;
     RECT  38.441 62.64 38.665 62.664 ;
     RECT  38.617 4.128 38.761 5.784 ;
     RECT  35.104 39.6 38.761 39.624 ;
     RECT  38.581 66.912 38.771 67.368 ;
     RECT  38.437 63.744 38.837 65.016 ;
     RECT  38.771 66.912 38.869 67.272 ;
     RECT  38.761 2.88 38.905 5.784 ;
     RECT  38.869 66.768 38.941 67.272 ;
     RECT  38.761 39.216 38.945 39.624 ;
     RECT  38.905 2.208 39.049 5.784 ;
     RECT  38.837 63.744 39.253 64.056 ;
     RECT  38.941 66.72 39.253 67.272 ;
     RECT  39.049 2.16 39.409 5.784 ;
     RECT  39.229 0.096 39.517 0.12 ;
     RECT  39.253 63.168 39.653 64.056 ;
     RECT  39.409 2.16 40.057 6.12 ;
     RECT  39.769 68.976 40.129 69 ;
     RECT  39.517 0.096 40.165 0.6 ;
     RECT  40.057 2.016 40.165 6.12 ;
     RECT  39.253 66.672 40.165 67.272 ;
     RECT  40.165 0.096 40.208 6.12 ;
     RECT  35.651 23.616 40.208 23.64 ;
     RECT  36.425 30.432 40.208 30.6 ;
     RECT  38.477 32.016 40.208 33.288 ;
     RECT  38.945 39.6 40.208 39.624 ;
     RECT  38.477 42.72 40.208 47.064 ;
     RECT  35.104 52.512 40.208 52.536 ;
     RECT  39.653 62.448 40.208 64.056 ;
     RECT  40.165 66.672 40.208 67.32 ;
     RECT  40.208 0.096 40.211 67.32 ;
     RECT  40.211 0.144 40.504 67.32 ;
     RECT  40.504 0.144 40.643 7.992 ;
     RECT  40.643 0.576 40.691 7.992 ;
     RECT  40.129 68.4 40.691 69 ;
     RECT  40.504 62.544 40.883 63.864 ;
     RECT  40.504 66.72 40.921 67.32 ;
     RECT  40.691 0.576 41.097 0.648 ;
     RECT  40.691 68.976 41.171 69 ;
     RECT  40.504 65.376 41.285 65.4 ;
     RECT  41.097 0.624 41.459 0.648 ;
     RECT  40.691 1.728 41.459 7.992 ;
     RECT  41.459 1.728 41.609 7.704 ;
     RECT  40.883 62.544 41.645 63.288 ;
     RECT  40.921 66.72 41.651 67.896 ;
     RECT  41.645 62.544 42.037 63.24 ;
     RECT  41.821 38.544 42.109 38.568 ;
     RECT  42.109 37.968 42.361 38.568 ;
     RECT  40.504 39.6 42.361 39.624 ;
     RECT  42.325 1.104 42.419 1.128 ;
     RECT  42.565 65.712 42.653 65.736 ;
     RECT  41.651 66.72 42.661 67.272 ;
     RECT  42.661 66.432 42.721 67.272 ;
     RECT  42.361 37.968 42.725 39.624 ;
     RECT  42.721 66.432 42.748 67.848 ;
     RECT  41.609 2.208 42.793 7.704 ;
     RECT  42.716 0.48 42.813 0.552 ;
     RECT  42.793 2.208 42.833 7.992 ;
     RECT  42.833 2.208 42.865 3.384 ;
     RECT  42.813 0.528 42.899 0.552 ;
     RECT  42.748 66.72 42.901 67.848 ;
     RECT  42.373 68.976 42.901 69 ;
     RECT  42.865 2.16 42.929 3.384 ;
     RECT  42.623 64.368 42.977 64.392 ;
     RECT  42.725 38.544 43.013 39.624 ;
     RECT  40.504 52.512 43.193 52.536 ;
     RECT  42.901 66.72 43.283 69 ;
     RECT  42.037 62.208 43.297 63.24 ;
     RECT  43.013 38.784 43.373 39.624 ;
     RECT  43.283 68.4 43.379 69 ;
     RECT  43.297 62.208 43.409 63.768 ;
     RECT  43.379 68.736 43.763 69 ;
     RECT  42.833 4.368 43.765 7.992 ;
     RECT  43.373 39.216 43.913 39.624 ;
     RECT  43.765 4.368 43.955 8.568 ;
     RECT  43.283 66.72 44.269 67.272 ;
     RECT  43.409 62.832 44.437 63.768 ;
     RECT  44.437 62.64 44.581 63.768 ;
     RECT  42.929 1.728 44.705 3.384 ;
     RECT  44.705 2.016 44.881 3.384 ;
     RECT  43.955 4.368 44.881 8.04 ;
     RECT  44.581 62.64 44.925 63.816 ;
     RECT  43.763 68.88 44.929 69 ;
     RECT  44.929 68.88 44.963 68.952 ;
     RECT  43.964 0.528 45.041 0.552 ;
     RECT  44.269 66.72 45.209 67.32 ;
     RECT  45.041 0.528 45.317 0.6 ;
     RECT  40.504 42.72 45.385 47.064 ;
     RECT  44.925 62.64 45.493 64.344 ;
     RECT  44.881 2.016 45.608 8.04 ;
     RECT  40.504 23.616 45.608 23.64 ;
     RECT  40.504 30.432 45.608 30.6 ;
     RECT  40.504 32.016 45.608 33.288 ;
     RECT  43.913 39.6 45.608 39.624 ;
     RECT  45.385 42.72 45.608 47.16 ;
     RECT  44.677 49.824 45.608 49.848 ;
     RECT  44.629 52.896 45.608 52.92 ;
     RECT  45.493 62.64 45.608 64.968 ;
     RECT  45.209 66.72 45.608 67.272 ;
     RECT  45.608 2.016 45.904 67.272 ;
     RECT  44.963 68.928 45.925 68.952 ;
     RECT  45.904 44.64 45.965 47.16 ;
     RECT  45.733 0.096 46.001 0.264 ;
     RECT  46.001 0.144 46.019 0.264 ;
     RECT  45.904 63.12 46.019 64.968 ;
     RECT  46.019 63.12 46.045 64.824 ;
     RECT  45.925 68.4 46.067 68.952 ;
     RECT  46.019 0.24 46.115 0.264 ;
     RECT  45.904 2.016 46.213 8.568 ;
     RECT  46.213 1.248 46.309 8.568 ;
     RECT  45.965 44.64 46.325 47.064 ;
     RECT  46.067 68.496 46.397 68.952 ;
     RECT  46.325 44.928 46.505 47.064 ;
     RECT  46.405 68.976 46.505 69 ;
     RECT  45.904 66.624 47.221 67.272 ;
     RECT  46.309 0.816 47.257 8.568 ;
     RECT  47.221 66.288 47.269 67.272 ;
     RECT  47.257 0.816 47.293 8.952 ;
     RECT  46.045 63.12 47.621 64.488 ;
     RECT  47.293 0.816 47.66 9.096 ;
     RECT  47.66 0.816 47.747 9.288 ;
     RECT  47.557 68.928 47.843 68.952 ;
     RECT  47.621 63.12 47.881 64.392 ;
     RECT  47.881 63.168 47.909 64.392 ;
     RECT  47.269 65.52 47.945 67.272 ;
     RECT  47.945 65.52 47.981 65.544 ;
     RECT  47.747 0.816 48.233 9.096 ;
     RECT  47.909 63.504 48.233 64.392 ;
     RECT  48.233 0.816 48.277 7.416 ;
     RECT  48.233 8.496 48.593 9.096 ;
     RECT  48.277 0.816 48.917 7.128 ;
     RECT  47.945 66.72 48.953 67.272 ;
     RECT  48.953 66.816 49.025 67.272 ;
     RECT  48.956 68.976 49.043 69 ;
     RECT  48.593 8.496 49.097 8.952 ;
     RECT  49.097 8.496 49.169 8.52 ;
     RECT  48.233 63.504 49.273 63.816 ;
     RECT  48.917 0.816 49.285 6.888 ;
     RECT  49.285 0.096 49.417 6.888 ;
     RECT  49.025 67.104 49.421 67.272 ;
     RECT  49.273 63.504 49.529 64.392 ;
     RECT  49.421 67.104 49.601 67.176 ;
     RECT  49.417 0.048 50.137 6.888 ;
     RECT  49.601 67.152 50.213 67.176 ;
     RECT  50.137 0.048 51.008 7.176 ;
     RECT  45.904 23.616 51.008 23.64 ;
     RECT  45.904 30.432 51.008 30.6 ;
     RECT  45.904 32.016 51.008 33.288 ;
     RECT  45.904 39.6 51.008 39.624 ;
     RECT  45.904 42.72 51.008 42.744 ;
     RECT  46.505 45.216 51.008 47.064 ;
     RECT  45.904 49.824 51.008 49.848 ;
     RECT  49.529 64.368 51.008 64.392 ;
     RECT  51.008 0.048 51.112 66.972 ;
     RECT  51.112 0.048 51.304 66.702 ;
     RECT  51.304 0.048 51.581 6.888 ;
     RECT  51.581 5.136 51.971 6.888 ;
     RECT  51.971 5.136 52.013 6.744 ;
     RECT  52.013 5.136 52.019 6.648 ;
     RECT  52.019 5.136 52.163 6.12 ;
     RECT  51.304 22.464 52.229 23.64 ;
     RECT  52.163 5.136 52.373 5.688 ;
     RECT  52.373 5.136 52.409 5.544 ;
     RECT  51.581 0.048 52.729 4.152 ;
     RECT  52.409 5.136 52.729 5.208 ;
     RECT  52.729 0.048 53.453 5.208 ;
     RECT  53.453 5.184 53.597 5.208 ;
     RECT  53.453 0.048 53.633 4.2 ;
     RECT  53.633 0.048 53.813 3.72 ;
     RECT  53.813 0.048 53.885 2.904 ;
     RECT  53.885 0.048 54.173 2.328 ;
     RECT  54.173 0.048 54.245 2.04 ;
     RECT  54.245 0.048 54.389 1.992 ;
     RECT  54.389 1.104 54.605 1.992 ;
     RECT  54.605 1.104 54.893 1.128 ;
     RECT  54.389 0.048 54.929 0.072 ;
     RECT  52.229 22.464 56.408 22.488 ;
     RECT  51.304 30.432 56.408 30.6 ;
     RECT  51.304 32.016 56.408 33.288 ;
     RECT  51.304 39.6 56.408 39.624 ;
     RECT  51.304 42.72 56.408 42.744 ;
     RECT  51.304 45.216 56.408 47.064 ;
     RECT  51.304 49.824 56.408 49.848 ;
     RECT  56.408 2.148 56.512 66.972 ;
     RECT  56.512 2.418 56.704 66.702 ;
     RECT  56.704 31.728 57.161 33.288 ;
     RECT  57.161 31.824 57.197 33.288 ;
     RECT  56.704 42.72 58.705 42.744 ;
     RECT  56.704 49.824 58.705 49.848 ;
     RECT  58.705 29.04 58.853 29.064 ;
     RECT  58.705 38.304 58.889 38.328 ;
     RECT  58.705 49.392 58.889 49.848 ;
     RECT  58.705 41.136 59.497 41.16 ;
     RECT  58.705 42.72 59.569 43.56 ;
     RECT  59.569 42.288 59.713 43.56 ;
     RECT  59.497 40.944 59.785 41.16 ;
     RECT  59.713 42.288 59.785 43.608 ;
     RECT  56.704 39.6 59.857 39.624 ;
     RECT  59.785 40.944 59.857 41.304 ;
     RECT  58.889 49.824 59.857 49.848 ;
     RECT  56.704 22.464 59.893 22.488 ;
     RECT  59.821 27.84 60.041 27.864 ;
     RECT  59.857 39.6 60.133 41.304 ;
     RECT  59.785 42.288 60.145 43.848 ;
     RECT  56.704 45.216 60.145 47.064 ;
     RECT  59.785 35.04 60.149 35.208 ;
     RECT  60.133 39.264 60.179 41.304 ;
     RECT  60.179 39.264 60.181 39.624 ;
     RECT  59.893 22.464 60.217 22.824 ;
     RECT  60.179 40.608 60.401 41.304 ;
     RECT  60.145 42.288 60.476 47.064 ;
     RECT  60.476 41.856 60.563 47.064 ;
     RECT  60.577 29.136 60.649 29.16 ;
     RECT  56.704 30.432 60.649 30.6 ;
     RECT  60.649 29.136 60.721 30.6 ;
     RECT  57.197 32.016 60.721 33.288 ;
     RECT  60.325 24.336 60.793 24.36 ;
     RECT  60.613 27.984 60.793 28.008 ;
     RECT  60.721 29.136 60.793 30.696 ;
     RECT  59.857 49.824 60.793 49.896 ;
     RECT  60.793 27.984 60.865 30.984 ;
     RECT  60.721 32.016 60.865 33.96 ;
     RECT  60.217 22.416 60.901 22.824 ;
     RECT  59.965 48.384 60.901 48.408 ;
     RECT  60.793 49.824 60.901 50.088 ;
     RECT  60.901 22.032 60.973 22.824 ;
     RECT  60.793 23.952 60.973 24.36 ;
     RECT  59.929 26.016 60.973 26.04 ;
     RECT  60.973 22.032 60.997 24.36 ;
     RECT  60.973 25.872 61.052 26.04 ;
     RECT  60.505 37.056 61.333 37.08 ;
     RECT  60.865 27.984 61.369 33.96 ;
     RECT  61.369 27.984 61.441 34.2 ;
     RECT  61.052 25.872 61.477 26.088 ;
     RECT  61.441 27.6 61.477 34.2 ;
     RECT  61.333 37.008 61.585 37.08 ;
     RECT  60.901 48.384 61.657 50.088 ;
     RECT  60.997 21.072 61.808 24.36 ;
     RECT  61.477 25.872 61.808 34.2 ;
     RECT  60.937 35.328 61.808 35.352 ;
     RECT  61.585 37.008 61.808 37.176 ;
     RECT  60.181 38.736 61.808 39.624 ;
     RECT  60.401 40.608 61.808 40.632 ;
     RECT  60.563 42.288 61.808 47.064 ;
     RECT  61.657 48.384 61.808 50.424 ;
     RECT  61.117 51.648 61.808 51.672 ;
     RECT  61.808 2.148 61.912 66.972 ;
     RECT  61.912 2.418 62.104 66.702 ;
     RECT  62.104 30.048 62.165 39.624 ;
     RECT  62.104 25.008 62.237 29.064 ;
     RECT  62.165 30.096 62.243 39.624 ;
     RECT  62.104 40.944 62.381 51.672 ;
     RECT  62.237 25.008 62.525 29.016 ;
     RECT  62.243 30.096 62.669 37.32 ;
     RECT  62.381 40.944 63.205 50.616 ;
     RECT  62.525 27.312 63.241 29.016 ;
     RECT  62.669 30.096 63.241 37.08 ;
     RECT  62.243 38.496 63.241 39.624 ;
     RECT  62.104 21.648 63.493 23.928 ;
     RECT  62.525 25.008 63.493 26.28 ;
     RECT  63.205 40.752 63.497 50.616 ;
     RECT  63.493 20.88 63.533 26.28 ;
     RECT  63.241 38.112 63.565 39.624 ;
     RECT  63.497 40.752 63.565 49.512 ;
     RECT  63.565 38.112 63.569 49.512 ;
     RECT  63.533 20.88 63.745 20.904 ;
     RECT  63.533 21.936 63.817 26.28 ;
     RECT  63.241 27.312 63.817 37.08 ;
     RECT  63.497 50.592 63.821 50.616 ;
     RECT  63.569 38.112 64.253 47.928 ;
     RECT  63.817 21.936 64.285 37.08 ;
     RECT  64.253 38.112 64.285 43.128 ;
     RECT  64.253 44.208 64.289 47.928 ;
     RECT  63.745 20.592 64.501 20.904 ;
     RECT  64.285 21.936 64.501 43.128 ;
     RECT  62.381 51.648 64.501 51.672 ;
     RECT  64.501 20.592 64.577 43.128 ;
     RECT  64.289 44.208 64.577 47.496 ;
     RECT  64.501 51.312 64.597 51.672 ;
     RECT  64.577 23.328 64.649 43.128 ;
     RECT  63.569 48.912 64.684 49.512 ;
     RECT  64.649 28.944 64.685 43.128 ;
     RECT  64.685 33.024 64.757 43.128 ;
     RECT  64.649 23.328 64.865 27.816 ;
     RECT  64.757 33.024 64.865 37.368 ;
     RECT  64.597 51.312 64.865 51.912 ;
     RECT  64.865 33.024 64.901 36.072 ;
     RECT  64.577 44.208 64.901 44.712 ;
     RECT  64.577 20.592 64.973 22.248 ;
     RECT  64.901 35.232 64.973 36.072 ;
     RECT  64.865 23.328 65.009 26.808 ;
     RECT  65.009 23.712 65.081 26.808 ;
     RECT  64.901 33.024 65.081 34.104 ;
     RECT  65.081 23.712 65.117 24.264 ;
     RECT  64.865 37.344 65.117 37.368 ;
     RECT  64.757 38.736 65.171 43.128 ;
     RECT  64.685 28.944 65.189 31.944 ;
     RECT  65.081 33.696 65.189 34.104 ;
     RECT  64.901 44.208 65.189 44.424 ;
     RECT  65.081 25.296 65.261 26.808 ;
     RECT  65.171 39.6 65.297 43.128 ;
     RECT  65.297 40.8 65.369 40.824 ;
     RECT  64.577 45.84 65.405 47.496 ;
     RECT  65.189 30.576 65.441 31.944 ;
     RECT  64.973 20.592 65.585 22.008 ;
     RECT  65.189 33.696 65.585 34.056 ;
     RECT  65.297 41.904 65.657 43.128 ;
     RECT  65.189 28.944 65.725 29.544 ;
     RECT  65.441 31.344 65.765 31.944 ;
     RECT  65.585 33.696 65.837 33.72 ;
     RECT  65.585 20.592 65.873 21.528 ;
     RECT  65.765 31.44 65.873 31.944 ;
     RECT  64.973 35.424 65.873 36.072 ;
     RECT  64.684 48.912 65.909 48.936 ;
     RECT  64.865 27.792 65.945 27.816 ;
     RECT  65.117 23.712 65.981 23.736 ;
     RECT  65.657 41.904 66.161 43.032 ;
     RECT  65.261 25.488 66.197 26.808 ;
     RECT  65.873 31.632 66.229 31.944 ;
     RECT  65.405 47.04 66.233 47.496 ;
     RECT  65.725 28.848 66.301 29.544 ;
     RECT  66.197 26.784 66.373 26.808 ;
     RECT  66.161 42.288 66.697 43.032 ;
     RECT  65.189 44.208 66.697 44.232 ;
     RECT  64.865 51.312 66.697 51.336 ;
     RECT  65.873 20.832 66.701 21.528 ;
     RECT  66.697 37.008 66.733 37.032 ;
     RECT  66.697 38.064 66.733 38.088 ;
     RECT  66.233 47.472 67.201 47.496 ;
     RECT  66.697 22.8 67.237 22.92 ;
     RECT  66.197 25.488 67.237 25.512 ;
     RECT  66.373 26.784 67.237 27.72 ;
     RECT  66.301 28.848 67.237 29.928 ;
     RECT  66.229 31.632 67.237 32.52 ;
     RECT  65.873 35.424 67.237 35.976 ;
     RECT  66.733 37.008 67.237 38.088 ;
     RECT  66.697 39.408 67.237 39.432 ;
     RECT  66.697 42.288 67.237 44.808 ;
     RECT  66.697 46.128 67.237 46.152 ;
     RECT  67.201 47.472 67.237 48.072 ;
     RECT  66.697 50.448 67.237 51.336 ;
     RECT  67.237 22.8 67.273 23.016 ;
     RECT  67.237 25.488 67.273 27.72 ;
     RECT  67.237 28.848 67.273 32.52 ;
     RECT  67.237 34.224 67.273 34.248 ;
     RECT  67.237 35.424 67.273 38.088 ;
     RECT  67.237 39.408 67.273 40.392 ;
     RECT  67.237 42.288 67.273 48.072 ;
     RECT  67.273 22.8 67.309 27.72 ;
     RECT  67.273 28.848 67.309 38.184 ;
     RECT  67.273 39.408 67.309 41.16 ;
     RECT  67.309 22.8 67.741 38.184 ;
     RECT  67.309 39.408 67.741 41.256 ;
     RECT  67.273 42.288 67.741 48.744 ;
     RECT  66.701 21.072 67.777 21.096 ;
     RECT  67.741 22.704 67.777 38.184 ;
     RECT  67.741 39.408 67.777 48.744 ;
     RECT  67.237 50.064 67.777 51.336 ;
     RECT  67.777 20.4 68.317 51.336 ;
     RECT  68.317 20.304 68.353 51.336 ;
     RECT  68.353 19.92 69.036 19.944 ;
     RECT  68.353 19.944 69.084 20.016 ;
     RECT  68.353 20.016 69.036 20.04 ;
     RECT  68.353 20.04 69.084 20.112 ;
     RECT  68.353 20.112 69.036 20.136 ;
     RECT  68.353 20.136 69.084 20.208 ;
     RECT  68.353 20.208 69.036 20.232 ;
     RECT  68.353 20.232 69.084 20.304 ;
     RECT  68.353 20.304 69.036 20.328 ;
     RECT  68.353 20.328 69.084 20.4 ;
     RECT  68.353 20.4 69.036 20.424 ;
     RECT  68.353 20.424 69.084 20.496 ;
     RECT  68.353 20.496 69.036 20.52 ;
     RECT  68.353 20.52 69.084 20.592 ;
     RECT  68.353 20.592 69.036 20.616 ;
     RECT  68.353 20.616 69.084 20.688 ;
     RECT  68.353 20.688 69.036 20.712 ;
     RECT  68.353 20.712 69.084 20.784 ;
     RECT  68.353 20.784 69.036 20.808 ;
     RECT  68.353 20.808 69.084 20.88 ;
     RECT  68.353 20.88 69.036 20.904 ;
     RECT  68.353 20.904 69.084 20.976 ;
     RECT  68.353 20.976 69.036 21 ;
     RECT  68.353 21 69.084 21.072 ;
     RECT  68.353 21.072 69.036 21.096 ;
     RECT  68.353 21.096 69.084 21.168 ;
     RECT  68.353 21.168 69.036 21.192 ;
     RECT  68.353 21.192 69.084 21.264 ;
     RECT  68.353 21.264 69.036 21.288 ;
     RECT  68.353 21.288 69.084 21.36 ;
     RECT  68.353 21.36 69.036 21.384 ;
     RECT  68.353 21.384 69.084 21.456 ;
     RECT  68.353 21.456 69.036 21.48 ;
     RECT  68.353 21.48 69.084 21.552 ;
     RECT  68.353 21.552 69.036 21.576 ;
     RECT  68.353 21.576 69.084 21.648 ;
     RECT  68.353 21.648 69.036 21.672 ;
     RECT  68.353 21.672 69.084 21.744 ;
     RECT  68.353 21.744 69.036 21.768 ;
     RECT  68.353 21.768 69.084 21.84 ;
     RECT  68.353 21.84 69.036 21.864 ;
     RECT  68.353 21.864 69.084 21.936 ;
     RECT  68.353 21.936 69.036 21.96 ;
     RECT  68.353 21.96 69.084 22.032 ;
     RECT  68.353 22.032 69.036 22.056 ;
     RECT  68.353 22.056 69.084 22.128 ;
     RECT  68.353 22.128 69.036 22.152 ;
     RECT  68.353 22.152 69.084 22.224 ;
     RECT  68.353 22.224 69.036 22.248 ;
     RECT  68.353 22.248 69.084 22.32 ;
     RECT  68.353 22.32 69.036 22.344 ;
     RECT  68.353 22.344 69.084 22.416 ;
     RECT  68.353 22.416 69.036 22.44 ;
     RECT  68.353 22.44 69.084 22.512 ;
     RECT  68.353 22.512 69.036 22.536 ;
     RECT  68.353 22.536 69.084 22.608 ;
     RECT  68.353 22.608 69.036 22.632 ;
     RECT  68.353 22.632 69.084 22.704 ;
     RECT  68.353 22.704 69.036 22.728 ;
     RECT  68.353 22.728 69.084 22.8 ;
     RECT  68.353 22.8 69.036 22.824 ;
     RECT  68.353 22.824 69.084 22.896 ;
     RECT  68.353 22.896 69.036 22.92 ;
     RECT  68.353 22.92 69.084 22.992 ;
     RECT  68.353 22.992 69.036 23.016 ;
     RECT  68.353 23.016 69.084 23.088 ;
     RECT  68.353 23.088 69.036 23.112 ;
     RECT  68.353 23.112 69.084 23.184 ;
     RECT  68.353 23.184 69.036 23.208 ;
     RECT  68.353 23.208 69.084 23.28 ;
     RECT  68.353 23.28 69.036 23.304 ;
     RECT  68.353 23.304 69.084 23.376 ;
     RECT  68.353 23.376 69.036 23.4 ;
     RECT  68.353 23.4 69.084 23.472 ;
     RECT  68.353 23.472 69.036 23.496 ;
     RECT  68.353 23.496 69.084 23.568 ;
     RECT  68.353 23.568 69.036 23.592 ;
     RECT  68.353 23.592 69.084 23.664 ;
     RECT  68.353 23.664 69.036 23.688 ;
     RECT  68.353 23.688 69.084 23.76 ;
     RECT  68.353 23.76 69.036 23.784 ;
     RECT  68.353 23.784 69.084 23.856 ;
     RECT  68.353 23.856 69.036 23.88 ;
     RECT  68.353 23.88 69.084 23.952 ;
     RECT  68.353 23.952 69.036 23.976 ;
     RECT  68.353 23.976 69.084 24.048 ;
     RECT  68.353 24.048 69.036 24.072 ;
     RECT  68.353 24.072 69.084 24.144 ;
     RECT  68.353 24.144 69.036 24.168 ;
     RECT  68.353 24.168 69.084 24.24 ;
     RECT  68.353 24.24 69.036 24.264 ;
     RECT  68.353 24.264 69.084 24.336 ;
     RECT  68.353 24.336 69.036 24.36 ;
     RECT  68.353 24.36 69.084 24.432 ;
     RECT  68.353 24.432 69.036 24.456 ;
     RECT  68.353 24.456 69.084 24.528 ;
     RECT  68.353 24.528 69.036 24.552 ;
     RECT  68.353 24.552 69.084 24.624 ;
     RECT  68.353 24.624 69.036 24.648 ;
     RECT  68.353 24.648 69.084 24.72 ;
     RECT  68.353 24.72 69.036 24.744 ;
     RECT  68.353 24.744 69.084 24.816 ;
     RECT  68.353 24.816 69.036 24.84 ;
     RECT  68.353 24.84 69.084 24.912 ;
     RECT  68.353 24.912 69.036 24.936 ;
     RECT  68.353 24.936 69.084 25.008 ;
     RECT  68.353 25.008 69.036 25.032 ;
     RECT  68.353 25.032 69.084 25.104 ;
     RECT  68.353 25.104 69.036 25.128 ;
     RECT  68.353 25.128 69.084 25.2 ;
     RECT  68.353 25.2 69.036 25.224 ;
     RECT  68.353 25.224 69.084 25.296 ;
     RECT  68.353 25.296 69.036 25.32 ;
     RECT  68.353 25.32 69.084 25.392 ;
     RECT  68.353 25.392 69.036 25.416 ;
     RECT  68.353 25.416 69.084 25.488 ;
     RECT  68.353 25.488 69.036 25.512 ;
     RECT  68.353 25.512 69.084 25.584 ;
     RECT  68.353 25.584 69.036 25.608 ;
     RECT  68.353 25.608 69.084 25.68 ;
     RECT  68.353 25.68 69.036 25.704 ;
     RECT  68.353 25.704 69.084 25.776 ;
     RECT  68.353 25.776 69.036 25.8 ;
     RECT  68.353 25.8 69.084 25.872 ;
     RECT  68.353 25.872 69.036 25.896 ;
     RECT  68.353 25.896 69.084 25.968 ;
     RECT  68.353 25.968 69.036 25.992 ;
     RECT  68.353 25.992 69.084 26.064 ;
     RECT  68.353 26.064 69.036 26.088 ;
     RECT  68.353 26.088 69.084 26.16 ;
     RECT  68.353 26.16 69.036 26.184 ;
     RECT  68.353 26.184 69.084 26.256 ;
     RECT  68.353 26.256 69.036 26.28 ;
     RECT  68.353 26.28 69.084 26.352 ;
     RECT  68.353 26.352 69.036 26.376 ;
     RECT  68.353 26.376 69.084 26.448 ;
     RECT  68.353 26.448 69.036 26.472 ;
     RECT  68.353 26.472 69.084 26.544 ;
     RECT  68.353 26.544 69.036 26.568 ;
     RECT  68.353 26.568 69.084 26.64 ;
     RECT  68.353 26.64 69.036 26.664 ;
     RECT  68.353 26.664 69.084 26.736 ;
     RECT  68.353 26.736 69.036 26.76 ;
     RECT  68.353 26.76 69.084 26.832 ;
     RECT  68.353 26.832 69.036 26.856 ;
     RECT  68.353 26.856 69.084 26.928 ;
     RECT  68.353 26.928 69.036 26.952 ;
     RECT  68.353 26.952 69.084 27.024 ;
     RECT  68.353 27.024 69.036 27.048 ;
     RECT  68.353 27.048 69.084 27.12 ;
     RECT  68.353 27.12 69.036 27.144 ;
     RECT  68.353 27.144 69.084 27.216 ;
     RECT  68.353 27.216 69.036 27.24 ;
     RECT  68.353 27.24 69.084 27.312 ;
     RECT  68.353 27.312 69.036 27.336 ;
     RECT  68.353 27.336 69.084 27.408 ;
     RECT  68.353 27.408 69.036 27.432 ;
     RECT  68.353 27.432 69.084 27.504 ;
     RECT  68.353 27.504 69.036 27.528 ;
     RECT  68.353 27.528 69.084 27.6 ;
     RECT  68.353 27.6 69.036 27.624 ;
     RECT  68.353 27.624 69.084 27.696 ;
     RECT  68.353 27.696 69.036 27.72 ;
     RECT  68.353 27.72 69.084 27.792 ;
     RECT  68.353 27.792 69.036 27.816 ;
     RECT  68.353 27.816 69.084 27.888 ;
     RECT  68.353 27.888 69.036 27.912 ;
     RECT  68.353 27.912 69.084 27.984 ;
     RECT  68.353 27.984 69.036 28.008 ;
     RECT  68.353 28.008 69.084 28.08 ;
     RECT  68.353 28.08 69.036 28.104 ;
     RECT  68.353 28.104 69.084 28.176 ;
     RECT  68.353 28.176 69.036 28.2 ;
     RECT  68.353 28.2 69.084 28.272 ;
     RECT  68.353 28.272 69.036 28.296 ;
     RECT  68.353 28.296 69.084 28.368 ;
     RECT  68.353 28.368 69.036 28.392 ;
     RECT  68.353 28.392 69.084 28.464 ;
     RECT  68.353 28.464 69.036 28.488 ;
     RECT  68.353 28.488 69.084 28.56 ;
     RECT  68.353 28.56 69.036 28.584 ;
     RECT  68.353 28.584 69.084 28.656 ;
     RECT  68.353 28.656 69.036 28.68 ;
     RECT  68.353 28.68 69.084 28.752 ;
     RECT  68.353 28.752 69.036 28.776 ;
     RECT  68.353 28.776 69.084 28.848 ;
     RECT  68.353 28.848 69.036 28.872 ;
     RECT  68.353 28.872 69.084 28.944 ;
     RECT  68.353 28.944 69.036 28.968 ;
     RECT  68.353 28.968 69.084 29.04 ;
     RECT  68.353 29.04 69.036 29.064 ;
     RECT  68.353 29.064 69.084 29.136 ;
     RECT  68.353 29.136 69.036 29.16 ;
     RECT  68.353 29.16 69.084 29.232 ;
     RECT  68.353 29.232 69.036 29.256 ;
     RECT  68.353 29.256 69.084 29.328 ;
     RECT  68.353 29.328 69.036 29.352 ;
     RECT  68.353 29.352 69.084 29.424 ;
     RECT  68.353 29.424 69.036 29.448 ;
     RECT  68.353 29.448 69.084 29.52 ;
     RECT  68.353 29.52 69.036 29.544 ;
     RECT  68.353 29.544 69.084 29.616 ;
     RECT  68.353 29.616 69.036 29.64 ;
     RECT  68.353 29.64 69.084 29.712 ;
     RECT  68.353 29.712 69.036 29.736 ;
     RECT  68.353 29.736 69.084 29.808 ;
     RECT  68.353 29.808 69.036 29.832 ;
     RECT  68.353 29.832 69.084 29.904 ;
     RECT  68.353 29.904 69.036 29.928 ;
     RECT  68.353 29.928 69.084 30 ;
     RECT  68.353 30 69.036 30.024 ;
     RECT  68.353 30.024 69.084 30.096 ;
     RECT  68.353 30.096 69.036 30.12 ;
     RECT  68.353 30.12 69.084 30.192 ;
     RECT  68.353 30.192 69.036 30.216 ;
     RECT  68.353 30.216 69.084 30.288 ;
     RECT  68.353 30.288 69.036 30.312 ;
     RECT  68.353 30.312 69.084 30.384 ;
     RECT  68.353 30.384 69.036 30.408 ;
     RECT  68.353 30.408 69.084 30.48 ;
     RECT  68.353 30.48 69.036 30.504 ;
     RECT  68.353 30.504 69.084 30.576 ;
     RECT  68.353 30.576 69.036 30.6 ;
     RECT  68.353 30.6 69.084 30.672 ;
     RECT  68.353 30.672 69.036 30.696 ;
     RECT  68.353 30.696 69.084 30.768 ;
     RECT  68.353 30.768 69.036 30.792 ;
     RECT  68.353 30.792 69.084 30.864 ;
     RECT  68.353 30.864 69.036 30.888 ;
     RECT  68.353 30.888 69.084 30.96 ;
     RECT  68.353 30.96 69.036 30.984 ;
     RECT  68.353 30.984 69.084 31.056 ;
     RECT  68.353 31.056 69.036 31.08 ;
     RECT  68.353 31.08 69.084 31.152 ;
     RECT  68.353 31.152 69.036 31.176 ;
     RECT  68.353 31.176 69.084 31.248 ;
     RECT  68.353 31.248 69.036 31.272 ;
     RECT  68.353 31.272 69.084 31.344 ;
     RECT  68.353 31.344 69.036 31.368 ;
     RECT  68.353 31.368 69.084 31.44 ;
     RECT  68.353 31.44 69.036 31.464 ;
     RECT  68.353 31.464 69.084 31.536 ;
     RECT  68.353 31.536 69.036 31.56 ;
     RECT  68.353 31.56 69.084 31.632 ;
     RECT  68.353 31.632 69.036 31.656 ;
     RECT  68.353 31.656 69.084 31.728 ;
     RECT  68.353 31.728 69.036 31.752 ;
     RECT  68.353 31.752 69.084 31.824 ;
     RECT  68.353 31.824 69.036 31.848 ;
     RECT  68.353 31.848 69.084 31.92 ;
     RECT  68.353 31.92 69.036 31.944 ;
     RECT  68.353 31.944 69.084 32.016 ;
     RECT  68.353 32.016 69.036 32.04 ;
     RECT  68.353 32.04 69.084 32.112 ;
     RECT  68.353 32.112 69.036 32.136 ;
     RECT  68.353 32.136 69.084 32.208 ;
     RECT  68.353 32.208 69.036 32.232 ;
     RECT  68.353 32.232 69.084 32.304 ;
     RECT  68.353 32.304 69.036 32.328 ;
     RECT  68.353 32.328 69.084 32.4 ;
     RECT  68.353 32.4 69.036 32.424 ;
     RECT  68.353 32.424 69.084 32.496 ;
     RECT  68.353 32.496 69.036 32.52 ;
     RECT  68.353 32.52 69.084 32.592 ;
     RECT  68.353 32.592 69.036 32.616 ;
     RECT  68.353 32.616 69.084 32.688 ;
     RECT  68.353 32.688 69.036 32.712 ;
     RECT  68.353 32.712 69.084 32.784 ;
     RECT  68.353 32.784 69.036 32.808 ;
     RECT  68.353 32.808 69.084 32.88 ;
     RECT  68.353 32.88 69.036 32.904 ;
     RECT  68.353 32.904 69.084 32.976 ;
     RECT  68.353 32.976 69.036 33 ;
     RECT  68.353 33 69.084 33.072 ;
     RECT  68.353 33.072 69.036 33.096 ;
     RECT  68.353 33.096 69.084 33.168 ;
     RECT  68.353 33.168 69.036 33.192 ;
     RECT  68.353 33.192 69.084 33.264 ;
     RECT  68.353 33.264 69.036 33.288 ;
     RECT  68.353 33.288 69.084 33.36 ;
     RECT  68.353 33.36 69.036 33.384 ;
     RECT  68.353 33.384 69.084 33.456 ;
     RECT  68.353 33.456 69.036 33.48 ;
     RECT  68.353 33.48 69.084 33.552 ;
     RECT  68.353 33.552 69.036 33.576 ;
     RECT  68.353 33.576 69.084 33.648 ;
     RECT  68.353 33.648 69.036 33.672 ;
     RECT  68.353 33.672 69.084 33.744 ;
     RECT  68.353 33.744 69.036 33.768 ;
     RECT  68.353 33.768 69.084 33.84 ;
     RECT  68.353 33.84 69.036 33.864 ;
     RECT  68.353 33.864 69.084 33.936 ;
     RECT  68.353 33.936 69.036 33.96 ;
     RECT  68.353 33.96 69.084 34.032 ;
     RECT  68.353 34.032 69.036 34.056 ;
     RECT  68.353 34.056 69.084 34.128 ;
     RECT  68.353 34.128 69.036 34.152 ;
     RECT  68.353 34.152 69.084 34.224 ;
     RECT  68.353 34.224 69.036 34.248 ;
     RECT  68.353 34.248 69.084 34.32 ;
     RECT  68.353 34.32 69.036 34.344 ;
     RECT  68.353 34.344 69.084 34.416 ;
     RECT  68.353 34.416 69.036 34.44 ;
     RECT  68.353 34.44 69.084 34.512 ;
     RECT  68.353 34.512 69.036 34.536 ;
     RECT  68.353 34.536 69.084 34.608 ;
     RECT  68.353 34.608 69.036 34.632 ;
     RECT  68.353 34.632 69.084 34.704 ;
     RECT  68.353 34.704 69.036 34.728 ;
     RECT  68.353 34.728 69.084 34.8 ;
     RECT  68.353 34.8 69.036 34.824 ;
     RECT  68.353 34.824 69.084 34.896 ;
     RECT  68.353 34.896 69.036 34.92 ;
     RECT  68.353 34.92 69.084 34.992 ;
     RECT  68.353 34.992 69.036 35.016 ;
     RECT  68.353 35.016 69.084 35.088 ;
     RECT  68.353 35.088 69.036 35.112 ;
     RECT  68.353 35.112 69.084 35.184 ;
     RECT  68.353 35.184 69.036 35.208 ;
     RECT  68.353 35.208 69.084 35.28 ;
     RECT  68.353 35.28 69.036 35.304 ;
     RECT  68.353 35.304 69.084 35.376 ;
     RECT  68.353 35.376 69.036 35.4 ;
     RECT  68.353 35.4 69.084 35.472 ;
     RECT  68.353 35.472 69.036 35.496 ;
     RECT  68.353 35.496 69.084 35.568 ;
     RECT  68.353 35.568 69.036 35.592 ;
     RECT  68.353 35.592 69.084 35.664 ;
     RECT  68.353 35.664 69.036 35.688 ;
     RECT  68.353 35.688 69.084 35.76 ;
     RECT  68.353 35.76 69.036 35.784 ;
     RECT  68.353 35.784 69.084 35.856 ;
     RECT  68.353 35.856 69.036 35.88 ;
     RECT  68.353 35.88 69.084 35.952 ;
     RECT  68.353 35.952 69.036 35.976 ;
     RECT  68.353 35.976 69.084 36.048 ;
     RECT  68.353 36.048 69.036 36.072 ;
     RECT  68.353 36.072 69.084 36.144 ;
     RECT  68.353 36.144 69.036 36.168 ;
     RECT  68.353 36.168 69.084 36.24 ;
     RECT  68.353 36.24 69.036 36.264 ;
     RECT  68.353 36.264 69.084 36.336 ;
     RECT  68.353 36.336 69.036 36.36 ;
     RECT  68.353 36.36 69.084 36.432 ;
     RECT  68.353 36.432 69.036 36.456 ;
     RECT  68.353 36.456 69.084 36.528 ;
     RECT  68.353 36.528 69.036 36.552 ;
     RECT  68.353 36.552 69.084 36.624 ;
     RECT  68.353 36.624 69.036 36.648 ;
     RECT  68.353 36.648 69.084 36.72 ;
     RECT  68.353 36.72 69.036 36.744 ;
     RECT  68.353 36.744 69.084 36.816 ;
     RECT  68.353 36.816 69.036 36.84 ;
     RECT  68.353 36.84 69.084 36.912 ;
     RECT  68.353 36.912 69.036 36.936 ;
     RECT  68.353 36.936 69.084 37.008 ;
     RECT  68.353 37.008 69.036 37.032 ;
     RECT  68.353 37.032 69.084 37.104 ;
     RECT  68.353 37.104 69.036 37.128 ;
     RECT  68.353 37.128 69.084 37.2 ;
     RECT  68.353 37.2 69.036 37.224 ;
     RECT  68.353 37.224 69.084 37.296 ;
     RECT  68.353 37.296 69.036 37.32 ;
     RECT  68.353 37.32 69.084 37.392 ;
     RECT  68.353 37.392 69.036 37.416 ;
     RECT  68.353 37.416 69.084 37.488 ;
     RECT  68.353 37.488 69.036 37.512 ;
     RECT  68.353 37.512 69.084 37.584 ;
     RECT  68.353 37.584 69.036 37.608 ;
     RECT  68.353 37.608 69.084 37.68 ;
     RECT  68.353 37.68 69.036 37.704 ;
     RECT  68.353 37.704 69.084 37.776 ;
     RECT  68.353 37.776 69.036 37.8 ;
     RECT  68.353 37.8 69.084 37.872 ;
     RECT  68.353 37.872 69.036 37.896 ;
     RECT  68.353 37.896 69.084 37.968 ;
     RECT  68.353 37.968 69.036 37.992 ;
     RECT  68.353 37.992 69.084 38.064 ;
     RECT  68.353 38.064 69.036 38.088 ;
     RECT  68.353 38.088 69.084 38.16 ;
     RECT  68.353 38.16 69.036 38.184 ;
     RECT  68.353 38.184 69.084 38.256 ;
     RECT  68.353 38.256 69.036 38.28 ;
     RECT  68.353 38.28 69.084 39.12 ;
     RECT  68.353 39.12 69.036 39.144 ;
     RECT  68.353 39.144 69.084 39.216 ;
     RECT  68.353 39.216 69.036 39.24 ;
     RECT  68.353 39.24 69.084 39.312 ;
     RECT  68.353 39.312 69.036 39.336 ;
     RECT  68.353 39.336 69.084 39.408 ;
     RECT  68.353 39.408 69.036 39.432 ;
     RECT  68.353 39.432 69.084 39.504 ;
     RECT  68.353 39.504 69.036 39.528 ;
     RECT  68.353 39.528 69.084 39.6 ;
     RECT  68.353 39.6 69.036 39.624 ;
     RECT  68.353 39.624 69.084 39.696 ;
     RECT  68.353 39.696 69.036 39.72 ;
     RECT  68.353 39.72 69.084 39.792 ;
     RECT  68.353 39.792 69.036 39.816 ;
     RECT  68.353 39.816 69.084 39.888 ;
     RECT  68.353 39.888 69.036 39.912 ;
     RECT  68.353 39.912 69.084 39.984 ;
     RECT  68.353 39.984 69.036 40.008 ;
     RECT  68.353 40.008 69.084 40.08 ;
     RECT  68.353 40.08 69.036 40.104 ;
     RECT  68.353 40.104 69.084 40.176 ;
     RECT  68.353 40.176 69.036 40.2 ;
     RECT  68.353 40.2 69.084 40.272 ;
     RECT  68.353 40.272 69.036 40.296 ;
     RECT  68.353 40.296 69.084 40.368 ;
     RECT  68.353 40.368 69.036 40.392 ;
     RECT  68.353 40.392 69.084 40.464 ;
     RECT  68.353 40.464 69.036 40.488 ;
     RECT  68.353 40.488 69.084 40.56 ;
     RECT  68.353 40.56 69.036 40.584 ;
     RECT  68.353 40.584 69.084 40.656 ;
     RECT  68.353 40.656 69.036 40.68 ;
     RECT  68.353 40.68 69.084 40.752 ;
     RECT  68.353 40.752 69.036 40.776 ;
     RECT  68.353 40.776 69.084 40.848 ;
     RECT  68.353 40.848 69.036 40.872 ;
     RECT  68.353 40.872 69.084 40.944 ;
     RECT  68.353 40.944 69.036 40.968 ;
     RECT  68.353 40.968 69.084 41.04 ;
     RECT  68.353 41.04 69.036 41.064 ;
     RECT  68.353 41.064 69.084 41.136 ;
     RECT  68.353 41.136 69.036 41.16 ;
     RECT  68.353 41.16 69.084 41.232 ;
     RECT  68.353 41.232 69.036 41.256 ;
     RECT  68.353 41.256 69.084 41.328 ;
     RECT  68.353 41.328 69.036 41.352 ;
     RECT  68.353 41.352 69.084 41.424 ;
     RECT  68.353 41.424 69.036 41.448 ;
     RECT  68.353 41.448 69.084 41.52 ;
     RECT  68.353 41.52 69.036 41.544 ;
     RECT  68.353 41.544 69.084 41.616 ;
     RECT  68.353 41.616 69.036 41.64 ;
     RECT  68.353 41.64 69.084 41.712 ;
     RECT  68.353 41.712 69.036 41.736 ;
     RECT  68.353 41.736 69.084 41.808 ;
     RECT  68.353 41.808 69.036 41.832 ;
     RECT  68.353 41.832 69.084 41.904 ;
     RECT  68.353 41.904 69.036 41.928 ;
     RECT  68.353 41.928 69.084 42 ;
     RECT  68.353 42 69.036 42.024 ;
     RECT  68.353 42.024 69.084 42.096 ;
     RECT  68.353 42.096 69.036 42.12 ;
     RECT  68.353 42.12 69.084 42.192 ;
     RECT  68.353 42.192 69.036 42.216 ;
     RECT  68.353 42.216 69.084 42.288 ;
     RECT  68.353 42.288 69.036 42.312 ;
     RECT  68.353 42.312 69.084 42.384 ;
     RECT  68.353 42.384 69.036 42.408 ;
     RECT  68.353 42.408 69.084 42.48 ;
     RECT  68.353 42.48 69.036 42.504 ;
     RECT  68.353 42.504 69.084 42.576 ;
     RECT  68.353 42.576 69.036 42.6 ;
     RECT  68.353 42.6 69.084 42.672 ;
     RECT  68.353 42.672 69.036 42.696 ;
     RECT  68.353 42.696 69.084 42.768 ;
     RECT  68.353 42.768 69.036 42.792 ;
     RECT  68.353 42.792 69.084 42.864 ;
     RECT  68.353 42.864 69.036 42.888 ;
     RECT  68.353 42.888 69.084 42.96 ;
     RECT  68.353 42.96 69.036 42.984 ;
     RECT  68.353 42.984 69.084 43.056 ;
     RECT  68.353 43.056 69.036 43.08 ;
     RECT  68.353 43.08 69.084 43.152 ;
     RECT  68.353 43.152 69.036 43.176 ;
     RECT  68.353 43.176 69.084 43.248 ;
     RECT  68.353 43.248 69.036 43.272 ;
     RECT  68.353 43.272 69.084 43.344 ;
     RECT  68.353 43.344 69.036 43.368 ;
     RECT  68.353 43.368 69.084 43.44 ;
     RECT  68.353 43.44 69.036 43.464 ;
     RECT  68.353 43.464 69.084 43.536 ;
     RECT  68.353 43.536 69.036 43.56 ;
     RECT  68.353 43.56 69.084 43.632 ;
     RECT  68.353 43.632 69.036 43.656 ;
     RECT  68.353 43.656 69.084 43.728 ;
     RECT  68.353 43.728 69.036 43.752 ;
     RECT  68.353 43.752 69.084 43.824 ;
     RECT  68.353 43.824 69.036 43.848 ;
     RECT  68.353 43.848 69.084 43.92 ;
     RECT  68.353 43.92 69.036 43.944 ;
     RECT  68.353 43.944 69.084 44.016 ;
     RECT  68.353 44.016 69.036 44.04 ;
     RECT  68.353 44.04 69.084 44.112 ;
     RECT  68.353 44.112 69.036 44.136 ;
     RECT  68.353 44.136 69.084 44.208 ;
     RECT  68.353 44.208 69.036 44.232 ;
     RECT  68.353 44.232 69.084 44.304 ;
     RECT  68.353 44.304 69.036 44.328 ;
     RECT  68.353 44.328 69.084 44.4 ;
     RECT  68.353 44.4 69.036 44.424 ;
     RECT  68.353 44.424 69.084 44.496 ;
     RECT  68.353 44.496 69.036 44.52 ;
     RECT  68.353 44.52 69.084 44.592 ;
     RECT  68.353 44.592 69.036 44.616 ;
     RECT  68.353 44.616 69.084 44.688 ;
     RECT  68.353 44.688 69.036 44.712 ;
     RECT  68.353 44.712 69.084 44.784 ;
     RECT  68.353 44.784 69.036 44.808 ;
     RECT  68.353 44.808 69.084 44.88 ;
     RECT  68.353 44.88 69.036 44.904 ;
     RECT  68.353 44.904 69.084 44.976 ;
     RECT  68.353 44.976 69.036 45 ;
     RECT  68.353 45 69.084 45.072 ;
     RECT  68.353 45.072 69.036 45.096 ;
     RECT  68.353 45.096 69.084 45.168 ;
     RECT  68.353 45.168 69.036 45.192 ;
     RECT  68.353 45.192 69.084 45.264 ;
     RECT  68.353 45.264 69.036 45.288 ;
     RECT  68.353 45.288 69.084 45.36 ;
     RECT  68.353 45.36 69.036 45.384 ;
     RECT  68.353 45.384 69.084 45.456 ;
     RECT  68.353 45.456 69.036 45.48 ;
     RECT  68.353 45.48 69.084 45.552 ;
     RECT  68.353 45.552 69.036 45.576 ;
     RECT  68.353 45.576 69.084 45.648 ;
     RECT  68.353 45.648 69.036 45.672 ;
     RECT  68.353 45.672 69.084 45.744 ;
     RECT  68.353 45.744 69.036 45.768 ;
     RECT  68.353 45.768 69.084 45.84 ;
     RECT  68.353 45.84 69.036 45.864 ;
     RECT  68.353 45.864 69.084 45.936 ;
     RECT  68.353 45.936 69.036 45.96 ;
     RECT  68.353 45.96 69.084 46.032 ;
     RECT  68.353 46.032 69.036 46.056 ;
     RECT  68.353 46.056 69.084 46.128 ;
     RECT  68.353 46.128 69.036 46.152 ;
     RECT  68.353 46.152 69.084 46.224 ;
     RECT  68.353 46.224 69.036 46.248 ;
     RECT  68.353 46.248 69.084 46.32 ;
     RECT  68.353 46.32 69.036 46.344 ;
     RECT  68.353 46.344 69.084 46.416 ;
     RECT  68.353 46.416 69.036 46.44 ;
     RECT  68.353 46.44 69.084 46.512 ;
     RECT  68.353 46.512 69.036 46.536 ;
     RECT  68.353 46.536 69.084 46.608 ;
     RECT  68.353 46.608 69.036 46.632 ;
     RECT  68.353 46.632 69.084 46.704 ;
     RECT  68.353 46.704 69.036 46.728 ;
     RECT  68.353 46.728 69.084 46.8 ;
     RECT  68.353 46.8 69.036 46.824 ;
     RECT  68.353 46.824 69.084 46.896 ;
     RECT  68.353 46.896 69.036 46.92 ;
     RECT  68.353 46.92 69.084 46.992 ;
     RECT  68.353 46.992 69.036 47.016 ;
     RECT  68.353 47.016 69.084 47.088 ;
     RECT  68.353 47.088 69.036 47.112 ;
     RECT  68.353 47.112 69.084 47.184 ;
     RECT  68.353 47.184 69.036 47.208 ;
     RECT  68.353 47.208 69.084 47.28 ;
     RECT  68.353 47.28 69.036 47.304 ;
     RECT  68.353 47.304 69.084 47.376 ;
     RECT  68.353 47.376 69.036 47.4 ;
     RECT  68.353 47.4 69.084 47.472 ;
     RECT  68.353 47.472 69.036 47.496 ;
     RECT  68.353 47.496 69.084 47.568 ;
     RECT  68.353 47.568 69.036 47.592 ;
     RECT  68.353 47.592 69.084 47.664 ;
     RECT  68.353 47.664 69.036 47.688 ;
     RECT  68.353 47.688 69.084 47.76 ;
     RECT  68.353 47.76 69.036 47.784 ;
     RECT  68.353 47.784 69.084 47.856 ;
     RECT  68.353 47.856 69.036 47.88 ;
     RECT  68.353 47.88 69.084 47.952 ;
     RECT  68.353 47.952 69.036 47.976 ;
     RECT  68.353 47.976 69.084 48.048 ;
     RECT  68.353 48.048 69.036 48.072 ;
     RECT  68.353 48.072 69.084 48.144 ;
     RECT  68.353 48.144 69.036 48.168 ;
     RECT  68.353 48.168 69.084 48.24 ;
     RECT  68.353 48.24 69.036 48.264 ;
     RECT  68.353 48.264 69.084 48.336 ;
     RECT  68.353 48.336 69.036 48.36 ;
     RECT  68.353 48.36 69.084 48.432 ;
     RECT  68.353 48.432 69.036 48.456 ;
     RECT  68.353 48.456 69.084 48.528 ;
     RECT  68.353 48.528 69.036 48.552 ;
     RECT  68.353 48.552 69.084 48.624 ;
     RECT  68.353 48.624 69.036 48.648 ;
     RECT  68.353 48.648 69.084 48.72 ;
     RECT  68.353 48.72 69.036 48.744 ;
     RECT  68.353 48.744 69.084 48.816 ;
     RECT  68.353 48.816 69.036 48.84 ;
     RECT  68.353 48.84 69.084 48.912 ;
     RECT  68.353 48.912 69.036 48.936 ;
     RECT  68.353 48.936 69.084 49.008 ;
     RECT  68.353 49.008 69.036 49.032 ;
     RECT  68.353 49.032 69.084 49.104 ;
     RECT  68.353 49.104 69.036 49.128 ;
     RECT  68.353 49.128 69.084 49.2 ;
     RECT  68.353 49.2 69.036 49.224 ;
     RECT  68.353 49.224 69.084 49.296 ;
     RECT  68.353 49.296 69.036 49.32 ;
     RECT  68.353 49.32 69.084 49.392 ;
     RECT  68.353 49.392 69.036 49.416 ;
     RECT  68.353 49.416 69.084 49.488 ;
     RECT  68.353 49.488 69.036 49.512 ;
     RECT  68.353 49.512 69.084 49.584 ;
     RECT  68.353 49.584 69.036 49.608 ;
     RECT  68.353 49.608 69.084 49.68 ;
     RECT  68.353 49.68 69.036 49.704 ;
     RECT  68.353 49.704 69.084 49.776 ;
     RECT  68.353 49.776 69.036 49.8 ;
     RECT  68.353 49.8 69.084 49.872 ;
     RECT  68.353 49.872 69.036 49.896 ;
     RECT  68.353 49.896 69.084 49.968 ;
     RECT  68.353 49.968 69.036 49.992 ;
     RECT  68.353 49.992 69.084 50.064 ;
     RECT  68.353 50.064 69.036 50.088 ;
     RECT  68.353 50.088 69.084 50.16 ;
     RECT  68.353 50.16 69.036 50.184 ;
     RECT  68.353 50.184 69.084 50.256 ;
     RECT  68.353 50.256 69.036 50.28 ;
     RECT  68.353 50.28 69.084 50.352 ;
     RECT  68.353 50.352 69.036 50.376 ;
     RECT  68.353 50.376 69.084 50.448 ;
     RECT  68.353 50.448 69.036 50.472 ;
     RECT  68.353 50.472 69.084 50.544 ;
     RECT  68.353 50.544 69.036 50.568 ;
     RECT  68.353 50.568 69.084 50.64 ;
     RECT  68.353 50.64 69.036 50.664 ;
     RECT  68.353 50.664 69.084 50.736 ;
     RECT  68.353 50.736 69.036 50.76 ;
     RECT  68.353 50.76 69.084 50.832 ;
     RECT  68.353 50.832 69.036 50.856 ;
     RECT  68.353 50.856 69.084 50.928 ;
     RECT  68.353 50.928 69.036 50.952 ;
     RECT  68.353 50.952 69.084 51.024 ;
     RECT  68.353 51.024 69.036 51.048 ;
     RECT  68.353 51.048 69.084 51.12 ;
     RECT  68.353 51.12 69.036 51.144 ;
     RECT  68.353 51.144 69.084 51.216 ;
     RECT  68.353 51.216 69.036 51.24 ;
     RECT  68.353 51.24 69.084 51.312 ;
     RECT  68.353 51.312 69.036 51.336 ;
    LAYER M5 ;
     RECT  39.144 0.016 39.216 0.084 ;
     RECT  39.24 0.016 39.312 0.084 ;
     RECT  39.336 0.016 39.408 0.084 ;
     RECT  39.432 0.016 39.504 0.084 ;
     RECT  39.528 0.016 39.6 0.084 ;
     RECT  39.624 0.016 39.696 0.084 ;
     RECT  39.72 0.016 39.792 0.084 ;
     RECT  39.816 0.016 39.888 0.084 ;
     RECT  39.912 0.016 39.984 0.084 ;
     RECT  40.008 0.016 40.08 0.084 ;
     RECT  40.104 0.016 40.176 0.084 ;
     RECT  40.2 0.016 40.272 0.084 ;
     RECT  40.296 0.016 40.368 0.084 ;
     RECT  40.392 0.016 40.464 0.084 ;
     RECT  40.488 0.016 40.56 0.084 ;
     RECT  40.584 0.016 40.656 0.084 ;
     RECT  40.68 0.016 40.752 0.084 ;
     RECT  40.776 0.016 40.848 0.084 ;
     RECT  40.872 0.016 40.944 0.084 ;
     RECT  40.968 0.016 41.04 0.084 ;
     RECT  41.064 0.016 41.136 0.084 ;
     RECT  41.16 0.016 41.232 0.084 ;
     RECT  41.256 0.016 41.328 0.084 ;
     RECT  41.352 0.016 41.424 0.084 ;
     RECT  41.448 0.016 41.52 0.084 ;
     RECT  41.544 0.016 42.192 0.084 ;
     RECT  42.216 0.016 42.288 0.084 ;
     RECT  42.312 0.016 42.384 0.084 ;
     RECT  42.408 0.016 42.48 0.084 ;
     RECT  42.504 0.016 42.576 0.084 ;
     RECT  42.6 0.016 42.672 0.084 ;
     RECT  42.696 0.016 42.768 0.084 ;
     RECT  42.792 0.016 42.864 0.084 ;
     RECT  42.888 0.016 42.96 0.084 ;
     RECT  42.984 0.016 43.056 0.084 ;
     RECT  43.08 0.016 43.152 0.084 ;
     RECT  43.176 0.016 43.248 0.084 ;
     RECT  43.272 0.016 43.344 0.084 ;
     RECT  43.368 0.016 43.44 0.084 ;
     RECT  43.464 0.016 43.536 0.084 ;
     RECT  43.56 0.016 43.632 0.084 ;
     RECT  43.656 0.016 43.728 0.084 ;
     RECT  43.752 0.016 43.824 0.084 ;
     RECT  43.848 0.016 43.92 0.084 ;
     RECT  43.944 0.016 44.016 0.084 ;
     RECT  44.04 0.016 44.112 0.084 ;
     RECT  44.136 0.016 44.208 0.084 ;
     RECT  44.232 0.016 44.304 0.084 ;
     RECT  44.328 0.016 44.4 0.084 ;
     RECT  44.424 0.016 44.496 0.084 ;
     RECT  44.52 0.016 44.592 0.084 ;
     RECT  44.616 0.016 44.688 0.084 ;
     RECT  44.712 0.016 44.784 0.084 ;
     RECT  44.808 0.016 44.88 0.084 ;
     RECT  44.904 0.016 44.976 0.084 ;
     RECT  45 0.016 45.072 0.084 ;
     RECT  45.096 0.016 45.168 0.084 ;
     RECT  45.192 0.016 45.264 0.084 ;
     RECT  45.288 0.016 45.36 0.084 ;
     RECT  45.384 0.016 45.456 0.084 ;
     RECT  45.48 0.016 45.552 0.084 ;
     RECT  45.576 0.016 45.648 0.084 ;
     RECT  45.672 0.016 45.744 0.084 ;
     RECT  45.768 0.016 45.84 0.084 ;
     RECT  45.864 0.016 45.936 0.084 ;
     RECT  45.96 0.016 46.032 0.084 ;
     RECT  46.056 0.016 46.128 0.084 ;
     RECT  46.152 0.016 46.224 0.084 ;
     RECT  46.248 0.016 46.32 0.084 ;
     RECT  46.344 0.016 46.416 0.084 ;
     RECT  46.44 0.016 46.512 0.084 ;
     RECT  46.536 0.016 46.608 0.084 ;
     RECT  46.632 0.016 46.704 0.084 ;
     RECT  46.728 0.016 46.8 0.084 ;
     RECT  46.824 0.016 46.896 0.084 ;
     RECT  46.92 0.016 46.992 0.084 ;
     RECT  47.016 0.016 47.088 0.084 ;
     RECT  47.112 0.016 47.184 0.084 ;
     RECT  47.208 0.016 47.28 0.084 ;
     RECT  47.304 0.016 47.376 0.084 ;
     RECT  47.4 0.016 47.472 0.084 ;
     RECT  47.496 0.016 47.568 0.084 ;
     RECT  47.592 0.016 47.664 0.084 ;
     RECT  47.688 0.016 47.76 0.084 ;
     RECT  47.784 0.016 47.856 0.084 ;
     RECT  47.88 0.016 47.952 0.084 ;
     RECT  47.976 0.016 48.048 0.084 ;
     RECT  48.072 0.016 48.144 0.084 ;
     RECT  48.168 0.016 48.24 0.084 ;
     RECT  48.264 0.016 48.336 0.084 ;
     RECT  48.36 0.016 48.432 0.084 ;
     RECT  48.456 0.016 48.528 0.084 ;
     RECT  48.552 0.016 48.624 0.084 ;
     RECT  48.648 0.016 48.72 0.084 ;
     RECT  48.744 0.016 48.816 0.084 ;
     RECT  48.84 0.016 48.912 0.084 ;
     RECT  48.936 0.016 49.008 0.084 ;
     RECT  49.032 0.016 49.104 0.084 ;
     RECT  49.128 0.016 49.2 0.084 ;
     RECT  49.224 0.016 49.296 0.084 ;
     RECT  49.32 0.016 49.392 0.084 ;
     RECT  49.416 0.016 49.488 0.084 ;
     RECT  49.512 0.016 49.584 0.084 ;
     RECT  49.608 0.016 49.68 0.084 ;
     RECT  49.704 0.016 49.776 0.084 ;
     RECT  49.8 0.016 49.872 0.084 ;
     RECT  49.896 0.016 49.968 0.084 ;
     RECT  49.992 0.016 50.064 0.084 ;
     RECT  50.088 0.016 50.16 0.084 ;
     RECT  50.184 0.016 50.256 0.084 ;
     RECT  50.28 0.016 50.352 0.084 ;
     RECT  50.376 0.016 50.448 0.084 ;
     RECT  50.472 0.016 50.544 0.084 ;
     RECT  50.568 0.016 50.64 0.084 ;
     RECT  50.664 0.016 50.736 0.084 ;
     RECT  50.76 0.016 50.832 0.084 ;
     RECT  50.856 0.016 50.928 0.084 ;
     RECT  50.952 0.016 51.024 0.084 ;
     RECT  51.048 0.016 51.12 0.084 ;
     RECT  51.144 0.016 51.216 0.084 ;
     RECT  51.24 0.016 51.312 0.084 ;
     RECT  39.12 0.084 51.336 0.133 ;
     RECT  2.4 2.137 2.52 2.151 ;
     RECT  7.8 2.137 7.92 2.151 ;
     RECT  13.2 2.137 13.32 2.151 ;
     RECT  18.6 2.137 18.72 2.151 ;
     RECT  24 2.137 24.12 2.151 ;
     RECT  29.4 2.137 29.52 2.151 ;
     RECT  34.8 2.137 34.92 2.151 ;
     RECT  56.4 2.137 56.52 2.151 ;
     RECT  61.8 2.137 61.92 2.151 ;
     RECT  39.12 0.133 51.432 2.291 ;
     RECT  39.696 2.291 41.16 4.019 ;
     RECT  39.792 4.019 41.16 4.067 ;
     RECT  34.8 2.151 35.112 4.117 ;
     RECT  40.2 4.067 41.16 5.123 ;
     RECT  42.288 2.291 51.432 5.125 ;
     RECT  42.288 5.125 52.008 5.653 ;
     RECT  42.288 5.653 52.152 5.987 ;
     RECT  43.728 5.987 52.152 6.323 ;
     RECT  43.728 6.323 49.128 6.659 ;
     RECT  50.112 6.323 52.152 6.755 ;
     RECT  40.2 5.123 40.968 6.805 ;
     RECT  42.288 5.987 42.696 6.805 ;
     RECT  34.8 4.117 35.64 7.381 ;
     RECT  40.2 6.805 42.696 7.475 ;
     RECT  43.728 6.659 48.456 7.475 ;
     RECT  40.2 7.475 42.504 7.523 ;
     RECT  43.824 7.475 48.456 7.523 ;
     RECT  40.2 7.523 42.312 7.715 ;
     RECT  40.2 7.715 41.448 8.003 ;
     RECT  43.92 7.523 48.456 8.051 ;
     RECT  45.6 8.051 48.456 8.531 ;
     RECT  43.92 8.051 43.944 8.579 ;
     RECT  45.6 8.531 47.736 8.579 ;
     RECT  47.712 8.579 47.736 9.299 ;
     RECT  34.8 7.381 36.456 10.307 ;
     RECT  7.8 2.151 8.112 18.661 ;
     RECT  4.32 18.661 4.344 19.331 ;
     RECT  7.8 18.661 8.232 20.003 ;
     RECT  61.8 2.151 62.112 21.061 ;
     RECT  7.8 20.003 8.112 21.541 ;
     RECT  61.008 21.061 62.112 22.451 ;
     RECT  2.4 2.151 2.712 22.789 ;
     RECT  4.56 21.013 4.584 22.835 ;
     RECT  51 6.755 52.152 22.835 ;
     RECT  34.8 10.307 35.64 23.075 ;
     RECT  2.4 22.789 3.288 23.555 ;
     RECT  63.84 22.693 63.864 23.603 ;
     RECT  4.512 24.085 4.536 24.419 ;
     RECT  2.4 23.555 2.712 25.093 ;
     RECT  0.144 25.765 0.168 25.955 ;
     RECT  2.4 25.093 2.904 25.955 ;
     RECT  7.488 21.541 8.112 25.957 ;
     RECT  7.44 25.957 8.112 26.725 ;
     RECT  2.4 25.955 2.712 27.157 ;
     RECT  2.304 27.157 2.712 27.347 ;
     RECT  5.76 26.677 5.784 27.395 ;
     RECT  6.912 26.725 8.112 28.115 ;
     RECT  64.512 28.261 64.536 28.979 ;
     RECT  7.44 28.115 8.112 29.029 ;
     RECT  7.44 29.029 8.232 30.035 ;
     RECT  0.288 30.757 0.312 30.899 ;
     RECT  0.192 30.949 0.216 31.139 ;
     RECT  4.368 29.365 4.392 31.237 ;
     RECT  7.44 30.035 8.112 31.379 ;
     RECT  61.104 22.451 62.112 31.379 ;
     RECT  65.28 30.709 65.304 31.379 ;
     RECT  4.368 31.237 5.352 32.339 ;
     RECT  36.384 32.293 36.408 32.483 ;
     RECT  4.368 32.339 4.392 32.579 ;
     RECT  29.4 2.151 29.712 33.493 ;
     RECT  29.28 33.493 29.712 33.635 ;
     RECT  63.504 32.437 63.528 34.165 ;
     RECT  2.4 27.347 2.712 34.453 ;
     RECT  2.304 34.453 2.712 34.643 ;
     RECT  18.6 2.151 18.912 34.933 ;
     RECT  63.504 34.165 63.576 35.939 ;
     RECT  7.8 31.379 8.112 36.421 ;
     RECT  4.512 35.125 4.536 36.515 ;
     RECT  63.504 35.939 63.528 37.091 ;
     RECT  2.4 34.643 2.712 37.429 ;
     RECT  2.304 37.429 2.712 37.667 ;
     RECT  7.488 36.421 8.112 37.667 ;
     RECT  61.8 31.379 62.112 37.957 ;
     RECT  61.8 37.957 62.232 38.579 ;
     RECT  0.192 38.965 0.216 39.251 ;
     RECT  65.136 38.725 65.16 39.443 ;
     RECT  60.144 39.253 60.168 39.493 ;
     RECT  60.144 39.493 60.552 39.923 ;
     RECT  26.688 40.453 26.712 40.691 ;
     RECT  60.528 39.923 60.552 42.613 ;
     RECT  59.616 42.613 60.552 42.755 ;
     RECT  64.944 42.133 64.968 42.803 ;
     RECT  59.856 42.755 60.552 42.851 ;
     RECT  63.84 42.661 63.864 42.995 ;
     RECT  5.664 42.997 5.688 43.139 ;
     RECT  7.536 37.667 8.112 43.139 ;
     RECT  2.4 37.667 2.712 43.573 ;
     RECT  44.544 44.437 44.568 44.675 ;
     RECT  2.4 43.573 3.48 45.011 ;
     RECT  60.528 42.851 60.552 45.013 ;
     RECT  61.8 38.579 62.112 45.013 ;
     RECT  60.528 45.013 62.112 45.059 ;
     RECT  5.856 44.965 5.88 45.683 ;
     RECT  0.144 45.781 0.168 46.067 ;
     RECT  4.464 42.133 4.488 46.165 ;
     RECT  4.464 46.165 4.92 46.211 ;
     RECT  7.68 43.139 8.112 46.547 ;
     RECT  2.4 45.011 2.712 47.605 ;
     RECT  2.064 47.605 2.712 47.795 ;
     RECT  7.8 46.547 8.112 48.805 ;
     RECT  7.68 48.805 8.112 48.901 ;
     RECT  4.896 46.211 4.92 49.091 ;
     RECT  7.68 48.901 8.52 49.619 ;
     RECT  7.68 49.619 8.112 49.811 ;
     RECT  45.6 8.579 45.912 49.813 ;
     RECT  60.96 45.059 62.112 49.859 ;
     RECT  64.608 49.477 64.632 51.923 ;
     RECT  34.8 23.075 35.256 52.547 ;
     RECT  24 2.151 24.312 62.341 ;
     RECT  40.2 8.003 40.512 62.437 ;
     RECT  28.032 33.013 28.056 62.581 ;
     RECT  38.4 62.293 38.424 62.629 ;
     RECT  44.688 49.813 45.912 62.629 ;
     RECT  26.736 62.581 26.76 62.773 ;
     RECT  28.032 62.581 28.2 62.773 ;
     RECT  24 62.341 24.936 62.821 ;
     RECT  26.736 62.773 28.2 62.821 ;
     RECT  29.4 33.635 29.712 62.821 ;
     RECT  34.8 52.547 35.112 62.821 ;
     RECT  44.448 62.629 45.912 62.821 ;
     RECT  22.992 62.821 23.016 63.013 ;
     RECT  22.176 63.013 23.016 63.061 ;
     RECT  24 62.821 29.712 63.061 ;
     RECT  18.6 34.933 19.752 63.109 ;
     RECT  22.176 63.061 29.712 63.109 ;
     RECT  38.4 62.629 38.616 63.109 ;
     RECT  44.064 62.821 45.912 63.109 ;
     RECT  39.696 62.437 40.512 63.157 ;
     RECT  43.728 63.109 46.536 63.157 ;
     RECT  47.808 63.109 47.832 63.157 ;
     RECT  18.6 63.109 21.096 63.205 ;
     RECT  22.128 63.109 29.712 63.205 ;
     RECT  37.392 63.109 38.616 63.205 ;
     RECT  39.6 63.157 40.512 63.205 ;
     RECT  18.432 63.205 21.096 63.253 ;
     RECT  22.08 63.205 29.712 63.253 ;
     RECT  37.104 63.205 40.872 63.253 ;
     RECT  18.432 63.253 29.712 63.637 ;
     RECT  34.8 62.821 35.208 63.637 ;
     RECT  37.104 63.253 40.968 63.637 ;
     RECT  34.8 63.637 35.304 63.781 ;
     RECT  43.728 63.157 47.832 63.781 ;
     RECT  18.432 63.637 29.928 63.827 ;
     RECT  18.6 63.827 29.928 63.829 ;
     RECT  31.2 63.205 31.224 63.829 ;
     RECT  34.8 63.781 35.496 63.829 ;
     RECT  36.72 63.637 40.968 63.829 ;
     RECT  33.456 62.821 33.48 64.309 ;
     RECT  42.672 64.357 42.696 65.701 ;
     RECT  32.688 64.309 33.48 66.133 ;
     RECT  18.6 63.829 31.224 66.709 ;
     RECT  32.592 66.133 33.48 66.709 ;
     RECT  34.8 63.829 40.968 66.709 ;
     RECT  42.576 65.701 42.696 66.709 ;
     RECT  43.728 63.781 48.36 66.709 ;
     RECT  17.904 66.709 48.552 66.805 ;
     RECT  2.4 47.795 2.712 66.969 ;
     RECT  7.8 49.811 8.112 66.969 ;
     RECT  13.2 2.151 13.512 66.969 ;
     RECT  51 22.835 51.312 66.969 ;
     RECT  56.4 2.151 56.712 66.969 ;
     RECT  61.8 49.859 62.112 66.969 ;
     RECT  2.4 66.969 2.52 66.983 ;
     RECT  7.8 66.969 7.92 66.983 ;
     RECT  13.2 66.969 13.32 66.983 ;
     RECT  51 66.969 51.12 66.983 ;
     RECT  56.4 66.969 56.52 66.983 ;
     RECT  61.8 66.969 61.92 66.983 ;
     RECT  17.904 66.805 48.936 67.237 ;
     RECT  17.712 67.237 49.128 69.036 ;
     RECT  17.736 69.036 17.808 69.072 ;
     RECT  17.832 69.036 17.904 69.072 ;
     RECT  17.928 69.036 18 69.072 ;
     RECT  18.024 69.036 18.096 69.072 ;
     RECT  18.12 69.036 18.192 69.072 ;
     RECT  18.216 69.036 18.288 69.072 ;
     RECT  18.312 69.036 18.384 69.072 ;
     RECT  18.408 69.036 18.48 69.072 ;
     RECT  18.504 69.036 18.576 69.072 ;
     RECT  18.6 69.036 18.672 69.072 ;
     RECT  18.696 69.036 18.768 69.072 ;
     RECT  18.792 69.036 18.864 69.072 ;
     RECT  18.888 69.036 18.96 69.072 ;
     RECT  18.984 69.036 19.056 69.072 ;
     RECT  19.08 69.036 19.152 69.072 ;
     RECT  19.176 69.036 19.248 69.072 ;
     RECT  19.272 69.036 19.344 69.072 ;
     RECT  19.368 69.036 19.44 69.072 ;
     RECT  19.464 69.036 19.536 69.072 ;
     RECT  19.56 69.036 19.632 69.072 ;
     RECT  19.656 69.036 19.728 69.072 ;
     RECT  19.752 69.036 19.824 69.072 ;
     RECT  19.848 69.036 19.92 69.072 ;
     RECT  19.944 69.036 20.016 69.072 ;
     RECT  20.04 69.036 20.112 69.072 ;
     RECT  20.136 69.036 20.208 69.072 ;
     RECT  20.232 69.036 20.304 69.072 ;
     RECT  20.328 69.036 20.4 69.072 ;
     RECT  20.424 69.036 20.496 69.072 ;
     RECT  20.52 69.036 20.592 69.072 ;
     RECT  20.616 69.036 20.688 69.072 ;
     RECT  20.712 69.036 20.784 69.072 ;
     RECT  20.808 69.036 20.88 69.072 ;
     RECT  20.904 69.036 20.976 69.072 ;
     RECT  21 69.036 21.072 69.072 ;
     RECT  21.096 69.036 21.168 69.072 ;
     RECT  21.192 69.036 21.264 69.072 ;
     RECT  21.288 69.036 21.36 69.072 ;
     RECT  21.384 69.036 21.456 69.072 ;
     RECT  21.48 69.036 21.552 69.072 ;
     RECT  21.576 69.036 21.648 69.072 ;
     RECT  21.672 69.036 21.744 69.072 ;
     RECT  21.768 69.036 21.84 69.072 ;
     RECT  21.864 69.036 21.936 69.072 ;
     RECT  21.96 69.036 22.032 69.072 ;
     RECT  22.056 69.036 22.128 69.072 ;
     RECT  22.152 69.036 22.224 69.072 ;
     RECT  22.248 69.036 22.32 69.072 ;
     RECT  22.344 69.036 22.416 69.072 ;
     RECT  22.44 69.036 22.512 69.072 ;
     RECT  22.536 69.036 22.608 69.072 ;
     RECT  22.632 69.036 22.704 69.072 ;
     RECT  22.728 69.036 22.8 69.072 ;
     RECT  22.824 69.036 22.896 69.072 ;
     RECT  22.92 69.036 22.992 69.072 ;
     RECT  23.016 69.036 23.088 69.072 ;
     RECT  23.112 69.036 23.184 69.072 ;
     RECT  23.208 69.036 23.28 69.072 ;
     RECT  23.304 69.036 23.376 69.072 ;
     RECT  23.4 69.036 23.472 69.072 ;
     RECT  23.496 69.036 23.568 69.072 ;
     RECT  23.592 69.036 23.664 69.072 ;
     RECT  23.688 69.036 23.76 69.072 ;
     RECT  23.784 69.036 23.856 69.072 ;
     RECT  23.88 69.036 23.952 69.072 ;
     RECT  23.976 69.036 24.048 69.072 ;
     RECT  24.072 69.036 24.144 69.072 ;
     RECT  24.168 69.036 24.24 69.072 ;
     RECT  24.264 69.036 24.336 69.072 ;
     RECT  24.36 69.036 24.432 69.072 ;
     RECT  24.456 69.036 24.528 69.072 ;
     RECT  24.552 69.036 24.624 69.072 ;
     RECT  24.648 69.036 24.72 69.072 ;
     RECT  24.744 69.036 24.816 69.072 ;
     RECT  24.84 69.036 24.912 69.072 ;
     RECT  24.936 69.036 25.008 69.072 ;
     RECT  25.032 69.036 25.104 69.072 ;
     RECT  25.128 69.036 25.2 69.072 ;
     RECT  25.224 69.036 25.296 69.072 ;
     RECT  25.32 69.036 25.392 69.072 ;
     RECT  25.416 69.036 25.488 69.072 ;
     RECT  25.512 69.036 25.584 69.072 ;
     RECT  25.608 69.036 25.68 69.072 ;
     RECT  25.704 69.036 25.776 69.072 ;
     RECT  25.8 69.036 25.872 69.072 ;
     RECT  25.896 69.036 25.968 69.072 ;
     RECT  25.992 69.036 26.064 69.072 ;
     RECT  26.088 69.036 26.16 69.072 ;
     RECT  26.184 69.036 26.256 69.072 ;
     RECT  26.28 69.036 26.352 69.072 ;
     RECT  26.376 69.036 26.448 69.072 ;
     RECT  26.472 69.036 26.544 69.072 ;
     RECT  26.568 69.036 26.64 69.072 ;
     RECT  26.664 69.036 26.736 69.072 ;
     RECT  26.76 69.036 26.832 69.072 ;
     RECT  26.856 69.036 26.928 69.072 ;
     RECT  26.952 69.036 27.024 69.072 ;
     RECT  27.048 69.036 27.12 69.072 ;
     RECT  27.144 69.036 27.216 69.072 ;
     RECT  27.24 69.036 27.312 69.072 ;
     RECT  27.336 69.036 27.408 69.072 ;
     RECT  27.432 69.036 27.504 69.072 ;
     RECT  27.528 69.036 27.6 69.072 ;
     RECT  27.624 69.036 27.696 69.072 ;
     RECT  27.72 69.036 27.792 69.072 ;
     RECT  27.816 69.036 27.888 69.072 ;
     RECT  27.912 69.036 27.984 69.072 ;
     RECT  28.008 69.036 28.08 69.072 ;
     RECT  28.104 69.036 28.176 69.072 ;
     RECT  28.2 69.036 28.272 69.072 ;
     RECT  28.296 69.036 28.368 69.072 ;
     RECT  28.392 69.036 28.464 69.072 ;
     RECT  28.488 69.036 28.56 69.072 ;
     RECT  28.584 69.036 28.656 69.072 ;
     RECT  28.68 69.036 28.752 69.072 ;
     RECT  28.776 69.036 28.848 69.072 ;
     RECT  28.872 69.036 28.944 69.072 ;
     RECT  28.968 69.036 29.04 69.072 ;
     RECT  29.064 69.036 29.136 69.072 ;
     RECT  29.16 69.036 29.232 69.072 ;
     RECT  29.256 69.036 29.328 69.072 ;
     RECT  29.352 69.036 29.424 69.072 ;
     RECT  29.448 69.036 29.52 69.072 ;
     RECT  29.544 69.036 29.616 69.072 ;
     RECT  29.64 69.036 29.712 69.072 ;
     RECT  29.736 69.036 29.808 69.072 ;
     RECT  29.832 69.036 29.904 69.072 ;
     RECT  29.928 69.036 30.576 69.072 ;
     RECT  30.6 69.036 30.672 69.072 ;
     RECT  30.696 69.036 30.768 69.072 ;
     RECT  30.792 69.036 30.864 69.072 ;
     RECT  30.888 69.036 30.96 69.072 ;
     RECT  30.984 69.036 31.056 69.072 ;
     RECT  31.08 69.036 31.152 69.072 ;
     RECT  31.176 69.036 31.248 69.072 ;
     RECT  31.272 69.036 31.344 69.072 ;
     RECT  31.368 69.036 31.44 69.072 ;
     RECT  31.464 69.036 31.536 69.072 ;
     RECT  31.56 69.036 31.632 69.072 ;
     RECT  31.656 69.036 31.728 69.072 ;
     RECT  31.752 69.036 31.824 69.072 ;
     RECT  31.848 69.036 31.92 69.072 ;
     RECT  31.944 69.036 32.016 69.072 ;
     RECT  32.04 69.036 32.112 69.072 ;
     RECT  32.136 69.036 32.208 69.072 ;
     RECT  32.232 69.036 32.304 69.072 ;
     RECT  32.328 69.036 32.4 69.072 ;
     RECT  32.424 69.036 32.496 69.072 ;
     RECT  32.52 69.036 32.592 69.072 ;
     RECT  32.616 69.036 32.688 69.072 ;
     RECT  32.712 69.036 32.784 69.072 ;
     RECT  32.808 69.036 32.88 69.072 ;
     RECT  32.904 69.036 32.976 69.072 ;
     RECT  33 69.036 33.072 69.072 ;
     RECT  33.096 69.036 33.168 69.072 ;
     RECT  33.192 69.036 33.264 69.072 ;
     RECT  33.288 69.036 33.36 69.072 ;
     RECT  33.384 69.036 33.456 69.072 ;
     RECT  33.48 69.036 33.552 69.072 ;
     RECT  33.576 69.036 33.648 69.072 ;
     RECT  33.672 69.036 33.744 69.072 ;
     RECT  33.768 69.036 33.84 69.072 ;
     RECT  33.864 69.036 33.936 69.072 ;
     RECT  33.96 69.036 34.032 69.072 ;
     RECT  34.056 69.036 34.128 69.072 ;
     RECT  34.152 69.036 34.224 69.072 ;
     RECT  34.248 69.036 34.32 69.072 ;
     RECT  34.344 69.036 34.416 69.072 ;
     RECT  34.44 69.036 34.512 69.072 ;
     RECT  34.536 69.036 34.608 69.072 ;
     RECT  34.632 69.036 34.704 69.072 ;
     RECT  34.728 69.036 34.8 69.072 ;
     RECT  34.824 69.036 34.896 69.072 ;
     RECT  34.92 69.036 34.992 69.072 ;
     RECT  35.016 69.036 35.088 69.072 ;
     RECT  35.112 69.036 35.184 69.072 ;
     RECT  35.208 69.036 35.28 69.072 ;
     RECT  35.304 69.036 35.376 69.072 ;
     RECT  35.4 69.036 35.472 69.072 ;
     RECT  35.496 69.036 35.568 69.072 ;
     RECT  35.592 69.036 35.664 69.072 ;
     RECT  35.688 69.036 35.76 69.072 ;
     RECT  35.784 69.036 35.856 69.072 ;
     RECT  35.88 69.036 35.952 69.072 ;
     RECT  35.976 69.036 36.048 69.072 ;
     RECT  36.072 69.036 36.144 69.072 ;
     RECT  36.168 69.036 36.24 69.072 ;
     RECT  36.264 69.036 36.336 69.072 ;
     RECT  36.36 69.036 36.432 69.072 ;
     RECT  36.456 69.036 36.528 69.072 ;
     RECT  36.552 69.036 36.624 69.072 ;
     RECT  36.648 69.036 36.72 69.072 ;
     RECT  36.744 69.036 36.816 69.072 ;
     RECT  36.84 69.036 36.912 69.072 ;
     RECT  36.936 69.036 37.008 69.072 ;
     RECT  37.032 69.036 37.104 69.072 ;
     RECT  37.128 69.036 37.2 69.072 ;
     RECT  37.224 69.036 37.296 69.072 ;
     RECT  37.32 69.036 37.392 69.072 ;
     RECT  37.416 69.036 37.488 69.072 ;
     RECT  37.512 69.036 37.584 69.072 ;
     RECT  37.608 69.036 37.68 69.072 ;
     RECT  37.704 69.036 37.776 69.072 ;
     RECT  37.8 69.036 37.872 69.072 ;
     RECT  37.896 69.036 37.968 69.072 ;
     RECT  37.992 69.036 38.064 69.072 ;
     RECT  38.088 69.036 38.16 69.072 ;
     RECT  38.184 69.036 38.256 69.072 ;
     RECT  38.28 69.036 38.352 69.072 ;
     RECT  38.376 69.036 38.448 69.072 ;
     RECT  38.472 69.036 38.544 69.072 ;
     RECT  38.568 69.036 38.64 69.072 ;
     RECT  38.664 69.036 38.736 69.072 ;
     RECT  38.76 69.036 38.832 69.072 ;
     RECT  38.856 69.036 38.928 69.072 ;
     RECT  38.952 69.036 39.024 69.072 ;
     RECT  39.048 69.036 39.12 69.072 ;
     RECT  39.144 69.036 39.216 69.072 ;
     RECT  39.24 69.036 39.312 69.072 ;
     RECT  39.336 69.036 39.408 69.072 ;
     RECT  39.432 69.036 39.504 69.072 ;
     RECT  39.528 69.036 39.6 69.072 ;
     RECT  39.624 69.036 39.696 69.072 ;
     RECT  39.72 69.036 39.792 69.072 ;
     RECT  39.816 69.036 39.888 69.072 ;
     RECT  39.912 69.036 39.984 69.072 ;
     RECT  40.008 69.036 40.08 69.072 ;
     RECT  40.104 69.036 40.176 69.072 ;
     RECT  40.2 69.036 40.272 69.072 ;
     RECT  40.296 69.036 40.368 69.072 ;
     RECT  40.392 69.036 40.464 69.072 ;
     RECT  40.488 69.036 40.56 69.072 ;
     RECT  40.584 69.036 40.656 69.072 ;
     RECT  40.68 69.036 40.752 69.072 ;
     RECT  40.776 69.036 40.848 69.072 ;
     RECT  40.872 69.036 40.944 69.072 ;
     RECT  40.968 69.036 41.04 69.072 ;
     RECT  41.064 69.036 41.136 69.072 ;
     RECT  41.16 69.036 41.232 69.072 ;
     RECT  41.256 69.036 41.328 69.072 ;
     RECT  41.352 69.036 41.424 69.072 ;
     RECT  41.448 69.036 41.52 69.072 ;
     RECT  41.544 69.036 41.616 69.072 ;
     RECT  41.64 69.036 41.712 69.072 ;
     RECT  41.736 69.036 41.808 69.072 ;
     RECT  41.832 69.036 41.904 69.072 ;
     RECT  41.928 69.036 42 69.072 ;
     RECT  42.024 69.036 42.096 69.072 ;
     RECT  42.12 69.036 42.192 69.072 ;
     RECT  42.216 69.036 42.288 69.072 ;
     RECT  42.312 69.036 42.384 69.072 ;
     RECT  42.408 69.036 42.48 69.072 ;
     RECT  42.504 69.036 42.576 69.072 ;
     RECT  42.6 69.036 42.672 69.072 ;
     RECT  42.696 69.036 42.768 69.072 ;
     RECT  42.792 69.036 42.864 69.072 ;
     RECT  42.888 69.036 42.96 69.072 ;
     RECT  42.984 69.036 43.056 69.072 ;
     RECT  43.08 69.036 43.152 69.072 ;
     RECT  43.176 69.036 43.248 69.072 ;
     RECT  43.272 69.036 43.344 69.072 ;
     RECT  43.368 69.036 43.44 69.072 ;
     RECT  43.464 69.036 43.536 69.072 ;
     RECT  43.56 69.036 43.632 69.072 ;
     RECT  43.656 69.036 43.728 69.072 ;
     RECT  43.752 69.036 43.824 69.072 ;
     RECT  43.848 69.036 43.92 69.072 ;
     RECT  43.944 69.036 44.016 69.072 ;
     RECT  44.04 69.036 44.112 69.072 ;
     RECT  44.136 69.036 44.208 69.072 ;
     RECT  44.232 69.036 44.304 69.072 ;
     RECT  44.328 69.036 44.4 69.072 ;
     RECT  44.424 69.036 44.496 69.072 ;
     RECT  44.52 69.036 44.592 69.072 ;
     RECT  44.616 69.036 44.688 69.072 ;
     RECT  44.712 69.036 44.784 69.072 ;
     RECT  44.808 69.036 44.88 69.072 ;
     RECT  44.904 69.036 44.976 69.072 ;
     RECT  45 69.036 45.072 69.072 ;
     RECT  45.096 69.036 45.168 69.072 ;
     RECT  45.192 69.036 45.264 69.072 ;
     RECT  45.288 69.036 45.36 69.072 ;
     RECT  45.384 69.036 45.456 69.072 ;
     RECT  45.48 69.036 45.552 69.072 ;
     RECT  45.576 69.036 45.648 69.072 ;
     RECT  45.672 69.036 45.744 69.072 ;
     RECT  45.768 69.036 45.84 69.072 ;
     RECT  45.864 69.036 45.936 69.072 ;
     RECT  45.96 69.036 46.032 69.072 ;
     RECT  46.056 69.036 46.128 69.072 ;
     RECT  46.152 69.036 46.224 69.072 ;
     RECT  46.248 69.036 46.32 69.072 ;
     RECT  46.344 69.036 46.416 69.072 ;
     RECT  46.44 69.036 46.512 69.072 ;
     RECT  46.536 69.036 46.608 69.072 ;
     RECT  46.632 69.036 46.704 69.072 ;
     RECT  46.728 69.036 46.8 69.072 ;
     RECT  46.824 69.036 46.896 69.072 ;
     RECT  46.92 69.036 46.992 69.072 ;
     RECT  47.016 69.036 47.088 69.072 ;
     RECT  47.112 69.036 47.184 69.072 ;
     RECT  47.208 69.036 47.28 69.072 ;
     RECT  47.304 69.036 47.376 69.072 ;
     RECT  47.4 69.036 47.472 69.072 ;
     RECT  47.496 69.036 47.568 69.072 ;
     RECT  47.592 69.036 47.664 69.072 ;
     RECT  47.688 69.036 47.76 69.072 ;
     RECT  47.784 69.036 47.856 69.072 ;
     RECT  47.88 69.036 47.952 69.072 ;
     RECT  47.976 69.036 48.048 69.072 ;
     RECT  48.072 69.036 48.144 69.072 ;
     RECT  48.168 69.036 48.24 69.072 ;
     RECT  48.264 69.036 48.336 69.072 ;
     RECT  48.36 69.036 48.432 69.072 ;
     RECT  48.456 69.036 48.528 69.072 ;
     RECT  48.552 69.036 48.624 69.072 ;
     RECT  48.648 69.036 48.72 69.072 ;
     RECT  48.744 69.036 48.816 69.072 ;
     RECT  48.84 69.036 48.912 69.072 ;
     RECT  48.936 69.036 49.008 69.072 ;
     RECT  49.032 69.036 49.104 69.072 ;
     RECT  41.16 2.291 42.288 5.123 ;
     RECT  40.968 5.123 42.288 6.805 ;
     RECT  42.696 5.987 43.728 7.475 ;
     RECT  49.128 6.323 50.112 6.659 ;
     RECT  42.504 7.475 43.824 7.523 ;
     RECT  3.288 22.789 4.56 22.835 ;
     RECT  3.288 22.835 4.536 23.555 ;
     RECT  4.512 23.555 4.536 24.085 ;
     RECT  5.784 26.725 6.912 27.395 ;
     RECT  35.256 32.293 36.384 32.483 ;
     RECT  62.112 32.437 63.504 37.091 ;
     RECT  28.056 33.013 29.4 33.493 ;
     RECT  28.056 33.493 29.28 33.635 ;
     RECT  28.056 33.635 29.4 62.581 ;
     RECT  62.112 37.091 62.232 37.957 ;
     RECT  60.552 39.493 61.8 45.013 ;
     RECT  26.712 40.453 28.032 40.691 ;
     RECT  63.864 42.661 64.944 42.803 ;
     RECT  4.488 42.997 5.664 43.139 ;
     RECT  3.48 43.573 4.464 45.011 ;
     RECT  44.568 44.437 45.6 44.675 ;
     RECT  4.488 44.965 5.856 45.683 ;
     RECT  4.488 45.683 4.92 46.165 ;
     RECT  38.424 62.437 39.696 62.629 ;
     RECT  26.76 62.581 28.032 62.773 ;
     RECT  28.2 62.581 29.4 62.821 ;
     RECT  38.616 62.629 39.696 63.157 ;
     RECT  23.016 62.821 24 63.061 ;
     RECT  33.48 62.821 34.8 66.709 ;
     RECT  21.096 63.109 22.128 63.205 ;
     RECT  46.536 63.109 47.808 63.157 ;
     RECT  38.616 63.157 39.6 63.205 ;
     RECT  21.096 63.205 22.08 63.253 ;
     RECT  29.712 63.205 31.2 63.637 ;
     RECT  29.928 63.637 31.2 63.829 ;
     RECT  35.304 63.637 36.72 63.781 ;
     RECT  35.496 63.781 36.72 63.829 ;
     RECT  31.224 64.309 32.688 66.133 ;
     RECT  42.696 64.357 43.728 66.709 ;
     RECT  31.224 66.133 32.592 66.709 ;
  END
END ot_hbm_host_cfg_leaf_ne2
END LIBRARY
